VERSION 5.8 ;
BUSBITCHARS "[]" ;
DIVIDERCHAR "/" ;
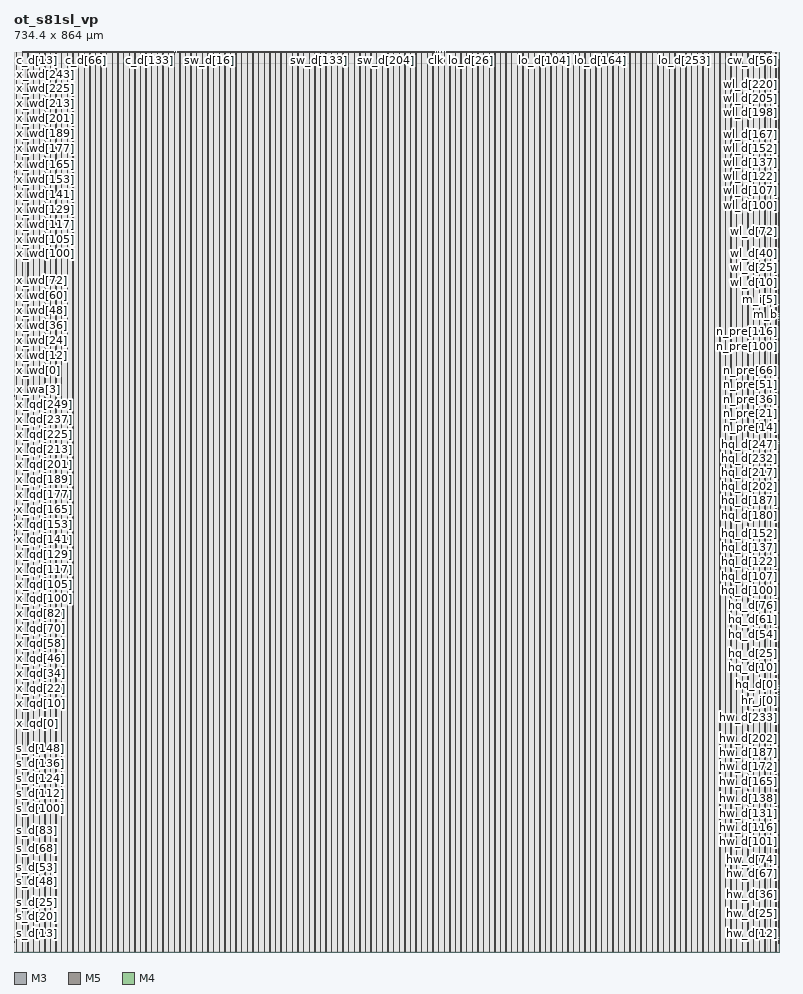
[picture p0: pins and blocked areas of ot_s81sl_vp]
MACRO ot_s81sl_vp
  CLASS BLOCK ;
  ORIGIN 0 0 ;
  FOREIGN ot_s81sl_vp 0 0 ;
  SIZE 734.4 BY 864.0 ;
  SYMMETRY X Y ;
  PIN c_v
    DIRECTION INPUT ;
    USE SIGNAL ;
    PORT
      LAYER M3 ;
        RECT 7.773 863.808 7.797 864.000 ;
    END
  END c_v
  PIN c_d[0]
    DIRECTION INPUT ;
    USE SIGNAL ;
    PORT
      LAYER M5 ;
        RECT 9.552 863.808 9.576 864.000 ;
    END
  END c_d[0]
  PIN c_d[1]
    DIRECTION INPUT ;
    USE SIGNAL ;
    PORT
      LAYER M3 ;
        RECT 10.473 863.808 10.497 864.000 ;
    END
  END c_d[1]
  PIN c_d[2]
    DIRECTION INPUT ;
    USE SIGNAL ;
    PORT
      LAYER M5 ;
        RECT 11.376 863.808 11.400 864.000 ;
    END
  END c_d[2]
  PIN c_d[3]
    DIRECTION INPUT ;
    USE SIGNAL ;
    PORT
      LAYER M3 ;
        RECT 12.273 863.808 12.297 864.000 ;
    END
  END c_d[3]
  PIN c_d[4]
    DIRECTION INPUT ;
    USE SIGNAL ;
    PORT
      LAYER M5 ;
        RECT 13.152 863.808 13.176 864.000 ;
    END
  END c_d[4]
  PIN c_d[5]
    DIRECTION INPUT ;
    USE SIGNAL ;
    PORT
      LAYER M3 ;
        RECT 14.073 863.808 14.097 864.000 ;
    END
  END c_d[5]
  PIN c_d[6]
    DIRECTION INPUT ;
    USE SIGNAL ;
    PORT
      LAYER M5 ;
        RECT 14.976 863.808 15.000 864.000 ;
    END
  END c_d[6]
  PIN c_d[7]
    DIRECTION INPUT ;
    USE SIGNAL ;
    PORT
      LAYER M3 ;
        RECT 15.873 863.808 15.897 864.000 ;
    END
  END c_d[7]
  PIN c_d[8]
    DIRECTION INPUT ;
    USE SIGNAL ;
    PORT
      LAYER M5 ;
        RECT 16.800 863.808 16.824 864.000 ;
    END
  END c_d[8]
  PIN c_d[9]
    DIRECTION INPUT ;
    USE SIGNAL ;
    PORT
      LAYER M3 ;
        RECT 17.673 863.808 17.697 864.000 ;
    END
  END c_d[9]
  PIN c_d[10]
    DIRECTION INPUT ;
    USE SIGNAL ;
    PORT
      LAYER M5 ;
        RECT 18.576 863.808 18.600 864.000 ;
    END
  END c_d[10]
  PIN c_d[11]
    DIRECTION INPUT ;
    USE SIGNAL ;
    PORT
      LAYER M3 ;
        RECT 19.509 863.808 19.533 864.000 ;
    END
  END c_d[11]
  PIN c_d[12]
    DIRECTION INPUT ;
    USE SIGNAL ;
    PORT
      LAYER M5 ;
        RECT 20.400 863.808 20.424 864.000 ;
    END
  END c_d[12]
  PIN c_d[13]
    DIRECTION INPUT ;
    USE SIGNAL ;
    PORT
      LAYER M3 ;
        RECT 21.309 863.808 21.333 864.000 ;
    END
  END c_d[13]
  PIN c_d[14]
    DIRECTION INPUT ;
    USE SIGNAL ;
    PORT
      LAYER M5 ;
        RECT 22.224 863.808 22.248 864.000 ;
    END
  END c_d[14]
  PIN c_d[15]
    DIRECTION INPUT ;
    USE SIGNAL ;
    PORT
      LAYER M3 ;
        RECT 23.109 863.808 23.133 864.000 ;
    END
  END c_d[15]
  PIN c_d[16]
    DIRECTION INPUT ;
    USE SIGNAL ;
    PORT
      LAYER M5 ;
        RECT 24.000 863.808 24.024 864.000 ;
    END
  END c_d[16]
  PIN c_d[17]
    DIRECTION INPUT ;
    USE SIGNAL ;
    PORT
      LAYER M3 ;
        RECT 24.909 863.808 24.933 864.000 ;
    END
  END c_d[17]
  PIN c_d[18]
    DIRECTION INPUT ;
    USE SIGNAL ;
    PORT
      LAYER M5 ;
        RECT 25.824 863.808 25.848 864.000 ;
    END
  END c_d[18]
  PIN c_d[19]
    DIRECTION INPUT ;
    USE SIGNAL ;
    PORT
      LAYER M3 ;
        RECT 26.709 863.808 26.733 864.000 ;
    END
  END c_d[19]
  PIN c_d[20]
    DIRECTION INPUT ;
    USE SIGNAL ;
    PORT
      LAYER M5 ;
        RECT 27.648 863.808 27.672 864.000 ;
    END
  END c_d[20]
  PIN c_d[21]
    DIRECTION INPUT ;
    USE SIGNAL ;
    PORT
      LAYER M3 ;
        RECT 28.545 863.808 28.569 864.000 ;
    END
  END c_d[21]
  PIN c_d[22]
    DIRECTION INPUT ;
    USE SIGNAL ;
    PORT
      LAYER M5 ;
        RECT 29.424 863.808 29.448 864.000 ;
    END
  END c_d[22]
  PIN c_d[23]
    DIRECTION INPUT ;
    USE SIGNAL ;
    PORT
      LAYER M3 ;
        RECT 30.345 863.808 30.369 864.000 ;
    END
  END c_d[23]
  PIN c_d[24]
    DIRECTION INPUT ;
    USE SIGNAL ;
    PORT
      LAYER M5 ;
        RECT 31.248 863.808 31.272 864.000 ;
    END
  END c_d[24]
  PIN c_d[25]
    DIRECTION INPUT ;
    USE SIGNAL ;
    PORT
      LAYER M3 ;
        RECT 32.145 863.808 32.169 864.000 ;
    END
  END c_d[25]
  PIN c_d[26]
    DIRECTION INPUT ;
    USE SIGNAL ;
    PORT
      LAYER M5 ;
        RECT 33.024 863.808 33.048 864.000 ;
    END
  END c_d[26]
  PIN c_d[27]
    DIRECTION INPUT ;
    USE SIGNAL ;
    PORT
      LAYER M3 ;
        RECT 33.945 863.808 33.969 864.000 ;
    END
  END c_d[27]
  PIN c_d[28]
    DIRECTION INPUT ;
    USE SIGNAL ;
    PORT
      LAYER M5 ;
        RECT 34.848 863.808 34.872 864.000 ;
    END
  END c_d[28]
  PIN c_d[29]
    DIRECTION INPUT ;
    USE SIGNAL ;
    PORT
      LAYER M3 ;
        RECT 35.745 863.808 35.769 864.000 ;
    END
  END c_d[29]
  PIN c_d[30]
    DIRECTION INPUT ;
    USE SIGNAL ;
    PORT
      LAYER M5 ;
        RECT 36.672 863.808 36.696 864.000 ;
    END
  END c_d[30]
  PIN c_d[31]
    DIRECTION INPUT ;
    USE SIGNAL ;
    PORT
      LAYER M3 ;
        RECT 37.581 863.808 37.605 864.000 ;
    END
  END c_d[31]
  PIN c_d[32]
    DIRECTION INPUT ;
    USE SIGNAL ;
    PORT
      LAYER M5 ;
        RECT 38.448 863.808 38.472 864.000 ;
    END
  END c_d[32]
  PIN c_d[33]
    DIRECTION INPUT ;
    USE SIGNAL ;
    PORT
      LAYER M3 ;
        RECT 39.381 863.808 39.405 864.000 ;
    END
  END c_d[33]
  PIN c_d[34]
    DIRECTION INPUT ;
    USE SIGNAL ;
    PORT
      LAYER M5 ;
        RECT 40.272 863.808 40.296 864.000 ;
    END
  END c_d[34]
  PIN c_d[35]
    DIRECTION INPUT ;
    USE SIGNAL ;
    PORT
      LAYER M3 ;
        RECT 41.181 863.808 41.205 864.000 ;
    END
  END c_d[35]
  PIN c_d[36]
    DIRECTION INPUT ;
    USE SIGNAL ;
    PORT
      LAYER M5 ;
        RECT 42.096 863.808 42.120 864.000 ;
    END
  END c_d[36]
  PIN c_d[37]
    DIRECTION INPUT ;
    USE SIGNAL ;
    PORT
      LAYER M3 ;
        RECT 42.981 863.808 43.005 864.000 ;
    END
  END c_d[37]
  PIN c_d[38]
    DIRECTION INPUT ;
    USE SIGNAL ;
    PORT
      LAYER M5 ;
        RECT 43.872 863.808 43.896 864.000 ;
    END
  END c_d[38]
  PIN c_d[39]
    DIRECTION INPUT ;
    USE SIGNAL ;
    PORT
      LAYER M3 ;
        RECT 44.781 863.808 44.805 864.000 ;
    END
  END c_d[39]
  PIN c_d[40]
    DIRECTION INPUT ;
    USE SIGNAL ;
    PORT
      LAYER M5 ;
        RECT 45.696 863.808 45.720 864.000 ;
    END
  END c_d[40]
  PIN c_d[41]
    DIRECTION INPUT ;
    USE SIGNAL ;
    PORT
      LAYER M3 ;
        RECT 46.617 863.808 46.641 864.000 ;
    END
  END c_d[41]
  PIN c_d[42]
    DIRECTION INPUT ;
    USE SIGNAL ;
    PORT
      LAYER M5 ;
        RECT 47.520 863.808 47.544 864.000 ;
    END
  END c_d[42]
  PIN c_d[43]
    DIRECTION INPUT ;
    USE SIGNAL ;
    PORT
      LAYER M3 ;
        RECT 48.417 863.808 48.441 864.000 ;
    END
  END c_d[43]
  PIN c_d[44]
    DIRECTION INPUT ;
    USE SIGNAL ;
    PORT
      LAYER M5 ;
        RECT 49.296 863.808 49.320 864.000 ;
    END
  END c_d[44]
  PIN c_d[45]
    DIRECTION INPUT ;
    USE SIGNAL ;
    PORT
      LAYER M3 ;
        RECT 50.217 863.808 50.241 864.000 ;
    END
  END c_d[45]
  PIN c_d[46]
    DIRECTION INPUT ;
    USE SIGNAL ;
    PORT
      LAYER M5 ;
        RECT 51.120 863.808 51.144 864.000 ;
    END
  END c_d[46]
  PIN c_d[47]
    DIRECTION INPUT ;
    USE SIGNAL ;
    PORT
      LAYER M3 ;
        RECT 52.017 863.808 52.041 864.000 ;
    END
  END c_d[47]
  PIN c_d[48]
    DIRECTION INPUT ;
    USE SIGNAL ;
    PORT
      LAYER M5 ;
        RECT 52.944 863.808 52.968 864.000 ;
    END
  END c_d[48]
  PIN c_d[49]
    DIRECTION INPUT ;
    USE SIGNAL ;
    PORT
      LAYER M3 ;
        RECT 53.817 863.808 53.841 864.000 ;
    END
  END c_d[49]
  PIN c_d[50]
    DIRECTION INPUT ;
    USE SIGNAL ;
    PORT
      LAYER M5 ;
        RECT 54.720 863.808 54.744 864.000 ;
    END
  END c_d[50]
  PIN c_d[51]
    DIRECTION INPUT ;
    USE SIGNAL ;
    PORT
      LAYER M3 ;
        RECT 55.653 863.808 55.677 864.000 ;
    END
  END c_d[51]
  PIN c_d[52]
    DIRECTION INPUT ;
    USE SIGNAL ;
    PORT
      LAYER M5 ;
        RECT 56.544 863.808 56.568 864.000 ;
    END
  END c_d[52]
  PIN c_d[53]
    DIRECTION INPUT ;
    USE SIGNAL ;
    PORT
      LAYER M3 ;
        RECT 57.453 863.808 57.477 864.000 ;
    END
  END c_d[53]
  PIN c_d[54]
    DIRECTION INPUT ;
    USE SIGNAL ;
    PORT
      LAYER M5 ;
        RECT 58.368 863.808 58.392 864.000 ;
    END
  END c_d[54]
  PIN c_d[55]
    DIRECTION INPUT ;
    USE SIGNAL ;
    PORT
      LAYER M3 ;
        RECT 59.253 863.808 59.277 864.000 ;
    END
  END c_d[55]
  PIN c_d[56]
    DIRECTION INPUT ;
    USE SIGNAL ;
    PORT
      LAYER M5 ;
        RECT 60.144 863.808 60.168 864.000 ;
    END
  END c_d[56]
  PIN c_d[57]
    DIRECTION INPUT ;
    USE SIGNAL ;
    PORT
      LAYER M3 ;
        RECT 61.053 863.808 61.077 864.000 ;
    END
  END c_d[57]
  PIN c_d[58]
    DIRECTION INPUT ;
    USE SIGNAL ;
    PORT
      LAYER M5 ;
        RECT 61.968 863.808 61.992 864.000 ;
    END
  END c_d[58]
  PIN c_d[59]
    DIRECTION INPUT ;
    USE SIGNAL ;
    PORT
      LAYER M3 ;
        RECT 62.853 863.808 62.877 864.000 ;
    END
  END c_d[59]
  PIN c_d[60]
    DIRECTION INPUT ;
    USE SIGNAL ;
    PORT
      LAYER M5 ;
        RECT 63.792 863.808 63.816 864.000 ;
    END
  END c_d[60]
  PIN c_d[61]
    DIRECTION INPUT ;
    USE SIGNAL ;
    PORT
      LAYER M3 ;
        RECT 64.689 863.808 64.713 864.000 ;
    END
  END c_d[61]
  PIN c_d[62]
    DIRECTION INPUT ;
    USE SIGNAL ;
    PORT
      LAYER M5 ;
        RECT 65.568 863.808 65.592 864.000 ;
    END
  END c_d[62]
  PIN c_d[63]
    DIRECTION INPUT ;
    USE SIGNAL ;
    PORT
      LAYER M3 ;
        RECT 66.489 863.808 66.513 864.000 ;
    END
  END c_d[63]
  PIN c_d[64]
    DIRECTION INPUT ;
    USE SIGNAL ;
    PORT
      LAYER M5 ;
        RECT 67.392 863.808 67.416 864.000 ;
    END
  END c_d[64]
  PIN c_d[65]
    DIRECTION INPUT ;
    USE SIGNAL ;
    PORT
      LAYER M3 ;
        RECT 68.289 863.808 68.313 864.000 ;
    END
  END c_d[65]
  PIN c_d[66]
    DIRECTION INPUT ;
    USE SIGNAL ;
    PORT
      LAYER M5 ;
        RECT 69.168 863.808 69.192 864.000 ;
    END
  END c_d[66]
  PIN c_d[67]
    DIRECTION INPUT ;
    USE SIGNAL ;
    PORT
      LAYER M3 ;
        RECT 70.089 863.808 70.113 864.000 ;
    END
  END c_d[67]
  PIN c_d[68]
    DIRECTION INPUT ;
    USE SIGNAL ;
    PORT
      LAYER M5 ;
        RECT 70.992 863.808 71.016 864.000 ;
    END
  END c_d[68]
  PIN c_d[69]
    DIRECTION INPUT ;
    USE SIGNAL ;
    PORT
      LAYER M3 ;
        RECT 71.889 863.808 71.913 864.000 ;
    END
  END c_d[69]
  PIN c_d[70]
    DIRECTION INPUT ;
    USE SIGNAL ;
    PORT
      LAYER M5 ;
        RECT 72.816 863.808 72.840 864.000 ;
    END
  END c_d[70]
  PIN c_d[71]
    DIRECTION INPUT ;
    USE SIGNAL ;
    PORT
      LAYER M3 ;
        RECT 73.725 863.808 73.749 864.000 ;
    END
  END c_d[71]
  PIN c_d[72]
    DIRECTION INPUT ;
    USE SIGNAL ;
    PORT
      LAYER M5 ;
        RECT 74.592 863.808 74.616 864.000 ;
    END
  END c_d[72]
  PIN c_d[73]
    DIRECTION INPUT ;
    USE SIGNAL ;
    PORT
      LAYER M3 ;
        RECT 75.525 863.808 75.549 864.000 ;
    END
  END c_d[73]
  PIN c_d[74]
    DIRECTION INPUT ;
    USE SIGNAL ;
    PORT
      LAYER M5 ;
        RECT 76.416 863.808 76.440 864.000 ;
    END
  END c_d[74]
  PIN c_d[75]
    DIRECTION INPUT ;
    USE SIGNAL ;
    PORT
      LAYER M3 ;
        RECT 77.325 863.808 77.349 864.000 ;
    END
  END c_d[75]
  PIN c_d[76]
    DIRECTION INPUT ;
    USE SIGNAL ;
    PORT
      LAYER M5 ;
        RECT 78.240 863.808 78.264 864.000 ;
    END
  END c_d[76]
  PIN c_d[77]
    DIRECTION INPUT ;
    USE SIGNAL ;
    PORT
      LAYER M3 ;
        RECT 79.125 863.808 79.149 864.000 ;
    END
  END c_d[77]
  PIN c_d[78]
    DIRECTION INPUT ;
    USE SIGNAL ;
    PORT
      LAYER M5 ;
        RECT 80.016 863.808 80.040 864.000 ;
    END
  END c_d[78]
  PIN c_d[79]
    DIRECTION INPUT ;
    USE SIGNAL ;
    PORT
      LAYER M3 ;
        RECT 80.925 863.808 80.949 864.000 ;
    END
  END c_d[79]
  PIN c_d[80]
    DIRECTION INPUT ;
    USE SIGNAL ;
    PORT
      LAYER M5 ;
        RECT 81.840 863.808 81.864 864.000 ;
    END
  END c_d[80]
  PIN c_d[81]
    DIRECTION INPUT ;
    USE SIGNAL ;
    PORT
      LAYER M3 ;
        RECT 82.761 863.808 82.785 864.000 ;
    END
  END c_d[81]
  PIN c_d[82]
    DIRECTION INPUT ;
    USE SIGNAL ;
    PORT
      LAYER M5 ;
        RECT 83.664 863.808 83.688 864.000 ;
    END
  END c_d[82]
  PIN c_d[83]
    DIRECTION INPUT ;
    USE SIGNAL ;
    PORT
      LAYER M3 ;
        RECT 84.561 863.808 84.585 864.000 ;
    END
  END c_d[83]
  PIN c_d[84]
    DIRECTION INPUT ;
    USE SIGNAL ;
    PORT
      LAYER M5 ;
        RECT 85.440 863.808 85.464 864.000 ;
    END
  END c_d[84]
  PIN c_d[85]
    DIRECTION INPUT ;
    USE SIGNAL ;
    PORT
      LAYER M3 ;
        RECT 86.361 863.808 86.385 864.000 ;
    END
  END c_d[85]
  PIN c_d[86]
    DIRECTION INPUT ;
    USE SIGNAL ;
    PORT
      LAYER M5 ;
        RECT 87.264 863.808 87.288 864.000 ;
    END
  END c_d[86]
  PIN c_d[87]
    DIRECTION INPUT ;
    USE SIGNAL ;
    PORT
      LAYER M3 ;
        RECT 88.161 863.808 88.185 864.000 ;
    END
  END c_d[87]
  PIN c_d[88]
    DIRECTION INPUT ;
    USE SIGNAL ;
    PORT
      LAYER M5 ;
        RECT 89.088 863.808 89.112 864.000 ;
    END
  END c_d[88]
  PIN c_d[89]
    DIRECTION INPUT ;
    USE SIGNAL ;
    PORT
      LAYER M3 ;
        RECT 89.961 863.808 89.985 864.000 ;
    END
  END c_d[89]
  PIN c_d[90]
    DIRECTION INPUT ;
    USE SIGNAL ;
    PORT
      LAYER M5 ;
        RECT 90.864 863.808 90.888 864.000 ;
    END
  END c_d[90]
  PIN c_d[91]
    DIRECTION INPUT ;
    USE SIGNAL ;
    PORT
      LAYER M3 ;
        RECT 91.797 863.808 91.821 864.000 ;
    END
  END c_d[91]
  PIN c_d[92]
    DIRECTION INPUT ;
    USE SIGNAL ;
    PORT
      LAYER M5 ;
        RECT 92.688 863.808 92.712 864.000 ;
    END
  END c_d[92]
  PIN c_d[93]
    DIRECTION INPUT ;
    USE SIGNAL ;
    PORT
      LAYER M3 ;
        RECT 93.597 863.808 93.621 864.000 ;
    END
  END c_d[93]
  PIN c_d[94]
    DIRECTION INPUT ;
    USE SIGNAL ;
    PORT
      LAYER M5 ;
        RECT 94.512 863.808 94.536 864.000 ;
    END
  END c_d[94]
  PIN c_d[95]
    DIRECTION INPUT ;
    USE SIGNAL ;
    PORT
      LAYER M3 ;
        RECT 95.397 863.808 95.421 864.000 ;
    END
  END c_d[95]
  PIN c_d[96]
    DIRECTION INPUT ;
    USE SIGNAL ;
    PORT
      LAYER M5 ;
        RECT 96.288 863.808 96.312 864.000 ;
    END
  END c_d[96]
  PIN c_d[97]
    DIRECTION INPUT ;
    USE SIGNAL ;
    PORT
      LAYER M3 ;
        RECT 97.197 863.808 97.221 864.000 ;
    END
  END c_d[97]
  PIN c_d[98]
    DIRECTION INPUT ;
    USE SIGNAL ;
    PORT
      LAYER M5 ;
        RECT 98.112 863.808 98.136 864.000 ;
    END
  END c_d[98]
  PIN c_d[99]
    DIRECTION INPUT ;
    USE SIGNAL ;
    PORT
      LAYER M3 ;
        RECT 98.997 863.808 99.021 864.000 ;
    END
  END c_d[99]
  PIN c_d[100]
    DIRECTION INPUT ;
    USE SIGNAL ;
    PORT
      LAYER M5 ;
        RECT 99.936 863.808 99.960 864.000 ;
    END
  END c_d[100]
  PIN c_d[101]
    DIRECTION INPUT ;
    USE SIGNAL ;
    PORT
      LAYER M3 ;
        RECT 100.833 863.808 100.857 864.000 ;
    END
  END c_d[101]
  PIN c_d[102]
    DIRECTION INPUT ;
    USE SIGNAL ;
    PORT
      LAYER M5 ;
        RECT 101.712 863.808 101.736 864.000 ;
    END
  END c_d[102]
  PIN c_d[103]
    DIRECTION INPUT ;
    USE SIGNAL ;
    PORT
      LAYER M3 ;
        RECT 102.633 863.808 102.657 864.000 ;
    END
  END c_d[103]
  PIN c_d[104]
    DIRECTION INPUT ;
    USE SIGNAL ;
    PORT
      LAYER M5 ;
        RECT 103.536 863.808 103.560 864.000 ;
    END
  END c_d[104]
  PIN c_d[105]
    DIRECTION INPUT ;
    USE SIGNAL ;
    PORT
      LAYER M3 ;
        RECT 104.433 863.808 104.457 864.000 ;
    END
  END c_d[105]
  PIN c_d[106]
    DIRECTION INPUT ;
    USE SIGNAL ;
    PORT
      LAYER M5 ;
        RECT 105.312 863.808 105.336 864.000 ;
    END
  END c_d[106]
  PIN c_d[107]
    DIRECTION INPUT ;
    USE SIGNAL ;
    PORT
      LAYER M3 ;
        RECT 106.233 863.808 106.257 864.000 ;
    END
  END c_d[107]
  PIN c_d[108]
    DIRECTION INPUT ;
    USE SIGNAL ;
    PORT
      LAYER M5 ;
        RECT 107.136 863.808 107.160 864.000 ;
    END
  END c_d[108]
  PIN c_d[109]
    DIRECTION INPUT ;
    USE SIGNAL ;
    PORT
      LAYER M3 ;
        RECT 108.033 863.808 108.057 864.000 ;
    END
  END c_d[109]
  PIN c_d[110]
    DIRECTION INPUT ;
    USE SIGNAL ;
    PORT
      LAYER M5 ;
        RECT 108.960 863.808 108.984 864.000 ;
    END
  END c_d[110]
  PIN c_d[111]
    DIRECTION INPUT ;
    USE SIGNAL ;
    PORT
      LAYER M3 ;
        RECT 109.869 863.808 109.893 864.000 ;
    END
  END c_d[111]
  PIN c_d[112]
    DIRECTION INPUT ;
    USE SIGNAL ;
    PORT
      LAYER M5 ;
        RECT 110.736 863.808 110.760 864.000 ;
    END
  END c_d[112]
  PIN c_d[113]
    DIRECTION INPUT ;
    USE SIGNAL ;
    PORT
      LAYER M3 ;
        RECT 111.669 863.808 111.693 864.000 ;
    END
  END c_d[113]
  PIN c_d[114]
    DIRECTION INPUT ;
    USE SIGNAL ;
    PORT
      LAYER M5 ;
        RECT 112.560 863.808 112.584 864.000 ;
    END
  END c_d[114]
  PIN c_d[115]
    DIRECTION INPUT ;
    USE SIGNAL ;
    PORT
      LAYER M3 ;
        RECT 113.469 863.808 113.493 864.000 ;
    END
  END c_d[115]
  PIN c_d[116]
    DIRECTION INPUT ;
    USE SIGNAL ;
    PORT
      LAYER M5 ;
        RECT 114.384 863.808 114.408 864.000 ;
    END
  END c_d[116]
  PIN c_d[117]
    DIRECTION INPUT ;
    USE SIGNAL ;
    PORT
      LAYER M3 ;
        RECT 115.269 863.808 115.293 864.000 ;
    END
  END c_d[117]
  PIN c_d[118]
    DIRECTION INPUT ;
    USE SIGNAL ;
    PORT
      LAYER M5 ;
        RECT 116.160 863.808 116.184 864.000 ;
    END
  END c_d[118]
  PIN c_d[119]
    DIRECTION INPUT ;
    USE SIGNAL ;
    PORT
      LAYER M3 ;
        RECT 117.069 863.808 117.093 864.000 ;
    END
  END c_d[119]
  PIN c_d[120]
    DIRECTION INPUT ;
    USE SIGNAL ;
    PORT
      LAYER M5 ;
        RECT 117.984 863.808 118.008 864.000 ;
    END
  END c_d[120]
  PIN c_d[121]
    DIRECTION INPUT ;
    USE SIGNAL ;
    PORT
      LAYER M3 ;
        RECT 118.905 863.808 118.929 864.000 ;
    END
  END c_d[121]
  PIN c_d[122]
    DIRECTION INPUT ;
    USE SIGNAL ;
    PORT
      LAYER M5 ;
        RECT 119.808 863.808 119.832 864.000 ;
    END
  END c_d[122]
  PIN c_d[123]
    DIRECTION INPUT ;
    USE SIGNAL ;
    PORT
      LAYER M3 ;
        RECT 120.705 863.808 120.729 864.000 ;
    END
  END c_d[123]
  PIN c_d[124]
    DIRECTION INPUT ;
    USE SIGNAL ;
    PORT
      LAYER M5 ;
        RECT 121.584 863.808 121.608 864.000 ;
    END
  END c_d[124]
  PIN c_d[125]
    DIRECTION INPUT ;
    USE SIGNAL ;
    PORT
      LAYER M3 ;
        RECT 122.505 863.808 122.529 864.000 ;
    END
  END c_d[125]
  PIN c_d[126]
    DIRECTION INPUT ;
    USE SIGNAL ;
    PORT
      LAYER M5 ;
        RECT 123.408 863.808 123.432 864.000 ;
    END
  END c_d[126]
  PIN c_d[127]
    DIRECTION INPUT ;
    USE SIGNAL ;
    PORT
      LAYER M3 ;
        RECT 124.305 863.808 124.329 864.000 ;
    END
  END c_d[127]
  PIN c_d[128]
    DIRECTION INPUT ;
    USE SIGNAL ;
    PORT
      LAYER M5 ;
        RECT 125.232 863.808 125.256 864.000 ;
    END
  END c_d[128]
  PIN c_d[129]
    DIRECTION INPUT ;
    USE SIGNAL ;
    PORT
      LAYER M3 ;
        RECT 126.105 863.808 126.129 864.000 ;
    END
  END c_d[129]
  PIN c_d[130]
    DIRECTION INPUT ;
    USE SIGNAL ;
    PORT
      LAYER M5 ;
        RECT 127.008 863.808 127.032 864.000 ;
    END
  END c_d[130]
  PIN c_d[131]
    DIRECTION INPUT ;
    USE SIGNAL ;
    PORT
      LAYER M3 ;
        RECT 127.941 863.808 127.965 864.000 ;
    END
  END c_d[131]
  PIN c_d[132]
    DIRECTION INPUT ;
    USE SIGNAL ;
    PORT
      LAYER M5 ;
        RECT 128.832 863.808 128.856 864.000 ;
    END
  END c_d[132]
  PIN c_d[133]
    DIRECTION INPUT ;
    USE SIGNAL ;
    PORT
      LAYER M3 ;
        RECT 129.741 863.808 129.765 864.000 ;
    END
  END c_d[133]
  PIN c_d[134]
    DIRECTION INPUT ;
    USE SIGNAL ;
    PORT
      LAYER M5 ;
        RECT 130.656 863.808 130.680 864.000 ;
    END
  END c_d[134]
  PIN c_d[135]
    DIRECTION INPUT ;
    USE SIGNAL ;
    PORT
      LAYER M3 ;
        RECT 131.541 863.808 131.565 864.000 ;
    END
  END c_d[135]
  PIN c_d[136]
    DIRECTION INPUT ;
    USE SIGNAL ;
    PORT
      LAYER M5 ;
        RECT 132.432 863.808 132.456 864.000 ;
    END
  END c_d[136]
  PIN c_d[137]
    DIRECTION INPUT ;
    USE SIGNAL ;
    PORT
      LAYER M3 ;
        RECT 133.341 863.808 133.365 864.000 ;
    END
  END c_d[137]
  PIN c_d[138]
    DIRECTION INPUT ;
    USE SIGNAL ;
    PORT
      LAYER M5 ;
        RECT 134.256 863.808 134.280 864.000 ;
    END
  END c_d[138]
  PIN c_d[139]
    DIRECTION INPUT ;
    USE SIGNAL ;
    PORT
      LAYER M3 ;
        RECT 135.141 863.808 135.165 864.000 ;
    END
  END c_d[139]
  PIN c_d[140]
    DIRECTION INPUT ;
    USE SIGNAL ;
    PORT
      LAYER M5 ;
        RECT 136.080 863.808 136.104 864.000 ;
    END
  END c_d[140]
  PIN c_d[141]
    DIRECTION INPUT ;
    USE SIGNAL ;
    PORT
      LAYER M3 ;
        RECT 136.977 863.808 137.001 864.000 ;
    END
  END c_d[141]
  PIN c_d[142]
    DIRECTION INPUT ;
    USE SIGNAL ;
    PORT
      LAYER M5 ;
        RECT 137.856 863.808 137.880 864.000 ;
    END
  END c_d[142]
  PIN c_d[143]
    DIRECTION INPUT ;
    USE SIGNAL ;
    PORT
      LAYER M3 ;
        RECT 138.777 863.808 138.801 864.000 ;
    END
  END c_d[143]
  PIN c_d[144]
    DIRECTION INPUT ;
    USE SIGNAL ;
    PORT
      LAYER M5 ;
        RECT 139.680 863.808 139.704 864.000 ;
    END
  END c_d[144]
  PIN c_d[145]
    DIRECTION INPUT ;
    USE SIGNAL ;
    PORT
      LAYER M3 ;
        RECT 140.577 863.808 140.601 864.000 ;
    END
  END c_d[145]
  PIN c_d[146]
    DIRECTION INPUT ;
    USE SIGNAL ;
    PORT
      LAYER M5 ;
        RECT 141.504 863.808 141.528 864.000 ;
    END
  END c_d[146]
  PIN c_d[147]
    DIRECTION INPUT ;
    USE SIGNAL ;
    PORT
      LAYER M3 ;
        RECT 142.377 863.808 142.401 864.000 ;
    END
  END c_d[147]
  PIN c_d[148]
    DIRECTION INPUT ;
    USE SIGNAL ;
    PORT
      LAYER M5 ;
        RECT 143.280 863.808 143.304 864.000 ;
    END
  END c_d[148]
  PIN c_d[149]
    DIRECTION INPUT ;
    USE SIGNAL ;
    PORT
      LAYER M3 ;
        RECT 144.177 863.808 144.201 864.000 ;
    END
  END c_d[149]
  PIN c_d[150]
    DIRECTION INPUT ;
    USE SIGNAL ;
    PORT
      LAYER M5 ;
        RECT 145.104 863.808 145.128 864.000 ;
    END
  END c_d[150]
  PIN c_d[151]
    DIRECTION INPUT ;
    USE SIGNAL ;
    PORT
      LAYER M3 ;
        RECT 146.013 863.808 146.037 864.000 ;
    END
  END c_d[151]
  PIN c_d[152]
    DIRECTION INPUT ;
    USE SIGNAL ;
    PORT
      LAYER M5 ;
        RECT 146.880 863.808 146.904 864.000 ;
    END
  END c_d[152]
  PIN c_d[153]
    DIRECTION INPUT ;
    USE SIGNAL ;
    PORT
      LAYER M3 ;
        RECT 147.813 863.808 147.837 864.000 ;
    END
  END c_d[153]
  PIN c_d[154]
    DIRECTION INPUT ;
    USE SIGNAL ;
    PORT
      LAYER M5 ;
        RECT 148.704 863.808 148.728 864.000 ;
    END
  END c_d[154]
  PIN c_d[155]
    DIRECTION INPUT ;
    USE SIGNAL ;
    PORT
      LAYER M3 ;
        RECT 149.613 863.808 149.637 864.000 ;
    END
  END c_d[155]
  PIN c_d[156]
    DIRECTION INPUT ;
    USE SIGNAL ;
    PORT
      LAYER M5 ;
        RECT 150.528 863.808 150.552 864.000 ;
    END
  END c_d[156]
  PIN c_d[157]
    DIRECTION INPUT ;
    USE SIGNAL ;
    PORT
      LAYER M3 ;
        RECT 151.413 863.808 151.437 864.000 ;
    END
  END c_d[157]
  PIN c_d[158]
    DIRECTION INPUT ;
    USE SIGNAL ;
    PORT
      LAYER M5 ;
        RECT 152.304 863.808 152.328 864.000 ;
    END
  END c_d[158]
  PIN c_d[159]
    DIRECTION INPUT ;
    USE SIGNAL ;
    PORT
      LAYER M3 ;
        RECT 153.213 863.808 153.237 864.000 ;
    END
  END c_d[159]
  PIN sw_v
    DIRECTION INPUT ;
    USE SIGNAL ;
    PORT
      LAYER M5 ;
        RECT 154.992 863.808 155.016 864.000 ;
    END
  END sw_v
  PIN sw_a[0]
    DIRECTION INPUT ;
    USE SIGNAL ;
    PORT
      LAYER M3 ;
        RECT 156.777 863.808 156.801 864.000 ;
    END
  END sw_a[0]
  PIN sw_a[1]
    DIRECTION INPUT ;
    USE SIGNAL ;
    PORT
      LAYER M5 ;
        RECT 157.680 863.808 157.704 864.000 ;
    END
  END sw_a[1]
  PIN sw_a[2]
    DIRECTION INPUT ;
    USE SIGNAL ;
    PORT
      LAYER M3 ;
        RECT 158.577 863.808 158.601 864.000 ;
    END
  END sw_a[2]
  PIN sw_a[3]
    DIRECTION INPUT ;
    USE SIGNAL ;
    PORT
      LAYER M5 ;
        RECT 159.456 863.808 159.480 864.000 ;
    END
  END sw_a[3]
  PIN sw_a[4]
    DIRECTION INPUT ;
    USE SIGNAL ;
    PORT
      LAYER M3 ;
        RECT 160.377 863.808 160.401 864.000 ;
    END
  END sw_a[4]
  PIN sw_a[5]
    DIRECTION INPUT ;
    USE SIGNAL ;
    PORT
      LAYER M5 ;
        RECT 161.280 863.808 161.304 864.000 ;
    END
  END sw_a[5]
  PIN sw_a[6]
    DIRECTION INPUT ;
    USE SIGNAL ;
    PORT
      LAYER M3 ;
        RECT 162.177 863.808 162.201 864.000 ;
    END
  END sw_a[6]
  PIN sw_a[7]
    DIRECTION INPUT ;
    USE SIGNAL ;
    PORT
      LAYER M5 ;
        RECT 163.104 863.808 163.128 864.000 ;
    END
  END sw_a[7]
  PIN sw_a[8]
    DIRECTION INPUT ;
    USE SIGNAL ;
    PORT
      LAYER M3 ;
        RECT 163.977 863.808 164.001 864.000 ;
    END
  END sw_a[8]
  PIN sw_a[9]
    DIRECTION INPUT ;
    USE SIGNAL ;
    PORT
      LAYER M5 ;
        RECT 164.880 863.808 164.904 864.000 ;
    END
  END sw_a[9]
  PIN sw_m[0]
    DIRECTION INPUT ;
    USE SIGNAL ;
    PORT
      LAYER M3 ;
        RECT 165.813 863.808 165.837 864.000 ;
    END
  END sw_m[0]
  PIN sw_m[1]
    DIRECTION INPUT ;
    USE SIGNAL ;
    PORT
      LAYER M5 ;
        RECT 166.704 863.808 166.728 864.000 ;
    END
  END sw_m[1]
  PIN sw_m[2]
    DIRECTION INPUT ;
    USE SIGNAL ;
    PORT
      LAYER M3 ;
        RECT 167.613 863.808 167.637 864.000 ;
    END
  END sw_m[2]
  PIN sw_m[3]
    DIRECTION INPUT ;
    USE SIGNAL ;
    PORT
      LAYER M5 ;
        RECT 168.528 863.808 168.552 864.000 ;
    END
  END sw_m[3]
  PIN sw_m[4]
    DIRECTION INPUT ;
    USE SIGNAL ;
    PORT
      LAYER M3 ;
        RECT 169.413 863.808 169.437 864.000 ;
    END
  END sw_m[4]
  PIN sw_m[5]
    DIRECTION INPUT ;
    USE SIGNAL ;
    PORT
      LAYER M5 ;
        RECT 170.304 863.808 170.328 864.000 ;
    END
  END sw_m[5]
  PIN sw_m[6]
    DIRECTION INPUT ;
    USE SIGNAL ;
    PORT
      LAYER M3 ;
        RECT 171.213 863.808 171.237 864.000 ;
    END
  END sw_m[6]
  PIN sw_m[7]
    DIRECTION INPUT ;
    USE SIGNAL ;
    PORT
      LAYER M5 ;
        RECT 172.128 863.808 172.152 864.000 ;
    END
  END sw_m[7]
  PIN sw_d[0]
    DIRECTION INPUT ;
    USE SIGNAL ;
    PORT
      LAYER M3 ;
        RECT 173.013 863.808 173.037 864.000 ;
    END
  END sw_d[0]
  PIN sw_d[1]
    DIRECTION INPUT ;
    USE SIGNAL ;
    PORT
      LAYER M5 ;
        RECT 173.952 863.808 173.976 864.000 ;
    END
  END sw_d[1]
  PIN sw_d[2]
    DIRECTION INPUT ;
    USE SIGNAL ;
    PORT
      LAYER M3 ;
        RECT 174.849 863.808 174.873 864.000 ;
    END
  END sw_d[2]
  PIN sw_d[3]
    DIRECTION INPUT ;
    USE SIGNAL ;
    PORT
      LAYER M5 ;
        RECT 175.728 863.808 175.752 864.000 ;
    END
  END sw_d[3]
  PIN sw_d[4]
    DIRECTION INPUT ;
    USE SIGNAL ;
    PORT
      LAYER M3 ;
        RECT 176.649 863.808 176.673 864.000 ;
    END
  END sw_d[4]
  PIN sw_d[5]
    DIRECTION INPUT ;
    USE SIGNAL ;
    PORT
      LAYER M5 ;
        RECT 177.552 863.808 177.576 864.000 ;
    END
  END sw_d[5]
  PIN sw_d[6]
    DIRECTION INPUT ;
    USE SIGNAL ;
    PORT
      LAYER M3 ;
        RECT 178.449 863.808 178.473 864.000 ;
    END
  END sw_d[6]
  PIN sw_d[7]
    DIRECTION INPUT ;
    USE SIGNAL ;
    PORT
      LAYER M5 ;
        RECT 179.376 863.808 179.400 864.000 ;
    END
  END sw_d[7]
  PIN sw_d[8]
    DIRECTION INPUT ;
    USE SIGNAL ;
    PORT
      LAYER M3 ;
        RECT 180.249 863.808 180.273 864.000 ;
    END
  END sw_d[8]
  PIN sw_d[9]
    DIRECTION INPUT ;
    USE SIGNAL ;
    PORT
      LAYER M5 ;
        RECT 181.152 863.808 181.176 864.000 ;
    END
  END sw_d[9]
  PIN sw_d[10]
    DIRECTION INPUT ;
    USE SIGNAL ;
    PORT
      LAYER M3 ;
        RECT 182.049 863.808 182.073 864.000 ;
    END
  END sw_d[10]
  PIN sw_d[11]
    DIRECTION INPUT ;
    USE SIGNAL ;
    PORT
      LAYER M5 ;
        RECT 182.976 863.808 183.000 864.000 ;
    END
  END sw_d[11]
  PIN sw_d[12]
    DIRECTION INPUT ;
    USE SIGNAL ;
    PORT
      LAYER M3 ;
        RECT 183.885 863.808 183.909 864.000 ;
    END
  END sw_d[12]
  PIN sw_d[13]
    DIRECTION INPUT ;
    USE SIGNAL ;
    PORT
      LAYER M5 ;
        RECT 184.752 863.808 184.776 864.000 ;
    END
  END sw_d[13]
  PIN sw_d[14]
    DIRECTION INPUT ;
    USE SIGNAL ;
    PORT
      LAYER M3 ;
        RECT 185.685 863.808 185.709 864.000 ;
    END
  END sw_d[14]
  PIN sw_d[15]
    DIRECTION INPUT ;
    USE SIGNAL ;
    PORT
      LAYER M5 ;
        RECT 186.576 863.808 186.600 864.000 ;
    END
  END sw_d[15]
  PIN sw_d[16]
    DIRECTION INPUT ;
    USE SIGNAL ;
    PORT
      LAYER M3 ;
        RECT 187.485 863.808 187.509 864.000 ;
    END
  END sw_d[16]
  PIN sw_d[17]
    DIRECTION INPUT ;
    USE SIGNAL ;
    PORT
      LAYER M5 ;
        RECT 188.400 863.808 188.424 864.000 ;
    END
  END sw_d[17]
  PIN sw_d[18]
    DIRECTION INPUT ;
    USE SIGNAL ;
    PORT
      LAYER M3 ;
        RECT 189.285 863.808 189.309 864.000 ;
    END
  END sw_d[18]
  PIN sw_d[19]
    DIRECTION INPUT ;
    USE SIGNAL ;
    PORT
      LAYER M5 ;
        RECT 190.176 863.808 190.200 864.000 ;
    END
  END sw_d[19]
  PIN sw_d[20]
    DIRECTION INPUT ;
    USE SIGNAL ;
    PORT
      LAYER M3 ;
        RECT 191.085 863.808 191.109 864.000 ;
    END
  END sw_d[20]
  PIN sw_d[21]
    DIRECTION INPUT ;
    USE SIGNAL ;
    PORT
      LAYER M5 ;
        RECT 192.000 863.808 192.024 864.000 ;
    END
  END sw_d[21]
  PIN sw_d[22]
    DIRECTION INPUT ;
    USE SIGNAL ;
    PORT
      LAYER M3 ;
        RECT 192.921 863.808 192.945 864.000 ;
    END
  END sw_d[22]
  PIN sw_d[23]
    DIRECTION INPUT ;
    USE SIGNAL ;
    PORT
      LAYER M5 ;
        RECT 193.824 863.808 193.848 864.000 ;
    END
  END sw_d[23]
  PIN sw_d[24]
    DIRECTION INPUT ;
    USE SIGNAL ;
    PORT
      LAYER M3 ;
        RECT 194.721 863.808 194.745 864.000 ;
    END
  END sw_d[24]
  PIN sw_d[25]
    DIRECTION INPUT ;
    USE SIGNAL ;
    PORT
      LAYER M5 ;
        RECT 195.600 863.808 195.624 864.000 ;
    END
  END sw_d[25]
  PIN sw_d[26]
    DIRECTION INPUT ;
    USE SIGNAL ;
    PORT
      LAYER M3 ;
        RECT 196.521 863.808 196.545 864.000 ;
    END
  END sw_d[26]
  PIN sw_d[27]
    DIRECTION INPUT ;
    USE SIGNAL ;
    PORT
      LAYER M5 ;
        RECT 197.424 863.808 197.448 864.000 ;
    END
  END sw_d[27]
  PIN sw_d[28]
    DIRECTION INPUT ;
    USE SIGNAL ;
    PORT
      LAYER M3 ;
        RECT 198.321 863.808 198.345 864.000 ;
    END
  END sw_d[28]
  PIN sw_d[29]
    DIRECTION INPUT ;
    USE SIGNAL ;
    PORT
      LAYER M5 ;
        RECT 199.248 863.808 199.272 864.000 ;
    END
  END sw_d[29]
  PIN sw_d[30]
    DIRECTION INPUT ;
    USE SIGNAL ;
    PORT
      LAYER M3 ;
        RECT 200.121 863.808 200.145 864.000 ;
    END
  END sw_d[30]
  PIN sw_d[31]
    DIRECTION INPUT ;
    USE SIGNAL ;
    PORT
      LAYER M5 ;
        RECT 201.024 863.808 201.048 864.000 ;
    END
  END sw_d[31]
  PIN sw_d[32]
    DIRECTION INPUT ;
    USE SIGNAL ;
    PORT
      LAYER M3 ;
        RECT 201.957 863.808 201.981 864.000 ;
    END
  END sw_d[32]
  PIN sw_d[33]
    DIRECTION INPUT ;
    USE SIGNAL ;
    PORT
      LAYER M5 ;
        RECT 202.848 863.808 202.872 864.000 ;
    END
  END sw_d[33]
  PIN sw_d[34]
    DIRECTION INPUT ;
    USE SIGNAL ;
    PORT
      LAYER M3 ;
        RECT 203.757 863.808 203.781 864.000 ;
    END
  END sw_d[34]
  PIN sw_d[35]
    DIRECTION INPUT ;
    USE SIGNAL ;
    PORT
      LAYER M5 ;
        RECT 204.672 863.808 204.696 864.000 ;
    END
  END sw_d[35]
  PIN sw_d[36]
    DIRECTION INPUT ;
    USE SIGNAL ;
    PORT
      LAYER M3 ;
        RECT 205.557 863.808 205.581 864.000 ;
    END
  END sw_d[36]
  PIN sw_d[37]
    DIRECTION INPUT ;
    USE SIGNAL ;
    PORT
      LAYER M5 ;
        RECT 206.448 863.808 206.472 864.000 ;
    END
  END sw_d[37]
  PIN sw_d[38]
    DIRECTION INPUT ;
    USE SIGNAL ;
    PORT
      LAYER M3 ;
        RECT 207.357 863.808 207.381 864.000 ;
    END
  END sw_d[38]
  PIN sw_d[39]
    DIRECTION INPUT ;
    USE SIGNAL ;
    PORT
      LAYER M5 ;
        RECT 208.272 863.808 208.296 864.000 ;
    END
  END sw_d[39]
  PIN sw_d[40]
    DIRECTION INPUT ;
    USE SIGNAL ;
    PORT
      LAYER M3 ;
        RECT 209.157 863.808 209.181 864.000 ;
    END
  END sw_d[40]
  PIN sw_d[41]
    DIRECTION INPUT ;
    USE SIGNAL ;
    PORT
      LAYER M5 ;
        RECT 210.096 863.808 210.120 864.000 ;
    END
  END sw_d[41]
  PIN sw_d[42]
    DIRECTION INPUT ;
    USE SIGNAL ;
    PORT
      LAYER M3 ;
        RECT 210.993 863.808 211.017 864.000 ;
    END
  END sw_d[42]
  PIN sw_d[43]
    DIRECTION INPUT ;
    USE SIGNAL ;
    PORT
      LAYER M5 ;
        RECT 211.872 863.808 211.896 864.000 ;
    END
  END sw_d[43]
  PIN sw_d[44]
    DIRECTION INPUT ;
    USE SIGNAL ;
    PORT
      LAYER M3 ;
        RECT 212.793 863.808 212.817 864.000 ;
    END
  END sw_d[44]
  PIN sw_d[45]
    DIRECTION INPUT ;
    USE SIGNAL ;
    PORT
      LAYER M5 ;
        RECT 213.696 863.808 213.720 864.000 ;
    END
  END sw_d[45]
  PIN sw_d[46]
    DIRECTION INPUT ;
    USE SIGNAL ;
    PORT
      LAYER M3 ;
        RECT 214.593 863.808 214.617 864.000 ;
    END
  END sw_d[46]
  PIN sw_d[47]
    DIRECTION INPUT ;
    USE SIGNAL ;
    PORT
      LAYER M5 ;
        RECT 215.520 863.808 215.544 864.000 ;
    END
  END sw_d[47]
  PIN sw_d[48]
    DIRECTION INPUT ;
    USE SIGNAL ;
    PORT
      LAYER M3 ;
        RECT 216.393 863.808 216.417 864.000 ;
    END
  END sw_d[48]
  PIN sw_d[49]
    DIRECTION INPUT ;
    USE SIGNAL ;
    PORT
      LAYER M5 ;
        RECT 217.296 863.808 217.320 864.000 ;
    END
  END sw_d[49]
  PIN sw_d[50]
    DIRECTION INPUT ;
    USE SIGNAL ;
    PORT
      LAYER M3 ;
        RECT 218.193 863.808 218.217 864.000 ;
    END
  END sw_d[50]
  PIN sw_d[51]
    DIRECTION INPUT ;
    USE SIGNAL ;
    PORT
      LAYER M5 ;
        RECT 219.120 863.808 219.144 864.000 ;
    END
  END sw_d[51]
  PIN sw_d[52]
    DIRECTION INPUT ;
    USE SIGNAL ;
    PORT
      LAYER M3 ;
        RECT 220.029 863.808 220.053 864.000 ;
    END
  END sw_d[52]
  PIN sw_d[53]
    DIRECTION INPUT ;
    USE SIGNAL ;
    PORT
      LAYER M5 ;
        RECT 220.944 863.808 220.968 864.000 ;
    END
  END sw_d[53]
  PIN sw_d[54]
    DIRECTION INPUT ;
    USE SIGNAL ;
    PORT
      LAYER M3 ;
        RECT 221.829 863.808 221.853 864.000 ;
    END
  END sw_d[54]
  PIN sw_d[55]
    DIRECTION INPUT ;
    USE SIGNAL ;
    PORT
      LAYER M5 ;
        RECT 222.720 863.808 222.744 864.000 ;
    END
  END sw_d[55]
  PIN sw_d[56]
    DIRECTION INPUT ;
    USE SIGNAL ;
    PORT
      LAYER M3 ;
        RECT 223.629 863.808 223.653 864.000 ;
    END
  END sw_d[56]
  PIN sw_d[57]
    DIRECTION INPUT ;
    USE SIGNAL ;
    PORT
      LAYER M5 ;
        RECT 224.544 863.808 224.568 864.000 ;
    END
  END sw_d[57]
  PIN sw_d[58]
    DIRECTION INPUT ;
    USE SIGNAL ;
    PORT
      LAYER M3 ;
        RECT 225.429 863.808 225.453 864.000 ;
    END
  END sw_d[58]
  PIN sw_d[59]
    DIRECTION INPUT ;
    USE SIGNAL ;
    PORT
      LAYER M5 ;
        RECT 226.320 863.808 226.344 864.000 ;
    END
  END sw_d[59]
  PIN sw_d[60]
    DIRECTION INPUT ;
    USE SIGNAL ;
    PORT
      LAYER M3 ;
        RECT 227.229 863.808 227.253 864.000 ;
    END
  END sw_d[60]
  PIN sw_d[61]
    DIRECTION INPUT ;
    USE SIGNAL ;
    PORT
      LAYER M5 ;
        RECT 228.144 863.808 228.168 864.000 ;
    END
  END sw_d[61]
  PIN sw_d[62]
    DIRECTION INPUT ;
    USE SIGNAL ;
    PORT
      LAYER M3 ;
        RECT 229.065 863.808 229.089 864.000 ;
    END
  END sw_d[62]
  PIN sw_d[63]
    DIRECTION INPUT ;
    USE SIGNAL ;
    PORT
      LAYER M5 ;
        RECT 229.968 863.808 229.992 864.000 ;
    END
  END sw_d[63]
  PIN sw_d[64]
    DIRECTION INPUT ;
    USE SIGNAL ;
    PORT
      LAYER M3 ;
        RECT 230.865 863.808 230.889 864.000 ;
    END
  END sw_d[64]
  PIN sw_d[65]
    DIRECTION INPUT ;
    USE SIGNAL ;
    PORT
      LAYER M5 ;
        RECT 231.744 863.808 231.768 864.000 ;
    END
  END sw_d[65]
  PIN sw_d[66]
    DIRECTION INPUT ;
    USE SIGNAL ;
    PORT
      LAYER M3 ;
        RECT 232.665 863.808 232.689 864.000 ;
    END
  END sw_d[66]
  PIN sw_d[67]
    DIRECTION INPUT ;
    USE SIGNAL ;
    PORT
      LAYER M5 ;
        RECT 233.568 863.808 233.592 864.000 ;
    END
  END sw_d[67]
  PIN sw_d[68]
    DIRECTION INPUT ;
    USE SIGNAL ;
    PORT
      LAYER M3 ;
        RECT 234.465 863.808 234.489 864.000 ;
    END
  END sw_d[68]
  PIN sw_d[69]
    DIRECTION INPUT ;
    USE SIGNAL ;
    PORT
      LAYER M5 ;
        RECT 235.392 863.808 235.416 864.000 ;
    END
  END sw_d[69]
  PIN sw_d[70]
    DIRECTION INPUT ;
    USE SIGNAL ;
    PORT
      LAYER M3 ;
        RECT 236.265 863.808 236.289 864.000 ;
    END
  END sw_d[70]
  PIN sw_d[71]
    DIRECTION INPUT ;
    USE SIGNAL ;
    PORT
      LAYER M5 ;
        RECT 237.168 863.808 237.192 864.000 ;
    END
  END sw_d[71]
  PIN sw_d[72]
    DIRECTION INPUT ;
    USE SIGNAL ;
    PORT
      LAYER M3 ;
        RECT 238.101 863.808 238.125 864.000 ;
    END
  END sw_d[72]
  PIN sw_d[73]
    DIRECTION INPUT ;
    USE SIGNAL ;
    PORT
      LAYER M5 ;
        RECT 238.992 863.808 239.016 864.000 ;
    END
  END sw_d[73]
  PIN sw_d[74]
    DIRECTION INPUT ;
    USE SIGNAL ;
    PORT
      LAYER M3 ;
        RECT 239.901 863.808 239.925 864.000 ;
    END
  END sw_d[74]
  PIN sw_d[75]
    DIRECTION INPUT ;
    USE SIGNAL ;
    PORT
      LAYER M5 ;
        RECT 240.816 863.808 240.840 864.000 ;
    END
  END sw_d[75]
  PIN sw_d[76]
    DIRECTION INPUT ;
    USE SIGNAL ;
    PORT
      LAYER M3 ;
        RECT 241.701 863.808 241.725 864.000 ;
    END
  END sw_d[76]
  PIN sw_d[77]
    DIRECTION INPUT ;
    USE SIGNAL ;
    PORT
      LAYER M5 ;
        RECT 242.592 863.808 242.616 864.000 ;
    END
  END sw_d[77]
  PIN sw_d[78]
    DIRECTION INPUT ;
    USE SIGNAL ;
    PORT
      LAYER M3 ;
        RECT 243.501 863.808 243.525 864.000 ;
    END
  END sw_d[78]
  PIN sw_d[79]
    DIRECTION INPUT ;
    USE SIGNAL ;
    PORT
      LAYER M5 ;
        RECT 244.416 863.808 244.440 864.000 ;
    END
  END sw_d[79]
  PIN sw_d[80]
    DIRECTION INPUT ;
    USE SIGNAL ;
    PORT
      LAYER M3 ;
        RECT 245.301 863.808 245.325 864.000 ;
    END
  END sw_d[80]
  PIN sw_d[81]
    DIRECTION INPUT ;
    USE SIGNAL ;
    PORT
      LAYER M5 ;
        RECT 246.240 863.808 246.264 864.000 ;
    END
  END sw_d[81]
  PIN sw_d[82]
    DIRECTION INPUT ;
    USE SIGNAL ;
    PORT
      LAYER M3 ;
        RECT 247.137 863.808 247.161 864.000 ;
    END
  END sw_d[82]
  PIN sw_d[83]
    DIRECTION INPUT ;
    USE SIGNAL ;
    PORT
      LAYER M5 ;
        RECT 248.016 863.808 248.040 864.000 ;
    END
  END sw_d[83]
  PIN sw_d[84]
    DIRECTION INPUT ;
    USE SIGNAL ;
    PORT
      LAYER M3 ;
        RECT 248.937 863.808 248.961 864.000 ;
    END
  END sw_d[84]
  PIN sw_d[85]
    DIRECTION INPUT ;
    USE SIGNAL ;
    PORT
      LAYER M5 ;
        RECT 249.840 863.808 249.864 864.000 ;
    END
  END sw_d[85]
  PIN sw_d[86]
    DIRECTION INPUT ;
    USE SIGNAL ;
    PORT
      LAYER M3 ;
        RECT 250.737 863.808 250.761 864.000 ;
    END
  END sw_d[86]
  PIN sw_d[87]
    DIRECTION INPUT ;
    USE SIGNAL ;
    PORT
      LAYER M5 ;
        RECT 251.664 863.808 251.688 864.000 ;
    END
  END sw_d[87]
  PIN sw_d[88]
    DIRECTION INPUT ;
    USE SIGNAL ;
    PORT
      LAYER M3 ;
        RECT 252.537 863.808 252.561 864.000 ;
    END
  END sw_d[88]
  PIN sw_d[89]
    DIRECTION INPUT ;
    USE SIGNAL ;
    PORT
      LAYER M5 ;
        RECT 253.440 863.808 253.464 864.000 ;
    END
  END sw_d[89]
  PIN sw_d[90]
    DIRECTION INPUT ;
    USE SIGNAL ;
    PORT
      LAYER M3 ;
        RECT 254.337 863.808 254.361 864.000 ;
    END
  END sw_d[90]
  PIN sw_d[91]
    DIRECTION INPUT ;
    USE SIGNAL ;
    PORT
      LAYER M5 ;
        RECT 255.264 863.808 255.288 864.000 ;
    END
  END sw_d[91]
  PIN sw_d[92]
    DIRECTION INPUT ;
    USE SIGNAL ;
    PORT
      LAYER M3 ;
        RECT 256.173 863.808 256.197 864.000 ;
    END
  END sw_d[92]
  PIN sw_d[93]
    DIRECTION INPUT ;
    USE SIGNAL ;
    PORT
      LAYER M5 ;
        RECT 257.088 863.808 257.112 864.000 ;
    END
  END sw_d[93]
  PIN sw_d[94]
    DIRECTION INPUT ;
    USE SIGNAL ;
    PORT
      LAYER M3 ;
        RECT 257.973 863.808 257.997 864.000 ;
    END
  END sw_d[94]
  PIN sw_d[95]
    DIRECTION INPUT ;
    USE SIGNAL ;
    PORT
      LAYER M5 ;
        RECT 258.864 863.808 258.888 864.000 ;
    END
  END sw_d[95]
  PIN sw_d[96]
    DIRECTION INPUT ;
    USE SIGNAL ;
    PORT
      LAYER M3 ;
        RECT 259.773 863.808 259.797 864.000 ;
    END
  END sw_d[96]
  PIN sw_d[97]
    DIRECTION INPUT ;
    USE SIGNAL ;
    PORT
      LAYER M5 ;
        RECT 260.688 863.808 260.712 864.000 ;
    END
  END sw_d[97]
  PIN sw_d[98]
    DIRECTION INPUT ;
    USE SIGNAL ;
    PORT
      LAYER M3 ;
        RECT 261.573 863.808 261.597 864.000 ;
    END
  END sw_d[98]
  PIN sw_d[99]
    DIRECTION INPUT ;
    USE SIGNAL ;
    PORT
      LAYER M5 ;
        RECT 262.464 863.808 262.488 864.000 ;
    END
  END sw_d[99]
  PIN sw_d[100]
    DIRECTION INPUT ;
    USE SIGNAL ;
    PORT
      LAYER M3 ;
        RECT 263.373 863.808 263.397 864.000 ;
    END
  END sw_d[100]
  PIN sw_d[101]
    DIRECTION INPUT ;
    USE SIGNAL ;
    PORT
      LAYER M5 ;
        RECT 264.288 863.808 264.312 864.000 ;
    END
  END sw_d[101]
  PIN sw_d[102]
    DIRECTION INPUT ;
    USE SIGNAL ;
    PORT
      LAYER M3 ;
        RECT 265.209 863.808 265.233 864.000 ;
    END
  END sw_d[102]
  PIN sw_d[103]
    DIRECTION INPUT ;
    USE SIGNAL ;
    PORT
      LAYER M5 ;
        RECT 266.112 863.808 266.136 864.000 ;
    END
  END sw_d[103]
  PIN sw_d[104]
    DIRECTION INPUT ;
    USE SIGNAL ;
    PORT
      LAYER M3 ;
        RECT 267.009 863.808 267.033 864.000 ;
    END
  END sw_d[104]
  PIN sw_d[105]
    DIRECTION INPUT ;
    USE SIGNAL ;
    PORT
      LAYER M5 ;
        RECT 267.888 863.808 267.912 864.000 ;
    END
  END sw_d[105]
  PIN sw_d[106]
    DIRECTION INPUT ;
    USE SIGNAL ;
    PORT
      LAYER M3 ;
        RECT 268.809 863.808 268.833 864.000 ;
    END
  END sw_d[106]
  PIN sw_d[107]
    DIRECTION INPUT ;
    USE SIGNAL ;
    PORT
      LAYER M5 ;
        RECT 269.712 863.808 269.736 864.000 ;
    END
  END sw_d[107]
  PIN sw_d[108]
    DIRECTION INPUT ;
    USE SIGNAL ;
    PORT
      LAYER M3 ;
        RECT 270.609 863.808 270.633 864.000 ;
    END
  END sw_d[108]
  PIN sw_d[109]
    DIRECTION INPUT ;
    USE SIGNAL ;
    PORT
      LAYER M5 ;
        RECT 271.536 863.808 271.560 864.000 ;
    END
  END sw_d[109]
  PIN sw_d[110]
    DIRECTION INPUT ;
    USE SIGNAL ;
    PORT
      LAYER M3 ;
        RECT 272.409 863.808 272.433 864.000 ;
    END
  END sw_d[110]
  PIN sw_d[111]
    DIRECTION INPUT ;
    USE SIGNAL ;
    PORT
      LAYER M5 ;
        RECT 273.312 863.808 273.336 864.000 ;
    END
  END sw_d[111]
  PIN sw_d[112]
    DIRECTION INPUT ;
    USE SIGNAL ;
    PORT
      LAYER M3 ;
        RECT 274.245 863.808 274.269 864.000 ;
    END
  END sw_d[112]
  PIN sw_d[113]
    DIRECTION INPUT ;
    USE SIGNAL ;
    PORT
      LAYER M5 ;
        RECT 275.136 863.808 275.160 864.000 ;
    END
  END sw_d[113]
  PIN sw_d[114]
    DIRECTION INPUT ;
    USE SIGNAL ;
    PORT
      LAYER M3 ;
        RECT 276.045 863.808 276.069 864.000 ;
    END
  END sw_d[114]
  PIN sw_d[115]
    DIRECTION INPUT ;
    USE SIGNAL ;
    PORT
      LAYER M5 ;
        RECT 276.960 863.808 276.984 864.000 ;
    END
  END sw_d[115]
  PIN sw_d[116]
    DIRECTION INPUT ;
    USE SIGNAL ;
    PORT
      LAYER M3 ;
        RECT 277.845 863.808 277.869 864.000 ;
    END
  END sw_d[116]
  PIN sw_d[117]
    DIRECTION INPUT ;
    USE SIGNAL ;
    PORT
      LAYER M5 ;
        RECT 278.736 863.808 278.760 864.000 ;
    END
  END sw_d[117]
  PIN sw_d[118]
    DIRECTION INPUT ;
    USE SIGNAL ;
    PORT
      LAYER M3 ;
        RECT 279.645 863.808 279.669 864.000 ;
    END
  END sw_d[118]
  PIN sw_d[119]
    DIRECTION INPUT ;
    USE SIGNAL ;
    PORT
      LAYER M5 ;
        RECT 280.560 863.808 280.584 864.000 ;
    END
  END sw_d[119]
  PIN sw_d[120]
    DIRECTION INPUT ;
    USE SIGNAL ;
    PORT
      LAYER M3 ;
        RECT 281.445 863.808 281.469 864.000 ;
    END
  END sw_d[120]
  PIN sw_d[121]
    DIRECTION INPUT ;
    USE SIGNAL ;
    PORT
      LAYER M5 ;
        RECT 282.384 863.808 282.408 864.000 ;
    END
  END sw_d[121]
  PIN sw_d[122]
    DIRECTION INPUT ;
    USE SIGNAL ;
    PORT
      LAYER M3 ;
        RECT 283.281 863.808 283.305 864.000 ;
    END
  END sw_d[122]
  PIN sw_d[123]
    DIRECTION INPUT ;
    USE SIGNAL ;
    PORT
      LAYER M5 ;
        RECT 284.160 863.808 284.184 864.000 ;
    END
  END sw_d[123]
  PIN sw_d[124]
    DIRECTION INPUT ;
    USE SIGNAL ;
    PORT
      LAYER M3 ;
        RECT 285.081 863.808 285.105 864.000 ;
    END
  END sw_d[124]
  PIN sw_d[125]
    DIRECTION INPUT ;
    USE SIGNAL ;
    PORT
      LAYER M5 ;
        RECT 285.984 863.808 286.008 864.000 ;
    END
  END sw_d[125]
  PIN sw_d[126]
    DIRECTION INPUT ;
    USE SIGNAL ;
    PORT
      LAYER M3 ;
        RECT 286.881 863.808 286.905 864.000 ;
    END
  END sw_d[126]
  PIN sw_d[127]
    DIRECTION INPUT ;
    USE SIGNAL ;
    PORT
      LAYER M5 ;
        RECT 287.808 863.808 287.832 864.000 ;
    END
  END sw_d[127]
  PIN sw_d[128]
    DIRECTION INPUT ;
    USE SIGNAL ;
    PORT
      LAYER M3 ;
        RECT 288.681 863.808 288.705 864.000 ;
    END
  END sw_d[128]
  PIN sw_d[129]
    DIRECTION INPUT ;
    USE SIGNAL ;
    PORT
      LAYER M5 ;
        RECT 289.584 863.808 289.608 864.000 ;
    END
  END sw_d[129]
  PIN sw_d[130]
    DIRECTION INPUT ;
    USE SIGNAL ;
    PORT
      LAYER M3 ;
        RECT 290.481 863.808 290.505 864.000 ;
    END
  END sw_d[130]
  PIN sw_d[131]
    DIRECTION INPUT ;
    USE SIGNAL ;
    PORT
      LAYER M5 ;
        RECT 291.408 863.808 291.432 864.000 ;
    END
  END sw_d[131]
  PIN sw_d[132]
    DIRECTION INPUT ;
    USE SIGNAL ;
    PORT
      LAYER M3 ;
        RECT 292.317 863.808 292.341 864.000 ;
    END
  END sw_d[132]
  PIN sw_d[133]
    DIRECTION INPUT ;
    USE SIGNAL ;
    PORT
      LAYER M5 ;
        RECT 293.232 863.808 293.256 864.000 ;
    END
  END sw_d[133]
  PIN sw_d[134]
    DIRECTION INPUT ;
    USE SIGNAL ;
    PORT
      LAYER M3 ;
        RECT 294.117 863.808 294.141 864.000 ;
    END
  END sw_d[134]
  PIN sw_d[135]
    DIRECTION INPUT ;
    USE SIGNAL ;
    PORT
      LAYER M5 ;
        RECT 295.008 863.808 295.032 864.000 ;
    END
  END sw_d[135]
  PIN sw_d[136]
    DIRECTION INPUT ;
    USE SIGNAL ;
    PORT
      LAYER M3 ;
        RECT 295.917 863.808 295.941 864.000 ;
    END
  END sw_d[136]
  PIN sw_d[137]
    DIRECTION INPUT ;
    USE SIGNAL ;
    PORT
      LAYER M5 ;
        RECT 296.832 863.808 296.856 864.000 ;
    END
  END sw_d[137]
  PIN sw_d[138]
    DIRECTION INPUT ;
    USE SIGNAL ;
    PORT
      LAYER M3 ;
        RECT 297.717 863.808 297.741 864.000 ;
    END
  END sw_d[138]
  PIN sw_d[139]
    DIRECTION INPUT ;
    USE SIGNAL ;
    PORT
      LAYER M5 ;
        RECT 298.608 863.808 298.632 864.000 ;
    END
  END sw_d[139]
  PIN sw_d[140]
    DIRECTION INPUT ;
    USE SIGNAL ;
    PORT
      LAYER M3 ;
        RECT 299.517 863.808 299.541 864.000 ;
    END
  END sw_d[140]
  PIN sw_d[141]
    DIRECTION INPUT ;
    USE SIGNAL ;
    PORT
      LAYER M5 ;
        RECT 300.432 863.808 300.456 864.000 ;
    END
  END sw_d[141]
  PIN sw_d[142]
    DIRECTION INPUT ;
    USE SIGNAL ;
    PORT
      LAYER M3 ;
        RECT 301.353 863.808 301.377 864.000 ;
    END
  END sw_d[142]
  PIN sw_d[143]
    DIRECTION INPUT ;
    USE SIGNAL ;
    PORT
      LAYER M5 ;
        RECT 302.256 863.808 302.280 864.000 ;
    END
  END sw_d[143]
  PIN sw_d[144]
    DIRECTION INPUT ;
    USE SIGNAL ;
    PORT
      LAYER M3 ;
        RECT 303.153 863.808 303.177 864.000 ;
    END
  END sw_d[144]
  PIN sw_d[145]
    DIRECTION INPUT ;
    USE SIGNAL ;
    PORT
      LAYER M5 ;
        RECT 304.032 863.808 304.056 864.000 ;
    END
  END sw_d[145]
  PIN sw_d[146]
    DIRECTION INPUT ;
    USE SIGNAL ;
    PORT
      LAYER M3 ;
        RECT 304.953 863.808 304.977 864.000 ;
    END
  END sw_d[146]
  PIN sw_d[147]
    DIRECTION INPUT ;
    USE SIGNAL ;
    PORT
      LAYER M5 ;
        RECT 305.856 863.808 305.880 864.000 ;
    END
  END sw_d[147]
  PIN sw_d[148]
    DIRECTION INPUT ;
    USE SIGNAL ;
    PORT
      LAYER M3 ;
        RECT 306.753 863.808 306.777 864.000 ;
    END
  END sw_d[148]
  PIN sw_d[149]
    DIRECTION INPUT ;
    USE SIGNAL ;
    PORT
      LAYER M5 ;
        RECT 307.680 863.808 307.704 864.000 ;
    END
  END sw_d[149]
  PIN sw_d[150]
    DIRECTION INPUT ;
    USE SIGNAL ;
    PORT
      LAYER M3 ;
        RECT 308.553 863.808 308.577 864.000 ;
    END
  END sw_d[150]
  PIN sw_d[151]
    DIRECTION INPUT ;
    USE SIGNAL ;
    PORT
      LAYER M5 ;
        RECT 309.456 863.808 309.480 864.000 ;
    END
  END sw_d[151]
  PIN sw_d[152]
    DIRECTION INPUT ;
    USE SIGNAL ;
    PORT
      LAYER M3 ;
        RECT 310.389 863.808 310.413 864.000 ;
    END
  END sw_d[152]
  PIN sw_d[153]
    DIRECTION INPUT ;
    USE SIGNAL ;
    PORT
      LAYER M5 ;
        RECT 311.280 863.808 311.304 864.000 ;
    END
  END sw_d[153]
  PIN sw_d[154]
    DIRECTION INPUT ;
    USE SIGNAL ;
    PORT
      LAYER M3 ;
        RECT 312.189 863.808 312.213 864.000 ;
    END
  END sw_d[154]
  PIN sw_d[155]
    DIRECTION INPUT ;
    USE SIGNAL ;
    PORT
      LAYER M5 ;
        RECT 313.104 863.808 313.128 864.000 ;
    END
  END sw_d[155]
  PIN sw_d[156]
    DIRECTION INPUT ;
    USE SIGNAL ;
    PORT
      LAYER M3 ;
        RECT 313.989 863.808 314.013 864.000 ;
    END
  END sw_d[156]
  PIN sw_d[157]
    DIRECTION INPUT ;
    USE SIGNAL ;
    PORT
      LAYER M5 ;
        RECT 314.880 863.808 314.904 864.000 ;
    END
  END sw_d[157]
  PIN sw_d[158]
    DIRECTION INPUT ;
    USE SIGNAL ;
    PORT
      LAYER M3 ;
        RECT 315.789 863.808 315.813 864.000 ;
    END
  END sw_d[158]
  PIN sw_d[159]
    DIRECTION INPUT ;
    USE SIGNAL ;
    PORT
      LAYER M5 ;
        RECT 316.704 863.808 316.728 864.000 ;
    END
  END sw_d[159]
  PIN sw_d[160]
    DIRECTION INPUT ;
    USE SIGNAL ;
    PORT
      LAYER M3 ;
        RECT 317.589 863.808 317.613 864.000 ;
    END
  END sw_d[160]
  PIN sw_d[161]
    DIRECTION INPUT ;
    USE SIGNAL ;
    PORT
      LAYER M5 ;
        RECT 318.528 863.808 318.552 864.000 ;
    END
  END sw_d[161]
  PIN sw_d[162]
    DIRECTION INPUT ;
    USE SIGNAL ;
    PORT
      LAYER M3 ;
        RECT 319.425 863.808 319.449 864.000 ;
    END
  END sw_d[162]
  PIN sw_d[163]
    DIRECTION INPUT ;
    USE SIGNAL ;
    PORT
      LAYER M5 ;
        RECT 320.304 863.808 320.328 864.000 ;
    END
  END sw_d[163]
  PIN sw_d[164]
    DIRECTION INPUT ;
    USE SIGNAL ;
    PORT
      LAYER M3 ;
        RECT 321.225 863.808 321.249 864.000 ;
    END
  END sw_d[164]
  PIN sw_d[165]
    DIRECTION INPUT ;
    USE SIGNAL ;
    PORT
      LAYER M5 ;
        RECT 322.128 863.808 322.152 864.000 ;
    END
  END sw_d[165]
  PIN sw_d[166]
    DIRECTION INPUT ;
    USE SIGNAL ;
    PORT
      LAYER M3 ;
        RECT 323.025 863.808 323.049 864.000 ;
    END
  END sw_d[166]
  PIN sw_d[167]
    DIRECTION INPUT ;
    USE SIGNAL ;
    PORT
      LAYER M5 ;
        RECT 323.952 863.808 323.976 864.000 ;
    END
  END sw_d[167]
  PIN sw_d[168]
    DIRECTION INPUT ;
    USE SIGNAL ;
    PORT
      LAYER M3 ;
        RECT 324.825 863.808 324.849 864.000 ;
    END
  END sw_d[168]
  PIN sw_d[169]
    DIRECTION INPUT ;
    USE SIGNAL ;
    PORT
      LAYER M5 ;
        RECT 325.728 863.808 325.752 864.000 ;
    END
  END sw_d[169]
  PIN sw_d[170]
    DIRECTION INPUT ;
    USE SIGNAL ;
    PORT
      LAYER M3 ;
        RECT 326.625 863.808 326.649 864.000 ;
    END
  END sw_d[170]
  PIN sw_d[171]
    DIRECTION INPUT ;
    USE SIGNAL ;
    PORT
      LAYER M5 ;
        RECT 327.552 863.808 327.576 864.000 ;
    END
  END sw_d[171]
  PIN sw_d[172]
    DIRECTION INPUT ;
    USE SIGNAL ;
    PORT
      LAYER M3 ;
        RECT 328.461 863.808 328.485 864.000 ;
    END
  END sw_d[172]
  PIN sw_d[173]
    DIRECTION INPUT ;
    USE SIGNAL ;
    PORT
      LAYER M5 ;
        RECT 329.376 863.808 329.400 864.000 ;
    END
  END sw_d[173]
  PIN sw_d[174]
    DIRECTION INPUT ;
    USE SIGNAL ;
    PORT
      LAYER M3 ;
        RECT 330.261 863.808 330.285 864.000 ;
    END
  END sw_d[174]
  PIN sw_d[175]
    DIRECTION INPUT ;
    USE SIGNAL ;
    PORT
      LAYER M5 ;
        RECT 331.152 863.808 331.176 864.000 ;
    END
  END sw_d[175]
  PIN sw_d[176]
    DIRECTION INPUT ;
    USE SIGNAL ;
    PORT
      LAYER M3 ;
        RECT 332.061 863.808 332.085 864.000 ;
    END
  END sw_d[176]
  PIN sw_d[177]
    DIRECTION INPUT ;
    USE SIGNAL ;
    PORT
      LAYER M5 ;
        RECT 332.976 863.808 333.000 864.000 ;
    END
  END sw_d[177]
  PIN sw_d[178]
    DIRECTION INPUT ;
    USE SIGNAL ;
    PORT
      LAYER M3 ;
        RECT 333.861 863.808 333.885 864.000 ;
    END
  END sw_d[178]
  PIN sw_d[179]
    DIRECTION INPUT ;
    USE SIGNAL ;
    PORT
      LAYER M5 ;
        RECT 334.752 863.808 334.776 864.000 ;
    END
  END sw_d[179]
  PIN sw_d[180]
    DIRECTION INPUT ;
    USE SIGNAL ;
    PORT
      LAYER M3 ;
        RECT 335.661 863.808 335.685 864.000 ;
    END
  END sw_d[180]
  PIN sw_d[181]
    DIRECTION INPUT ;
    USE SIGNAL ;
    PORT
      LAYER M5 ;
        RECT 336.576 863.808 336.600 864.000 ;
    END
  END sw_d[181]
  PIN sw_d[182]
    DIRECTION INPUT ;
    USE SIGNAL ;
    PORT
      LAYER M3 ;
        RECT 337.497 863.808 337.521 864.000 ;
    END
  END sw_d[182]
  PIN sw_d[183]
    DIRECTION INPUT ;
    USE SIGNAL ;
    PORT
      LAYER M5 ;
        RECT 338.400 863.808 338.424 864.000 ;
    END
  END sw_d[183]
  PIN sw_d[184]
    DIRECTION INPUT ;
    USE SIGNAL ;
    PORT
      LAYER M3 ;
        RECT 339.297 863.808 339.321 864.000 ;
    END
  END sw_d[184]
  PIN sw_d[185]
    DIRECTION INPUT ;
    USE SIGNAL ;
    PORT
      LAYER M5 ;
        RECT 340.176 863.808 340.200 864.000 ;
    END
  END sw_d[185]
  PIN sw_d[186]
    DIRECTION INPUT ;
    USE SIGNAL ;
    PORT
      LAYER M3 ;
        RECT 341.097 863.808 341.121 864.000 ;
    END
  END sw_d[186]
  PIN sw_d[187]
    DIRECTION INPUT ;
    USE SIGNAL ;
    PORT
      LAYER M5 ;
        RECT 342.000 863.808 342.024 864.000 ;
    END
  END sw_d[187]
  PIN sw_d[188]
    DIRECTION INPUT ;
    USE SIGNAL ;
    PORT
      LAYER M3 ;
        RECT 342.897 863.808 342.921 864.000 ;
    END
  END sw_d[188]
  PIN sw_d[189]
    DIRECTION INPUT ;
    USE SIGNAL ;
    PORT
      LAYER M5 ;
        RECT 343.824 863.808 343.848 864.000 ;
    END
  END sw_d[189]
  PIN sw_d[190]
    DIRECTION INPUT ;
    USE SIGNAL ;
    PORT
      LAYER M3 ;
        RECT 344.697 863.808 344.721 864.000 ;
    END
  END sw_d[190]
  PIN sw_d[191]
    DIRECTION INPUT ;
    USE SIGNAL ;
    PORT
      LAYER M5 ;
        RECT 345.600 863.808 345.624 864.000 ;
    END
  END sw_d[191]
  PIN sw_d[192]
    DIRECTION INPUT ;
    USE SIGNAL ;
    PORT
      LAYER M3 ;
        RECT 346.533 863.808 346.557 864.000 ;
    END
  END sw_d[192]
  PIN sw_d[193]
    DIRECTION INPUT ;
    USE SIGNAL ;
    PORT
      LAYER M5 ;
        RECT 347.424 863.808 347.448 864.000 ;
    END
  END sw_d[193]
  PIN sw_d[194]
    DIRECTION INPUT ;
    USE SIGNAL ;
    PORT
      LAYER M3 ;
        RECT 348.333 863.808 348.357 864.000 ;
    END
  END sw_d[194]
  PIN sw_d[195]
    DIRECTION INPUT ;
    USE SIGNAL ;
    PORT
      LAYER M5 ;
        RECT 349.248 863.808 349.272 864.000 ;
    END
  END sw_d[195]
  PIN sw_d[196]
    DIRECTION INPUT ;
    USE SIGNAL ;
    PORT
      LAYER M3 ;
        RECT 350.133 863.808 350.157 864.000 ;
    END
  END sw_d[196]
  PIN sw_d[197]
    DIRECTION INPUT ;
    USE SIGNAL ;
    PORT
      LAYER M5 ;
        RECT 351.024 863.808 351.048 864.000 ;
    END
  END sw_d[197]
  PIN sw_d[198]
    DIRECTION INPUT ;
    USE SIGNAL ;
    PORT
      LAYER M3 ;
        RECT 351.933 863.808 351.957 864.000 ;
    END
  END sw_d[198]
  PIN sw_d[199]
    DIRECTION INPUT ;
    USE SIGNAL ;
    PORT
      LAYER M5 ;
        RECT 352.848 863.808 352.872 864.000 ;
    END
  END sw_d[199]
  PIN sw_d[200]
    DIRECTION INPUT ;
    USE SIGNAL ;
    PORT
      LAYER M3 ;
        RECT 353.733 863.808 353.757 864.000 ;
    END
  END sw_d[200]
  PIN sw_d[201]
    DIRECTION INPUT ;
    USE SIGNAL ;
    PORT
      LAYER M5 ;
        RECT 354.672 863.808 354.696 864.000 ;
    END
  END sw_d[201]
  PIN sw_d[202]
    DIRECTION INPUT ;
    USE SIGNAL ;
    PORT
      LAYER M3 ;
        RECT 355.569 863.808 355.593 864.000 ;
    END
  END sw_d[202]
  PIN sw_d[203]
    DIRECTION INPUT ;
    USE SIGNAL ;
    PORT
      LAYER M5 ;
        RECT 356.448 863.808 356.472 864.000 ;
    END
  END sw_d[203]
  PIN sw_d[204]
    DIRECTION INPUT ;
    USE SIGNAL ;
    PORT
      LAYER M3 ;
        RECT 357.369 863.808 357.393 864.000 ;
    END
  END sw_d[204]
  PIN sw_d[205]
    DIRECTION INPUT ;
    USE SIGNAL ;
    PORT
      LAYER M5 ;
        RECT 358.272 863.808 358.296 864.000 ;
    END
  END sw_d[205]
  PIN sw_d[206]
    DIRECTION INPUT ;
    USE SIGNAL ;
    PORT
      LAYER M3 ;
        RECT 359.169 863.808 359.193 864.000 ;
    END
  END sw_d[206]
  PIN sw_d[207]
    DIRECTION INPUT ;
    USE SIGNAL ;
    PORT
      LAYER M5 ;
        RECT 360.096 863.808 360.120 864.000 ;
    END
  END sw_d[207]
  PIN sw_d[208]
    DIRECTION INPUT ;
    USE SIGNAL ;
    PORT
      LAYER M3 ;
        RECT 360.969 863.808 360.993 864.000 ;
    END
  END sw_d[208]
  PIN sw_d[209]
    DIRECTION INPUT ;
    USE SIGNAL ;
    PORT
      LAYER M5 ;
        RECT 361.872 863.808 361.896 864.000 ;
    END
  END sw_d[209]
  PIN sw_d[210]
    DIRECTION INPUT ;
    USE SIGNAL ;
    PORT
      LAYER M3 ;
        RECT 362.769 863.808 362.793 864.000 ;
    END
  END sw_d[210]
  PIN sw_d[211]
    DIRECTION INPUT ;
    USE SIGNAL ;
    PORT
      LAYER M5 ;
        RECT 363.696 863.808 363.720 864.000 ;
    END
  END sw_d[211]
  PIN sw_d[212]
    DIRECTION INPUT ;
    USE SIGNAL ;
    PORT
      LAYER M3 ;
        RECT 364.605 863.808 364.629 864.000 ;
    END
  END sw_d[212]
  PIN sw_d[213]
    DIRECTION INPUT ;
    USE SIGNAL ;
    PORT
      LAYER M5 ;
        RECT 365.520 863.808 365.544 864.000 ;
    END
  END sw_d[213]
  PIN sw_d[214]
    DIRECTION INPUT ;
    USE SIGNAL ;
    PORT
      LAYER M3 ;
        RECT 366.405 863.808 366.429 864.000 ;
    END
  END sw_d[214]
  PIN sw_d[215]
    DIRECTION INPUT ;
    USE SIGNAL ;
    PORT
      LAYER M5 ;
        RECT 367.296 863.808 367.320 864.000 ;
    END
  END sw_d[215]
  PIN sw_d[216]
    DIRECTION INPUT ;
    USE SIGNAL ;
    PORT
      LAYER M3 ;
        RECT 368.205 863.808 368.229 864.000 ;
    END
  END sw_d[216]
  PIN sw_d[217]
    DIRECTION INPUT ;
    USE SIGNAL ;
    PORT
      LAYER M5 ;
        RECT 369.120 863.808 369.144 864.000 ;
    END
  END sw_d[217]
  PIN sw_d[218]
    DIRECTION INPUT ;
    USE SIGNAL ;
    PORT
      LAYER M3 ;
        RECT 370.005 863.808 370.029 864.000 ;
    END
  END sw_d[218]
  PIN sw_d[219]
    DIRECTION INPUT ;
    USE SIGNAL ;
    PORT
      LAYER M5 ;
        RECT 370.896 863.808 370.920 864.000 ;
    END
  END sw_d[219]
  PIN sw_d[220]
    DIRECTION INPUT ;
    USE SIGNAL ;
    PORT
      LAYER M3 ;
        RECT 371.805 863.808 371.829 864.000 ;
    END
  END sw_d[220]
  PIN sw_d[221]
    DIRECTION INPUT ;
    USE SIGNAL ;
    PORT
      LAYER M5 ;
        RECT 372.720 863.808 372.744 864.000 ;
    END
  END sw_d[221]
  PIN sw_d[222]
    DIRECTION INPUT ;
    USE SIGNAL ;
    PORT
      LAYER M3 ;
        RECT 373.641 863.808 373.665 864.000 ;
    END
  END sw_d[222]
  PIN sw_d[223]
    DIRECTION INPUT ;
    USE SIGNAL ;
    PORT
      LAYER M5 ;
        RECT 374.544 863.808 374.568 864.000 ;
    END
  END sw_d[223]
  PIN sw_d[224]
    DIRECTION INPUT ;
    USE SIGNAL ;
    PORT
      LAYER M3 ;
        RECT 375.441 863.808 375.465 864.000 ;
    END
  END sw_d[224]
  PIN sw_d[225]
    DIRECTION INPUT ;
    USE SIGNAL ;
    PORT
      LAYER M5 ;
        RECT 376.320 863.808 376.344 864.000 ;
    END
  END sw_d[225]
  PIN sw_d[226]
    DIRECTION INPUT ;
    USE SIGNAL ;
    PORT
      LAYER M3 ;
        RECT 377.241 863.808 377.265 864.000 ;
    END
  END sw_d[226]
  PIN sw_d[227]
    DIRECTION INPUT ;
    USE SIGNAL ;
    PORT
      LAYER M5 ;
        RECT 378.144 863.808 378.168 864.000 ;
    END
  END sw_d[227]
  PIN sw_d[228]
    DIRECTION INPUT ;
    USE SIGNAL ;
    PORT
      LAYER M3 ;
        RECT 379.041 863.808 379.065 864.000 ;
    END
  END sw_d[228]
  PIN sw_d[229]
    DIRECTION INPUT ;
    USE SIGNAL ;
    PORT
      LAYER M5 ;
        RECT 379.968 863.808 379.992 864.000 ;
    END
  END sw_d[229]
  PIN sw_d[230]
    DIRECTION INPUT ;
    USE SIGNAL ;
    PORT
      LAYER M3 ;
        RECT 380.841 863.808 380.865 864.000 ;
    END
  END sw_d[230]
  PIN sw_d[231]
    DIRECTION INPUT ;
    USE SIGNAL ;
    PORT
      LAYER M5 ;
        RECT 381.744 863.808 381.768 864.000 ;
    END
  END sw_d[231]
  PIN sw_d[232]
    DIRECTION INPUT ;
    USE SIGNAL ;
    PORT
      LAYER M3 ;
        RECT 382.677 863.808 382.701 864.000 ;
    END
  END sw_d[232]
  PIN sw_d[233]
    DIRECTION INPUT ;
    USE SIGNAL ;
    PORT
      LAYER M5 ;
        RECT 383.568 863.808 383.592 864.000 ;
    END
  END sw_d[233]
  PIN sw_d[234]
    DIRECTION INPUT ;
    USE SIGNAL ;
    PORT
      LAYER M3 ;
        RECT 384.477 863.808 384.501 864.000 ;
    END
  END sw_d[234]
  PIN sw_d[235]
    DIRECTION INPUT ;
    USE SIGNAL ;
    PORT
      LAYER M5 ;
        RECT 385.392 863.808 385.416 864.000 ;
    END
  END sw_d[235]
  PIN sw_d[236]
    DIRECTION INPUT ;
    USE SIGNAL ;
    PORT
      LAYER M3 ;
        RECT 386.277 863.808 386.301 864.000 ;
    END
  END sw_d[236]
  PIN sw_d[237]
    DIRECTION INPUT ;
    USE SIGNAL ;
    PORT
      LAYER M5 ;
        RECT 387.168 863.808 387.192 864.000 ;
    END
  END sw_d[237]
  PIN sw_d[238]
    DIRECTION INPUT ;
    USE SIGNAL ;
    PORT
      LAYER M3 ;
        RECT 388.077 863.808 388.101 864.000 ;
    END
  END sw_d[238]
  PIN sw_d[239]
    DIRECTION INPUT ;
    USE SIGNAL ;
    PORT
      LAYER M5 ;
        RECT 388.992 863.808 389.016 864.000 ;
    END
  END sw_d[239]
  PIN sw_d[240]
    DIRECTION INPUT ;
    USE SIGNAL ;
    PORT
      LAYER M3 ;
        RECT 389.913 863.808 389.937 864.000 ;
    END
  END sw_d[240]
  PIN sw_d[241]
    DIRECTION INPUT ;
    USE SIGNAL ;
    PORT
      LAYER M5 ;
        RECT 390.816 863.808 390.840 864.000 ;
    END
  END sw_d[241]
  PIN sw_d[242]
    DIRECTION INPUT ;
    USE SIGNAL ;
    PORT
      LAYER M3 ;
        RECT 391.713 863.808 391.737 864.000 ;
    END
  END sw_d[242]
  PIN sw_d[243]
    DIRECTION INPUT ;
    USE SIGNAL ;
    PORT
      LAYER M5 ;
        RECT 392.592 863.808 392.616 864.000 ;
    END
  END sw_d[243]
  PIN sw_d[244]
    DIRECTION INPUT ;
    USE SIGNAL ;
    PORT
      LAYER M3 ;
        RECT 393.513 863.808 393.537 864.000 ;
    END
  END sw_d[244]
  PIN sw_d[245]
    DIRECTION INPUT ;
    USE SIGNAL ;
    PORT
      LAYER M5 ;
        RECT 394.416 863.808 394.440 864.000 ;
    END
  END sw_d[245]
  PIN sw_d[246]
    DIRECTION INPUT ;
    USE SIGNAL ;
    PORT
      LAYER M3 ;
        RECT 395.313 863.808 395.337 864.000 ;
    END
  END sw_d[246]
  PIN sw_d[247]
    DIRECTION INPUT ;
    USE SIGNAL ;
    PORT
      LAYER M5 ;
        RECT 396.240 863.808 396.264 864.000 ;
    END
  END sw_d[247]
  PIN sw_d[248]
    DIRECTION INPUT ;
    USE SIGNAL ;
    PORT
      LAYER M3 ;
        RECT 397.113 863.808 397.137 864.000 ;
    END
  END sw_d[248]
  PIN sw_d[249]
    DIRECTION INPUT ;
    USE SIGNAL ;
    PORT
      LAYER M5 ;
        RECT 398.016 863.808 398.040 864.000 ;
    END
  END sw_d[249]
  PIN sw_d[250]
    DIRECTION INPUT ;
    USE SIGNAL ;
    PORT
      LAYER M3 ;
        RECT 398.949 863.808 398.973 864.000 ;
    END
  END sw_d[250]
  PIN sw_d[251]
    DIRECTION INPUT ;
    USE SIGNAL ;
    PORT
      LAYER M5 ;
        RECT 399.840 863.808 399.864 864.000 ;
    END
  END sw_d[251]
  PIN sw_d[252]
    DIRECTION INPUT ;
    USE SIGNAL ;
    PORT
      LAYER M3 ;
        RECT 400.749 863.808 400.773 864.000 ;
    END
  END sw_d[252]
  PIN sw_d[253]
    DIRECTION INPUT ;
    USE SIGNAL ;
    PORT
      LAYER M5 ;
        RECT 401.664 863.808 401.688 864.000 ;
    END
  END sw_d[253]
  PIN sw_d[254]
    DIRECTION INPUT ;
    USE SIGNAL ;
    PORT
      LAYER M3 ;
        RECT 402.549 863.808 402.573 864.000 ;
    END
  END sw_d[254]
  PIN sw_d[255]
    DIRECTION INPUT ;
    USE SIGNAL ;
    PORT
      LAYER M5 ;
        RECT 403.440 863.808 403.464 864.000 ;
    END
  END sw_d[255]
  PIN clk
    DIRECTION INPUT ;
    USE CLOCK ;
    PORT
      LAYER M5 ;
        RECT 405.216 863.808 405.240 864.000 ;
    END
  END clk
  PIN rst_n
    DIRECTION INPUT ;
    USE SIGNAL ;
    PORT
      LAYER M5 ;
        RECT 407.856 863.808 407.880 864.000 ;
    END
  END rst_n
  PIN fault
    DIRECTION OUTPUT ;
    USE SIGNAL ;
    PORT
      LAYER M3 ;
        RECT 410.469 863.808 410.493 864.000 ;
    END
  END fault
  PIN lo_v
    DIRECTION OUTPUT ;
    USE SIGNAL ;
    PORT
      LAYER M5 ;
        RECT 413.136 863.808 413.160 864.000 ;
    END
  END lo_v
  PIN lo_d[0]
    DIRECTION OUTPUT ;
    USE SIGNAL ;
    PORT
      LAYER M3 ;
        RECT 414.897 863.808 414.921 864.000 ;
    END
  END lo_d[0]
  PIN lo_d[1]
    DIRECTION OUTPUT ;
    USE SIGNAL ;
    PORT
      LAYER M5 ;
        RECT 415.776 863.808 415.800 864.000 ;
    END
  END lo_d[1]
  PIN lo_d[2]
    DIRECTION OUTPUT ;
    USE SIGNAL ;
    PORT
      LAYER M3 ;
        RECT 416.697 863.808 416.721 864.000 ;
    END
  END lo_d[2]
  PIN lo_d[3]
    DIRECTION OUTPUT ;
    USE SIGNAL ;
    PORT
      LAYER M5 ;
        RECT 417.600 863.808 417.624 864.000 ;
    END
  END lo_d[3]
  PIN lo_d[4]
    DIRECTION OUTPUT ;
    USE SIGNAL ;
    PORT
      LAYER M3 ;
        RECT 418.497 863.808 418.521 864.000 ;
    END
  END lo_d[4]
  PIN lo_d[5]
    DIRECTION OUTPUT ;
    USE SIGNAL ;
    PORT
      LAYER M5 ;
        RECT 419.424 863.808 419.448 864.000 ;
    END
  END lo_d[5]
  PIN lo_d[6]
    DIRECTION OUTPUT ;
    USE SIGNAL ;
    PORT
      LAYER M3 ;
        RECT 420.297 863.808 420.321 864.000 ;
    END
  END lo_d[6]
  PIN lo_d[7]
    DIRECTION OUTPUT ;
    USE SIGNAL ;
    PORT
      LAYER M5 ;
        RECT 421.200 863.808 421.224 864.000 ;
    END
  END lo_d[7]
  PIN lo_d[8]
    DIRECTION OUTPUT ;
    USE SIGNAL ;
    PORT
      LAYER M3 ;
        RECT 422.097 863.808 422.121 864.000 ;
    END
  END lo_d[8]
  PIN lo_d[9]
    DIRECTION OUTPUT ;
    USE SIGNAL ;
    PORT
      LAYER M5 ;
        RECT 423.024 863.808 423.048 864.000 ;
    END
  END lo_d[9]
  PIN lo_d[10]
    DIRECTION OUTPUT ;
    USE SIGNAL ;
    PORT
      LAYER M3 ;
        RECT 423.933 863.808 423.957 864.000 ;
    END
  END lo_d[10]
  PIN lo_d[11]
    DIRECTION OUTPUT ;
    USE SIGNAL ;
    PORT
      LAYER M5 ;
        RECT 424.848 863.808 424.872 864.000 ;
    END
  END lo_d[11]
  PIN lo_d[12]
    DIRECTION OUTPUT ;
    USE SIGNAL ;
    PORT
      LAYER M3 ;
        RECT 425.733 863.808 425.757 864.000 ;
    END
  END lo_d[12]
  PIN lo_d[13]
    DIRECTION OUTPUT ;
    USE SIGNAL ;
    PORT
      LAYER M5 ;
        RECT 426.624 863.808 426.648 864.000 ;
    END
  END lo_d[13]
  PIN lo_d[14]
    DIRECTION OUTPUT ;
    USE SIGNAL ;
    PORT
      LAYER M3 ;
        RECT 427.533 863.808 427.557 864.000 ;
    END
  END lo_d[14]
  PIN lo_d[15]
    DIRECTION OUTPUT ;
    USE SIGNAL ;
    PORT
      LAYER M5 ;
        RECT 428.448 863.808 428.472 864.000 ;
    END
  END lo_d[15]
  PIN lo_d[16]
    DIRECTION OUTPUT ;
    USE SIGNAL ;
    PORT
      LAYER M3 ;
        RECT 429.333 863.808 429.357 864.000 ;
    END
  END lo_d[16]
  PIN lo_d[17]
    DIRECTION OUTPUT ;
    USE SIGNAL ;
    PORT
      LAYER M5 ;
        RECT 430.224 863.808 430.248 864.000 ;
    END
  END lo_d[17]
  PIN lo_d[18]
    DIRECTION OUTPUT ;
    USE SIGNAL ;
    PORT
      LAYER M3 ;
        RECT 431.133 863.808 431.157 864.000 ;
    END
  END lo_d[18]
  PIN lo_d[19]
    DIRECTION OUTPUT ;
    USE SIGNAL ;
    PORT
      LAYER M5 ;
        RECT 432.048 863.808 432.072 864.000 ;
    END
  END lo_d[19]
  PIN lo_d[20]
    DIRECTION OUTPUT ;
    USE SIGNAL ;
    PORT
      LAYER M3 ;
        RECT 432.969 863.808 432.993 864.000 ;
    END
  END lo_d[20]
  PIN lo_d[21]
    DIRECTION OUTPUT ;
    USE SIGNAL ;
    PORT
      LAYER M5 ;
        RECT 433.872 863.808 433.896 864.000 ;
    END
  END lo_d[21]
  PIN lo_d[22]
    DIRECTION OUTPUT ;
    USE SIGNAL ;
    PORT
      LAYER M3 ;
        RECT 434.769 863.808 434.793 864.000 ;
    END
  END lo_d[22]
  PIN lo_d[23]
    DIRECTION OUTPUT ;
    USE SIGNAL ;
    PORT
      LAYER M5 ;
        RECT 435.648 863.808 435.672 864.000 ;
    END
  END lo_d[23]
  PIN lo_d[24]
    DIRECTION OUTPUT ;
    USE SIGNAL ;
    PORT
      LAYER M3 ;
        RECT 436.569 863.808 436.593 864.000 ;
    END
  END lo_d[24]
  PIN lo_d[25]
    DIRECTION OUTPUT ;
    USE SIGNAL ;
    PORT
      LAYER M5 ;
        RECT 437.472 863.808 437.496 864.000 ;
    END
  END lo_d[25]
  PIN lo_d[26]
    DIRECTION OUTPUT ;
    USE SIGNAL ;
    PORT
      LAYER M3 ;
        RECT 438.369 863.808 438.393 864.000 ;
    END
  END lo_d[26]
  PIN lo_d[27]
    DIRECTION OUTPUT ;
    USE SIGNAL ;
    PORT
      LAYER M5 ;
        RECT 439.296 863.808 439.320 864.000 ;
    END
  END lo_d[27]
  PIN lo_d[28]
    DIRECTION OUTPUT ;
    USE SIGNAL ;
    PORT
      LAYER M3 ;
        RECT 440.169 863.808 440.193 864.000 ;
    END
  END lo_d[28]
  PIN lo_d[29]
    DIRECTION OUTPUT ;
    USE SIGNAL ;
    PORT
      LAYER M5 ;
        RECT 441.072 863.808 441.096 864.000 ;
    END
  END lo_d[29]
  PIN lo_d[30]
    DIRECTION OUTPUT ;
    USE SIGNAL ;
    PORT
      LAYER M3 ;
        RECT 442.005 863.808 442.029 864.000 ;
    END
  END lo_d[30]
  PIN lo_d[31]
    DIRECTION OUTPUT ;
    USE SIGNAL ;
    PORT
      LAYER M5 ;
        RECT 442.896 863.808 442.920 864.000 ;
    END
  END lo_d[31]
  PIN lo_d[32]
    DIRECTION OUTPUT ;
    USE SIGNAL ;
    PORT
      LAYER M3 ;
        RECT 443.805 863.808 443.829 864.000 ;
    END
  END lo_d[32]
  PIN lo_d[33]
    DIRECTION OUTPUT ;
    USE SIGNAL ;
    PORT
      LAYER M5 ;
        RECT 444.720 863.808 444.744 864.000 ;
    END
  END lo_d[33]
  PIN lo_d[34]
    DIRECTION OUTPUT ;
    USE SIGNAL ;
    PORT
      LAYER M3 ;
        RECT 445.605 863.808 445.629 864.000 ;
    END
  END lo_d[34]
  PIN lo_d[35]
    DIRECTION OUTPUT ;
    USE SIGNAL ;
    PORT
      LAYER M5 ;
        RECT 446.496 863.808 446.520 864.000 ;
    END
  END lo_d[35]
  PIN lo_d[36]
    DIRECTION OUTPUT ;
    USE SIGNAL ;
    PORT
      LAYER M3 ;
        RECT 447.405 863.808 447.429 864.000 ;
    END
  END lo_d[36]
  PIN lo_d[37]
    DIRECTION OUTPUT ;
    USE SIGNAL ;
    PORT
      LAYER M5 ;
        RECT 448.320 863.808 448.344 864.000 ;
    END
  END lo_d[37]
  PIN lo_d[38]
    DIRECTION OUTPUT ;
    USE SIGNAL ;
    PORT
      LAYER M3 ;
        RECT 449.205 863.808 449.229 864.000 ;
    END
  END lo_d[38]
  PIN lo_d[39]
    DIRECTION OUTPUT ;
    USE SIGNAL ;
    PORT
      LAYER M5 ;
        RECT 450.144 863.808 450.168 864.000 ;
    END
  END lo_d[39]
  PIN lo_d[40]
    DIRECTION OUTPUT ;
    USE SIGNAL ;
    PORT
      LAYER M3 ;
        RECT 451.041 863.808 451.065 864.000 ;
    END
  END lo_d[40]
  PIN lo_d[41]
    DIRECTION OUTPUT ;
    USE SIGNAL ;
    PORT
      LAYER M5 ;
        RECT 451.920 863.808 451.944 864.000 ;
    END
  END lo_d[41]
  PIN lo_d[42]
    DIRECTION OUTPUT ;
    USE SIGNAL ;
    PORT
      LAYER M3 ;
        RECT 452.841 863.808 452.865 864.000 ;
    END
  END lo_d[42]
  PIN lo_d[43]
    DIRECTION OUTPUT ;
    USE SIGNAL ;
    PORT
      LAYER M5 ;
        RECT 453.744 863.808 453.768 864.000 ;
    END
  END lo_d[43]
  PIN lo_d[44]
    DIRECTION OUTPUT ;
    USE SIGNAL ;
    PORT
      LAYER M3 ;
        RECT 454.641 863.808 454.665 864.000 ;
    END
  END lo_d[44]
  PIN lo_d[45]
    DIRECTION OUTPUT ;
    USE SIGNAL ;
    PORT
      LAYER M5 ;
        RECT 455.568 863.808 455.592 864.000 ;
    END
  END lo_d[45]
  PIN lo_d[46]
    DIRECTION OUTPUT ;
    USE SIGNAL ;
    PORT
      LAYER M3 ;
        RECT 456.441 863.808 456.465 864.000 ;
    END
  END lo_d[46]
  PIN lo_d[47]
    DIRECTION OUTPUT ;
    USE SIGNAL ;
    PORT
      LAYER M5 ;
        RECT 457.344 863.808 457.368 864.000 ;
    END
  END lo_d[47]
  PIN lo_d[48]
    DIRECTION OUTPUT ;
    USE SIGNAL ;
    PORT
      LAYER M3 ;
        RECT 458.241 863.808 458.265 864.000 ;
    END
  END lo_d[48]
  PIN lo_d[49]
    DIRECTION OUTPUT ;
    USE SIGNAL ;
    PORT
      LAYER M5 ;
        RECT 459.168 863.808 459.192 864.000 ;
    END
  END lo_d[49]
  PIN lo_d[50]
    DIRECTION OUTPUT ;
    USE SIGNAL ;
    PORT
      LAYER M3 ;
        RECT 460.077 863.808 460.101 864.000 ;
    END
  END lo_d[50]
  PIN lo_d[51]
    DIRECTION OUTPUT ;
    USE SIGNAL ;
    PORT
      LAYER M5 ;
        RECT 460.992 863.808 461.016 864.000 ;
    END
  END lo_d[51]
  PIN lo_d[52]
    DIRECTION OUTPUT ;
    USE SIGNAL ;
    PORT
      LAYER M3 ;
        RECT 461.877 863.808 461.901 864.000 ;
    END
  END lo_d[52]
  PIN lo_d[53]
    DIRECTION OUTPUT ;
    USE SIGNAL ;
    PORT
      LAYER M5 ;
        RECT 462.768 863.808 462.792 864.000 ;
    END
  END lo_d[53]
  PIN lo_d[54]
    DIRECTION OUTPUT ;
    USE SIGNAL ;
    PORT
      LAYER M3 ;
        RECT 463.677 863.808 463.701 864.000 ;
    END
  END lo_d[54]
  PIN lo_d[55]
    DIRECTION OUTPUT ;
    USE SIGNAL ;
    PORT
      LAYER M5 ;
        RECT 464.592 863.808 464.616 864.000 ;
    END
  END lo_d[55]
  PIN lo_d[56]
    DIRECTION OUTPUT ;
    USE SIGNAL ;
    PORT
      LAYER M3 ;
        RECT 465.477 863.808 465.501 864.000 ;
    END
  END lo_d[56]
  PIN lo_d[57]
    DIRECTION OUTPUT ;
    USE SIGNAL ;
    PORT
      LAYER M5 ;
        RECT 466.368 863.808 466.392 864.000 ;
    END
  END lo_d[57]
  PIN lo_d[58]
    DIRECTION OUTPUT ;
    USE SIGNAL ;
    PORT
      LAYER M3 ;
        RECT 467.277 863.808 467.301 864.000 ;
    END
  END lo_d[58]
  PIN lo_d[59]
    DIRECTION OUTPUT ;
    USE SIGNAL ;
    PORT
      LAYER M5 ;
        RECT 468.192 863.808 468.216 864.000 ;
    END
  END lo_d[59]
  PIN lo_d[60]
    DIRECTION OUTPUT ;
    USE SIGNAL ;
    PORT
      LAYER M3 ;
        RECT 469.113 863.808 469.137 864.000 ;
    END
  END lo_d[60]
  PIN lo_d[61]
    DIRECTION OUTPUT ;
    USE SIGNAL ;
    PORT
      LAYER M5 ;
        RECT 470.016 863.808 470.040 864.000 ;
    END
  END lo_d[61]
  PIN lo_d[62]
    DIRECTION OUTPUT ;
    USE SIGNAL ;
    PORT
      LAYER M3 ;
        RECT 470.913 863.808 470.937 864.000 ;
    END
  END lo_d[62]
  PIN lo_d[63]
    DIRECTION OUTPUT ;
    USE SIGNAL ;
    PORT
      LAYER M5 ;
        RECT 471.792 863.808 471.816 864.000 ;
    END
  END lo_d[63]
  PIN lo_d[64]
    DIRECTION OUTPUT ;
    USE SIGNAL ;
    PORT
      LAYER M3 ;
        RECT 472.713 863.808 472.737 864.000 ;
    END
  END lo_d[64]
  PIN lo_d[65]
    DIRECTION OUTPUT ;
    USE SIGNAL ;
    PORT
      LAYER M5 ;
        RECT 473.616 863.808 473.640 864.000 ;
    END
  END lo_d[65]
  PIN lo_d[66]
    DIRECTION OUTPUT ;
    USE SIGNAL ;
    PORT
      LAYER M3 ;
        RECT 474.513 863.808 474.537 864.000 ;
    END
  END lo_d[66]
  PIN lo_d[67]
    DIRECTION OUTPUT ;
    USE SIGNAL ;
    PORT
      LAYER M5 ;
        RECT 475.440 863.808 475.464 864.000 ;
    END
  END lo_d[67]
  PIN lo_d[68]
    DIRECTION OUTPUT ;
    USE SIGNAL ;
    PORT
      LAYER M3 ;
        RECT 476.313 863.808 476.337 864.000 ;
    END
  END lo_d[68]
  PIN lo_d[69]
    DIRECTION OUTPUT ;
    USE SIGNAL ;
    PORT
      LAYER M5 ;
        RECT 477.216 863.808 477.240 864.000 ;
    END
  END lo_d[69]
  PIN lo_d[70]
    DIRECTION OUTPUT ;
    USE SIGNAL ;
    PORT
      LAYER M3 ;
        RECT 478.149 863.808 478.173 864.000 ;
    END
  END lo_d[70]
  PIN lo_d[71]
    DIRECTION OUTPUT ;
    USE SIGNAL ;
    PORT
      LAYER M5 ;
        RECT 479.040 863.808 479.064 864.000 ;
    END
  END lo_d[71]
  PIN lo_d[72]
    DIRECTION OUTPUT ;
    USE SIGNAL ;
    PORT
      LAYER M3 ;
        RECT 479.949 863.808 479.973 864.000 ;
    END
  END lo_d[72]
  PIN lo_d[73]
    DIRECTION OUTPUT ;
    USE SIGNAL ;
    PORT
      LAYER M5 ;
        RECT 480.864 863.808 480.888 864.000 ;
    END
  END lo_d[73]
  PIN lo_d[74]
    DIRECTION OUTPUT ;
    USE SIGNAL ;
    PORT
      LAYER M3 ;
        RECT 481.749 863.808 481.773 864.000 ;
    END
  END lo_d[74]
  PIN lo_d[75]
    DIRECTION OUTPUT ;
    USE SIGNAL ;
    PORT
      LAYER M5 ;
        RECT 482.640 863.808 482.664 864.000 ;
    END
  END lo_d[75]
  PIN lo_d[76]
    DIRECTION OUTPUT ;
    USE SIGNAL ;
    PORT
      LAYER M3 ;
        RECT 483.549 863.808 483.573 864.000 ;
    END
  END lo_d[76]
  PIN lo_d[77]
    DIRECTION OUTPUT ;
    USE SIGNAL ;
    PORT
      LAYER M5 ;
        RECT 484.464 863.808 484.488 864.000 ;
    END
  END lo_d[77]
  PIN lo_d[78]
    DIRECTION OUTPUT ;
    USE SIGNAL ;
    PORT
      LAYER M3 ;
        RECT 485.349 863.808 485.373 864.000 ;
    END
  END lo_d[78]
  PIN lo_d[79]
    DIRECTION OUTPUT ;
    USE SIGNAL ;
    PORT
      LAYER M5 ;
        RECT 486.288 863.808 486.312 864.000 ;
    END
  END lo_d[79]
  PIN lo_d[80]
    DIRECTION OUTPUT ;
    USE SIGNAL ;
    PORT
      LAYER M3 ;
        RECT 487.185 863.808 487.209 864.000 ;
    END
  END lo_d[80]
  PIN lo_d[81]
    DIRECTION OUTPUT ;
    USE SIGNAL ;
    PORT
      LAYER M5 ;
        RECT 488.064 863.808 488.088 864.000 ;
    END
  END lo_d[81]
  PIN lo_d[82]
    DIRECTION OUTPUT ;
    USE SIGNAL ;
    PORT
      LAYER M3 ;
        RECT 488.985 863.808 489.009 864.000 ;
    END
  END lo_d[82]
  PIN lo_d[83]
    DIRECTION OUTPUT ;
    USE SIGNAL ;
    PORT
      LAYER M5 ;
        RECT 489.888 863.808 489.912 864.000 ;
    END
  END lo_d[83]
  PIN lo_d[84]
    DIRECTION OUTPUT ;
    USE SIGNAL ;
    PORT
      LAYER M3 ;
        RECT 490.785 863.808 490.809 864.000 ;
    END
  END lo_d[84]
  PIN lo_d[85]
    DIRECTION OUTPUT ;
    USE SIGNAL ;
    PORT
      LAYER M5 ;
        RECT 491.712 863.808 491.736 864.000 ;
    END
  END lo_d[85]
  PIN lo_d[86]
    DIRECTION OUTPUT ;
    USE SIGNAL ;
    PORT
      LAYER M3 ;
        RECT 492.585 863.808 492.609 864.000 ;
    END
  END lo_d[86]
  PIN lo_d[87]
    DIRECTION OUTPUT ;
    USE SIGNAL ;
    PORT
      LAYER M5 ;
        RECT 493.488 863.808 493.512 864.000 ;
    END
  END lo_d[87]
  PIN lo_d[88]
    DIRECTION OUTPUT ;
    USE SIGNAL ;
    PORT
      LAYER M3 ;
        RECT 494.385 863.808 494.409 864.000 ;
    END
  END lo_d[88]
  PIN lo_d[89]
    DIRECTION OUTPUT ;
    USE SIGNAL ;
    PORT
      LAYER M5 ;
        RECT 495.312 863.808 495.336 864.000 ;
    END
  END lo_d[89]
  PIN lo_d[90]
    DIRECTION OUTPUT ;
    USE SIGNAL ;
    PORT
      LAYER M3 ;
        RECT 496.221 863.808 496.245 864.000 ;
    END
  END lo_d[90]
  PIN lo_d[91]
    DIRECTION OUTPUT ;
    USE SIGNAL ;
    PORT
      LAYER M5 ;
        RECT 497.136 863.808 497.160 864.000 ;
    END
  END lo_d[91]
  PIN lo_d[92]
    DIRECTION OUTPUT ;
    USE SIGNAL ;
    PORT
      LAYER M3 ;
        RECT 498.021 863.808 498.045 864.000 ;
    END
  END lo_d[92]
  PIN lo_d[93]
    DIRECTION OUTPUT ;
    USE SIGNAL ;
    PORT
      LAYER M5 ;
        RECT 498.912 863.808 498.936 864.000 ;
    END
  END lo_d[93]
  PIN lo_d[94]
    DIRECTION OUTPUT ;
    USE SIGNAL ;
    PORT
      LAYER M3 ;
        RECT 499.821 863.808 499.845 864.000 ;
    END
  END lo_d[94]
  PIN lo_d[95]
    DIRECTION OUTPUT ;
    USE SIGNAL ;
    PORT
      LAYER M5 ;
        RECT 500.736 863.808 500.760 864.000 ;
    END
  END lo_d[95]
  PIN lo_d[96]
    DIRECTION OUTPUT ;
    USE SIGNAL ;
    PORT
      LAYER M3 ;
        RECT 501.621 863.808 501.645 864.000 ;
    END
  END lo_d[96]
  PIN lo_d[97]
    DIRECTION OUTPUT ;
    USE SIGNAL ;
    PORT
      LAYER M5 ;
        RECT 502.512 863.808 502.536 864.000 ;
    END
  END lo_d[97]
  PIN lo_d[98]
    DIRECTION OUTPUT ;
    USE SIGNAL ;
    PORT
      LAYER M3 ;
        RECT 503.421 863.808 503.445 864.000 ;
    END
  END lo_d[98]
  PIN lo_d[99]
    DIRECTION OUTPUT ;
    USE SIGNAL ;
    PORT
      LAYER M5 ;
        RECT 504.336 863.808 504.360 864.000 ;
    END
  END lo_d[99]
  PIN lo_d[100]
    DIRECTION OUTPUT ;
    USE SIGNAL ;
    PORT
      LAYER M3 ;
        RECT 505.257 863.808 505.281 864.000 ;
    END
  END lo_d[100]
  PIN lo_d[101]
    DIRECTION OUTPUT ;
    USE SIGNAL ;
    PORT
      LAYER M5 ;
        RECT 506.160 863.808 506.184 864.000 ;
    END
  END lo_d[101]
  PIN lo_d[102]
    DIRECTION OUTPUT ;
    USE SIGNAL ;
    PORT
      LAYER M3 ;
        RECT 507.057 863.808 507.081 864.000 ;
    END
  END lo_d[102]
  PIN lo_d[103]
    DIRECTION OUTPUT ;
    USE SIGNAL ;
    PORT
      LAYER M5 ;
        RECT 507.936 863.808 507.960 864.000 ;
    END
  END lo_d[103]
  PIN lo_d[104]
    DIRECTION OUTPUT ;
    USE SIGNAL ;
    PORT
      LAYER M3 ;
        RECT 508.857 863.808 508.881 864.000 ;
    END
  END lo_d[104]
  PIN lo_d[105]
    DIRECTION OUTPUT ;
    USE SIGNAL ;
    PORT
      LAYER M5 ;
        RECT 509.760 863.808 509.784 864.000 ;
    END
  END lo_d[105]
  PIN lo_d[106]
    DIRECTION OUTPUT ;
    USE SIGNAL ;
    PORT
      LAYER M3 ;
        RECT 510.657 863.808 510.681 864.000 ;
    END
  END lo_d[106]
  PIN lo_d[107]
    DIRECTION OUTPUT ;
    USE SIGNAL ;
    PORT
      LAYER M5 ;
        RECT 511.584 863.808 511.608 864.000 ;
    END
  END lo_d[107]
  PIN lo_d[108]
    DIRECTION OUTPUT ;
    USE SIGNAL ;
    PORT
      LAYER M3 ;
        RECT 512.457 863.808 512.481 864.000 ;
    END
  END lo_d[108]
  PIN lo_d[109]
    DIRECTION OUTPUT ;
    USE SIGNAL ;
    PORT
      LAYER M5 ;
        RECT 513.360 863.808 513.384 864.000 ;
    END
  END lo_d[109]
  PIN lo_d[110]
    DIRECTION OUTPUT ;
    USE SIGNAL ;
    PORT
      LAYER M3 ;
        RECT 514.293 863.808 514.317 864.000 ;
    END
  END lo_d[110]
  PIN lo_d[111]
    DIRECTION OUTPUT ;
    USE SIGNAL ;
    PORT
      LAYER M5 ;
        RECT 515.184 863.808 515.208 864.000 ;
    END
  END lo_d[111]
  PIN lo_d[112]
    DIRECTION OUTPUT ;
    USE SIGNAL ;
    PORT
      LAYER M3 ;
        RECT 516.093 863.808 516.117 864.000 ;
    END
  END lo_d[112]
  PIN lo_d[113]
    DIRECTION OUTPUT ;
    USE SIGNAL ;
    PORT
      LAYER M5 ;
        RECT 517.008 863.808 517.032 864.000 ;
    END
  END lo_d[113]
  PIN lo_d[114]
    DIRECTION OUTPUT ;
    USE SIGNAL ;
    PORT
      LAYER M3 ;
        RECT 517.893 863.808 517.917 864.000 ;
    END
  END lo_d[114]
  PIN lo_d[115]
    DIRECTION OUTPUT ;
    USE SIGNAL ;
    PORT
      LAYER M5 ;
        RECT 518.784 863.808 518.808 864.000 ;
    END
  END lo_d[115]
  PIN lo_d[116]
    DIRECTION OUTPUT ;
    USE SIGNAL ;
    PORT
      LAYER M3 ;
        RECT 519.693 863.808 519.717 864.000 ;
    END
  END lo_d[116]
  PIN lo_d[117]
    DIRECTION OUTPUT ;
    USE SIGNAL ;
    PORT
      LAYER M5 ;
        RECT 520.608 863.808 520.632 864.000 ;
    END
  END lo_d[117]
  PIN lo_d[118]
    DIRECTION OUTPUT ;
    USE SIGNAL ;
    PORT
      LAYER M3 ;
        RECT 521.493 863.808 521.517 864.000 ;
    END
  END lo_d[118]
  PIN lo_d[119]
    DIRECTION OUTPUT ;
    USE SIGNAL ;
    PORT
      LAYER M5 ;
        RECT 522.432 863.808 522.456 864.000 ;
    END
  END lo_d[119]
  PIN lo_d[120]
    DIRECTION OUTPUT ;
    USE SIGNAL ;
    PORT
      LAYER M3 ;
        RECT 523.329 863.808 523.353 864.000 ;
    END
  END lo_d[120]
  PIN lo_d[121]
    DIRECTION OUTPUT ;
    USE SIGNAL ;
    PORT
      LAYER M5 ;
        RECT 524.208 863.808 524.232 864.000 ;
    END
  END lo_d[121]
  PIN lo_d[122]
    DIRECTION OUTPUT ;
    USE SIGNAL ;
    PORT
      LAYER M3 ;
        RECT 525.129 863.808 525.153 864.000 ;
    END
  END lo_d[122]
  PIN lo_d[123]
    DIRECTION OUTPUT ;
    USE SIGNAL ;
    PORT
      LAYER M5 ;
        RECT 526.032 863.808 526.056 864.000 ;
    END
  END lo_d[123]
  PIN lo_d[124]
    DIRECTION OUTPUT ;
    USE SIGNAL ;
    PORT
      LAYER M3 ;
        RECT 526.929 863.808 526.953 864.000 ;
    END
  END lo_d[124]
  PIN lo_d[125]
    DIRECTION OUTPUT ;
    USE SIGNAL ;
    PORT
      LAYER M5 ;
        RECT 527.856 863.808 527.880 864.000 ;
    END
  END lo_d[125]
  PIN lo_d[126]
    DIRECTION OUTPUT ;
    USE SIGNAL ;
    PORT
      LAYER M3 ;
        RECT 528.729 863.808 528.753 864.000 ;
    END
  END lo_d[126]
  PIN lo_d[127]
    DIRECTION OUTPUT ;
    USE SIGNAL ;
    PORT
      LAYER M5 ;
        RECT 529.632 863.808 529.656 864.000 ;
    END
  END lo_d[127]
  PIN lo_d[128]
    DIRECTION OUTPUT ;
    USE SIGNAL ;
    PORT
      LAYER M3 ;
        RECT 530.529 863.808 530.553 864.000 ;
    END
  END lo_d[128]
  PIN lo_d[129]
    DIRECTION OUTPUT ;
    USE SIGNAL ;
    PORT
      LAYER M5 ;
        RECT 531.456 863.808 531.480 864.000 ;
    END
  END lo_d[129]
  PIN lo_d[130]
    DIRECTION OUTPUT ;
    USE SIGNAL ;
    PORT
      LAYER M3 ;
        RECT 532.365 863.808 532.389 864.000 ;
    END
  END lo_d[130]
  PIN lo_d[131]
    DIRECTION OUTPUT ;
    USE SIGNAL ;
    PORT
      LAYER M5 ;
        RECT 533.280 863.808 533.304 864.000 ;
    END
  END lo_d[131]
  PIN lo_d[132]
    DIRECTION OUTPUT ;
    USE SIGNAL ;
    PORT
      LAYER M3 ;
        RECT 534.165 863.808 534.189 864.000 ;
    END
  END lo_d[132]
  PIN lo_d[133]
    DIRECTION OUTPUT ;
    USE SIGNAL ;
    PORT
      LAYER M5 ;
        RECT 535.056 863.808 535.080 864.000 ;
    END
  END lo_d[133]
  PIN lo_d[134]
    DIRECTION OUTPUT ;
    USE SIGNAL ;
    PORT
      LAYER M3 ;
        RECT 535.965 863.808 535.989 864.000 ;
    END
  END lo_d[134]
  PIN lo_d[135]
    DIRECTION OUTPUT ;
    USE SIGNAL ;
    PORT
      LAYER M5 ;
        RECT 536.880 863.808 536.904 864.000 ;
    END
  END lo_d[135]
  PIN lo_d[136]
    DIRECTION OUTPUT ;
    USE SIGNAL ;
    PORT
      LAYER M3 ;
        RECT 537.765 863.808 537.789 864.000 ;
    END
  END lo_d[136]
  PIN lo_d[137]
    DIRECTION OUTPUT ;
    USE SIGNAL ;
    PORT
      LAYER M5 ;
        RECT 538.656 863.808 538.680 864.000 ;
    END
  END lo_d[137]
  PIN lo_d[138]
    DIRECTION OUTPUT ;
    USE SIGNAL ;
    PORT
      LAYER M3 ;
        RECT 539.565 863.808 539.589 864.000 ;
    END
  END lo_d[138]
  PIN lo_d[139]
    DIRECTION OUTPUT ;
    USE SIGNAL ;
    PORT
      LAYER M5 ;
        RECT 540.480 863.808 540.504 864.000 ;
    END
  END lo_d[139]
  PIN lo_d[140]
    DIRECTION OUTPUT ;
    USE SIGNAL ;
    PORT
      LAYER M3 ;
        RECT 541.401 863.808 541.425 864.000 ;
    END
  END lo_d[140]
  PIN lo_d[141]
    DIRECTION OUTPUT ;
    USE SIGNAL ;
    PORT
      LAYER M5 ;
        RECT 542.304 863.808 542.328 864.000 ;
    END
  END lo_d[141]
  PIN lo_d[142]
    DIRECTION OUTPUT ;
    USE SIGNAL ;
    PORT
      LAYER M3 ;
        RECT 543.201 863.808 543.225 864.000 ;
    END
  END lo_d[142]
  PIN lo_d[143]
    DIRECTION OUTPUT ;
    USE SIGNAL ;
    PORT
      LAYER M5 ;
        RECT 544.080 863.808 544.104 864.000 ;
    END
  END lo_d[143]
  PIN lo_d[144]
    DIRECTION OUTPUT ;
    USE SIGNAL ;
    PORT
      LAYER M3 ;
        RECT 545.001 863.808 545.025 864.000 ;
    END
  END lo_d[144]
  PIN lo_d[145]
    DIRECTION OUTPUT ;
    USE SIGNAL ;
    PORT
      LAYER M5 ;
        RECT 545.904 863.808 545.928 864.000 ;
    END
  END lo_d[145]
  PIN lo_d[146]
    DIRECTION OUTPUT ;
    USE SIGNAL ;
    PORT
      LAYER M3 ;
        RECT 546.801 863.808 546.825 864.000 ;
    END
  END lo_d[146]
  PIN lo_d[147]
    DIRECTION OUTPUT ;
    USE SIGNAL ;
    PORT
      LAYER M5 ;
        RECT 547.728 863.808 547.752 864.000 ;
    END
  END lo_d[147]
  PIN lo_d[148]
    DIRECTION OUTPUT ;
    USE SIGNAL ;
    PORT
      LAYER M3 ;
        RECT 548.601 863.808 548.625 864.000 ;
    END
  END lo_d[148]
  PIN lo_d[149]
    DIRECTION OUTPUT ;
    USE SIGNAL ;
    PORT
      LAYER M5 ;
        RECT 549.504 863.808 549.528 864.000 ;
    END
  END lo_d[149]
  PIN lo_d[150]
    DIRECTION OUTPUT ;
    USE SIGNAL ;
    PORT
      LAYER M3 ;
        RECT 550.437 863.808 550.461 864.000 ;
    END
  END lo_d[150]
  PIN lo_d[151]
    DIRECTION OUTPUT ;
    USE SIGNAL ;
    PORT
      LAYER M5 ;
        RECT 551.328 863.808 551.352 864.000 ;
    END
  END lo_d[151]
  PIN lo_d[152]
    DIRECTION OUTPUT ;
    USE SIGNAL ;
    PORT
      LAYER M3 ;
        RECT 552.237 863.808 552.261 864.000 ;
    END
  END lo_d[152]
  PIN lo_d[153]
    DIRECTION OUTPUT ;
    USE SIGNAL ;
    PORT
      LAYER M5 ;
        RECT 553.152 863.808 553.176 864.000 ;
    END
  END lo_d[153]
  PIN lo_d[154]
    DIRECTION OUTPUT ;
    USE SIGNAL ;
    PORT
      LAYER M3 ;
        RECT 554.037 863.808 554.061 864.000 ;
    END
  END lo_d[154]
  PIN lo_d[155]
    DIRECTION OUTPUT ;
    USE SIGNAL ;
    PORT
      LAYER M5 ;
        RECT 554.928 863.808 554.952 864.000 ;
    END
  END lo_d[155]
  PIN lo_d[156]
    DIRECTION OUTPUT ;
    USE SIGNAL ;
    PORT
      LAYER M3 ;
        RECT 555.837 863.808 555.861 864.000 ;
    END
  END lo_d[156]
  PIN lo_d[157]
    DIRECTION OUTPUT ;
    USE SIGNAL ;
    PORT
      LAYER M5 ;
        RECT 556.752 863.808 556.776 864.000 ;
    END
  END lo_d[157]
  PIN lo_d[158]
    DIRECTION OUTPUT ;
    USE SIGNAL ;
    PORT
      LAYER M3 ;
        RECT 557.673 863.808 557.697 864.000 ;
    END
  END lo_d[158]
  PIN lo_d[159]
    DIRECTION OUTPUT ;
    USE SIGNAL ;
    PORT
      LAYER M5 ;
        RECT 558.576 863.808 558.600 864.000 ;
    END
  END lo_d[159]
  PIN lo_d[160]
    DIRECTION OUTPUT ;
    USE SIGNAL ;
    PORT
      LAYER M3 ;
        RECT 559.473 863.808 559.497 864.000 ;
    END
  END lo_d[160]
  PIN lo_d[161]
    DIRECTION OUTPUT ;
    USE SIGNAL ;
    PORT
      LAYER M5 ;
        RECT 560.352 863.808 560.376 864.000 ;
    END
  END lo_d[161]
  PIN lo_d[162]
    DIRECTION OUTPUT ;
    USE SIGNAL ;
    PORT
      LAYER M3 ;
        RECT 561.273 863.808 561.297 864.000 ;
    END
  END lo_d[162]
  PIN lo_d[163]
    DIRECTION OUTPUT ;
    USE SIGNAL ;
    PORT
      LAYER M5 ;
        RECT 562.176 863.808 562.200 864.000 ;
    END
  END lo_d[163]
  PIN lo_d[164]
    DIRECTION OUTPUT ;
    USE SIGNAL ;
    PORT
      LAYER M3 ;
        RECT 563.073 863.808 563.097 864.000 ;
    END
  END lo_d[164]
  PIN lo_d[165]
    DIRECTION OUTPUT ;
    USE SIGNAL ;
    PORT
      LAYER M5 ;
        RECT 564.000 863.808 564.024 864.000 ;
    END
  END lo_d[165]
  PIN lo_d[166]
    DIRECTION OUTPUT ;
    USE SIGNAL ;
    PORT
      LAYER M3 ;
        RECT 564.873 863.808 564.897 864.000 ;
    END
  END lo_d[166]
  PIN lo_d[167]
    DIRECTION OUTPUT ;
    USE SIGNAL ;
    PORT
      LAYER M5 ;
        RECT 565.776 863.808 565.800 864.000 ;
    END
  END lo_d[167]
  PIN lo_d[168]
    DIRECTION OUTPUT ;
    USE SIGNAL ;
    PORT
      LAYER M3 ;
        RECT 566.709 863.808 566.733 864.000 ;
    END
  END lo_d[168]
  PIN lo_d[169]
    DIRECTION OUTPUT ;
    USE SIGNAL ;
    PORT
      LAYER M5 ;
        RECT 567.600 863.808 567.624 864.000 ;
    END
  END lo_d[169]
  PIN lo_d[170]
    DIRECTION OUTPUT ;
    USE SIGNAL ;
    PORT
      LAYER M3 ;
        RECT 568.509 863.808 568.533 864.000 ;
    END
  END lo_d[170]
  PIN lo_d[171]
    DIRECTION OUTPUT ;
    USE SIGNAL ;
    PORT
      LAYER M5 ;
        RECT 569.424 863.808 569.448 864.000 ;
    END
  END lo_d[171]
  PIN lo_d[172]
    DIRECTION OUTPUT ;
    USE SIGNAL ;
    PORT
      LAYER M3 ;
        RECT 570.309 863.808 570.333 864.000 ;
    END
  END lo_d[172]
  PIN lo_d[173]
    DIRECTION OUTPUT ;
    USE SIGNAL ;
    PORT
      LAYER M5 ;
        RECT 571.200 863.808 571.224 864.000 ;
    END
  END lo_d[173]
  PIN lo_d[174]
    DIRECTION OUTPUT ;
    USE SIGNAL ;
    PORT
      LAYER M3 ;
        RECT 572.109 863.808 572.133 864.000 ;
    END
  END lo_d[174]
  PIN lo_d[175]
    DIRECTION OUTPUT ;
    USE SIGNAL ;
    PORT
      LAYER M5 ;
        RECT 573.024 863.808 573.048 864.000 ;
    END
  END lo_d[175]
  PIN lo_d[176]
    DIRECTION OUTPUT ;
    USE SIGNAL ;
    PORT
      LAYER M3 ;
        RECT 573.909 863.808 573.933 864.000 ;
    END
  END lo_d[176]
  PIN lo_d[177]
    DIRECTION OUTPUT ;
    USE SIGNAL ;
    PORT
      LAYER M5 ;
        RECT 574.800 863.808 574.824 864.000 ;
    END
  END lo_d[177]
  PIN lo_d[178]
    DIRECTION OUTPUT ;
    USE SIGNAL ;
    PORT
      LAYER M3 ;
        RECT 575.745 863.808 575.769 864.000 ;
    END
  END lo_d[178]
  PIN lo_d[179]
    DIRECTION OUTPUT ;
    USE SIGNAL ;
    PORT
      LAYER M5 ;
        RECT 576.624 863.808 576.648 864.000 ;
    END
  END lo_d[179]
  PIN lo_d[180]
    DIRECTION OUTPUT ;
    USE SIGNAL ;
    PORT
      LAYER M3 ;
        RECT 577.545 863.808 577.569 864.000 ;
    END
  END lo_d[180]
  PIN lo_d[181]
    DIRECTION OUTPUT ;
    USE SIGNAL ;
    PORT
      LAYER M5 ;
        RECT 578.448 863.808 578.472 864.000 ;
    END
  END lo_d[181]
  PIN lo_d[182]
    DIRECTION OUTPUT ;
    USE SIGNAL ;
    PORT
      LAYER M3 ;
        RECT 579.345 863.808 579.369 864.000 ;
    END
  END lo_d[182]
  PIN lo_d[183]
    DIRECTION OUTPUT ;
    USE SIGNAL ;
    PORT
      LAYER M5 ;
        RECT 580.224 863.808 580.248 864.000 ;
    END
  END lo_d[183]
  PIN lo_d[184]
    DIRECTION OUTPUT ;
    USE SIGNAL ;
    PORT
      LAYER M3 ;
        RECT 581.145 863.808 581.169 864.000 ;
    END
  END lo_d[184]
  PIN lo_d[185]
    DIRECTION OUTPUT ;
    USE SIGNAL ;
    PORT
      LAYER M5 ;
        RECT 582.048 863.808 582.072 864.000 ;
    END
  END lo_d[185]
  PIN lo_d[186]
    DIRECTION OUTPUT ;
    USE SIGNAL ;
    PORT
      LAYER M3 ;
        RECT 582.945 863.808 582.969 864.000 ;
    END
  END lo_d[186]
  PIN lo_d[187]
    DIRECTION OUTPUT ;
    USE SIGNAL ;
    PORT
      LAYER M5 ;
        RECT 583.872 863.808 583.896 864.000 ;
    END
  END lo_d[187]
  PIN lo_d[188]
    DIRECTION OUTPUT ;
    USE SIGNAL ;
    PORT
      LAYER M3 ;
        RECT 584.781 863.808 584.805 864.000 ;
    END
  END lo_d[188]
  PIN lo_d[189]
    DIRECTION OUTPUT ;
    USE SIGNAL ;
    PORT
      LAYER M5 ;
        RECT 585.648 863.808 585.672 864.000 ;
    END
  END lo_d[189]
  PIN lo_d[190]
    DIRECTION OUTPUT ;
    USE SIGNAL ;
    PORT
      LAYER M3 ;
        RECT 586.581 863.808 586.605 864.000 ;
    END
  END lo_d[190]
  PIN lo_d[191]
    DIRECTION OUTPUT ;
    USE SIGNAL ;
    PORT
      LAYER M5 ;
        RECT 587.472 863.808 587.496 864.000 ;
    END
  END lo_d[191]
  PIN lo_d[192]
    DIRECTION OUTPUT ;
    USE SIGNAL ;
    PORT
      LAYER M3 ;
        RECT 588.381 863.808 588.405 864.000 ;
    END
  END lo_d[192]
  PIN lo_d[193]
    DIRECTION OUTPUT ;
    USE SIGNAL ;
    PORT
      LAYER M5 ;
        RECT 589.296 863.808 589.320 864.000 ;
    END
  END lo_d[193]
  PIN lo_d[194]
    DIRECTION OUTPUT ;
    USE SIGNAL ;
    PORT
      LAYER M3 ;
        RECT 590.181 863.808 590.205 864.000 ;
    END
  END lo_d[194]
  PIN lo_d[195]
    DIRECTION OUTPUT ;
    USE SIGNAL ;
    PORT
      LAYER M5 ;
        RECT 591.072 863.808 591.096 864.000 ;
    END
  END lo_d[195]
  PIN lo_d[196]
    DIRECTION OUTPUT ;
    USE SIGNAL ;
    PORT
      LAYER M3 ;
        RECT 591.981 863.808 592.005 864.000 ;
    END
  END lo_d[196]
  PIN lo_d[197]
    DIRECTION OUTPUT ;
    USE SIGNAL ;
    PORT
      LAYER M5 ;
        RECT 592.896 863.808 592.920 864.000 ;
    END
  END lo_d[197]
  PIN lo_d[198]
    DIRECTION OUTPUT ;
    USE SIGNAL ;
    PORT
      LAYER M3 ;
        RECT 593.817 863.808 593.841 864.000 ;
    END
  END lo_d[198]
  PIN lo_d[199]
    DIRECTION OUTPUT ;
    USE SIGNAL ;
    PORT
      LAYER M5 ;
        RECT 594.720 863.808 594.744 864.000 ;
    END
  END lo_d[199]
  PIN lo_d[200]
    DIRECTION OUTPUT ;
    USE SIGNAL ;
    PORT
      LAYER M3 ;
        RECT 595.617 863.808 595.641 864.000 ;
    END
  END lo_d[200]
  PIN lo_d[201]
    DIRECTION OUTPUT ;
    USE SIGNAL ;
    PORT
      LAYER M5 ;
        RECT 596.496 863.808 596.520 864.000 ;
    END
  END lo_d[201]
  PIN lo_d[202]
    DIRECTION OUTPUT ;
    USE SIGNAL ;
    PORT
      LAYER M3 ;
        RECT 597.417 863.808 597.441 864.000 ;
    END
  END lo_d[202]
  PIN lo_d[203]
    DIRECTION OUTPUT ;
    USE SIGNAL ;
    PORT
      LAYER M5 ;
        RECT 598.320 863.808 598.344 864.000 ;
    END
  END lo_d[203]
  PIN lo_d[204]
    DIRECTION OUTPUT ;
    USE SIGNAL ;
    PORT
      LAYER M3 ;
        RECT 599.217 863.808 599.241 864.000 ;
    END
  END lo_d[204]
  PIN lo_d[205]
    DIRECTION OUTPUT ;
    USE SIGNAL ;
    PORT
      LAYER M5 ;
        RECT 600.144 863.808 600.168 864.000 ;
    END
  END lo_d[205]
  PIN lo_d[206]
    DIRECTION OUTPUT ;
    USE SIGNAL ;
    PORT
      LAYER M3 ;
        RECT 601.017 863.808 601.041 864.000 ;
    END
  END lo_d[206]
  PIN lo_d[207]
    DIRECTION OUTPUT ;
    USE SIGNAL ;
    PORT
      LAYER M5 ;
        RECT 601.920 863.808 601.944 864.000 ;
    END
  END lo_d[207]
  PIN lo_d[208]
    DIRECTION OUTPUT ;
    USE SIGNAL ;
    PORT
      LAYER M3 ;
        RECT 602.853 863.808 602.877 864.000 ;
    END
  END lo_d[208]
  PIN lo_d[209]
    DIRECTION OUTPUT ;
    USE SIGNAL ;
    PORT
      LAYER M5 ;
        RECT 603.744 863.808 603.768 864.000 ;
    END
  END lo_d[209]
  PIN lo_d[210]
    DIRECTION OUTPUT ;
    USE SIGNAL ;
    PORT
      LAYER M3 ;
        RECT 604.653 863.808 604.677 864.000 ;
    END
  END lo_d[210]
  PIN lo_d[211]
    DIRECTION OUTPUT ;
    USE SIGNAL ;
    PORT
      LAYER M5 ;
        RECT 605.568 863.808 605.592 864.000 ;
    END
  END lo_d[211]
  PIN lo_d[212]
    DIRECTION OUTPUT ;
    USE SIGNAL ;
    PORT
      LAYER M3 ;
        RECT 606.453 863.808 606.477 864.000 ;
    END
  END lo_d[212]
  PIN lo_d[213]
    DIRECTION OUTPUT ;
    USE SIGNAL ;
    PORT
      LAYER M5 ;
        RECT 607.344 863.808 607.368 864.000 ;
    END
  END lo_d[213]
  PIN lo_d[214]
    DIRECTION OUTPUT ;
    USE SIGNAL ;
    PORT
      LAYER M3 ;
        RECT 608.253 863.808 608.277 864.000 ;
    END
  END lo_d[214]
  PIN lo_d[215]
    DIRECTION OUTPUT ;
    USE SIGNAL ;
    PORT
      LAYER M5 ;
        RECT 609.168 863.808 609.192 864.000 ;
    END
  END lo_d[215]
  PIN lo_d[216]
    DIRECTION OUTPUT ;
    USE SIGNAL ;
    PORT
      LAYER M3 ;
        RECT 610.053 863.808 610.077 864.000 ;
    END
  END lo_d[216]
  PIN lo_d[217]
    DIRECTION OUTPUT ;
    USE SIGNAL ;
    PORT
      LAYER M5 ;
        RECT 610.992 863.808 611.016 864.000 ;
    END
  END lo_d[217]
  PIN lo_d[218]
    DIRECTION OUTPUT ;
    USE SIGNAL ;
    PORT
      LAYER M3 ;
        RECT 611.889 863.808 611.913 864.000 ;
    END
  END lo_d[218]
  PIN lo_d[219]
    DIRECTION OUTPUT ;
    USE SIGNAL ;
    PORT
      LAYER M5 ;
        RECT 612.768 863.808 612.792 864.000 ;
    END
  END lo_d[219]
  PIN lo_d[220]
    DIRECTION OUTPUT ;
    USE SIGNAL ;
    PORT
      LAYER M3 ;
        RECT 613.689 863.808 613.713 864.000 ;
    END
  END lo_d[220]
  PIN lo_d[221]
    DIRECTION OUTPUT ;
    USE SIGNAL ;
    PORT
      LAYER M5 ;
        RECT 614.592 863.808 614.616 864.000 ;
    END
  END lo_d[221]
  PIN lo_d[222]
    DIRECTION OUTPUT ;
    USE SIGNAL ;
    PORT
      LAYER M3 ;
        RECT 615.489 863.808 615.513 864.000 ;
    END
  END lo_d[222]
  PIN lo_d[223]
    DIRECTION OUTPUT ;
    USE SIGNAL ;
    PORT
      LAYER M5 ;
        RECT 616.368 863.808 616.392 864.000 ;
    END
  END lo_d[223]
  PIN lo_d[224]
    DIRECTION OUTPUT ;
    USE SIGNAL ;
    PORT
      LAYER M3 ;
        RECT 617.289 863.808 617.313 864.000 ;
    END
  END lo_d[224]
  PIN lo_d[225]
    DIRECTION OUTPUT ;
    USE SIGNAL ;
    PORT
      LAYER M5 ;
        RECT 618.192 863.808 618.216 864.000 ;
    END
  END lo_d[225]
  PIN lo_d[226]
    DIRECTION OUTPUT ;
    USE SIGNAL ;
    PORT
      LAYER M3 ;
        RECT 619.089 863.808 619.113 864.000 ;
    END
  END lo_d[226]
  PIN lo_d[227]
    DIRECTION OUTPUT ;
    USE SIGNAL ;
    PORT
      LAYER M5 ;
        RECT 620.016 863.808 620.040 864.000 ;
    END
  END lo_d[227]
  PIN lo_d[228]
    DIRECTION OUTPUT ;
    USE SIGNAL ;
    PORT
      LAYER M3 ;
        RECT 620.925 863.808 620.949 864.000 ;
    END
  END lo_d[228]
  PIN lo_d[229]
    DIRECTION OUTPUT ;
    USE SIGNAL ;
    PORT
      LAYER M5 ;
        RECT 621.792 863.808 621.816 864.000 ;
    END
  END lo_d[229]
  PIN lo_d[230]
    DIRECTION OUTPUT ;
    USE SIGNAL ;
    PORT
      LAYER M3 ;
        RECT 622.725 863.808 622.749 864.000 ;
    END
  END lo_d[230]
  PIN lo_d[231]
    DIRECTION OUTPUT ;
    USE SIGNAL ;
    PORT
      LAYER M5 ;
        RECT 623.616 863.808 623.640 864.000 ;
    END
  END lo_d[231]
  PIN lo_d[232]
    DIRECTION OUTPUT ;
    USE SIGNAL ;
    PORT
      LAYER M3 ;
        RECT 624.525 863.808 624.549 864.000 ;
    END
  END lo_d[232]
  PIN lo_d[233]
    DIRECTION OUTPUT ;
    USE SIGNAL ;
    PORT
      LAYER M5 ;
        RECT 625.440 863.808 625.464 864.000 ;
    END
  END lo_d[233]
  PIN lo_d[234]
    DIRECTION OUTPUT ;
    USE SIGNAL ;
    PORT
      LAYER M3 ;
        RECT 626.325 863.808 626.349 864.000 ;
    END
  END lo_d[234]
  PIN lo_d[235]
    DIRECTION OUTPUT ;
    USE SIGNAL ;
    PORT
      LAYER M5 ;
        RECT 627.216 863.808 627.240 864.000 ;
    END
  END lo_d[235]
  PIN lo_d[236]
    DIRECTION OUTPUT ;
    USE SIGNAL ;
    PORT
      LAYER M3 ;
        RECT 628.125 863.808 628.149 864.000 ;
    END
  END lo_d[236]
  PIN lo_d[237]
    DIRECTION OUTPUT ;
    USE SIGNAL ;
    PORT
      LAYER M5 ;
        RECT 629.040 863.808 629.064 864.000 ;
    END
  END lo_d[237]
  PIN lo_d[238]
    DIRECTION OUTPUT ;
    USE SIGNAL ;
    PORT
      LAYER M3 ;
        RECT 629.961 863.808 629.985 864.000 ;
    END
  END lo_d[238]
  PIN lo_d[239]
    DIRECTION OUTPUT ;
    USE SIGNAL ;
    PORT
      LAYER M5 ;
        RECT 630.864 863.808 630.888 864.000 ;
    END
  END lo_d[239]
  PIN lo_d[240]
    DIRECTION OUTPUT ;
    USE SIGNAL ;
    PORT
      LAYER M3 ;
        RECT 631.761 863.808 631.785 864.000 ;
    END
  END lo_d[240]
  PIN lo_d[241]
    DIRECTION OUTPUT ;
    USE SIGNAL ;
    PORT
      LAYER M5 ;
        RECT 632.640 863.808 632.664 864.000 ;
    END
  END lo_d[241]
  PIN lo_d[242]
    DIRECTION OUTPUT ;
    USE SIGNAL ;
    PORT
      LAYER M3 ;
        RECT 633.561 863.808 633.585 864.000 ;
    END
  END lo_d[242]
  PIN lo_d[243]
    DIRECTION OUTPUT ;
    USE SIGNAL ;
    PORT
      LAYER M5 ;
        RECT 634.464 863.808 634.488 864.000 ;
    END
  END lo_d[243]
  PIN lo_d[244]
    DIRECTION OUTPUT ;
    USE SIGNAL ;
    PORT
      LAYER M3 ;
        RECT 635.361 863.808 635.385 864.000 ;
    END
  END lo_d[244]
  PIN lo_d[245]
    DIRECTION OUTPUT ;
    USE SIGNAL ;
    PORT
      LAYER M5 ;
        RECT 636.288 863.808 636.312 864.000 ;
    END
  END lo_d[245]
  PIN lo_d[246]
    DIRECTION OUTPUT ;
    USE SIGNAL ;
    PORT
      LAYER M3 ;
        RECT 637.161 863.808 637.185 864.000 ;
    END
  END lo_d[246]
  PIN lo_d[247]
    DIRECTION OUTPUT ;
    USE SIGNAL ;
    PORT
      LAYER M5 ;
        RECT 638.064 863.808 638.088 864.000 ;
    END
  END lo_d[247]
  PIN lo_d[248]
    DIRECTION OUTPUT ;
    USE SIGNAL ;
    PORT
      LAYER M3 ;
        RECT 638.997 863.808 639.021 864.000 ;
    END
  END lo_d[248]
  PIN lo_d[249]
    DIRECTION OUTPUT ;
    USE SIGNAL ;
    PORT
      LAYER M5 ;
        RECT 639.888 863.808 639.912 864.000 ;
    END
  END lo_d[249]
  PIN lo_d[250]
    DIRECTION OUTPUT ;
    USE SIGNAL ;
    PORT
      LAYER M3 ;
        RECT 640.797 863.808 640.821 864.000 ;
    END
  END lo_d[250]
  PIN lo_d[251]
    DIRECTION OUTPUT ;
    USE SIGNAL ;
    PORT
      LAYER M5 ;
        RECT 641.712 863.808 641.736 864.000 ;
    END
  END lo_d[251]
  PIN lo_d[252]
    DIRECTION OUTPUT ;
    USE SIGNAL ;
    PORT
      LAYER M3 ;
        RECT 642.597 863.808 642.621 864.000 ;
    END
  END lo_d[252]
  PIN lo_d[253]
    DIRECTION OUTPUT ;
    USE SIGNAL ;
    PORT
      LAYER M5 ;
        RECT 643.488 863.808 643.512 864.000 ;
    END
  END lo_d[253]
  PIN lo_d[254]
    DIRECTION OUTPUT ;
    USE SIGNAL ;
    PORT
      LAYER M3 ;
        RECT 644.397 863.808 644.421 864.000 ;
    END
  END lo_d[254]
  PIN lo_d[255]
    DIRECTION OUTPUT ;
    USE SIGNAL ;
    PORT
      LAYER M5 ;
        RECT 645.312 863.808 645.336 864.000 ;
    END
  END lo_d[255]
  PIN cw_v[0]
    DIRECTION INPUT ;
    USE SIGNAL ;
    PORT
      LAYER M3 ;
        RECT 646.413 863.808 646.437 864.000 ;
    END
  END cw_v[0]
  PIN cw_v[1]
    DIRECTION INPUT ;
    USE SIGNAL ;
    PORT
      LAYER M5 ;
        RECT 647.712 863.808 647.736 864.000 ;
    END
  END cw_v[1]
  PIN cw_a[0]
    DIRECTION INPUT ;
    USE SIGNAL ;
    PORT
      LAYER M3 ;
        RECT 648.825 863.808 648.849 864.000 ;
    END
  END cw_a[0]
  PIN cw_a[1]
    DIRECTION INPUT ;
    USE SIGNAL ;
    PORT
      LAYER M5 ;
        RECT 649.728 863.808 649.752 864.000 ;
    END
  END cw_a[1]
  PIN cw_a[2]
    DIRECTION INPUT ;
    USE SIGNAL ;
    PORT
      LAYER M3 ;
        RECT 650.661 863.808 650.685 864.000 ;
    END
  END cw_a[2]
  PIN cw_a[3]
    DIRECTION INPUT ;
    USE SIGNAL ;
    PORT
      LAYER M5 ;
        RECT 651.552 863.808 651.576 864.000 ;
    END
  END cw_a[3]
  PIN cw_a[4]
    DIRECTION INPUT ;
    USE SIGNAL ;
    PORT
      LAYER M3 ;
        RECT 652.461 863.808 652.485 864.000 ;
    END
  END cw_a[4]
  PIN cw_a[5]
    DIRECTION INPUT ;
    USE SIGNAL ;
    PORT
      LAYER M5 ;
        RECT 653.376 863.808 653.400 864.000 ;
    END
  END cw_a[5]
  PIN cw_a[6]
    DIRECTION INPUT ;
    USE SIGNAL ;
    PORT
      LAYER M3 ;
        RECT 654.261 863.808 654.285 864.000 ;
    END
  END cw_a[6]
  PIN cw_a[7]
    DIRECTION INPUT ;
    USE SIGNAL ;
    PORT
      LAYER M5 ;
        RECT 655.152 863.808 655.176 864.000 ;
    END
  END cw_a[7]
  PIN cw_a[8]
    DIRECTION INPUT ;
    USE SIGNAL ;
    PORT
      LAYER M3 ;
        RECT 656.061 863.808 656.085 864.000 ;
    END
  END cw_a[8]
  PIN cw_a[9]
    DIRECTION INPUT ;
    USE SIGNAL ;
    PORT
      LAYER M5 ;
        RECT 656.976 863.808 657.000 864.000 ;
    END
  END cw_a[9]
  PIN cw_a[10]
    DIRECTION INPUT ;
    USE SIGNAL ;
    PORT
      LAYER M3 ;
        RECT 657.861 863.808 657.885 864.000 ;
    END
  END cw_a[10]
  PIN cw_a[11]
    DIRECTION INPUT ;
    USE SIGNAL ;
    PORT
      LAYER M5 ;
        RECT 658.800 863.808 658.824 864.000 ;
    END
  END cw_a[11]
  PIN cw_a[12]
    DIRECTION INPUT ;
    USE SIGNAL ;
    PORT
      LAYER M3 ;
        RECT 659.697 863.808 659.721 864.000 ;
    END
  END cw_a[12]
  PIN cw_a[13]
    DIRECTION INPUT ;
    USE SIGNAL ;
    PORT
      LAYER M5 ;
        RECT 660.576 863.808 660.600 864.000 ;
    END
  END cw_a[13]
  PIN cw_a[14]
    DIRECTION INPUT ;
    USE SIGNAL ;
    PORT
      LAYER M3 ;
        RECT 661.497 863.808 661.521 864.000 ;
    END
  END cw_a[14]
  PIN cw_a[15]
    DIRECTION INPUT ;
    USE SIGNAL ;
    PORT
      LAYER M5 ;
        RECT 662.400 863.808 662.424 864.000 ;
    END
  END cw_a[15]
  PIN cw_a[16]
    DIRECTION INPUT ;
    USE SIGNAL ;
    PORT
      LAYER M3 ;
        RECT 663.297 863.808 663.321 864.000 ;
    END
  END cw_a[16]
  PIN cw_a[17]
    DIRECTION INPUT ;
    USE SIGNAL ;
    PORT
      LAYER M5 ;
        RECT 664.224 863.808 664.248 864.000 ;
    END
  END cw_a[17]
  PIN cw_a[18]
    DIRECTION INPUT ;
    USE SIGNAL ;
    PORT
      LAYER M3 ;
        RECT 665.097 863.808 665.121 864.000 ;
    END
  END cw_a[18]
  PIN cw_a[19]
    DIRECTION INPUT ;
    USE SIGNAL ;
    PORT
      LAYER M5 ;
        RECT 666.000 863.808 666.024 864.000 ;
    END
  END cw_a[19]
  PIN cw_a[20]
    DIRECTION INPUT ;
    USE SIGNAL ;
    PORT
      LAYER M3 ;
        RECT 666.897 863.808 666.921 864.000 ;
    END
  END cw_a[20]
  PIN cw_a[21]
    DIRECTION INPUT ;
    USE SIGNAL ;
    PORT
      LAYER M5 ;
        RECT 667.824 863.808 667.848 864.000 ;
    END
  END cw_a[21]
  PIN cw_a[22]
    DIRECTION INPUT ;
    USE SIGNAL ;
    PORT
      LAYER M3 ;
        RECT 668.733 863.808 668.757 864.000 ;
    END
  END cw_a[22]
  PIN cw_a[23]
    DIRECTION INPUT ;
    USE SIGNAL ;
    PORT
      LAYER M5 ;
        RECT 669.648 863.808 669.672 864.000 ;
    END
  END cw_a[23]
  PIN cw_d[0]
    DIRECTION INPUT ;
    USE SIGNAL ;
    PORT
      LAYER M3 ;
        RECT 670.533 863.808 670.557 864.000 ;
    END
  END cw_d[0]
  PIN cw_d[1]
    DIRECTION INPUT ;
    USE SIGNAL ;
    PORT
      LAYER M5 ;
        RECT 671.424 863.808 671.448 864.000 ;
    END
  END cw_d[1]
  PIN cw_d[2]
    DIRECTION INPUT ;
    USE SIGNAL ;
    PORT
      LAYER M3 ;
        RECT 672.333 863.808 672.357 864.000 ;
    END
  END cw_d[2]
  PIN cw_d[3]
    DIRECTION INPUT ;
    USE SIGNAL ;
    PORT
      LAYER M5 ;
        RECT 673.248 863.808 673.272 864.000 ;
    END
  END cw_d[3]
  PIN cw_d[4]
    DIRECTION INPUT ;
    USE SIGNAL ;
    PORT
      LAYER M3 ;
        RECT 674.133 863.808 674.157 864.000 ;
    END
  END cw_d[4]
  PIN cw_d[5]
    DIRECTION INPUT ;
    USE SIGNAL ;
    PORT
      LAYER M5 ;
        RECT 675.024 863.808 675.048 864.000 ;
    END
  END cw_d[5]
  PIN cw_d[6]
    DIRECTION INPUT ;
    USE SIGNAL ;
    PORT
      LAYER M3 ;
        RECT 675.933 863.808 675.957 864.000 ;
    END
  END cw_d[6]
  PIN cw_d[7]
    DIRECTION INPUT ;
    USE SIGNAL ;
    PORT
      LAYER M5 ;
        RECT 676.848 863.808 676.872 864.000 ;
    END
  END cw_d[7]
  PIN cw_d[8]
    DIRECTION INPUT ;
    USE SIGNAL ;
    PORT
      LAYER M3 ;
        RECT 677.769 863.808 677.793 864.000 ;
    END
  END cw_d[8]
  PIN cw_d[9]
    DIRECTION INPUT ;
    USE SIGNAL ;
    PORT
      LAYER M5 ;
        RECT 678.672 863.808 678.696 864.000 ;
    END
  END cw_d[9]
  PIN cw_d[10]
    DIRECTION INPUT ;
    USE SIGNAL ;
    PORT
      LAYER M3 ;
        RECT 679.569 863.808 679.593 864.000 ;
    END
  END cw_d[10]
  PIN cw_d[11]
    DIRECTION INPUT ;
    USE SIGNAL ;
    PORT
      LAYER M5 ;
        RECT 680.448 863.808 680.472 864.000 ;
    END
  END cw_d[11]
  PIN cw_d[12]
    DIRECTION INPUT ;
    USE SIGNAL ;
    PORT
      LAYER M3 ;
        RECT 681.369 863.808 681.393 864.000 ;
    END
  END cw_d[12]
  PIN cw_d[13]
    DIRECTION INPUT ;
    USE SIGNAL ;
    PORT
      LAYER M5 ;
        RECT 682.272 863.808 682.296 864.000 ;
    END
  END cw_d[13]
  PIN cw_d[14]
    DIRECTION INPUT ;
    USE SIGNAL ;
    PORT
      LAYER M3 ;
        RECT 683.169 863.808 683.193 864.000 ;
    END
  END cw_d[14]
  PIN cw_d[15]
    DIRECTION INPUT ;
    USE SIGNAL ;
    PORT
      LAYER M5 ;
        RECT 684.096 863.808 684.120 864.000 ;
    END
  END cw_d[15]
  PIN cw_d[16]
    DIRECTION INPUT ;
    USE SIGNAL ;
    PORT
      LAYER M3 ;
        RECT 684.969 863.808 684.993 864.000 ;
    END
  END cw_d[16]
  PIN cw_d[17]
    DIRECTION INPUT ;
    USE SIGNAL ;
    PORT
      LAYER M5 ;
        RECT 685.872 863.808 685.896 864.000 ;
    END
  END cw_d[17]
  PIN cw_d[18]
    DIRECTION INPUT ;
    USE SIGNAL ;
    PORT
      LAYER M3 ;
        RECT 686.805 863.808 686.829 864.000 ;
    END
  END cw_d[18]
  PIN cw_d[19]
    DIRECTION INPUT ;
    USE SIGNAL ;
    PORT
      LAYER M5 ;
        RECT 687.696 863.808 687.720 864.000 ;
    END
  END cw_d[19]
  PIN cw_d[20]
    DIRECTION INPUT ;
    USE SIGNAL ;
    PORT
      LAYER M3 ;
        RECT 688.605 863.808 688.629 864.000 ;
    END
  END cw_d[20]
  PIN cw_d[21]
    DIRECTION INPUT ;
    USE SIGNAL ;
    PORT
      LAYER M5 ;
        RECT 689.520 863.808 689.544 864.000 ;
    END
  END cw_d[21]
  PIN cw_d[22]
    DIRECTION INPUT ;
    USE SIGNAL ;
    PORT
      LAYER M3 ;
        RECT 690.405 863.808 690.429 864.000 ;
    END
  END cw_d[22]
  PIN cw_d[23]
    DIRECTION INPUT ;
    USE SIGNAL ;
    PORT
      LAYER M5 ;
        RECT 691.296 863.808 691.320 864.000 ;
    END
  END cw_d[23]
  PIN cw_d[24]
    DIRECTION INPUT ;
    USE SIGNAL ;
    PORT
      LAYER M3 ;
        RECT 692.205 863.808 692.229 864.000 ;
    END
  END cw_d[24]
  PIN cw_d[25]
    DIRECTION INPUT ;
    USE SIGNAL ;
    PORT
      LAYER M5 ;
        RECT 693.120 863.808 693.144 864.000 ;
    END
  END cw_d[25]
  PIN cw_d[26]
    DIRECTION INPUT ;
    USE SIGNAL ;
    PORT
      LAYER M3 ;
        RECT 694.005 863.808 694.029 864.000 ;
    END
  END cw_d[26]
  PIN cw_d[27]
    DIRECTION INPUT ;
    USE SIGNAL ;
    PORT
      LAYER M5 ;
        RECT 694.944 863.808 694.968 864.000 ;
    END
  END cw_d[27]
  PIN cw_d[28]
    DIRECTION INPUT ;
    USE SIGNAL ;
    PORT
      LAYER M3 ;
        RECT 695.841 863.808 695.865 864.000 ;
    END
  END cw_d[28]
  PIN cw_d[29]
    DIRECTION INPUT ;
    USE SIGNAL ;
    PORT
      LAYER M5 ;
        RECT 696.720 863.808 696.744 864.000 ;
    END
  END cw_d[29]
  PIN cw_d[30]
    DIRECTION INPUT ;
    USE SIGNAL ;
    PORT
      LAYER M3 ;
        RECT 697.641 863.808 697.665 864.000 ;
    END
  END cw_d[30]
  PIN cw_d[31]
    DIRECTION INPUT ;
    USE SIGNAL ;
    PORT
      LAYER M5 ;
        RECT 698.544 863.808 698.568 864.000 ;
    END
  END cw_d[31]
  PIN cw_d[32]
    DIRECTION INPUT ;
    USE SIGNAL ;
    PORT
      LAYER M3 ;
        RECT 699.441 863.808 699.465 864.000 ;
    END
  END cw_d[32]
  PIN cw_d[33]
    DIRECTION INPUT ;
    USE SIGNAL ;
    PORT
      LAYER M5 ;
        RECT 700.368 863.808 700.392 864.000 ;
    END
  END cw_d[33]
  PIN cw_d[34]
    DIRECTION INPUT ;
    USE SIGNAL ;
    PORT
      LAYER M3 ;
        RECT 701.241 863.808 701.265 864.000 ;
    END
  END cw_d[34]
  PIN cw_d[35]
    DIRECTION INPUT ;
    USE SIGNAL ;
    PORT
      LAYER M5 ;
        RECT 702.144 863.808 702.168 864.000 ;
    END
  END cw_d[35]
  PIN cw_d[36]
    DIRECTION INPUT ;
    USE SIGNAL ;
    PORT
      LAYER M3 ;
        RECT 703.041 863.808 703.065 864.000 ;
    END
  END cw_d[36]
  PIN cw_d[37]
    DIRECTION INPUT ;
    USE SIGNAL ;
    PORT
      LAYER M5 ;
        RECT 703.968 863.808 703.992 864.000 ;
    END
  END cw_d[37]
  PIN cw_d[38]
    DIRECTION INPUT ;
    USE SIGNAL ;
    PORT
      LAYER M3 ;
        RECT 704.877 863.808 704.901 864.000 ;
    END
  END cw_d[38]
  PIN cw_d[39]
    DIRECTION INPUT ;
    USE SIGNAL ;
    PORT
      LAYER M5 ;
        RECT 705.792 863.808 705.816 864.000 ;
    END
  END cw_d[39]
  PIN cw_d[40]
    DIRECTION INPUT ;
    USE SIGNAL ;
    PORT
      LAYER M3 ;
        RECT 706.677 863.808 706.701 864.000 ;
    END
  END cw_d[40]
  PIN cw_d[41]
    DIRECTION INPUT ;
    USE SIGNAL ;
    PORT
      LAYER M5 ;
        RECT 707.568 863.808 707.592 864.000 ;
    END
  END cw_d[41]
  PIN cw_d[42]
    DIRECTION INPUT ;
    USE SIGNAL ;
    PORT
      LAYER M3 ;
        RECT 708.477 863.808 708.501 864.000 ;
    END
  END cw_d[42]
  PIN cw_d[43]
    DIRECTION INPUT ;
    USE SIGNAL ;
    PORT
      LAYER M5 ;
        RECT 709.392 863.808 709.416 864.000 ;
    END
  END cw_d[43]
  PIN cw_d[44]
    DIRECTION INPUT ;
    USE SIGNAL ;
    PORT
      LAYER M3 ;
        RECT 710.277 863.808 710.301 864.000 ;
    END
  END cw_d[44]
  PIN cw_d[45]
    DIRECTION INPUT ;
    USE SIGNAL ;
    PORT
      LAYER M5 ;
        RECT 711.168 863.808 711.192 864.000 ;
    END
  END cw_d[45]
  PIN cw_d[46]
    DIRECTION INPUT ;
    USE SIGNAL ;
    PORT
      LAYER M3 ;
        RECT 712.077 863.808 712.101 864.000 ;
    END
  END cw_d[46]
  PIN cw_d[47]
    DIRECTION INPUT ;
    USE SIGNAL ;
    PORT
      LAYER M5 ;
        RECT 712.992 863.808 713.016 864.000 ;
    END
  END cw_d[47]
  PIN cw_d[48]
    DIRECTION INPUT ;
    USE SIGNAL ;
    PORT
      LAYER M3 ;
        RECT 713.913 863.808 713.937 864.000 ;
    END
  END cw_d[48]
  PIN cw_d[49]
    DIRECTION INPUT ;
    USE SIGNAL ;
    PORT
      LAYER M5 ;
        RECT 714.816 863.808 714.840 864.000 ;
    END
  END cw_d[49]
  PIN cw_d[50]
    DIRECTION INPUT ;
    USE SIGNAL ;
    PORT
      LAYER M3 ;
        RECT 715.713 863.808 715.737 864.000 ;
    END
  END cw_d[50]
  PIN cw_d[51]
    DIRECTION INPUT ;
    USE SIGNAL ;
    PORT
      LAYER M5 ;
        RECT 716.592 863.808 716.616 864.000 ;
    END
  END cw_d[51]
  PIN cw_d[52]
    DIRECTION INPUT ;
    USE SIGNAL ;
    PORT
      LAYER M3 ;
        RECT 717.513 863.808 717.537 864.000 ;
    END
  END cw_d[52]
  PIN cw_d[53]
    DIRECTION INPUT ;
    USE SIGNAL ;
    PORT
      LAYER M5 ;
        RECT 718.416 863.808 718.440 864.000 ;
    END
  END cw_d[53]
  PIN cw_d[54]
    DIRECTION INPUT ;
    USE SIGNAL ;
    PORT
      LAYER M3 ;
        RECT 719.313 863.808 719.337 864.000 ;
    END
  END cw_d[54]
  PIN cw_d[55]
    DIRECTION INPUT ;
    USE SIGNAL ;
    PORT
      LAYER M5 ;
        RECT 720.240 863.808 720.264 864.000 ;
    END
  END cw_d[55]
  PIN cw_d[56]
    DIRECTION INPUT ;
    USE SIGNAL ;
    PORT
      LAYER M3 ;
        RECT 721.113 863.808 721.137 864.000 ;
    END
  END cw_d[56]
  PIN cw_d[57]
    DIRECTION INPUT ;
    USE SIGNAL ;
    PORT
      LAYER M5 ;
        RECT 722.016 863.808 722.040 864.000 ;
    END
  END cw_d[57]
  PIN cw_d[58]
    DIRECTION INPUT ;
    USE SIGNAL ;
    PORT
      LAYER M3 ;
        RECT 722.949 863.808 722.973 864.000 ;
    END
  END cw_d[58]
  PIN cw_d[59]
    DIRECTION INPUT ;
    USE SIGNAL ;
    PORT
      LAYER M5 ;
        RECT 723.840 863.808 723.864 864.000 ;
    END
  END cw_d[59]
  PIN cw_d[60]
    DIRECTION INPUT ;
    USE SIGNAL ;
    PORT
      LAYER M3 ;
        RECT 724.749 863.808 724.773 864.000 ;
    END
  END cw_d[60]
  PIN cw_d[61]
    DIRECTION INPUT ;
    USE SIGNAL ;
    PORT
      LAYER M5 ;
        RECT 725.664 863.808 725.688 864.000 ;
    END
  END cw_d[61]
  PIN cw_d[62]
    DIRECTION INPUT ;
    USE SIGNAL ;
    PORT
      LAYER M3 ;
        RECT 726.549 863.808 726.573 864.000 ;
    END
  END cw_d[62]
  PIN cw_d[63]
    DIRECTION INPUT ;
    USE SIGNAL ;
    PORT
      LAYER M5 ;
        RECT 727.440 863.808 727.464 864.000 ;
    END
  END cw_d[63]
  PIN hw_v
    DIRECTION OUTPUT ;
    USE SIGNAL ;
    PORT
      LAYER M4 ;
        RECT 734.208 7.728 734.400 7.752 ;
    END
  END hw_v
  PIN hw_j[0]
    DIRECTION OUTPUT ;
    USE SIGNAL ;
    PORT
      LAYER M4 ;
        RECT 734.208 9.456 734.400 9.480 ;
    END
  END hw_j[0]
  PIN hw_j[1]
    DIRECTION OUTPUT ;
    USE SIGNAL ;
    PORT
      LAYER M4 ;
        RECT 734.208 10.272 734.400 10.296 ;
    END
  END hw_j[1]
  PIN hw_j[2]
    DIRECTION OUTPUT ;
    USE SIGNAL ;
    PORT
      LAYER M4 ;
        RECT 734.208 11.136 734.400 11.160 ;
    END
  END hw_j[2]
  PIN hw_hf
    DIRECTION OUTPUT ;
    USE SIGNAL ;
    PORT
      LAYER M4 ;
        RECT 734.208 12.816 734.400 12.840 ;
    END
  END hw_hf
  PIN hw_d[0]
    DIRECTION OUTPUT ;
    USE SIGNAL ;
    PORT
      LAYER M4 ;
        RECT 734.208 14.544 734.400 14.568 ;
    END
  END hw_d[0]
  PIN hw_d[1]
    DIRECTION OUTPUT ;
    USE SIGNAL ;
    PORT
      LAYER M4 ;
        RECT 734.208 15.456 734.400 15.480 ;
    END
  END hw_d[1]
  PIN hw_d[2]
    DIRECTION OUTPUT ;
    USE SIGNAL ;
    PORT
      LAYER M4 ;
        RECT 734.208 16.368 734.400 16.392 ;
    END
  END hw_d[2]
  PIN hw_d[3]
    DIRECTION OUTPUT ;
    USE SIGNAL ;
    PORT
      LAYER M4 ;
        RECT 734.208 17.280 734.400 17.304 ;
    END
  END hw_d[3]
  PIN hw_d[4]
    DIRECTION OUTPUT ;
    USE SIGNAL ;
    PORT
      LAYER M4 ;
        RECT 734.208 18.192 734.400 18.216 ;
    END
  END hw_d[4]
  PIN hw_d[5]
    DIRECTION OUTPUT ;
    USE SIGNAL ;
    PORT
      LAYER M4 ;
        RECT 734.208 19.104 734.400 19.128 ;
    END
  END hw_d[5]
  PIN hw_d[6]
    DIRECTION OUTPUT ;
    USE SIGNAL ;
    PORT
      LAYER M4 ;
        RECT 734.208 20.016 734.400 20.040 ;
    END
  END hw_d[6]
  PIN hw_d[7]
    DIRECTION OUTPUT ;
    USE SIGNAL ;
    PORT
      LAYER M4 ;
        RECT 734.208 20.880 734.400 20.904 ;
    END
  END hw_d[7]
  PIN hw_d[8]
    DIRECTION OUTPUT ;
    USE SIGNAL ;
    PORT
      LAYER M4 ;
        RECT 734.208 21.792 734.400 21.816 ;
    END
  END hw_d[8]
  PIN hw_d[9]
    DIRECTION OUTPUT ;
    USE SIGNAL ;
    PORT
      LAYER M4 ;
        RECT 734.208 22.704 734.400 22.728 ;
    END
  END hw_d[9]
  PIN hw_d[10]
    DIRECTION OUTPUT ;
    USE SIGNAL ;
    PORT
      LAYER M4 ;
        RECT 734.208 23.616 734.400 23.640 ;
    END
  END hw_d[10]
  PIN hw_d[11]
    DIRECTION OUTPUT ;
    USE SIGNAL ;
    PORT
      LAYER M4 ;
        RECT 734.208 24.528 734.400 24.552 ;
    END
  END hw_d[11]
  PIN hw_d[12]
    DIRECTION OUTPUT ;
    USE SIGNAL ;
    PORT
      LAYER M4 ;
        RECT 734.208 25.440 734.400 25.464 ;
    END
  END hw_d[12]
  PIN hw_d[13]
    DIRECTION OUTPUT ;
    USE SIGNAL ;
    PORT
      LAYER M4 ;
        RECT 734.208 26.304 734.400 26.328 ;
    END
  END hw_d[13]
  PIN hw_d[14]
    DIRECTION OUTPUT ;
    USE SIGNAL ;
    PORT
      LAYER M4 ;
        RECT 734.208 27.216 734.400 27.240 ;
    END
  END hw_d[14]
  PIN hw_d[15]
    DIRECTION OUTPUT ;
    USE SIGNAL ;
    PORT
      LAYER M4 ;
        RECT 734.208 28.128 734.400 28.152 ;
    END
  END hw_d[15]
  PIN hw_d[16]
    DIRECTION OUTPUT ;
    USE SIGNAL ;
    PORT
      LAYER M4 ;
        RECT 734.208 29.040 734.400 29.064 ;
    END
  END hw_d[16]
  PIN hw_d[17]
    DIRECTION OUTPUT ;
    USE SIGNAL ;
    PORT
      LAYER M4 ;
        RECT 734.208 29.952 734.400 29.976 ;
    END
  END hw_d[17]
  PIN hw_d[18]
    DIRECTION OUTPUT ;
    USE SIGNAL ;
    PORT
      LAYER M4 ;
        RECT 734.208 30.864 734.400 30.888 ;
    END
  END hw_d[18]
  PIN hw_d[19]
    DIRECTION OUTPUT ;
    USE SIGNAL ;
    PORT
      LAYER M4 ;
        RECT 734.208 31.776 734.400 31.800 ;
    END
  END hw_d[19]
  PIN hw_d[20]
    DIRECTION OUTPUT ;
    USE SIGNAL ;
    PORT
      LAYER M4 ;
        RECT 734.208 32.640 734.400 32.664 ;
    END
  END hw_d[20]
  PIN hw_d[21]
    DIRECTION OUTPUT ;
    USE SIGNAL ;
    PORT
      LAYER M4 ;
        RECT 734.208 33.552 734.400 33.576 ;
    END
  END hw_d[21]
  PIN hw_d[22]
    DIRECTION OUTPUT ;
    USE SIGNAL ;
    PORT
      LAYER M4 ;
        RECT 734.208 34.464 734.400 34.488 ;
    END
  END hw_d[22]
  PIN hw_d[23]
    DIRECTION OUTPUT ;
    USE SIGNAL ;
    PORT
      LAYER M4 ;
        RECT 734.208 35.376 734.400 35.400 ;
    END
  END hw_d[23]
  PIN hw_d[24]
    DIRECTION OUTPUT ;
    USE SIGNAL ;
    PORT
      LAYER M4 ;
        RECT 734.208 36.288 734.400 36.312 ;
    END
  END hw_d[24]
  PIN hw_d[25]
    DIRECTION OUTPUT ;
    USE SIGNAL ;
    PORT
      LAYER M4 ;
        RECT 734.208 37.200 734.400 37.224 ;
    END
  END hw_d[25]
  PIN hw_d[26]
    DIRECTION OUTPUT ;
    USE SIGNAL ;
    PORT
      LAYER M4 ;
        RECT 734.208 38.112 734.400 38.136 ;
    END
  END hw_d[26]
  PIN hw_d[27]
    DIRECTION OUTPUT ;
    USE SIGNAL ;
    PORT
      LAYER M4 ;
        RECT 734.208 38.976 734.400 39.000 ;
    END
  END hw_d[27]
  PIN hw_d[28]
    DIRECTION OUTPUT ;
    USE SIGNAL ;
    PORT
      LAYER M4 ;
        RECT 734.208 39.888 734.400 39.912 ;
    END
  END hw_d[28]
  PIN hw_d[29]
    DIRECTION OUTPUT ;
    USE SIGNAL ;
    PORT
      LAYER M4 ;
        RECT 734.208 40.800 734.400 40.824 ;
    END
  END hw_d[29]
  PIN hw_d[30]
    DIRECTION OUTPUT ;
    USE SIGNAL ;
    PORT
      LAYER M4 ;
        RECT 734.208 41.712 734.400 41.736 ;
    END
  END hw_d[30]
  PIN hw_d[31]
    DIRECTION OUTPUT ;
    USE SIGNAL ;
    PORT
      LAYER M4 ;
        RECT 734.208 42.624 734.400 42.648 ;
    END
  END hw_d[31]
  PIN hw_d[32]
    DIRECTION OUTPUT ;
    USE SIGNAL ;
    PORT
      LAYER M4 ;
        RECT 734.208 43.536 734.400 43.560 ;
    END
  END hw_d[32]
  PIN hw_d[33]
    DIRECTION OUTPUT ;
    USE SIGNAL ;
    PORT
      LAYER M4 ;
        RECT 734.208 44.400 734.400 44.424 ;
    END
  END hw_d[33]
  PIN hw_d[34]
    DIRECTION OUTPUT ;
    USE SIGNAL ;
    PORT
      LAYER M4 ;
        RECT 734.208 45.312 734.400 45.336 ;
    END
  END hw_d[34]
  PIN hw_d[35]
    DIRECTION OUTPUT ;
    USE SIGNAL ;
    PORT
      LAYER M4 ;
        RECT 734.208 46.224 734.400 46.248 ;
    END
  END hw_d[35]
  PIN hw_d[36]
    DIRECTION OUTPUT ;
    USE SIGNAL ;
    PORT
      LAYER M4 ;
        RECT 734.208 47.136 734.400 47.160 ;
    END
  END hw_d[36]
  PIN hw_d[37]
    DIRECTION OUTPUT ;
    USE SIGNAL ;
    PORT
      LAYER M4 ;
        RECT 734.208 48.048 734.400 48.072 ;
    END
  END hw_d[37]
  PIN hw_d[38]
    DIRECTION OUTPUT ;
    USE SIGNAL ;
    PORT
      LAYER M4 ;
        RECT 734.208 48.960 734.400 48.984 ;
    END
  END hw_d[38]
  PIN hw_d[39]
    DIRECTION OUTPUT ;
    USE SIGNAL ;
    PORT
      LAYER M4 ;
        RECT 734.208 49.872 734.400 49.896 ;
    END
  END hw_d[39]
  PIN hw_d[40]
    DIRECTION OUTPUT ;
    USE SIGNAL ;
    PORT
      LAYER M4 ;
        RECT 734.208 50.736 734.400 50.760 ;
    END
  END hw_d[40]
  PIN hw_d[41]
    DIRECTION OUTPUT ;
    USE SIGNAL ;
    PORT
      LAYER M4 ;
        RECT 734.208 51.648 734.400 51.672 ;
    END
  END hw_d[41]
  PIN hw_d[42]
    DIRECTION OUTPUT ;
    USE SIGNAL ;
    PORT
      LAYER M4 ;
        RECT 734.208 52.560 734.400 52.584 ;
    END
  END hw_d[42]
  PIN hw_d[43]
    DIRECTION OUTPUT ;
    USE SIGNAL ;
    PORT
      LAYER M4 ;
        RECT 734.208 53.472 734.400 53.496 ;
    END
  END hw_d[43]
  PIN hw_d[44]
    DIRECTION OUTPUT ;
    USE SIGNAL ;
    PORT
      LAYER M4 ;
        RECT 734.208 54.384 734.400 54.408 ;
    END
  END hw_d[44]
  PIN hw_d[45]
    DIRECTION OUTPUT ;
    USE SIGNAL ;
    PORT
      LAYER M4 ;
        RECT 734.208 55.296 734.400 55.320 ;
    END
  END hw_d[45]
  PIN hw_d[46]
    DIRECTION OUTPUT ;
    USE SIGNAL ;
    PORT
      LAYER M4 ;
        RECT 734.208 56.208 734.400 56.232 ;
    END
  END hw_d[46]
  PIN hw_d[47]
    DIRECTION OUTPUT ;
    USE SIGNAL ;
    PORT
      LAYER M4 ;
        RECT 734.208 57.072 734.400 57.096 ;
    END
  END hw_d[47]
  PIN hw_d[48]
    DIRECTION OUTPUT ;
    USE SIGNAL ;
    PORT
      LAYER M4 ;
        RECT 734.208 57.984 734.400 58.008 ;
    END
  END hw_d[48]
  PIN hw_d[49]
    DIRECTION OUTPUT ;
    USE SIGNAL ;
    PORT
      LAYER M4 ;
        RECT 734.208 58.896 734.400 58.920 ;
    END
  END hw_d[49]
  PIN hw_d[50]
    DIRECTION OUTPUT ;
    USE SIGNAL ;
    PORT
      LAYER M4 ;
        RECT 734.208 59.808 734.400 59.832 ;
    END
  END hw_d[50]
  PIN hw_d[51]
    DIRECTION OUTPUT ;
    USE SIGNAL ;
    PORT
      LAYER M4 ;
        RECT 734.208 60.720 734.400 60.744 ;
    END
  END hw_d[51]
  PIN hw_d[52]
    DIRECTION OUTPUT ;
    USE SIGNAL ;
    PORT
      LAYER M4 ;
        RECT 734.208 61.632 734.400 61.656 ;
    END
  END hw_d[52]
  PIN hw_d[53]
    DIRECTION OUTPUT ;
    USE SIGNAL ;
    PORT
      LAYER M4 ;
        RECT 734.208 62.496 734.400 62.520 ;
    END
  END hw_d[53]
  PIN hw_d[54]
    DIRECTION OUTPUT ;
    USE SIGNAL ;
    PORT
      LAYER M4 ;
        RECT 734.208 63.408 734.400 63.432 ;
    END
  END hw_d[54]
  PIN hw_d[55]
    DIRECTION OUTPUT ;
    USE SIGNAL ;
    PORT
      LAYER M4 ;
        RECT 734.208 64.320 734.400 64.344 ;
    END
  END hw_d[55]
  PIN hw_d[56]
    DIRECTION OUTPUT ;
    USE SIGNAL ;
    PORT
      LAYER M4 ;
        RECT 734.208 65.232 734.400 65.256 ;
    END
  END hw_d[56]
  PIN hw_d[57]
    DIRECTION OUTPUT ;
    USE SIGNAL ;
    PORT
      LAYER M4 ;
        RECT 734.208 66.144 734.400 66.168 ;
    END
  END hw_d[57]
  PIN hw_d[58]
    DIRECTION OUTPUT ;
    USE SIGNAL ;
    PORT
      LAYER M4 ;
        RECT 734.208 67.056 734.400 67.080 ;
    END
  END hw_d[58]
  PIN hw_d[59]
    DIRECTION OUTPUT ;
    USE SIGNAL ;
    PORT
      LAYER M4 ;
        RECT 734.208 67.968 734.400 67.992 ;
    END
  END hw_d[59]
  PIN hw_d[60]
    DIRECTION OUTPUT ;
    USE SIGNAL ;
    PORT
      LAYER M4 ;
        RECT 734.208 68.832 734.400 68.856 ;
    END
  END hw_d[60]
  PIN hw_d[61]
    DIRECTION OUTPUT ;
    USE SIGNAL ;
    PORT
      LAYER M4 ;
        RECT 734.208 69.744 734.400 69.768 ;
    END
  END hw_d[61]
  PIN hw_d[62]
    DIRECTION OUTPUT ;
    USE SIGNAL ;
    PORT
      LAYER M4 ;
        RECT 734.208 70.656 734.400 70.680 ;
    END
  END hw_d[62]
  PIN hw_d[63]
    DIRECTION OUTPUT ;
    USE SIGNAL ;
    PORT
      LAYER M4 ;
        RECT 734.208 71.568 734.400 71.592 ;
    END
  END hw_d[63]
  PIN hw_d[64]
    DIRECTION OUTPUT ;
    USE SIGNAL ;
    PORT
      LAYER M4 ;
        RECT 734.208 72.480 734.400 72.504 ;
    END
  END hw_d[64]
  PIN hw_d[65]
    DIRECTION OUTPUT ;
    USE SIGNAL ;
    PORT
      LAYER M4 ;
        RECT 734.208 73.392 734.400 73.416 ;
    END
  END hw_d[65]
  PIN hw_d[66]
    DIRECTION OUTPUT ;
    USE SIGNAL ;
    PORT
      LAYER M4 ;
        RECT 734.208 74.256 734.400 74.280 ;
    END
  END hw_d[66]
  PIN hw_d[67]
    DIRECTION OUTPUT ;
    USE SIGNAL ;
    PORT
      LAYER M4 ;
        RECT 734.208 75.168 734.400 75.192 ;
    END
  END hw_d[67]
  PIN hw_d[68]
    DIRECTION OUTPUT ;
    USE SIGNAL ;
    PORT
      LAYER M4 ;
        RECT 734.208 76.080 734.400 76.104 ;
    END
  END hw_d[68]
  PIN hw_d[69]
    DIRECTION OUTPUT ;
    USE SIGNAL ;
    PORT
      LAYER M4 ;
        RECT 734.208 76.992 734.400 77.016 ;
    END
  END hw_d[69]
  PIN hw_d[70]
    DIRECTION OUTPUT ;
    USE SIGNAL ;
    PORT
      LAYER M4 ;
        RECT 734.208 77.904 734.400 77.928 ;
    END
  END hw_d[70]
  PIN hw_d[71]
    DIRECTION OUTPUT ;
    USE SIGNAL ;
    PORT
      LAYER M4 ;
        RECT 734.208 78.816 734.400 78.840 ;
    END
  END hw_d[71]
  PIN hw_d[72]
    DIRECTION OUTPUT ;
    USE SIGNAL ;
    PORT
      LAYER M4 ;
        RECT 734.208 79.728 734.400 79.752 ;
    END
  END hw_d[72]
  PIN hw_d[73]
    DIRECTION OUTPUT ;
    USE SIGNAL ;
    PORT
      LAYER M4 ;
        RECT 734.208 80.592 734.400 80.616 ;
    END
  END hw_d[73]
  PIN hw_d[74]
    DIRECTION OUTPUT ;
    USE SIGNAL ;
    PORT
      LAYER M4 ;
        RECT 734.208 81.504 734.400 81.528 ;
    END
  END hw_d[74]
  PIN hw_d[75]
    DIRECTION OUTPUT ;
    USE SIGNAL ;
    PORT
      LAYER M4 ;
        RECT 734.208 82.416 734.400 82.440 ;
    END
  END hw_d[75]
  PIN hw_d[76]
    DIRECTION OUTPUT ;
    USE SIGNAL ;
    PORT
      LAYER M4 ;
        RECT 734.208 83.328 734.400 83.352 ;
    END
  END hw_d[76]
  PIN hw_d[77]
    DIRECTION OUTPUT ;
    USE SIGNAL ;
    PORT
      LAYER M4 ;
        RECT 734.208 84.240 734.400 84.264 ;
    END
  END hw_d[77]
  PIN hw_d[78]
    DIRECTION OUTPUT ;
    USE SIGNAL ;
    PORT
      LAYER M4 ;
        RECT 734.208 85.152 734.400 85.176 ;
    END
  END hw_d[78]
  PIN hw_d[79]
    DIRECTION OUTPUT ;
    USE SIGNAL ;
    PORT
      LAYER M4 ;
        RECT 734.208 86.064 734.400 86.088 ;
    END
  END hw_d[79]
  PIN hw_d[80]
    DIRECTION OUTPUT ;
    USE SIGNAL ;
    PORT
      LAYER M4 ;
        RECT 734.208 86.928 734.400 86.952 ;
    END
  END hw_d[80]
  PIN hw_d[81]
    DIRECTION OUTPUT ;
    USE SIGNAL ;
    PORT
      LAYER M4 ;
        RECT 734.208 87.840 734.400 87.864 ;
    END
  END hw_d[81]
  PIN hw_d[82]
    DIRECTION OUTPUT ;
    USE SIGNAL ;
    PORT
      LAYER M4 ;
        RECT 734.208 88.752 734.400 88.776 ;
    END
  END hw_d[82]
  PIN hw_d[83]
    DIRECTION OUTPUT ;
    USE SIGNAL ;
    PORT
      LAYER M4 ;
        RECT 734.208 89.664 734.400 89.688 ;
    END
  END hw_d[83]
  PIN hw_d[84]
    DIRECTION OUTPUT ;
    USE SIGNAL ;
    PORT
      LAYER M4 ;
        RECT 734.208 90.576 734.400 90.600 ;
    END
  END hw_d[84]
  PIN hw_d[85]
    DIRECTION OUTPUT ;
    USE SIGNAL ;
    PORT
      LAYER M4 ;
        RECT 734.208 91.488 734.400 91.512 ;
    END
  END hw_d[85]
  PIN hw_d[86]
    DIRECTION OUTPUT ;
    USE SIGNAL ;
    PORT
      LAYER M4 ;
        RECT 734.208 92.352 734.400 92.376 ;
    END
  END hw_d[86]
  PIN hw_d[87]
    DIRECTION OUTPUT ;
    USE SIGNAL ;
    PORT
      LAYER M4 ;
        RECT 734.208 93.264 734.400 93.288 ;
    END
  END hw_d[87]
  PIN hw_d[88]
    DIRECTION OUTPUT ;
    USE SIGNAL ;
    PORT
      LAYER M4 ;
        RECT 734.208 94.176 734.400 94.200 ;
    END
  END hw_d[88]
  PIN hw_d[89]
    DIRECTION OUTPUT ;
    USE SIGNAL ;
    PORT
      LAYER M4 ;
        RECT 734.208 95.088 734.400 95.112 ;
    END
  END hw_d[89]
  PIN hw_d[90]
    DIRECTION OUTPUT ;
    USE SIGNAL ;
    PORT
      LAYER M4 ;
        RECT 734.208 96.000 734.400 96.024 ;
    END
  END hw_d[90]
  PIN hw_d[91]
    DIRECTION OUTPUT ;
    USE SIGNAL ;
    PORT
      LAYER M4 ;
        RECT 734.208 96.912 734.400 96.936 ;
    END
  END hw_d[91]
  PIN hw_d[92]
    DIRECTION OUTPUT ;
    USE SIGNAL ;
    PORT
      LAYER M4 ;
        RECT 734.208 97.824 734.400 97.848 ;
    END
  END hw_d[92]
  PIN hw_d[93]
    DIRECTION OUTPUT ;
    USE SIGNAL ;
    PORT
      LAYER M4 ;
        RECT 734.208 98.688 734.400 98.712 ;
    END
  END hw_d[93]
  PIN hw_d[94]
    DIRECTION OUTPUT ;
    USE SIGNAL ;
    PORT
      LAYER M4 ;
        RECT 734.208 99.600 734.400 99.624 ;
    END
  END hw_d[94]
  PIN hw_d[95]
    DIRECTION OUTPUT ;
    USE SIGNAL ;
    PORT
      LAYER M4 ;
        RECT 734.208 100.512 734.400 100.536 ;
    END
  END hw_d[95]
  PIN hw_d[96]
    DIRECTION OUTPUT ;
    USE SIGNAL ;
    PORT
      LAYER M4 ;
        RECT 734.208 101.424 734.400 101.448 ;
    END
  END hw_d[96]
  PIN hw_d[97]
    DIRECTION OUTPUT ;
    USE SIGNAL ;
    PORT
      LAYER M4 ;
        RECT 734.208 102.336 734.400 102.360 ;
    END
  END hw_d[97]
  PIN hw_d[98]
    DIRECTION OUTPUT ;
    USE SIGNAL ;
    PORT
      LAYER M4 ;
        RECT 734.208 103.248 734.400 103.272 ;
    END
  END hw_d[98]
  PIN hw_d[99]
    DIRECTION OUTPUT ;
    USE SIGNAL ;
    PORT
      LAYER M4 ;
        RECT 734.208 104.160 734.400 104.184 ;
    END
  END hw_d[99]
  PIN hw_d[100]
    DIRECTION OUTPUT ;
    USE SIGNAL ;
    PORT
      LAYER M4 ;
        RECT 734.208 105.024 734.400 105.048 ;
    END
  END hw_d[100]
  PIN hw_d[101]
    DIRECTION OUTPUT ;
    USE SIGNAL ;
    PORT
      LAYER M4 ;
        RECT 734.208 105.936 734.400 105.960 ;
    END
  END hw_d[101]
  PIN hw_d[102]
    DIRECTION OUTPUT ;
    USE SIGNAL ;
    PORT
      LAYER M4 ;
        RECT 734.208 106.848 734.400 106.872 ;
    END
  END hw_d[102]
  PIN hw_d[103]
    DIRECTION OUTPUT ;
    USE SIGNAL ;
    PORT
      LAYER M4 ;
        RECT 734.208 107.760 734.400 107.784 ;
    END
  END hw_d[103]
  PIN hw_d[104]
    DIRECTION OUTPUT ;
    USE SIGNAL ;
    PORT
      LAYER M4 ;
        RECT 734.208 108.672 734.400 108.696 ;
    END
  END hw_d[104]
  PIN hw_d[105]
    DIRECTION OUTPUT ;
    USE SIGNAL ;
    PORT
      LAYER M4 ;
        RECT 734.208 109.584 734.400 109.608 ;
    END
  END hw_d[105]
  PIN hw_d[106]
    DIRECTION OUTPUT ;
    USE SIGNAL ;
    PORT
      LAYER M4 ;
        RECT 734.208 110.448 734.400 110.472 ;
    END
  END hw_d[106]
  PIN hw_d[107]
    DIRECTION OUTPUT ;
    USE SIGNAL ;
    PORT
      LAYER M4 ;
        RECT 734.208 111.360 734.400 111.384 ;
    END
  END hw_d[107]
  PIN hw_d[108]
    DIRECTION OUTPUT ;
    USE SIGNAL ;
    PORT
      LAYER M4 ;
        RECT 734.208 112.272 734.400 112.296 ;
    END
  END hw_d[108]
  PIN hw_d[109]
    DIRECTION OUTPUT ;
    USE SIGNAL ;
    PORT
      LAYER M4 ;
        RECT 734.208 113.184 734.400 113.208 ;
    END
  END hw_d[109]
  PIN hw_d[110]
    DIRECTION OUTPUT ;
    USE SIGNAL ;
    PORT
      LAYER M4 ;
        RECT 734.208 114.096 734.400 114.120 ;
    END
  END hw_d[110]
  PIN hw_d[111]
    DIRECTION OUTPUT ;
    USE SIGNAL ;
    PORT
      LAYER M4 ;
        RECT 734.208 115.008 734.400 115.032 ;
    END
  END hw_d[111]
  PIN hw_d[112]
    DIRECTION OUTPUT ;
    USE SIGNAL ;
    PORT
      LAYER M4 ;
        RECT 734.208 115.920 734.400 115.944 ;
    END
  END hw_d[112]
  PIN hw_d[113]
    DIRECTION OUTPUT ;
    USE SIGNAL ;
    PORT
      LAYER M4 ;
        RECT 734.208 116.784 734.400 116.808 ;
    END
  END hw_d[113]
  PIN hw_d[114]
    DIRECTION OUTPUT ;
    USE SIGNAL ;
    PORT
      LAYER M4 ;
        RECT 734.208 117.696 734.400 117.720 ;
    END
  END hw_d[114]
  PIN hw_d[115]
    DIRECTION OUTPUT ;
    USE SIGNAL ;
    PORT
      LAYER M4 ;
        RECT 734.208 118.608 734.400 118.632 ;
    END
  END hw_d[115]
  PIN hw_d[116]
    DIRECTION OUTPUT ;
    USE SIGNAL ;
    PORT
      LAYER M4 ;
        RECT 734.208 119.520 734.400 119.544 ;
    END
  END hw_d[116]
  PIN hw_d[117]
    DIRECTION OUTPUT ;
    USE SIGNAL ;
    PORT
      LAYER M4 ;
        RECT 734.208 120.432 734.400 120.456 ;
    END
  END hw_d[117]
  PIN hw_d[118]
    DIRECTION OUTPUT ;
    USE SIGNAL ;
    PORT
      LAYER M4 ;
        RECT 734.208 121.344 734.400 121.368 ;
    END
  END hw_d[118]
  PIN hw_d[119]
    DIRECTION OUTPUT ;
    USE SIGNAL ;
    PORT
      LAYER M4 ;
        RECT 734.208 122.256 734.400 122.280 ;
    END
  END hw_d[119]
  PIN hw_d[120]
    DIRECTION OUTPUT ;
    USE SIGNAL ;
    PORT
      LAYER M4 ;
        RECT 734.208 123.120 734.400 123.144 ;
    END
  END hw_d[120]
  PIN hw_d[121]
    DIRECTION OUTPUT ;
    USE SIGNAL ;
    PORT
      LAYER M4 ;
        RECT 734.208 124.032 734.400 124.056 ;
    END
  END hw_d[121]
  PIN hw_d[122]
    DIRECTION OUTPUT ;
    USE SIGNAL ;
    PORT
      LAYER M4 ;
        RECT 734.208 124.944 734.400 124.968 ;
    END
  END hw_d[122]
  PIN hw_d[123]
    DIRECTION OUTPUT ;
    USE SIGNAL ;
    PORT
      LAYER M4 ;
        RECT 734.208 125.856 734.400 125.880 ;
    END
  END hw_d[123]
  PIN hw_d[124]
    DIRECTION OUTPUT ;
    USE SIGNAL ;
    PORT
      LAYER M4 ;
        RECT 734.208 126.768 734.400 126.792 ;
    END
  END hw_d[124]
  PIN hw_d[125]
    DIRECTION OUTPUT ;
    USE SIGNAL ;
    PORT
      LAYER M4 ;
        RECT 734.208 127.680 734.400 127.704 ;
    END
  END hw_d[125]
  PIN hw_d[126]
    DIRECTION OUTPUT ;
    USE SIGNAL ;
    PORT
      LAYER M4 ;
        RECT 734.208 128.544 734.400 128.568 ;
    END
  END hw_d[126]
  PIN hw_d[127]
    DIRECTION OUTPUT ;
    USE SIGNAL ;
    PORT
      LAYER M4 ;
        RECT 734.208 129.456 734.400 129.480 ;
    END
  END hw_d[127]
  PIN hw_d[128]
    DIRECTION OUTPUT ;
    USE SIGNAL ;
    PORT
      LAYER M4 ;
        RECT 734.208 130.368 734.400 130.392 ;
    END
  END hw_d[128]
  PIN hw_d[129]
    DIRECTION OUTPUT ;
    USE SIGNAL ;
    PORT
      LAYER M4 ;
        RECT 734.208 131.280 734.400 131.304 ;
    END
  END hw_d[129]
  PIN hw_d[130]
    DIRECTION OUTPUT ;
    USE SIGNAL ;
    PORT
      LAYER M4 ;
        RECT 734.208 132.192 734.400 132.216 ;
    END
  END hw_d[130]
  PIN hw_d[131]
    DIRECTION OUTPUT ;
    USE SIGNAL ;
    PORT
      LAYER M4 ;
        RECT 734.208 133.104 734.400 133.128 ;
    END
  END hw_d[131]
  PIN hw_d[132]
    DIRECTION OUTPUT ;
    USE SIGNAL ;
    PORT
      LAYER M4 ;
        RECT 734.208 134.016 734.400 134.040 ;
    END
  END hw_d[132]
  PIN hw_d[133]
    DIRECTION OUTPUT ;
    USE SIGNAL ;
    PORT
      LAYER M4 ;
        RECT 734.208 134.880 734.400 134.904 ;
    END
  END hw_d[133]
  PIN hw_d[134]
    DIRECTION OUTPUT ;
    USE SIGNAL ;
    PORT
      LAYER M4 ;
        RECT 734.208 135.792 734.400 135.816 ;
    END
  END hw_d[134]
  PIN hw_d[135]
    DIRECTION OUTPUT ;
    USE SIGNAL ;
    PORT
      LAYER M4 ;
        RECT 734.208 136.704 734.400 136.728 ;
    END
  END hw_d[135]
  PIN hw_d[136]
    DIRECTION OUTPUT ;
    USE SIGNAL ;
    PORT
      LAYER M4 ;
        RECT 734.208 137.616 734.400 137.640 ;
    END
  END hw_d[136]
  PIN hw_d[137]
    DIRECTION OUTPUT ;
    USE SIGNAL ;
    PORT
      LAYER M4 ;
        RECT 734.208 138.528 734.400 138.552 ;
    END
  END hw_d[137]
  PIN hw_d[138]
    DIRECTION OUTPUT ;
    USE SIGNAL ;
    PORT
      LAYER M4 ;
        RECT 734.208 139.440 734.400 139.464 ;
    END
  END hw_d[138]
  PIN hw_d[139]
    DIRECTION OUTPUT ;
    USE SIGNAL ;
    PORT
      LAYER M4 ;
        RECT 734.208 140.352 734.400 140.376 ;
    END
  END hw_d[139]
  PIN hw_d[140]
    DIRECTION OUTPUT ;
    USE SIGNAL ;
    PORT
      LAYER M4 ;
        RECT 734.208 141.216 734.400 141.240 ;
    END
  END hw_d[140]
  PIN hw_d[141]
    DIRECTION OUTPUT ;
    USE SIGNAL ;
    PORT
      LAYER M4 ;
        RECT 734.208 142.128 734.400 142.152 ;
    END
  END hw_d[141]
  PIN hw_d[142]
    DIRECTION OUTPUT ;
    USE SIGNAL ;
    PORT
      LAYER M4 ;
        RECT 734.208 143.040 734.400 143.064 ;
    END
  END hw_d[142]
  PIN hw_d[143]
    DIRECTION OUTPUT ;
    USE SIGNAL ;
    PORT
      LAYER M4 ;
        RECT 734.208 143.952 734.400 143.976 ;
    END
  END hw_d[143]
  PIN hw_d[144]
    DIRECTION OUTPUT ;
    USE SIGNAL ;
    PORT
      LAYER M4 ;
        RECT 734.208 144.864 734.400 144.888 ;
    END
  END hw_d[144]
  PIN hw_d[145]
    DIRECTION OUTPUT ;
    USE SIGNAL ;
    PORT
      LAYER M4 ;
        RECT 734.208 145.776 734.400 145.800 ;
    END
  END hw_d[145]
  PIN hw_d[146]
    DIRECTION OUTPUT ;
    USE SIGNAL ;
    PORT
      LAYER M4 ;
        RECT 734.208 146.640 734.400 146.664 ;
    END
  END hw_d[146]
  PIN hw_d[147]
    DIRECTION OUTPUT ;
    USE SIGNAL ;
    PORT
      LAYER M4 ;
        RECT 734.208 147.552 734.400 147.576 ;
    END
  END hw_d[147]
  PIN hw_d[148]
    DIRECTION OUTPUT ;
    USE SIGNAL ;
    PORT
      LAYER M4 ;
        RECT 734.208 148.464 734.400 148.488 ;
    END
  END hw_d[148]
  PIN hw_d[149]
    DIRECTION OUTPUT ;
    USE SIGNAL ;
    PORT
      LAYER M4 ;
        RECT 734.208 149.376 734.400 149.400 ;
    END
  END hw_d[149]
  PIN hw_d[150]
    DIRECTION OUTPUT ;
    USE SIGNAL ;
    PORT
      LAYER M4 ;
        RECT 734.208 150.288 734.400 150.312 ;
    END
  END hw_d[150]
  PIN hw_d[151]
    DIRECTION OUTPUT ;
    USE SIGNAL ;
    PORT
      LAYER M4 ;
        RECT 734.208 151.200 734.400 151.224 ;
    END
  END hw_d[151]
  PIN hw_d[152]
    DIRECTION OUTPUT ;
    USE SIGNAL ;
    PORT
      LAYER M4 ;
        RECT 734.208 152.112 734.400 152.136 ;
    END
  END hw_d[152]
  PIN hw_d[153]
    DIRECTION OUTPUT ;
    USE SIGNAL ;
    PORT
      LAYER M4 ;
        RECT 734.208 152.976 734.400 153.000 ;
    END
  END hw_d[153]
  PIN hw_d[154]
    DIRECTION OUTPUT ;
    USE SIGNAL ;
    PORT
      LAYER M4 ;
        RECT 734.208 153.888 734.400 153.912 ;
    END
  END hw_d[154]
  PIN hw_d[155]
    DIRECTION OUTPUT ;
    USE SIGNAL ;
    PORT
      LAYER M4 ;
        RECT 734.208 154.800 734.400 154.824 ;
    END
  END hw_d[155]
  PIN hw_d[156]
    DIRECTION OUTPUT ;
    USE SIGNAL ;
    PORT
      LAYER M4 ;
        RECT 734.208 155.712 734.400 155.736 ;
    END
  END hw_d[156]
  PIN hw_d[157]
    DIRECTION OUTPUT ;
    USE SIGNAL ;
    PORT
      LAYER M4 ;
        RECT 734.208 156.624 734.400 156.648 ;
    END
  END hw_d[157]
  PIN hw_d[158]
    DIRECTION OUTPUT ;
    USE SIGNAL ;
    PORT
      LAYER M4 ;
        RECT 734.208 157.536 734.400 157.560 ;
    END
  END hw_d[158]
  PIN hw_d[159]
    DIRECTION OUTPUT ;
    USE SIGNAL ;
    PORT
      LAYER M4 ;
        RECT 734.208 158.400 734.400 158.424 ;
    END
  END hw_d[159]
  PIN hw_d[160]
    DIRECTION OUTPUT ;
    USE SIGNAL ;
    PORT
      LAYER M4 ;
        RECT 734.208 159.312 734.400 159.336 ;
    END
  END hw_d[160]
  PIN hw_d[161]
    DIRECTION OUTPUT ;
    USE SIGNAL ;
    PORT
      LAYER M4 ;
        RECT 734.208 160.224 734.400 160.248 ;
    END
  END hw_d[161]
  PIN hw_d[162]
    DIRECTION OUTPUT ;
    USE SIGNAL ;
    PORT
      LAYER M4 ;
        RECT 734.208 161.136 734.400 161.160 ;
    END
  END hw_d[162]
  PIN hw_d[163]
    DIRECTION OUTPUT ;
    USE SIGNAL ;
    PORT
      LAYER M4 ;
        RECT 734.208 162.048 734.400 162.072 ;
    END
  END hw_d[163]
  PIN hw_d[164]
    DIRECTION OUTPUT ;
    USE SIGNAL ;
    PORT
      LAYER M4 ;
        RECT 734.208 162.960 734.400 162.984 ;
    END
  END hw_d[164]
  PIN hw_d[165]
    DIRECTION OUTPUT ;
    USE SIGNAL ;
    PORT
      LAYER M4 ;
        RECT 734.208 163.872 734.400 163.896 ;
    END
  END hw_d[165]
  PIN hw_d[166]
    DIRECTION OUTPUT ;
    USE SIGNAL ;
    PORT
      LAYER M4 ;
        RECT 734.208 164.736 734.400 164.760 ;
    END
  END hw_d[166]
  PIN hw_d[167]
    DIRECTION OUTPUT ;
    USE SIGNAL ;
    PORT
      LAYER M4 ;
        RECT 734.208 165.648 734.400 165.672 ;
    END
  END hw_d[167]
  PIN hw_d[168]
    DIRECTION OUTPUT ;
    USE SIGNAL ;
    PORT
      LAYER M4 ;
        RECT 734.208 166.560 734.400 166.584 ;
    END
  END hw_d[168]
  PIN hw_d[169]
    DIRECTION OUTPUT ;
    USE SIGNAL ;
    PORT
      LAYER M4 ;
        RECT 734.208 167.472 734.400 167.496 ;
    END
  END hw_d[169]
  PIN hw_d[170]
    DIRECTION OUTPUT ;
    USE SIGNAL ;
    PORT
      LAYER M4 ;
        RECT 734.208 168.384 734.400 168.408 ;
    END
  END hw_d[170]
  PIN hw_d[171]
    DIRECTION OUTPUT ;
    USE SIGNAL ;
    PORT
      LAYER M4 ;
        RECT 734.208 169.296 734.400 169.320 ;
    END
  END hw_d[171]
  PIN hw_d[172]
    DIRECTION OUTPUT ;
    USE SIGNAL ;
    PORT
      LAYER M4 ;
        RECT 734.208 170.208 734.400 170.232 ;
    END
  END hw_d[172]
  PIN hw_d[173]
    DIRECTION OUTPUT ;
    USE SIGNAL ;
    PORT
      LAYER M4 ;
        RECT 734.208 171.072 734.400 171.096 ;
    END
  END hw_d[173]
  PIN hw_d[174]
    DIRECTION OUTPUT ;
    USE SIGNAL ;
    PORT
      LAYER M4 ;
        RECT 734.208 171.984 734.400 172.008 ;
    END
  END hw_d[174]
  PIN hw_d[175]
    DIRECTION OUTPUT ;
    USE SIGNAL ;
    PORT
      LAYER M4 ;
        RECT 734.208 172.896 734.400 172.920 ;
    END
  END hw_d[175]
  PIN hw_d[176]
    DIRECTION OUTPUT ;
    USE SIGNAL ;
    PORT
      LAYER M4 ;
        RECT 734.208 173.808 734.400 173.832 ;
    END
  END hw_d[176]
  PIN hw_d[177]
    DIRECTION OUTPUT ;
    USE SIGNAL ;
    PORT
      LAYER M4 ;
        RECT 734.208 174.720 734.400 174.744 ;
    END
  END hw_d[177]
  PIN hw_d[178]
    DIRECTION OUTPUT ;
    USE SIGNAL ;
    PORT
      LAYER M4 ;
        RECT 734.208 175.632 734.400 175.656 ;
    END
  END hw_d[178]
  PIN hw_d[179]
    DIRECTION OUTPUT ;
    USE SIGNAL ;
    PORT
      LAYER M4 ;
        RECT 734.208 176.496 734.400 176.520 ;
    END
  END hw_d[179]
  PIN hw_d[180]
    DIRECTION OUTPUT ;
    USE SIGNAL ;
    PORT
      LAYER M4 ;
        RECT 734.208 177.408 734.400 177.432 ;
    END
  END hw_d[180]
  PIN hw_d[181]
    DIRECTION OUTPUT ;
    USE SIGNAL ;
    PORT
      LAYER M4 ;
        RECT 734.208 178.320 734.400 178.344 ;
    END
  END hw_d[181]
  PIN hw_d[182]
    DIRECTION OUTPUT ;
    USE SIGNAL ;
    PORT
      LAYER M4 ;
        RECT 734.208 179.232 734.400 179.256 ;
    END
  END hw_d[182]
  PIN hw_d[183]
    DIRECTION OUTPUT ;
    USE SIGNAL ;
    PORT
      LAYER M4 ;
        RECT 734.208 180.144 734.400 180.168 ;
    END
  END hw_d[183]
  PIN hw_d[184]
    DIRECTION OUTPUT ;
    USE SIGNAL ;
    PORT
      LAYER M4 ;
        RECT 734.208 181.056 734.400 181.080 ;
    END
  END hw_d[184]
  PIN hw_d[185]
    DIRECTION OUTPUT ;
    USE SIGNAL ;
    PORT
      LAYER M4 ;
        RECT 734.208 181.968 734.400 181.992 ;
    END
  END hw_d[185]
  PIN hw_d[186]
    DIRECTION OUTPUT ;
    USE SIGNAL ;
    PORT
      LAYER M4 ;
        RECT 734.208 182.832 734.400 182.856 ;
    END
  END hw_d[186]
  PIN hw_d[187]
    DIRECTION OUTPUT ;
    USE SIGNAL ;
    PORT
      LAYER M4 ;
        RECT 734.208 183.744 734.400 183.768 ;
    END
  END hw_d[187]
  PIN hw_d[188]
    DIRECTION OUTPUT ;
    USE SIGNAL ;
    PORT
      LAYER M4 ;
        RECT 734.208 184.656 734.400 184.680 ;
    END
  END hw_d[188]
  PIN hw_d[189]
    DIRECTION OUTPUT ;
    USE SIGNAL ;
    PORT
      LAYER M4 ;
        RECT 734.208 185.568 734.400 185.592 ;
    END
  END hw_d[189]
  PIN hw_d[190]
    DIRECTION OUTPUT ;
    USE SIGNAL ;
    PORT
      LAYER M4 ;
        RECT 734.208 186.480 734.400 186.504 ;
    END
  END hw_d[190]
  PIN hw_d[191]
    DIRECTION OUTPUT ;
    USE SIGNAL ;
    PORT
      LAYER M4 ;
        RECT 734.208 187.392 734.400 187.416 ;
    END
  END hw_d[191]
  PIN hw_d[192]
    DIRECTION OUTPUT ;
    USE SIGNAL ;
    PORT
      LAYER M4 ;
        RECT 734.208 188.304 734.400 188.328 ;
    END
  END hw_d[192]
  PIN hw_d[193]
    DIRECTION OUTPUT ;
    USE SIGNAL ;
    PORT
      LAYER M4 ;
        RECT 734.208 189.168 734.400 189.192 ;
    END
  END hw_d[193]
  PIN hw_d[194]
    DIRECTION OUTPUT ;
    USE SIGNAL ;
    PORT
      LAYER M4 ;
        RECT 734.208 190.080 734.400 190.104 ;
    END
  END hw_d[194]
  PIN hw_d[195]
    DIRECTION OUTPUT ;
    USE SIGNAL ;
    PORT
      LAYER M4 ;
        RECT 734.208 190.992 734.400 191.016 ;
    END
  END hw_d[195]
  PIN hw_d[196]
    DIRECTION OUTPUT ;
    USE SIGNAL ;
    PORT
      LAYER M4 ;
        RECT 734.208 191.904 734.400 191.928 ;
    END
  END hw_d[196]
  PIN hw_d[197]
    DIRECTION OUTPUT ;
    USE SIGNAL ;
    PORT
      LAYER M4 ;
        RECT 734.208 192.816 734.400 192.840 ;
    END
  END hw_d[197]
  PIN hw_d[198]
    DIRECTION OUTPUT ;
    USE SIGNAL ;
    PORT
      LAYER M4 ;
        RECT 734.208 193.728 734.400 193.752 ;
    END
  END hw_d[198]
  PIN hw_d[199]
    DIRECTION OUTPUT ;
    USE SIGNAL ;
    PORT
      LAYER M4 ;
        RECT 734.208 194.592 734.400 194.616 ;
    END
  END hw_d[199]
  PIN hw_d[200]
    DIRECTION OUTPUT ;
    USE SIGNAL ;
    PORT
      LAYER M4 ;
        RECT 734.208 195.504 734.400 195.528 ;
    END
  END hw_d[200]
  PIN hw_d[201]
    DIRECTION OUTPUT ;
    USE SIGNAL ;
    PORT
      LAYER M4 ;
        RECT 734.208 196.416 734.400 196.440 ;
    END
  END hw_d[201]
  PIN hw_d[202]
    DIRECTION OUTPUT ;
    USE SIGNAL ;
    PORT
      LAYER M4 ;
        RECT 734.208 197.328 734.400 197.352 ;
    END
  END hw_d[202]
  PIN hw_d[203]
    DIRECTION OUTPUT ;
    USE SIGNAL ;
    PORT
      LAYER M4 ;
        RECT 734.208 198.240 734.400 198.264 ;
    END
  END hw_d[203]
  PIN hw_d[204]
    DIRECTION OUTPUT ;
    USE SIGNAL ;
    PORT
      LAYER M4 ;
        RECT 734.208 199.152 734.400 199.176 ;
    END
  END hw_d[204]
  PIN hw_d[205]
    DIRECTION OUTPUT ;
    USE SIGNAL ;
    PORT
      LAYER M4 ;
        RECT 734.208 200.064 734.400 200.088 ;
    END
  END hw_d[205]
  PIN hw_d[206]
    DIRECTION OUTPUT ;
    USE SIGNAL ;
    PORT
      LAYER M4 ;
        RECT 734.208 200.928 734.400 200.952 ;
    END
  END hw_d[206]
  PIN hw_d[207]
    DIRECTION OUTPUT ;
    USE SIGNAL ;
    PORT
      LAYER M4 ;
        RECT 734.208 201.840 734.400 201.864 ;
    END
  END hw_d[207]
  PIN hw_d[208]
    DIRECTION OUTPUT ;
    USE SIGNAL ;
    PORT
      LAYER M4 ;
        RECT 734.208 202.752 734.400 202.776 ;
    END
  END hw_d[208]
  PIN hw_d[209]
    DIRECTION OUTPUT ;
    USE SIGNAL ;
    PORT
      LAYER M4 ;
        RECT 734.208 203.664 734.400 203.688 ;
    END
  END hw_d[209]
  PIN hw_d[210]
    DIRECTION OUTPUT ;
    USE SIGNAL ;
    PORT
      LAYER M4 ;
        RECT 734.208 204.576 734.400 204.600 ;
    END
  END hw_d[210]
  PIN hw_d[211]
    DIRECTION OUTPUT ;
    USE SIGNAL ;
    PORT
      LAYER M4 ;
        RECT 734.208 205.488 734.400 205.512 ;
    END
  END hw_d[211]
  PIN hw_d[212]
    DIRECTION OUTPUT ;
    USE SIGNAL ;
    PORT
      LAYER M4 ;
        RECT 734.208 206.400 734.400 206.424 ;
    END
  END hw_d[212]
  PIN hw_d[213]
    DIRECTION OUTPUT ;
    USE SIGNAL ;
    PORT
      LAYER M4 ;
        RECT 734.208 207.264 734.400 207.288 ;
    END
  END hw_d[213]
  PIN hw_d[214]
    DIRECTION OUTPUT ;
    USE SIGNAL ;
    PORT
      LAYER M4 ;
        RECT 734.208 208.176 734.400 208.200 ;
    END
  END hw_d[214]
  PIN hw_d[215]
    DIRECTION OUTPUT ;
    USE SIGNAL ;
    PORT
      LAYER M4 ;
        RECT 734.208 209.088 734.400 209.112 ;
    END
  END hw_d[215]
  PIN hw_d[216]
    DIRECTION OUTPUT ;
    USE SIGNAL ;
    PORT
      LAYER M4 ;
        RECT 734.208 210.000 734.400 210.024 ;
    END
  END hw_d[216]
  PIN hw_d[217]
    DIRECTION OUTPUT ;
    USE SIGNAL ;
    PORT
      LAYER M4 ;
        RECT 734.208 210.912 734.400 210.936 ;
    END
  END hw_d[217]
  PIN hw_d[218]
    DIRECTION OUTPUT ;
    USE SIGNAL ;
    PORT
      LAYER M4 ;
        RECT 734.208 211.824 734.400 211.848 ;
    END
  END hw_d[218]
  PIN hw_d[219]
    DIRECTION OUTPUT ;
    USE SIGNAL ;
    PORT
      LAYER M4 ;
        RECT 734.208 212.688 734.400 212.712 ;
    END
  END hw_d[219]
  PIN hw_d[220]
    DIRECTION OUTPUT ;
    USE SIGNAL ;
    PORT
      LAYER M4 ;
        RECT 734.208 213.600 734.400 213.624 ;
    END
  END hw_d[220]
  PIN hw_d[221]
    DIRECTION OUTPUT ;
    USE SIGNAL ;
    PORT
      LAYER M4 ;
        RECT 734.208 214.512 734.400 214.536 ;
    END
  END hw_d[221]
  PIN hw_d[222]
    DIRECTION OUTPUT ;
    USE SIGNAL ;
    PORT
      LAYER M4 ;
        RECT 734.208 215.424 734.400 215.448 ;
    END
  END hw_d[222]
  PIN hw_d[223]
    DIRECTION OUTPUT ;
    USE SIGNAL ;
    PORT
      LAYER M4 ;
        RECT 734.208 216.336 734.400 216.360 ;
    END
  END hw_d[223]
  PIN hw_d[224]
    DIRECTION OUTPUT ;
    USE SIGNAL ;
    PORT
      LAYER M4 ;
        RECT 734.208 217.248 734.400 217.272 ;
    END
  END hw_d[224]
  PIN hw_d[225]
    DIRECTION OUTPUT ;
    USE SIGNAL ;
    PORT
      LAYER M4 ;
        RECT 734.208 218.160 734.400 218.184 ;
    END
  END hw_d[225]
  PIN hw_d[226]
    DIRECTION OUTPUT ;
    USE SIGNAL ;
    PORT
      LAYER M4 ;
        RECT 734.208 219.024 734.400 219.048 ;
    END
  END hw_d[226]
  PIN hw_d[227]
    DIRECTION OUTPUT ;
    USE SIGNAL ;
    PORT
      LAYER M4 ;
        RECT 734.208 219.936 734.400 219.960 ;
    END
  END hw_d[227]
  PIN hw_d[228]
    DIRECTION OUTPUT ;
    USE SIGNAL ;
    PORT
      LAYER M4 ;
        RECT 734.208 220.848 734.400 220.872 ;
    END
  END hw_d[228]
  PIN hw_d[229]
    DIRECTION OUTPUT ;
    USE SIGNAL ;
    PORT
      LAYER M4 ;
        RECT 734.208 221.760 734.400 221.784 ;
    END
  END hw_d[229]
  PIN hw_d[230]
    DIRECTION OUTPUT ;
    USE SIGNAL ;
    PORT
      LAYER M4 ;
        RECT 734.208 222.672 734.400 222.696 ;
    END
  END hw_d[230]
  PIN hw_d[231]
    DIRECTION OUTPUT ;
    USE SIGNAL ;
    PORT
      LAYER M4 ;
        RECT 734.208 223.584 734.400 223.608 ;
    END
  END hw_d[231]
  PIN hw_d[232]
    DIRECTION OUTPUT ;
    USE SIGNAL ;
    PORT
      LAYER M4 ;
        RECT 734.208 224.496 734.400 224.520 ;
    END
  END hw_d[232]
  PIN hw_d[233]
    DIRECTION OUTPUT ;
    USE SIGNAL ;
    PORT
      LAYER M4 ;
        RECT 734.208 225.360 734.400 225.384 ;
    END
  END hw_d[233]
  PIN hw_d[234]
    DIRECTION OUTPUT ;
    USE SIGNAL ;
    PORT
      LAYER M4 ;
        RECT 734.208 226.272 734.400 226.296 ;
    END
  END hw_d[234]
  PIN hw_d[235]
    DIRECTION OUTPUT ;
    USE SIGNAL ;
    PORT
      LAYER M4 ;
        RECT 734.208 227.184 734.400 227.208 ;
    END
  END hw_d[235]
  PIN hw_d[236]
    DIRECTION OUTPUT ;
    USE SIGNAL ;
    PORT
      LAYER M4 ;
        RECT 734.208 228.096 734.400 228.120 ;
    END
  END hw_d[236]
  PIN hw_d[237]
    DIRECTION OUTPUT ;
    USE SIGNAL ;
    PORT
      LAYER M4 ;
        RECT 734.208 229.008 734.400 229.032 ;
    END
  END hw_d[237]
  PIN hw_d[238]
    DIRECTION OUTPUT ;
    USE SIGNAL ;
    PORT
      LAYER M4 ;
        RECT 734.208 229.920 734.400 229.944 ;
    END
  END hw_d[238]
  PIN hw_d[239]
    DIRECTION OUTPUT ;
    USE SIGNAL ;
    PORT
      LAYER M4 ;
        RECT 734.208 230.784 734.400 230.808 ;
    END
  END hw_d[239]
  PIN hw_d[240]
    DIRECTION OUTPUT ;
    USE SIGNAL ;
    PORT
      LAYER M4 ;
        RECT 734.208 231.696 734.400 231.720 ;
    END
  END hw_d[240]
  PIN hw_d[241]
    DIRECTION OUTPUT ;
    USE SIGNAL ;
    PORT
      LAYER M4 ;
        RECT 734.208 232.608 734.400 232.632 ;
    END
  END hw_d[241]
  PIN hw_d[242]
    DIRECTION OUTPUT ;
    USE SIGNAL ;
    PORT
      LAYER M4 ;
        RECT 734.208 233.520 734.400 233.544 ;
    END
  END hw_d[242]
  PIN hw_d[243]
    DIRECTION OUTPUT ;
    USE SIGNAL ;
    PORT
      LAYER M4 ;
        RECT 734.208 234.432 734.400 234.456 ;
    END
  END hw_d[243]
  PIN hw_d[244]
    DIRECTION OUTPUT ;
    USE SIGNAL ;
    PORT
      LAYER M4 ;
        RECT 734.208 235.344 734.400 235.368 ;
    END
  END hw_d[244]
  PIN hw_d[245]
    DIRECTION OUTPUT ;
    USE SIGNAL ;
    PORT
      LAYER M4 ;
        RECT 734.208 236.256 734.400 236.280 ;
    END
  END hw_d[245]
  PIN hw_d[246]
    DIRECTION OUTPUT ;
    USE SIGNAL ;
    PORT
      LAYER M4 ;
        RECT 734.208 237.120 734.400 237.144 ;
    END
  END hw_d[246]
  PIN hw_d[247]
    DIRECTION OUTPUT ;
    USE SIGNAL ;
    PORT
      LAYER M4 ;
        RECT 734.208 238.032 734.400 238.056 ;
    END
  END hw_d[247]
  PIN hw_d[248]
    DIRECTION OUTPUT ;
    USE SIGNAL ;
    PORT
      LAYER M4 ;
        RECT 734.208 238.944 734.400 238.968 ;
    END
  END hw_d[248]
  PIN hw_d[249]
    DIRECTION OUTPUT ;
    USE SIGNAL ;
    PORT
      LAYER M4 ;
        RECT 734.208 239.856 734.400 239.880 ;
    END
  END hw_d[249]
  PIN hw_d[250]
    DIRECTION OUTPUT ;
    USE SIGNAL ;
    PORT
      LAYER M4 ;
        RECT 734.208 240.768 734.400 240.792 ;
    END
  END hw_d[250]
  PIN hw_d[251]
    DIRECTION OUTPUT ;
    USE SIGNAL ;
    PORT
      LAYER M4 ;
        RECT 734.208 241.680 734.400 241.704 ;
    END
  END hw_d[251]
  PIN hw_d[252]
    DIRECTION OUTPUT ;
    USE SIGNAL ;
    PORT
      LAYER M4 ;
        RECT 734.208 242.592 734.400 242.616 ;
    END
  END hw_d[252]
  PIN hw_d[253]
    DIRECTION OUTPUT ;
    USE SIGNAL ;
    PORT
      LAYER M4 ;
        RECT 734.208 243.456 734.400 243.480 ;
    END
  END hw_d[253]
  PIN hw_d[254]
    DIRECTION OUTPUT ;
    USE SIGNAL ;
    PORT
      LAYER M4 ;
        RECT 734.208 244.368 734.400 244.392 ;
    END
  END hw_d[254]
  PIN hw_d[255]
    DIRECTION OUTPUT ;
    USE SIGNAL ;
    PORT
      LAYER M4 ;
        RECT 734.208 245.280 734.400 245.304 ;
    END
  END hw_d[255]
  PIN hr_v
    DIRECTION OUTPUT ;
    USE SIGNAL ;
    PORT
      LAYER M4 ;
        RECT 734.208 247.008 734.400 247.032 ;
    END
  END hr_v
  PIN hr_j[0]
    DIRECTION OUTPUT ;
    USE SIGNAL ;
    PORT
      LAYER M4 ;
        RECT 734.208 248.688 734.400 248.712 ;
    END
  END hr_j[0]
  PIN hr_j[1]
    DIRECTION OUTPUT ;
    USE SIGNAL ;
    PORT
      LAYER M4 ;
        RECT 734.208 249.552 734.400 249.576 ;
    END
  END hr_j[1]
  PIN hr_j[2]
    DIRECTION OUTPUT ;
    USE SIGNAL ;
    PORT
      LAYER M4 ;
        RECT 734.208 250.416 734.400 250.440 ;
    END
  END hr_j[2]
  PIN hr_hf
    DIRECTION OUTPUT ;
    USE SIGNAL ;
    PORT
      LAYER M4 ;
        RECT 734.208 252.096 734.400 252.120 ;
    END
  END hr_hf
  PIN hq_v
    DIRECTION INPUT ;
    USE SIGNAL ;
    PORT
      LAYER M4 ;
        RECT 734.208 254.640 734.400 254.664 ;
    END
  END hq_v
  PIN hq_d[0]
    DIRECTION INPUT ;
    USE SIGNAL ;
    PORT
      LAYER M4 ;
        RECT 734.208 256.368 734.400 256.392 ;
    END
  END hq_d[0]
  PIN hq_d[1]
    DIRECTION INPUT ;
    USE SIGNAL ;
    PORT
      LAYER M4 ;
        RECT 734.208 257.280 734.400 257.304 ;
    END
  END hq_d[1]
  PIN hq_d[2]
    DIRECTION INPUT ;
    USE SIGNAL ;
    PORT
      LAYER M4 ;
        RECT 734.208 258.192 734.400 258.216 ;
    END
  END hq_d[2]
  PIN hq_d[3]
    DIRECTION INPUT ;
    USE SIGNAL ;
    PORT
      LAYER M4 ;
        RECT 734.208 259.104 734.400 259.128 ;
    END
  END hq_d[3]
  PIN hq_d[4]
    DIRECTION INPUT ;
    USE SIGNAL ;
    PORT
      LAYER M4 ;
        RECT 734.208 260.016 734.400 260.040 ;
    END
  END hq_d[4]
  PIN hq_d[5]
    DIRECTION INPUT ;
    USE SIGNAL ;
    PORT
      LAYER M4 ;
        RECT 734.208 260.880 734.400 260.904 ;
    END
  END hq_d[5]
  PIN hq_d[6]
    DIRECTION INPUT ;
    USE SIGNAL ;
    PORT
      LAYER M4 ;
        RECT 734.208 261.792 734.400 261.816 ;
    END
  END hq_d[6]
  PIN hq_d[7]
    DIRECTION INPUT ;
    USE SIGNAL ;
    PORT
      LAYER M4 ;
        RECT 734.208 262.704 734.400 262.728 ;
    END
  END hq_d[7]
  PIN hq_d[8]
    DIRECTION INPUT ;
    USE SIGNAL ;
    PORT
      LAYER M4 ;
        RECT 734.208 263.616 734.400 263.640 ;
    END
  END hq_d[8]
  PIN hq_d[9]
    DIRECTION INPUT ;
    USE SIGNAL ;
    PORT
      LAYER M4 ;
        RECT 734.208 264.528 734.400 264.552 ;
    END
  END hq_d[9]
  PIN hq_d[10]
    DIRECTION INPUT ;
    USE SIGNAL ;
    PORT
      LAYER M4 ;
        RECT 734.208 265.440 734.400 265.464 ;
    END
  END hq_d[10]
  PIN hq_d[11]
    DIRECTION INPUT ;
    USE SIGNAL ;
    PORT
      LAYER M4 ;
        RECT 734.208 266.352 734.400 266.376 ;
    END
  END hq_d[11]
  PIN hq_d[12]
    DIRECTION INPUT ;
    USE SIGNAL ;
    PORT
      LAYER M4 ;
        RECT 734.208 267.216 734.400 267.240 ;
    END
  END hq_d[12]
  PIN hq_d[13]
    DIRECTION INPUT ;
    USE SIGNAL ;
    PORT
      LAYER M4 ;
        RECT 734.208 268.128 734.400 268.152 ;
    END
  END hq_d[13]
  PIN hq_d[14]
    DIRECTION INPUT ;
    USE SIGNAL ;
    PORT
      LAYER M4 ;
        RECT 734.208 269.040 734.400 269.064 ;
    END
  END hq_d[14]
  PIN hq_d[15]
    DIRECTION INPUT ;
    USE SIGNAL ;
    PORT
      LAYER M4 ;
        RECT 734.208 269.952 734.400 269.976 ;
    END
  END hq_d[15]
  PIN hq_d[16]
    DIRECTION INPUT ;
    USE SIGNAL ;
    PORT
      LAYER M4 ;
        RECT 734.208 270.864 734.400 270.888 ;
    END
  END hq_d[16]
  PIN hq_d[17]
    DIRECTION INPUT ;
    USE SIGNAL ;
    PORT
      LAYER M4 ;
        RECT 734.208 271.776 734.400 271.800 ;
    END
  END hq_d[17]
  PIN hq_d[18]
    DIRECTION INPUT ;
    USE SIGNAL ;
    PORT
      LAYER M4 ;
        RECT 734.208 272.688 734.400 272.712 ;
    END
  END hq_d[18]
  PIN hq_d[19]
    DIRECTION INPUT ;
    USE SIGNAL ;
    PORT
      LAYER M4 ;
        RECT 734.208 273.552 734.400 273.576 ;
    END
  END hq_d[19]
  PIN hq_d[20]
    DIRECTION INPUT ;
    USE SIGNAL ;
    PORT
      LAYER M4 ;
        RECT 734.208 274.464 734.400 274.488 ;
    END
  END hq_d[20]
  PIN hq_d[21]
    DIRECTION INPUT ;
    USE SIGNAL ;
    PORT
      LAYER M4 ;
        RECT 734.208 275.376 734.400 275.400 ;
    END
  END hq_d[21]
  PIN hq_d[22]
    DIRECTION INPUT ;
    USE SIGNAL ;
    PORT
      LAYER M4 ;
        RECT 734.208 276.288 734.400 276.312 ;
    END
  END hq_d[22]
  PIN hq_d[23]
    DIRECTION INPUT ;
    USE SIGNAL ;
    PORT
      LAYER M4 ;
        RECT 734.208 277.200 734.400 277.224 ;
    END
  END hq_d[23]
  PIN hq_d[24]
    DIRECTION INPUT ;
    USE SIGNAL ;
    PORT
      LAYER M4 ;
        RECT 734.208 278.112 734.400 278.136 ;
    END
  END hq_d[24]
  PIN hq_d[25]
    DIRECTION INPUT ;
    USE SIGNAL ;
    PORT
      LAYER M4 ;
        RECT 734.208 278.976 734.400 279.000 ;
    END
  END hq_d[25]
  PIN hq_d[26]
    DIRECTION INPUT ;
    USE SIGNAL ;
    PORT
      LAYER M4 ;
        RECT 734.208 279.888 734.400 279.912 ;
    END
  END hq_d[26]
  PIN hq_d[27]
    DIRECTION INPUT ;
    USE SIGNAL ;
    PORT
      LAYER M4 ;
        RECT 734.208 280.800 734.400 280.824 ;
    END
  END hq_d[27]
  PIN hq_d[28]
    DIRECTION INPUT ;
    USE SIGNAL ;
    PORT
      LAYER M4 ;
        RECT 734.208 281.712 734.400 281.736 ;
    END
  END hq_d[28]
  PIN hq_d[29]
    DIRECTION INPUT ;
    USE SIGNAL ;
    PORT
      LAYER M4 ;
        RECT 734.208 282.624 734.400 282.648 ;
    END
  END hq_d[29]
  PIN hq_d[30]
    DIRECTION INPUT ;
    USE SIGNAL ;
    PORT
      LAYER M4 ;
        RECT 734.208 283.536 734.400 283.560 ;
    END
  END hq_d[30]
  PIN hq_d[31]
    DIRECTION INPUT ;
    USE SIGNAL ;
    PORT
      LAYER M4 ;
        RECT 734.208 284.448 734.400 284.472 ;
    END
  END hq_d[31]
  PIN hq_d[32]
    DIRECTION INPUT ;
    USE SIGNAL ;
    PORT
      LAYER M4 ;
        RECT 734.208 285.312 734.400 285.336 ;
    END
  END hq_d[32]
  PIN hq_d[33]
    DIRECTION INPUT ;
    USE SIGNAL ;
    PORT
      LAYER M4 ;
        RECT 734.208 286.224 734.400 286.248 ;
    END
  END hq_d[33]
  PIN hq_d[34]
    DIRECTION INPUT ;
    USE SIGNAL ;
    PORT
      LAYER M4 ;
        RECT 734.208 287.136 734.400 287.160 ;
    END
  END hq_d[34]
  PIN hq_d[35]
    DIRECTION INPUT ;
    USE SIGNAL ;
    PORT
      LAYER M4 ;
        RECT 734.208 288.048 734.400 288.072 ;
    END
  END hq_d[35]
  PIN hq_d[36]
    DIRECTION INPUT ;
    USE SIGNAL ;
    PORT
      LAYER M4 ;
        RECT 734.208 288.960 734.400 288.984 ;
    END
  END hq_d[36]
  PIN hq_d[37]
    DIRECTION INPUT ;
    USE SIGNAL ;
    PORT
      LAYER M4 ;
        RECT 734.208 289.872 734.400 289.896 ;
    END
  END hq_d[37]
  PIN hq_d[38]
    DIRECTION INPUT ;
    USE SIGNAL ;
    PORT
      LAYER M4 ;
        RECT 734.208 290.784 734.400 290.808 ;
    END
  END hq_d[38]
  PIN hq_d[39]
    DIRECTION INPUT ;
    USE SIGNAL ;
    PORT
      LAYER M4 ;
        RECT 734.208 291.648 734.400 291.672 ;
    END
  END hq_d[39]
  PIN hq_d[40]
    DIRECTION INPUT ;
    USE SIGNAL ;
    PORT
      LAYER M4 ;
        RECT 734.208 292.560 734.400 292.584 ;
    END
  END hq_d[40]
  PIN hq_d[41]
    DIRECTION INPUT ;
    USE SIGNAL ;
    PORT
      LAYER M4 ;
        RECT 734.208 293.472 734.400 293.496 ;
    END
  END hq_d[41]
  PIN hq_d[42]
    DIRECTION INPUT ;
    USE SIGNAL ;
    PORT
      LAYER M4 ;
        RECT 734.208 294.384 734.400 294.408 ;
    END
  END hq_d[42]
  PIN hq_d[43]
    DIRECTION INPUT ;
    USE SIGNAL ;
    PORT
      LAYER M4 ;
        RECT 734.208 295.296 734.400 295.320 ;
    END
  END hq_d[43]
  PIN hq_d[44]
    DIRECTION INPUT ;
    USE SIGNAL ;
    PORT
      LAYER M4 ;
        RECT 734.208 296.208 734.400 296.232 ;
    END
  END hq_d[44]
  PIN hq_d[45]
    DIRECTION INPUT ;
    USE SIGNAL ;
    PORT
      LAYER M4 ;
        RECT 734.208 297.072 734.400 297.096 ;
    END
  END hq_d[45]
  PIN hq_d[46]
    DIRECTION INPUT ;
    USE SIGNAL ;
    PORT
      LAYER M4 ;
        RECT 734.208 297.984 734.400 298.008 ;
    END
  END hq_d[46]
  PIN hq_d[47]
    DIRECTION INPUT ;
    USE SIGNAL ;
    PORT
      LAYER M4 ;
        RECT 734.208 298.896 734.400 298.920 ;
    END
  END hq_d[47]
  PIN hq_d[48]
    DIRECTION INPUT ;
    USE SIGNAL ;
    PORT
      LAYER M4 ;
        RECT 734.208 299.808 734.400 299.832 ;
    END
  END hq_d[48]
  PIN hq_d[49]
    DIRECTION INPUT ;
    USE SIGNAL ;
    PORT
      LAYER M4 ;
        RECT 734.208 300.720 734.400 300.744 ;
    END
  END hq_d[49]
  PIN hq_d[50]
    DIRECTION INPUT ;
    USE SIGNAL ;
    PORT
      LAYER M4 ;
        RECT 734.208 301.632 734.400 301.656 ;
    END
  END hq_d[50]
  PIN hq_d[51]
    DIRECTION INPUT ;
    USE SIGNAL ;
    PORT
      LAYER M4 ;
        RECT 734.208 302.544 734.400 302.568 ;
    END
  END hq_d[51]
  PIN hq_d[52]
    DIRECTION INPUT ;
    USE SIGNAL ;
    PORT
      LAYER M4 ;
        RECT 734.208 303.408 734.400 303.432 ;
    END
  END hq_d[52]
  PIN hq_d[53]
    DIRECTION INPUT ;
    USE SIGNAL ;
    PORT
      LAYER M4 ;
        RECT 734.208 304.320 734.400 304.344 ;
    END
  END hq_d[53]
  PIN hq_d[54]
    DIRECTION INPUT ;
    USE SIGNAL ;
    PORT
      LAYER M4 ;
        RECT 734.208 305.232 734.400 305.256 ;
    END
  END hq_d[54]
  PIN hq_d[55]
    DIRECTION INPUT ;
    USE SIGNAL ;
    PORT
      LAYER M4 ;
        RECT 734.208 306.144 734.400 306.168 ;
    END
  END hq_d[55]
  PIN hq_d[56]
    DIRECTION INPUT ;
    USE SIGNAL ;
    PORT
      LAYER M4 ;
        RECT 734.208 307.056 734.400 307.080 ;
    END
  END hq_d[56]
  PIN hq_d[57]
    DIRECTION INPUT ;
    USE SIGNAL ;
    PORT
      LAYER M4 ;
        RECT 734.208 307.968 734.400 307.992 ;
    END
  END hq_d[57]
  PIN hq_d[58]
    DIRECTION INPUT ;
    USE SIGNAL ;
    PORT
      LAYER M4 ;
        RECT 734.208 308.880 734.400 308.904 ;
    END
  END hq_d[58]
  PIN hq_d[59]
    DIRECTION INPUT ;
    USE SIGNAL ;
    PORT
      LAYER M4 ;
        RECT 734.208 309.744 734.400 309.768 ;
    END
  END hq_d[59]
  PIN hq_d[60]
    DIRECTION INPUT ;
    USE SIGNAL ;
    PORT
      LAYER M4 ;
        RECT 734.208 310.656 734.400 310.680 ;
    END
  END hq_d[60]
  PIN hq_d[61]
    DIRECTION INPUT ;
    USE SIGNAL ;
    PORT
      LAYER M4 ;
        RECT 734.208 311.568 734.400 311.592 ;
    END
  END hq_d[61]
  PIN hq_d[62]
    DIRECTION INPUT ;
    USE SIGNAL ;
    PORT
      LAYER M4 ;
        RECT 734.208 312.480 734.400 312.504 ;
    END
  END hq_d[62]
  PIN hq_d[63]
    DIRECTION INPUT ;
    USE SIGNAL ;
    PORT
      LAYER M4 ;
        RECT 734.208 313.392 734.400 313.416 ;
    END
  END hq_d[63]
  PIN hq_d[64]
    DIRECTION INPUT ;
    USE SIGNAL ;
    PORT
      LAYER M4 ;
        RECT 734.208 314.304 734.400 314.328 ;
    END
  END hq_d[64]
  PIN hq_d[65]
    DIRECTION INPUT ;
    USE SIGNAL ;
    PORT
      LAYER M4 ;
        RECT 734.208 315.168 734.400 315.192 ;
    END
  END hq_d[65]
  PIN hq_d[66]
    DIRECTION INPUT ;
    USE SIGNAL ;
    PORT
      LAYER M4 ;
        RECT 734.208 316.080 734.400 316.104 ;
    END
  END hq_d[66]
  PIN hq_d[67]
    DIRECTION INPUT ;
    USE SIGNAL ;
    PORT
      LAYER M4 ;
        RECT 734.208 316.992 734.400 317.016 ;
    END
  END hq_d[67]
  PIN hq_d[68]
    DIRECTION INPUT ;
    USE SIGNAL ;
    PORT
      LAYER M4 ;
        RECT 734.208 317.904 734.400 317.928 ;
    END
  END hq_d[68]
  PIN hq_d[69]
    DIRECTION INPUT ;
    USE SIGNAL ;
    PORT
      LAYER M4 ;
        RECT 734.208 318.816 734.400 318.840 ;
    END
  END hq_d[69]
  PIN hq_d[70]
    DIRECTION INPUT ;
    USE SIGNAL ;
    PORT
      LAYER M4 ;
        RECT 734.208 319.728 734.400 319.752 ;
    END
  END hq_d[70]
  PIN hq_d[71]
    DIRECTION INPUT ;
    USE SIGNAL ;
    PORT
      LAYER M4 ;
        RECT 734.208 320.640 734.400 320.664 ;
    END
  END hq_d[71]
  PIN hq_d[72]
    DIRECTION INPUT ;
    USE SIGNAL ;
    PORT
      LAYER M4 ;
        RECT 734.208 321.504 734.400 321.528 ;
    END
  END hq_d[72]
  PIN hq_d[73]
    DIRECTION INPUT ;
    USE SIGNAL ;
    PORT
      LAYER M4 ;
        RECT 734.208 322.416 734.400 322.440 ;
    END
  END hq_d[73]
  PIN hq_d[74]
    DIRECTION INPUT ;
    USE SIGNAL ;
    PORT
      LAYER M4 ;
        RECT 734.208 323.328 734.400 323.352 ;
    END
  END hq_d[74]
  PIN hq_d[75]
    DIRECTION INPUT ;
    USE SIGNAL ;
    PORT
      LAYER M4 ;
        RECT 734.208 324.240 734.400 324.264 ;
    END
  END hq_d[75]
  PIN hq_d[76]
    DIRECTION INPUT ;
    USE SIGNAL ;
    PORT
      LAYER M4 ;
        RECT 734.208 325.152 734.400 325.176 ;
    END
  END hq_d[76]
  PIN hq_d[77]
    DIRECTION INPUT ;
    USE SIGNAL ;
    PORT
      LAYER M4 ;
        RECT 734.208 326.064 734.400 326.088 ;
    END
  END hq_d[77]
  PIN hq_d[78]
    DIRECTION INPUT ;
    USE SIGNAL ;
    PORT
      LAYER M4 ;
        RECT 734.208 326.928 734.400 326.952 ;
    END
  END hq_d[78]
  PIN hq_d[79]
    DIRECTION INPUT ;
    USE SIGNAL ;
    PORT
      LAYER M4 ;
        RECT 734.208 327.840 734.400 327.864 ;
    END
  END hq_d[79]
  PIN hq_d[80]
    DIRECTION INPUT ;
    USE SIGNAL ;
    PORT
      LAYER M4 ;
        RECT 734.208 328.752 734.400 328.776 ;
    END
  END hq_d[80]
  PIN hq_d[81]
    DIRECTION INPUT ;
    USE SIGNAL ;
    PORT
      LAYER M4 ;
        RECT 734.208 329.664 734.400 329.688 ;
    END
  END hq_d[81]
  PIN hq_d[82]
    DIRECTION INPUT ;
    USE SIGNAL ;
    PORT
      LAYER M4 ;
        RECT 734.208 330.576 734.400 330.600 ;
    END
  END hq_d[82]
  PIN hq_d[83]
    DIRECTION INPUT ;
    USE SIGNAL ;
    PORT
      LAYER M4 ;
        RECT 734.208 331.488 734.400 331.512 ;
    END
  END hq_d[83]
  PIN hq_d[84]
    DIRECTION INPUT ;
    USE SIGNAL ;
    PORT
      LAYER M4 ;
        RECT 734.208 332.400 734.400 332.424 ;
    END
  END hq_d[84]
  PIN hq_d[85]
    DIRECTION INPUT ;
    USE SIGNAL ;
    PORT
      LAYER M4 ;
        RECT 734.208 333.264 734.400 333.288 ;
    END
  END hq_d[85]
  PIN hq_d[86]
    DIRECTION INPUT ;
    USE SIGNAL ;
    PORT
      LAYER M4 ;
        RECT 734.208 334.176 734.400 334.200 ;
    END
  END hq_d[86]
  PIN hq_d[87]
    DIRECTION INPUT ;
    USE SIGNAL ;
    PORT
      LAYER M4 ;
        RECT 734.208 335.088 734.400 335.112 ;
    END
  END hq_d[87]
  PIN hq_d[88]
    DIRECTION INPUT ;
    USE SIGNAL ;
    PORT
      LAYER M4 ;
        RECT 734.208 336.000 734.400 336.024 ;
    END
  END hq_d[88]
  PIN hq_d[89]
    DIRECTION INPUT ;
    USE SIGNAL ;
    PORT
      LAYER M4 ;
        RECT 734.208 336.912 734.400 336.936 ;
    END
  END hq_d[89]
  PIN hq_d[90]
    DIRECTION INPUT ;
    USE SIGNAL ;
    PORT
      LAYER M4 ;
        RECT 734.208 337.824 734.400 337.848 ;
    END
  END hq_d[90]
  PIN hq_d[91]
    DIRECTION INPUT ;
    USE SIGNAL ;
    PORT
      LAYER M4 ;
        RECT 734.208 338.736 734.400 338.760 ;
    END
  END hq_d[91]
  PIN hq_d[92]
    DIRECTION INPUT ;
    USE SIGNAL ;
    PORT
      LAYER M4 ;
        RECT 734.208 339.600 734.400 339.624 ;
    END
  END hq_d[92]
  PIN hq_d[93]
    DIRECTION INPUT ;
    USE SIGNAL ;
    PORT
      LAYER M4 ;
        RECT 734.208 340.512 734.400 340.536 ;
    END
  END hq_d[93]
  PIN hq_d[94]
    DIRECTION INPUT ;
    USE SIGNAL ;
    PORT
      LAYER M4 ;
        RECT 734.208 341.424 734.400 341.448 ;
    END
  END hq_d[94]
  PIN hq_d[95]
    DIRECTION INPUT ;
    USE SIGNAL ;
    PORT
      LAYER M4 ;
        RECT 734.208 342.336 734.400 342.360 ;
    END
  END hq_d[95]
  PIN hq_d[96]
    DIRECTION INPUT ;
    USE SIGNAL ;
    PORT
      LAYER M4 ;
        RECT 734.208 343.248 734.400 343.272 ;
    END
  END hq_d[96]
  PIN hq_d[97]
    DIRECTION INPUT ;
    USE SIGNAL ;
    PORT
      LAYER M4 ;
        RECT 734.208 344.160 734.400 344.184 ;
    END
  END hq_d[97]
  PIN hq_d[98]
    DIRECTION INPUT ;
    USE SIGNAL ;
    PORT
      LAYER M4 ;
        RECT 734.208 345.024 734.400 345.048 ;
    END
  END hq_d[98]
  PIN hq_d[99]
    DIRECTION INPUT ;
    USE SIGNAL ;
    PORT
      LAYER M4 ;
        RECT 734.208 345.936 734.400 345.960 ;
    END
  END hq_d[99]
  PIN hq_d[100]
    DIRECTION INPUT ;
    USE SIGNAL ;
    PORT
      LAYER M4 ;
        RECT 734.208 346.848 734.400 346.872 ;
    END
  END hq_d[100]
  PIN hq_d[101]
    DIRECTION INPUT ;
    USE SIGNAL ;
    PORT
      LAYER M4 ;
        RECT 734.208 347.760 734.400 347.784 ;
    END
  END hq_d[101]
  PIN hq_d[102]
    DIRECTION INPUT ;
    USE SIGNAL ;
    PORT
      LAYER M4 ;
        RECT 734.208 348.672 734.400 348.696 ;
    END
  END hq_d[102]
  PIN hq_d[103]
    DIRECTION INPUT ;
    USE SIGNAL ;
    PORT
      LAYER M4 ;
        RECT 734.208 349.584 734.400 349.608 ;
    END
  END hq_d[103]
  PIN hq_d[104]
    DIRECTION INPUT ;
    USE SIGNAL ;
    PORT
      LAYER M4 ;
        RECT 734.208 350.496 734.400 350.520 ;
    END
  END hq_d[104]
  PIN hq_d[105]
    DIRECTION INPUT ;
    USE SIGNAL ;
    PORT
      LAYER M4 ;
        RECT 734.208 351.360 734.400 351.384 ;
    END
  END hq_d[105]
  PIN hq_d[106]
    DIRECTION INPUT ;
    USE SIGNAL ;
    PORT
      LAYER M4 ;
        RECT 734.208 352.272 734.400 352.296 ;
    END
  END hq_d[106]
  PIN hq_d[107]
    DIRECTION INPUT ;
    USE SIGNAL ;
    PORT
      LAYER M4 ;
        RECT 734.208 353.184 734.400 353.208 ;
    END
  END hq_d[107]
  PIN hq_d[108]
    DIRECTION INPUT ;
    USE SIGNAL ;
    PORT
      LAYER M4 ;
        RECT 734.208 354.096 734.400 354.120 ;
    END
  END hq_d[108]
  PIN hq_d[109]
    DIRECTION INPUT ;
    USE SIGNAL ;
    PORT
      LAYER M4 ;
        RECT 734.208 355.008 734.400 355.032 ;
    END
  END hq_d[109]
  PIN hq_d[110]
    DIRECTION INPUT ;
    USE SIGNAL ;
    PORT
      LAYER M4 ;
        RECT 734.208 355.920 734.400 355.944 ;
    END
  END hq_d[110]
  PIN hq_d[111]
    DIRECTION INPUT ;
    USE SIGNAL ;
    PORT
      LAYER M4 ;
        RECT 734.208 356.832 734.400 356.856 ;
    END
  END hq_d[111]
  PIN hq_d[112]
    DIRECTION INPUT ;
    USE SIGNAL ;
    PORT
      LAYER M4 ;
        RECT 734.208 357.696 734.400 357.720 ;
    END
  END hq_d[112]
  PIN hq_d[113]
    DIRECTION INPUT ;
    USE SIGNAL ;
    PORT
      LAYER M4 ;
        RECT 734.208 358.608 734.400 358.632 ;
    END
  END hq_d[113]
  PIN hq_d[114]
    DIRECTION INPUT ;
    USE SIGNAL ;
    PORT
      LAYER M4 ;
        RECT 734.208 359.520 734.400 359.544 ;
    END
  END hq_d[114]
  PIN hq_d[115]
    DIRECTION INPUT ;
    USE SIGNAL ;
    PORT
      LAYER M4 ;
        RECT 734.208 360.432 734.400 360.456 ;
    END
  END hq_d[115]
  PIN hq_d[116]
    DIRECTION INPUT ;
    USE SIGNAL ;
    PORT
      LAYER M4 ;
        RECT 734.208 361.344 734.400 361.368 ;
    END
  END hq_d[116]
  PIN hq_d[117]
    DIRECTION INPUT ;
    USE SIGNAL ;
    PORT
      LAYER M4 ;
        RECT 734.208 362.256 734.400 362.280 ;
    END
  END hq_d[117]
  PIN hq_d[118]
    DIRECTION INPUT ;
    USE SIGNAL ;
    PORT
      LAYER M4 ;
        RECT 734.208 363.120 734.400 363.144 ;
    END
  END hq_d[118]
  PIN hq_d[119]
    DIRECTION INPUT ;
    USE SIGNAL ;
    PORT
      LAYER M4 ;
        RECT 734.208 364.032 734.400 364.056 ;
    END
  END hq_d[119]
  PIN hq_d[120]
    DIRECTION INPUT ;
    USE SIGNAL ;
    PORT
      LAYER M4 ;
        RECT 734.208 364.944 734.400 364.968 ;
    END
  END hq_d[120]
  PIN hq_d[121]
    DIRECTION INPUT ;
    USE SIGNAL ;
    PORT
      LAYER M4 ;
        RECT 734.208 365.856 734.400 365.880 ;
    END
  END hq_d[121]
  PIN hq_d[122]
    DIRECTION INPUT ;
    USE SIGNAL ;
    PORT
      LAYER M4 ;
        RECT 734.208 366.768 734.400 366.792 ;
    END
  END hq_d[122]
  PIN hq_d[123]
    DIRECTION INPUT ;
    USE SIGNAL ;
    PORT
      LAYER M4 ;
        RECT 734.208 367.680 734.400 367.704 ;
    END
  END hq_d[123]
  PIN hq_d[124]
    DIRECTION INPUT ;
    USE SIGNAL ;
    PORT
      LAYER M4 ;
        RECT 734.208 368.592 734.400 368.616 ;
    END
  END hq_d[124]
  PIN hq_d[125]
    DIRECTION INPUT ;
    USE SIGNAL ;
    PORT
      LAYER M4 ;
        RECT 734.208 369.456 734.400 369.480 ;
    END
  END hq_d[125]
  PIN hq_d[126]
    DIRECTION INPUT ;
    USE SIGNAL ;
    PORT
      LAYER M4 ;
        RECT 734.208 370.368 734.400 370.392 ;
    END
  END hq_d[126]
  PIN hq_d[127]
    DIRECTION INPUT ;
    USE SIGNAL ;
    PORT
      LAYER M4 ;
        RECT 734.208 371.280 734.400 371.304 ;
    END
  END hq_d[127]
  PIN hq_d[128]
    DIRECTION INPUT ;
    USE SIGNAL ;
    PORT
      LAYER M4 ;
        RECT 734.208 372.192 734.400 372.216 ;
    END
  END hq_d[128]
  PIN hq_d[129]
    DIRECTION INPUT ;
    USE SIGNAL ;
    PORT
      LAYER M4 ;
        RECT 734.208 373.104 734.400 373.128 ;
    END
  END hq_d[129]
  PIN hq_d[130]
    DIRECTION INPUT ;
    USE SIGNAL ;
    PORT
      LAYER M4 ;
        RECT 734.208 374.016 734.400 374.040 ;
    END
  END hq_d[130]
  PIN hq_d[131]
    DIRECTION INPUT ;
    USE SIGNAL ;
    PORT
      LAYER M4 ;
        RECT 734.208 374.928 734.400 374.952 ;
    END
  END hq_d[131]
  PIN hq_d[132]
    DIRECTION INPUT ;
    USE SIGNAL ;
    PORT
      LAYER M4 ;
        RECT 734.208 375.792 734.400 375.816 ;
    END
  END hq_d[132]
  PIN hq_d[133]
    DIRECTION INPUT ;
    USE SIGNAL ;
    PORT
      LAYER M4 ;
        RECT 734.208 376.704 734.400 376.728 ;
    END
  END hq_d[133]
  PIN hq_d[134]
    DIRECTION INPUT ;
    USE SIGNAL ;
    PORT
      LAYER M4 ;
        RECT 734.208 377.616 734.400 377.640 ;
    END
  END hq_d[134]
  PIN hq_d[135]
    DIRECTION INPUT ;
    USE SIGNAL ;
    PORT
      LAYER M4 ;
        RECT 734.208 378.528 734.400 378.552 ;
    END
  END hq_d[135]
  PIN hq_d[136]
    DIRECTION INPUT ;
    USE SIGNAL ;
    PORT
      LAYER M4 ;
        RECT 734.208 379.440 734.400 379.464 ;
    END
  END hq_d[136]
  PIN hq_d[137]
    DIRECTION INPUT ;
    USE SIGNAL ;
    PORT
      LAYER M4 ;
        RECT 734.208 380.352 734.400 380.376 ;
    END
  END hq_d[137]
  PIN hq_d[138]
    DIRECTION INPUT ;
    USE SIGNAL ;
    PORT
      LAYER M4 ;
        RECT 734.208 381.216 734.400 381.240 ;
    END
  END hq_d[138]
  PIN hq_d[139]
    DIRECTION INPUT ;
    USE SIGNAL ;
    PORT
      LAYER M4 ;
        RECT 734.208 382.128 734.400 382.152 ;
    END
  END hq_d[139]
  PIN hq_d[140]
    DIRECTION INPUT ;
    USE SIGNAL ;
    PORT
      LAYER M4 ;
        RECT 734.208 383.040 734.400 383.064 ;
    END
  END hq_d[140]
  PIN hq_d[141]
    DIRECTION INPUT ;
    USE SIGNAL ;
    PORT
      LAYER M4 ;
        RECT 734.208 383.952 734.400 383.976 ;
    END
  END hq_d[141]
  PIN hq_d[142]
    DIRECTION INPUT ;
    USE SIGNAL ;
    PORT
      LAYER M4 ;
        RECT 734.208 384.864 734.400 384.888 ;
    END
  END hq_d[142]
  PIN hq_d[143]
    DIRECTION INPUT ;
    USE SIGNAL ;
    PORT
      LAYER M4 ;
        RECT 734.208 385.776 734.400 385.800 ;
    END
  END hq_d[143]
  PIN hq_d[144]
    DIRECTION INPUT ;
    USE SIGNAL ;
    PORT
      LAYER M4 ;
        RECT 734.208 386.688 734.400 386.712 ;
    END
  END hq_d[144]
  PIN hq_d[145]
    DIRECTION INPUT ;
    USE SIGNAL ;
    PORT
      LAYER M4 ;
        RECT 734.208 387.552 734.400 387.576 ;
    END
  END hq_d[145]
  PIN hq_d[146]
    DIRECTION INPUT ;
    USE SIGNAL ;
    PORT
      LAYER M4 ;
        RECT 734.208 388.464 734.400 388.488 ;
    END
  END hq_d[146]
  PIN hq_d[147]
    DIRECTION INPUT ;
    USE SIGNAL ;
    PORT
      LAYER M4 ;
        RECT 734.208 389.376 734.400 389.400 ;
    END
  END hq_d[147]
  PIN hq_d[148]
    DIRECTION INPUT ;
    USE SIGNAL ;
    PORT
      LAYER M4 ;
        RECT 734.208 390.288 734.400 390.312 ;
    END
  END hq_d[148]
  PIN hq_d[149]
    DIRECTION INPUT ;
    USE SIGNAL ;
    PORT
      LAYER M4 ;
        RECT 734.208 391.200 734.400 391.224 ;
    END
  END hq_d[149]
  PIN hq_d[150]
    DIRECTION INPUT ;
    USE SIGNAL ;
    PORT
      LAYER M4 ;
        RECT 734.208 392.112 734.400 392.136 ;
    END
  END hq_d[150]
  PIN hq_d[151]
    DIRECTION INPUT ;
    USE SIGNAL ;
    PORT
      LAYER M4 ;
        RECT 734.208 392.976 734.400 393.000 ;
    END
  END hq_d[151]
  PIN hq_d[152]
    DIRECTION INPUT ;
    USE SIGNAL ;
    PORT
      LAYER M4 ;
        RECT 734.208 393.888 734.400 393.912 ;
    END
  END hq_d[152]
  PIN hq_d[153]
    DIRECTION INPUT ;
    USE SIGNAL ;
    PORT
      LAYER M4 ;
        RECT 734.208 394.800 734.400 394.824 ;
    END
  END hq_d[153]
  PIN hq_d[154]
    DIRECTION INPUT ;
    USE SIGNAL ;
    PORT
      LAYER M4 ;
        RECT 734.208 395.712 734.400 395.736 ;
    END
  END hq_d[154]
  PIN hq_d[155]
    DIRECTION INPUT ;
    USE SIGNAL ;
    PORT
      LAYER M4 ;
        RECT 734.208 396.624 734.400 396.648 ;
    END
  END hq_d[155]
  PIN hq_d[156]
    DIRECTION INPUT ;
    USE SIGNAL ;
    PORT
      LAYER M4 ;
        RECT 734.208 397.536 734.400 397.560 ;
    END
  END hq_d[156]
  PIN hq_d[157]
    DIRECTION INPUT ;
    USE SIGNAL ;
    PORT
      LAYER M4 ;
        RECT 734.208 398.448 734.400 398.472 ;
    END
  END hq_d[157]
  PIN hq_d[158]
    DIRECTION INPUT ;
    USE SIGNAL ;
    PORT
      LAYER M4 ;
        RECT 734.208 399.312 734.400 399.336 ;
    END
  END hq_d[158]
  PIN hq_d[159]
    DIRECTION INPUT ;
    USE SIGNAL ;
    PORT
      LAYER M4 ;
        RECT 734.208 400.224 734.400 400.248 ;
    END
  END hq_d[159]
  PIN hq_d[160]
    DIRECTION INPUT ;
    USE SIGNAL ;
    PORT
      LAYER M4 ;
        RECT 734.208 401.136 734.400 401.160 ;
    END
  END hq_d[160]
  PIN hq_d[161]
    DIRECTION INPUT ;
    USE SIGNAL ;
    PORT
      LAYER M4 ;
        RECT 734.208 402.048 734.400 402.072 ;
    END
  END hq_d[161]
  PIN hq_d[162]
    DIRECTION INPUT ;
    USE SIGNAL ;
    PORT
      LAYER M4 ;
        RECT 734.208 402.960 734.400 402.984 ;
    END
  END hq_d[162]
  PIN hq_d[163]
    DIRECTION INPUT ;
    USE SIGNAL ;
    PORT
      LAYER M4 ;
        RECT 734.208 403.872 734.400 403.896 ;
    END
  END hq_d[163]
  PIN hq_d[164]
    DIRECTION INPUT ;
    USE SIGNAL ;
    PORT
      LAYER M4 ;
        RECT 734.208 404.784 734.400 404.808 ;
    END
  END hq_d[164]
  PIN hq_d[165]
    DIRECTION INPUT ;
    USE SIGNAL ;
    PORT
      LAYER M4 ;
        RECT 734.208 405.648 734.400 405.672 ;
    END
  END hq_d[165]
  PIN hq_d[166]
    DIRECTION INPUT ;
    USE SIGNAL ;
    PORT
      LAYER M4 ;
        RECT 734.208 406.560 734.400 406.584 ;
    END
  END hq_d[166]
  PIN hq_d[167]
    DIRECTION INPUT ;
    USE SIGNAL ;
    PORT
      LAYER M4 ;
        RECT 734.208 407.472 734.400 407.496 ;
    END
  END hq_d[167]
  PIN hq_d[168]
    DIRECTION INPUT ;
    USE SIGNAL ;
    PORT
      LAYER M4 ;
        RECT 734.208 408.384 734.400 408.408 ;
    END
  END hq_d[168]
  PIN hq_d[169]
    DIRECTION INPUT ;
    USE SIGNAL ;
    PORT
      LAYER M4 ;
        RECT 734.208 409.296 734.400 409.320 ;
    END
  END hq_d[169]
  PIN hq_d[170]
    DIRECTION INPUT ;
    USE SIGNAL ;
    PORT
      LAYER M4 ;
        RECT 734.208 410.208 734.400 410.232 ;
    END
  END hq_d[170]
  PIN hq_d[171]
    DIRECTION INPUT ;
    USE SIGNAL ;
    PORT
      LAYER M4 ;
        RECT 734.208 411.072 734.400 411.096 ;
    END
  END hq_d[171]
  PIN hq_d[172]
    DIRECTION INPUT ;
    USE SIGNAL ;
    PORT
      LAYER M4 ;
        RECT 734.208 411.984 734.400 412.008 ;
    END
  END hq_d[172]
  PIN hq_d[173]
    DIRECTION INPUT ;
    USE SIGNAL ;
    PORT
      LAYER M4 ;
        RECT 734.208 412.896 734.400 412.920 ;
    END
  END hq_d[173]
  PIN hq_d[174]
    DIRECTION INPUT ;
    USE SIGNAL ;
    PORT
      LAYER M4 ;
        RECT 734.208 413.808 734.400 413.832 ;
    END
  END hq_d[174]
  PIN hq_d[175]
    DIRECTION INPUT ;
    USE SIGNAL ;
    PORT
      LAYER M4 ;
        RECT 734.208 414.720 734.400 414.744 ;
    END
  END hq_d[175]
  PIN hq_d[176]
    DIRECTION INPUT ;
    USE SIGNAL ;
    PORT
      LAYER M4 ;
        RECT 734.208 415.632 734.400 415.656 ;
    END
  END hq_d[176]
  PIN hq_d[177]
    DIRECTION INPUT ;
    USE SIGNAL ;
    PORT
      LAYER M4 ;
        RECT 734.208 416.544 734.400 416.568 ;
    END
  END hq_d[177]
  PIN hq_d[178]
    DIRECTION INPUT ;
    USE SIGNAL ;
    PORT
      LAYER M4 ;
        RECT 734.208 417.408 734.400 417.432 ;
    END
  END hq_d[178]
  PIN hq_d[179]
    DIRECTION INPUT ;
    USE SIGNAL ;
    PORT
      LAYER M4 ;
        RECT 734.208 418.320 734.400 418.344 ;
    END
  END hq_d[179]
  PIN hq_d[180]
    DIRECTION INPUT ;
    USE SIGNAL ;
    PORT
      LAYER M4 ;
        RECT 734.208 419.232 734.400 419.256 ;
    END
  END hq_d[180]
  PIN hq_d[181]
    DIRECTION INPUT ;
    USE SIGNAL ;
    PORT
      LAYER M4 ;
        RECT 734.208 420.144 734.400 420.168 ;
    END
  END hq_d[181]
  PIN hq_d[182]
    DIRECTION INPUT ;
    USE SIGNAL ;
    PORT
      LAYER M4 ;
        RECT 734.208 421.056 734.400 421.080 ;
    END
  END hq_d[182]
  PIN hq_d[183]
    DIRECTION INPUT ;
    USE SIGNAL ;
    PORT
      LAYER M4 ;
        RECT 734.208 421.968 734.400 421.992 ;
    END
  END hq_d[183]
  PIN hq_d[184]
    DIRECTION INPUT ;
    USE SIGNAL ;
    PORT
      LAYER M4 ;
        RECT 734.208 422.880 734.400 422.904 ;
    END
  END hq_d[184]
  PIN hq_d[185]
    DIRECTION INPUT ;
    USE SIGNAL ;
    PORT
      LAYER M4 ;
        RECT 734.208 423.744 734.400 423.768 ;
    END
  END hq_d[185]
  PIN hq_d[186]
    DIRECTION INPUT ;
    USE SIGNAL ;
    PORT
      LAYER M4 ;
        RECT 734.208 424.656 734.400 424.680 ;
    END
  END hq_d[186]
  PIN hq_d[187]
    DIRECTION INPUT ;
    USE SIGNAL ;
    PORT
      LAYER M4 ;
        RECT 734.208 425.568 734.400 425.592 ;
    END
  END hq_d[187]
  PIN hq_d[188]
    DIRECTION INPUT ;
    USE SIGNAL ;
    PORT
      LAYER M4 ;
        RECT 734.208 426.480 734.400 426.504 ;
    END
  END hq_d[188]
  PIN hq_d[189]
    DIRECTION INPUT ;
    USE SIGNAL ;
    PORT
      LAYER M4 ;
        RECT 734.208 427.392 734.400 427.416 ;
    END
  END hq_d[189]
  PIN hq_d[190]
    DIRECTION INPUT ;
    USE SIGNAL ;
    PORT
      LAYER M4 ;
        RECT 734.208 428.304 734.400 428.328 ;
    END
  END hq_d[190]
  PIN hq_d[191]
    DIRECTION INPUT ;
    USE SIGNAL ;
    PORT
      LAYER M4 ;
        RECT 734.208 429.168 734.400 429.192 ;
    END
  END hq_d[191]
  PIN hq_d[192]
    DIRECTION INPUT ;
    USE SIGNAL ;
    PORT
      LAYER M4 ;
        RECT 734.208 430.080 734.400 430.104 ;
    END
  END hq_d[192]
  PIN hq_d[193]
    DIRECTION INPUT ;
    USE SIGNAL ;
    PORT
      LAYER M4 ;
        RECT 734.208 430.992 734.400 431.016 ;
    END
  END hq_d[193]
  PIN hq_d[194]
    DIRECTION INPUT ;
    USE SIGNAL ;
    PORT
      LAYER M4 ;
        RECT 734.208 431.904 734.400 431.928 ;
    END
  END hq_d[194]
  PIN hq_d[195]
    DIRECTION INPUT ;
    USE SIGNAL ;
    PORT
      LAYER M4 ;
        RECT 734.208 432.816 734.400 432.840 ;
    END
  END hq_d[195]
  PIN hq_d[196]
    DIRECTION INPUT ;
    USE SIGNAL ;
    PORT
      LAYER M4 ;
        RECT 734.208 433.728 734.400 433.752 ;
    END
  END hq_d[196]
  PIN hq_d[197]
    DIRECTION INPUT ;
    USE SIGNAL ;
    PORT
      LAYER M4 ;
        RECT 734.208 434.640 734.400 434.664 ;
    END
  END hq_d[197]
  PIN hq_d[198]
    DIRECTION INPUT ;
    USE SIGNAL ;
    PORT
      LAYER M4 ;
        RECT 734.208 435.504 734.400 435.528 ;
    END
  END hq_d[198]
  PIN hq_d[199]
    DIRECTION INPUT ;
    USE SIGNAL ;
    PORT
      LAYER M4 ;
        RECT 734.208 436.416 734.400 436.440 ;
    END
  END hq_d[199]
  PIN hq_d[200]
    DIRECTION INPUT ;
    USE SIGNAL ;
    PORT
      LAYER M4 ;
        RECT 734.208 437.328 734.400 437.352 ;
    END
  END hq_d[200]
  PIN hq_d[201]
    DIRECTION INPUT ;
    USE SIGNAL ;
    PORT
      LAYER M4 ;
        RECT 734.208 438.240 734.400 438.264 ;
    END
  END hq_d[201]
  PIN hq_d[202]
    DIRECTION INPUT ;
    USE SIGNAL ;
    PORT
      LAYER M4 ;
        RECT 734.208 439.152 734.400 439.176 ;
    END
  END hq_d[202]
  PIN hq_d[203]
    DIRECTION INPUT ;
    USE SIGNAL ;
    PORT
      LAYER M4 ;
        RECT 734.208 440.064 734.400 440.088 ;
    END
  END hq_d[203]
  PIN hq_d[204]
    DIRECTION INPUT ;
    USE SIGNAL ;
    PORT
      LAYER M4 ;
        RECT 734.208 440.976 734.400 441.000 ;
    END
  END hq_d[204]
  PIN hq_d[205]
    DIRECTION INPUT ;
    USE SIGNAL ;
    PORT
      LAYER M4 ;
        RECT 734.208 441.840 734.400 441.864 ;
    END
  END hq_d[205]
  PIN hq_d[206]
    DIRECTION INPUT ;
    USE SIGNAL ;
    PORT
      LAYER M4 ;
        RECT 734.208 442.752 734.400 442.776 ;
    END
  END hq_d[206]
  PIN hq_d[207]
    DIRECTION INPUT ;
    USE SIGNAL ;
    PORT
      LAYER M4 ;
        RECT 734.208 443.664 734.400 443.688 ;
    END
  END hq_d[207]
  PIN hq_d[208]
    DIRECTION INPUT ;
    USE SIGNAL ;
    PORT
      LAYER M4 ;
        RECT 734.208 444.576 734.400 444.600 ;
    END
  END hq_d[208]
  PIN hq_d[209]
    DIRECTION INPUT ;
    USE SIGNAL ;
    PORT
      LAYER M4 ;
        RECT 734.208 445.488 734.400 445.512 ;
    END
  END hq_d[209]
  PIN hq_d[210]
    DIRECTION INPUT ;
    USE SIGNAL ;
    PORT
      LAYER M4 ;
        RECT 734.208 446.400 734.400 446.424 ;
    END
  END hq_d[210]
  PIN hq_d[211]
    DIRECTION INPUT ;
    USE SIGNAL ;
    PORT
      LAYER M4 ;
        RECT 734.208 447.264 734.400 447.288 ;
    END
  END hq_d[211]
  PIN hq_d[212]
    DIRECTION INPUT ;
    USE SIGNAL ;
    PORT
      LAYER M4 ;
        RECT 734.208 448.176 734.400 448.200 ;
    END
  END hq_d[212]
  PIN hq_d[213]
    DIRECTION INPUT ;
    USE SIGNAL ;
    PORT
      LAYER M4 ;
        RECT 734.208 449.088 734.400 449.112 ;
    END
  END hq_d[213]
  PIN hq_d[214]
    DIRECTION INPUT ;
    USE SIGNAL ;
    PORT
      LAYER M4 ;
        RECT 734.208 450.000 734.400 450.024 ;
    END
  END hq_d[214]
  PIN hq_d[215]
    DIRECTION INPUT ;
    USE SIGNAL ;
    PORT
      LAYER M4 ;
        RECT 734.208 450.912 734.400 450.936 ;
    END
  END hq_d[215]
  PIN hq_d[216]
    DIRECTION INPUT ;
    USE SIGNAL ;
    PORT
      LAYER M4 ;
        RECT 734.208 451.824 734.400 451.848 ;
    END
  END hq_d[216]
  PIN hq_d[217]
    DIRECTION INPUT ;
    USE SIGNAL ;
    PORT
      LAYER M4 ;
        RECT 734.208 452.736 734.400 452.760 ;
    END
  END hq_d[217]
  PIN hq_d[218]
    DIRECTION INPUT ;
    USE SIGNAL ;
    PORT
      LAYER M4 ;
        RECT 734.208 453.600 734.400 453.624 ;
    END
  END hq_d[218]
  PIN hq_d[219]
    DIRECTION INPUT ;
    USE SIGNAL ;
    PORT
      LAYER M4 ;
        RECT 734.208 454.512 734.400 454.536 ;
    END
  END hq_d[219]
  PIN hq_d[220]
    DIRECTION INPUT ;
    USE SIGNAL ;
    PORT
      LAYER M4 ;
        RECT 734.208 455.424 734.400 455.448 ;
    END
  END hq_d[220]
  PIN hq_d[221]
    DIRECTION INPUT ;
    USE SIGNAL ;
    PORT
      LAYER M4 ;
        RECT 734.208 456.336 734.400 456.360 ;
    END
  END hq_d[221]
  PIN hq_d[222]
    DIRECTION INPUT ;
    USE SIGNAL ;
    PORT
      LAYER M4 ;
        RECT 734.208 457.248 734.400 457.272 ;
    END
  END hq_d[222]
  PIN hq_d[223]
    DIRECTION INPUT ;
    USE SIGNAL ;
    PORT
      LAYER M4 ;
        RECT 734.208 458.160 734.400 458.184 ;
    END
  END hq_d[223]
  PIN hq_d[224]
    DIRECTION INPUT ;
    USE SIGNAL ;
    PORT
      LAYER M4 ;
        RECT 734.208 459.024 734.400 459.048 ;
    END
  END hq_d[224]
  PIN hq_d[225]
    DIRECTION INPUT ;
    USE SIGNAL ;
    PORT
      LAYER M4 ;
        RECT 734.208 459.936 734.400 459.960 ;
    END
  END hq_d[225]
  PIN hq_d[226]
    DIRECTION INPUT ;
    USE SIGNAL ;
    PORT
      LAYER M4 ;
        RECT 734.208 460.848 734.400 460.872 ;
    END
  END hq_d[226]
  PIN hq_d[227]
    DIRECTION INPUT ;
    USE SIGNAL ;
    PORT
      LAYER M4 ;
        RECT 734.208 461.760 734.400 461.784 ;
    END
  END hq_d[227]
  PIN hq_d[228]
    DIRECTION INPUT ;
    USE SIGNAL ;
    PORT
      LAYER M4 ;
        RECT 734.208 462.672 734.400 462.696 ;
    END
  END hq_d[228]
  PIN hq_d[229]
    DIRECTION INPUT ;
    USE SIGNAL ;
    PORT
      LAYER M4 ;
        RECT 734.208 463.584 734.400 463.608 ;
    END
  END hq_d[229]
  PIN hq_d[230]
    DIRECTION INPUT ;
    USE SIGNAL ;
    PORT
      LAYER M4 ;
        RECT 734.208 464.496 734.400 464.520 ;
    END
  END hq_d[230]
  PIN hq_d[231]
    DIRECTION INPUT ;
    USE SIGNAL ;
    PORT
      LAYER M4 ;
        RECT 734.208 465.360 734.400 465.384 ;
    END
  END hq_d[231]
  PIN hq_d[232]
    DIRECTION INPUT ;
    USE SIGNAL ;
    PORT
      LAYER M4 ;
        RECT 734.208 466.272 734.400 466.296 ;
    END
  END hq_d[232]
  PIN hq_d[233]
    DIRECTION INPUT ;
    USE SIGNAL ;
    PORT
      LAYER M4 ;
        RECT 734.208 467.184 734.400 467.208 ;
    END
  END hq_d[233]
  PIN hq_d[234]
    DIRECTION INPUT ;
    USE SIGNAL ;
    PORT
      LAYER M4 ;
        RECT 734.208 468.096 734.400 468.120 ;
    END
  END hq_d[234]
  PIN hq_d[235]
    DIRECTION INPUT ;
    USE SIGNAL ;
    PORT
      LAYER M4 ;
        RECT 734.208 469.008 734.400 469.032 ;
    END
  END hq_d[235]
  PIN hq_d[236]
    DIRECTION INPUT ;
    USE SIGNAL ;
    PORT
      LAYER M4 ;
        RECT 734.208 469.920 734.400 469.944 ;
    END
  END hq_d[236]
  PIN hq_d[237]
    DIRECTION INPUT ;
    USE SIGNAL ;
    PORT
      LAYER M4 ;
        RECT 734.208 470.832 734.400 470.856 ;
    END
  END hq_d[237]
  PIN hq_d[238]
    DIRECTION INPUT ;
    USE SIGNAL ;
    PORT
      LAYER M4 ;
        RECT 734.208 471.696 734.400 471.720 ;
    END
  END hq_d[238]
  PIN hq_d[239]
    DIRECTION INPUT ;
    USE SIGNAL ;
    PORT
      LAYER M4 ;
        RECT 734.208 472.608 734.400 472.632 ;
    END
  END hq_d[239]
  PIN hq_d[240]
    DIRECTION INPUT ;
    USE SIGNAL ;
    PORT
      LAYER M4 ;
        RECT 734.208 473.520 734.400 473.544 ;
    END
  END hq_d[240]
  PIN hq_d[241]
    DIRECTION INPUT ;
    USE SIGNAL ;
    PORT
      LAYER M4 ;
        RECT 734.208 474.432 734.400 474.456 ;
    END
  END hq_d[241]
  PIN hq_d[242]
    DIRECTION INPUT ;
    USE SIGNAL ;
    PORT
      LAYER M4 ;
        RECT 734.208 475.344 734.400 475.368 ;
    END
  END hq_d[242]
  PIN hq_d[243]
    DIRECTION INPUT ;
    USE SIGNAL ;
    PORT
      LAYER M4 ;
        RECT 734.208 476.256 734.400 476.280 ;
    END
  END hq_d[243]
  PIN hq_d[244]
    DIRECTION INPUT ;
    USE SIGNAL ;
    PORT
      LAYER M4 ;
        RECT 734.208 477.120 734.400 477.144 ;
    END
  END hq_d[244]
  PIN hq_d[245]
    DIRECTION INPUT ;
    USE SIGNAL ;
    PORT
      LAYER M4 ;
        RECT 734.208 478.032 734.400 478.056 ;
    END
  END hq_d[245]
  PIN hq_d[246]
    DIRECTION INPUT ;
    USE SIGNAL ;
    PORT
      LAYER M4 ;
        RECT 734.208 478.944 734.400 478.968 ;
    END
  END hq_d[246]
  PIN hq_d[247]
    DIRECTION INPUT ;
    USE SIGNAL ;
    PORT
      LAYER M4 ;
        RECT 734.208 479.856 734.400 479.880 ;
    END
  END hq_d[247]
  PIN hq_d[248]
    DIRECTION INPUT ;
    USE SIGNAL ;
    PORT
      LAYER M4 ;
        RECT 734.208 480.768 734.400 480.792 ;
    END
  END hq_d[248]
  PIN hq_d[249]
    DIRECTION INPUT ;
    USE SIGNAL ;
    PORT
      LAYER M4 ;
        RECT 734.208 481.680 734.400 481.704 ;
    END
  END hq_d[249]
  PIN hq_d[250]
    DIRECTION INPUT ;
    USE SIGNAL ;
    PORT
      LAYER M4 ;
        RECT 734.208 482.592 734.400 482.616 ;
    END
  END hq_d[250]
  PIN hq_d[251]
    DIRECTION INPUT ;
    USE SIGNAL ;
    PORT
      LAYER M4 ;
        RECT 734.208 483.456 734.400 483.480 ;
    END
  END hq_d[251]
  PIN hq_d[252]
    DIRECTION INPUT ;
    USE SIGNAL ;
    PORT
      LAYER M4 ;
        RECT 734.208 484.368 734.400 484.392 ;
    END
  END hq_d[252]
  PIN hq_d[253]
    DIRECTION INPUT ;
    USE SIGNAL ;
    PORT
      LAYER M4 ;
        RECT 734.208 485.280 734.400 485.304 ;
    END
  END hq_d[253]
  PIN hq_d[254]
    DIRECTION INPUT ;
    USE SIGNAL ;
    PORT
      LAYER M4 ;
        RECT 734.208 486.192 734.400 486.216 ;
    END
  END hq_d[254]
  PIN hq_d[255]
    DIRECTION INPUT ;
    USE SIGNAL ;
    PORT
      LAYER M4 ;
        RECT 734.208 487.104 734.400 487.128 ;
    END
  END hq_d[255]
  PIN n_go
    DIRECTION OUTPUT ;
    USE SIGNAL ;
    PORT
      LAYER M4 ;
        RECT 734.208 488.832 734.400 488.856 ;
    END
  END n_go
  PIN n_pre[0]
    DIRECTION OUTPUT ;
    USE SIGNAL ;
    PORT
      LAYER M4 ;
        RECT 734.208 490.560 734.400 490.584 ;
    END
  END n_pre[0]
  PIN n_pre[1]
    DIRECTION OUTPUT ;
    USE SIGNAL ;
    PORT
      LAYER M4 ;
        RECT 734.208 491.472 734.400 491.496 ;
    END
  END n_pre[1]
  PIN n_pre[2]
    DIRECTION OUTPUT ;
    USE SIGNAL ;
    PORT
      LAYER M4 ;
        RECT 734.208 492.336 734.400 492.360 ;
    END
  END n_pre[2]
  PIN n_pre[3]
    DIRECTION OUTPUT ;
    USE SIGNAL ;
    PORT
      LAYER M4 ;
        RECT 734.208 493.248 734.400 493.272 ;
    END
  END n_pre[3]
  PIN n_pre[4]
    DIRECTION OUTPUT ;
    USE SIGNAL ;
    PORT
      LAYER M4 ;
        RECT 734.208 494.160 734.400 494.184 ;
    END
  END n_pre[4]
  PIN n_pre[5]
    DIRECTION OUTPUT ;
    USE SIGNAL ;
    PORT
      LAYER M4 ;
        RECT 734.208 495.072 734.400 495.096 ;
    END
  END n_pre[5]
  PIN n_pre[6]
    DIRECTION OUTPUT ;
    USE SIGNAL ;
    PORT
      LAYER M4 ;
        RECT 734.208 495.984 734.400 496.008 ;
    END
  END n_pre[6]
  PIN n_pre[7]
    DIRECTION OUTPUT ;
    USE SIGNAL ;
    PORT
      LAYER M4 ;
        RECT 734.208 496.896 734.400 496.920 ;
    END
  END n_pre[7]
  PIN n_pre[8]
    DIRECTION OUTPUT ;
    USE SIGNAL ;
    PORT
      LAYER M4 ;
        RECT 734.208 497.808 734.400 497.832 ;
    END
  END n_pre[8]
  PIN n_pre[9]
    DIRECTION OUTPUT ;
    USE SIGNAL ;
    PORT
      LAYER M4 ;
        RECT 734.208 498.672 734.400 498.696 ;
    END
  END n_pre[9]
  PIN n_pre[10]
    DIRECTION OUTPUT ;
    USE SIGNAL ;
    PORT
      LAYER M4 ;
        RECT 734.208 499.584 734.400 499.608 ;
    END
  END n_pre[10]
  PIN n_pre[11]
    DIRECTION OUTPUT ;
    USE SIGNAL ;
    PORT
      LAYER M4 ;
        RECT 734.208 500.496 734.400 500.520 ;
    END
  END n_pre[11]
  PIN n_pre[12]
    DIRECTION OUTPUT ;
    USE SIGNAL ;
    PORT
      LAYER M4 ;
        RECT 734.208 501.408 734.400 501.432 ;
    END
  END n_pre[12]
  PIN n_pre[13]
    DIRECTION OUTPUT ;
    USE SIGNAL ;
    PORT
      LAYER M4 ;
        RECT 734.208 502.320 734.400 502.344 ;
    END
  END n_pre[13]
  PIN n_pre[14]
    DIRECTION OUTPUT ;
    USE SIGNAL ;
    PORT
      LAYER M4 ;
        RECT 734.208 503.232 734.400 503.256 ;
    END
  END n_pre[14]
  PIN n_pre[15]
    DIRECTION OUTPUT ;
    USE SIGNAL ;
    PORT
      LAYER M4 ;
        RECT 734.208 504.096 734.400 504.120 ;
    END
  END n_pre[15]
  PIN n_pre[16]
    DIRECTION OUTPUT ;
    USE SIGNAL ;
    PORT
      LAYER M4 ;
        RECT 734.208 505.008 734.400 505.032 ;
    END
  END n_pre[16]
  PIN n_pre[17]
    DIRECTION OUTPUT ;
    USE SIGNAL ;
    PORT
      LAYER M4 ;
        RECT 734.208 505.920 734.400 505.944 ;
    END
  END n_pre[17]
  PIN n_pre[18]
    DIRECTION OUTPUT ;
    USE SIGNAL ;
    PORT
      LAYER M4 ;
        RECT 734.208 506.832 734.400 506.856 ;
    END
  END n_pre[18]
  PIN n_pre[19]
    DIRECTION OUTPUT ;
    USE SIGNAL ;
    PORT
      LAYER M4 ;
        RECT 734.208 507.744 734.400 507.768 ;
    END
  END n_pre[19]
  PIN n_pre[20]
    DIRECTION OUTPUT ;
    USE SIGNAL ;
    PORT
      LAYER M4 ;
        RECT 734.208 508.656 734.400 508.680 ;
    END
  END n_pre[20]
  PIN n_pre[21]
    DIRECTION OUTPUT ;
    USE SIGNAL ;
    PORT
      LAYER M4 ;
        RECT 734.208 509.568 734.400 509.592 ;
    END
  END n_pre[21]
  PIN n_pre[22]
    DIRECTION OUTPUT ;
    USE SIGNAL ;
    PORT
      LAYER M4 ;
        RECT 734.208 510.432 734.400 510.456 ;
    END
  END n_pre[22]
  PIN n_pre[23]
    DIRECTION OUTPUT ;
    USE SIGNAL ;
    PORT
      LAYER M4 ;
        RECT 734.208 511.344 734.400 511.368 ;
    END
  END n_pre[23]
  PIN n_pre[24]
    DIRECTION OUTPUT ;
    USE SIGNAL ;
    PORT
      LAYER M4 ;
        RECT 734.208 512.256 734.400 512.280 ;
    END
  END n_pre[24]
  PIN n_pre[25]
    DIRECTION OUTPUT ;
    USE SIGNAL ;
    PORT
      LAYER M4 ;
        RECT 734.208 513.168 734.400 513.192 ;
    END
  END n_pre[25]
  PIN n_pre[26]
    DIRECTION OUTPUT ;
    USE SIGNAL ;
    PORT
      LAYER M4 ;
        RECT 734.208 514.080 734.400 514.104 ;
    END
  END n_pre[26]
  PIN n_pre[27]
    DIRECTION OUTPUT ;
    USE SIGNAL ;
    PORT
      LAYER M4 ;
        RECT 734.208 514.992 734.400 515.016 ;
    END
  END n_pre[27]
  PIN n_pre[28]
    DIRECTION OUTPUT ;
    USE SIGNAL ;
    PORT
      LAYER M4 ;
        RECT 734.208 515.904 734.400 515.928 ;
    END
  END n_pre[28]
  PIN n_pre[29]
    DIRECTION OUTPUT ;
    USE SIGNAL ;
    PORT
      LAYER M4 ;
        RECT 734.208 516.768 734.400 516.792 ;
    END
  END n_pre[29]
  PIN n_pre[30]
    DIRECTION OUTPUT ;
    USE SIGNAL ;
    PORT
      LAYER M4 ;
        RECT 734.208 517.680 734.400 517.704 ;
    END
  END n_pre[30]
  PIN n_pre[31]
    DIRECTION OUTPUT ;
    USE SIGNAL ;
    PORT
      LAYER M4 ;
        RECT 734.208 518.592 734.400 518.616 ;
    END
  END n_pre[31]
  PIN n_pre[32]
    DIRECTION OUTPUT ;
    USE SIGNAL ;
    PORT
      LAYER M4 ;
        RECT 734.208 519.504 734.400 519.528 ;
    END
  END n_pre[32]
  PIN n_pre[33]
    DIRECTION OUTPUT ;
    USE SIGNAL ;
    PORT
      LAYER M4 ;
        RECT 734.208 520.416 734.400 520.440 ;
    END
  END n_pre[33]
  PIN n_pre[34]
    DIRECTION OUTPUT ;
    USE SIGNAL ;
    PORT
      LAYER M4 ;
        RECT 734.208 521.328 734.400 521.352 ;
    END
  END n_pre[34]
  PIN n_pre[35]
    DIRECTION OUTPUT ;
    USE SIGNAL ;
    PORT
      LAYER M4 ;
        RECT 734.208 522.192 734.400 522.216 ;
    END
  END n_pre[35]
  PIN n_pre[36]
    DIRECTION OUTPUT ;
    USE SIGNAL ;
    PORT
      LAYER M4 ;
        RECT 734.208 523.104 734.400 523.128 ;
    END
  END n_pre[36]
  PIN n_pre[37]
    DIRECTION OUTPUT ;
    USE SIGNAL ;
    PORT
      LAYER M4 ;
        RECT 734.208 524.016 734.400 524.040 ;
    END
  END n_pre[37]
  PIN n_pre[38]
    DIRECTION OUTPUT ;
    USE SIGNAL ;
    PORT
      LAYER M4 ;
        RECT 734.208 524.928 734.400 524.952 ;
    END
  END n_pre[38]
  PIN n_pre[39]
    DIRECTION OUTPUT ;
    USE SIGNAL ;
    PORT
      LAYER M4 ;
        RECT 734.208 525.840 734.400 525.864 ;
    END
  END n_pre[39]
  PIN n_pre[40]
    DIRECTION OUTPUT ;
    USE SIGNAL ;
    PORT
      LAYER M4 ;
        RECT 734.208 526.752 734.400 526.776 ;
    END
  END n_pre[40]
  PIN n_pre[41]
    DIRECTION OUTPUT ;
    USE SIGNAL ;
    PORT
      LAYER M4 ;
        RECT 734.208 527.664 734.400 527.688 ;
    END
  END n_pre[41]
  PIN n_pre[42]
    DIRECTION OUTPUT ;
    USE SIGNAL ;
    PORT
      LAYER M4 ;
        RECT 734.208 528.528 734.400 528.552 ;
    END
  END n_pre[42]
  PIN n_pre[43]
    DIRECTION OUTPUT ;
    USE SIGNAL ;
    PORT
      LAYER M4 ;
        RECT 734.208 529.440 734.400 529.464 ;
    END
  END n_pre[43]
  PIN n_pre[44]
    DIRECTION OUTPUT ;
    USE SIGNAL ;
    PORT
      LAYER M4 ;
        RECT 734.208 530.352 734.400 530.376 ;
    END
  END n_pre[44]
  PIN n_pre[45]
    DIRECTION OUTPUT ;
    USE SIGNAL ;
    PORT
      LAYER M4 ;
        RECT 734.208 531.264 734.400 531.288 ;
    END
  END n_pre[45]
  PIN n_pre[46]
    DIRECTION OUTPUT ;
    USE SIGNAL ;
    PORT
      LAYER M4 ;
        RECT 734.208 532.176 734.400 532.200 ;
    END
  END n_pre[46]
  PIN n_pre[47]
    DIRECTION OUTPUT ;
    USE SIGNAL ;
    PORT
      LAYER M4 ;
        RECT 734.208 533.088 734.400 533.112 ;
    END
  END n_pre[47]
  PIN n_pre[48]
    DIRECTION OUTPUT ;
    USE SIGNAL ;
    PORT
      LAYER M4 ;
        RECT 734.208 534.000 734.400 534.024 ;
    END
  END n_pre[48]
  PIN n_pre[49]
    DIRECTION OUTPUT ;
    USE SIGNAL ;
    PORT
      LAYER M4 ;
        RECT 734.208 534.864 734.400 534.888 ;
    END
  END n_pre[49]
  PIN n_pre[50]
    DIRECTION OUTPUT ;
    USE SIGNAL ;
    PORT
      LAYER M4 ;
        RECT 734.208 535.776 734.400 535.800 ;
    END
  END n_pre[50]
  PIN n_pre[51]
    DIRECTION OUTPUT ;
    USE SIGNAL ;
    PORT
      LAYER M4 ;
        RECT 734.208 536.688 734.400 536.712 ;
    END
  END n_pre[51]
  PIN n_pre[52]
    DIRECTION OUTPUT ;
    USE SIGNAL ;
    PORT
      LAYER M4 ;
        RECT 734.208 537.600 734.400 537.624 ;
    END
  END n_pre[52]
  PIN n_pre[53]
    DIRECTION OUTPUT ;
    USE SIGNAL ;
    PORT
      LAYER M4 ;
        RECT 734.208 538.512 734.400 538.536 ;
    END
  END n_pre[53]
  PIN n_pre[54]
    DIRECTION OUTPUT ;
    USE SIGNAL ;
    PORT
      LAYER M4 ;
        RECT 734.208 539.424 734.400 539.448 ;
    END
  END n_pre[54]
  PIN n_pre[55]
    DIRECTION OUTPUT ;
    USE SIGNAL ;
    PORT
      LAYER M4 ;
        RECT 734.208 540.288 734.400 540.312 ;
    END
  END n_pre[55]
  PIN n_pre[56]
    DIRECTION OUTPUT ;
    USE SIGNAL ;
    PORT
      LAYER M4 ;
        RECT 734.208 541.200 734.400 541.224 ;
    END
  END n_pre[56]
  PIN n_pre[57]
    DIRECTION OUTPUT ;
    USE SIGNAL ;
    PORT
      LAYER M4 ;
        RECT 734.208 542.112 734.400 542.136 ;
    END
  END n_pre[57]
  PIN n_pre[58]
    DIRECTION OUTPUT ;
    USE SIGNAL ;
    PORT
      LAYER M4 ;
        RECT 734.208 543.024 734.400 543.048 ;
    END
  END n_pre[58]
  PIN n_pre[59]
    DIRECTION OUTPUT ;
    USE SIGNAL ;
    PORT
      LAYER M4 ;
        RECT 734.208 543.936 734.400 543.960 ;
    END
  END n_pre[59]
  PIN n_pre[60]
    DIRECTION OUTPUT ;
    USE SIGNAL ;
    PORT
      LAYER M4 ;
        RECT 734.208 544.848 734.400 544.872 ;
    END
  END n_pre[60]
  PIN n_pre[61]
    DIRECTION OUTPUT ;
    USE SIGNAL ;
    PORT
      LAYER M4 ;
        RECT 734.208 545.760 734.400 545.784 ;
    END
  END n_pre[61]
  PIN n_pre[62]
    DIRECTION OUTPUT ;
    USE SIGNAL ;
    PORT
      LAYER M4 ;
        RECT 734.208 546.624 734.400 546.648 ;
    END
  END n_pre[62]
  PIN n_pre[63]
    DIRECTION OUTPUT ;
    USE SIGNAL ;
    PORT
      LAYER M4 ;
        RECT 734.208 547.536 734.400 547.560 ;
    END
  END n_pre[63]
  PIN n_pre[64]
    DIRECTION OUTPUT ;
    USE SIGNAL ;
    PORT
      LAYER M4 ;
        RECT 734.208 548.448 734.400 548.472 ;
    END
  END n_pre[64]
  PIN n_pre[65]
    DIRECTION OUTPUT ;
    USE SIGNAL ;
    PORT
      LAYER M4 ;
        RECT 734.208 549.360 734.400 549.384 ;
    END
  END n_pre[65]
  PIN n_pre[66]
    DIRECTION OUTPUT ;
    USE SIGNAL ;
    PORT
      LAYER M4 ;
        RECT 734.208 550.272 734.400 550.296 ;
    END
  END n_pre[66]
  PIN n_pre[67]
    DIRECTION OUTPUT ;
    USE SIGNAL ;
    PORT
      LAYER M4 ;
        RECT 734.208 551.184 734.400 551.208 ;
    END
  END n_pre[67]
  PIN n_pre[68]
    DIRECTION OUTPUT ;
    USE SIGNAL ;
    PORT
      LAYER M4 ;
        RECT 734.208 552.096 734.400 552.120 ;
    END
  END n_pre[68]
  PIN n_pre[69]
    DIRECTION OUTPUT ;
    USE SIGNAL ;
    PORT
      LAYER M4 ;
        RECT 734.208 552.960 734.400 552.984 ;
    END
  END n_pre[69]
  PIN n_pre[70]
    DIRECTION OUTPUT ;
    USE SIGNAL ;
    PORT
      LAYER M4 ;
        RECT 734.208 553.872 734.400 553.896 ;
    END
  END n_pre[70]
  PIN n_pre[71]
    DIRECTION OUTPUT ;
    USE SIGNAL ;
    PORT
      LAYER M4 ;
        RECT 734.208 554.784 734.400 554.808 ;
    END
  END n_pre[71]
  PIN n_pre[72]
    DIRECTION OUTPUT ;
    USE SIGNAL ;
    PORT
      LAYER M4 ;
        RECT 734.208 555.696 734.400 555.720 ;
    END
  END n_pre[72]
  PIN n_pre[73]
    DIRECTION OUTPUT ;
    USE SIGNAL ;
    PORT
      LAYER M4 ;
        RECT 734.208 556.608 734.400 556.632 ;
    END
  END n_pre[73]
  PIN n_pre[74]
    DIRECTION OUTPUT ;
    USE SIGNAL ;
    PORT
      LAYER M4 ;
        RECT 734.208 557.520 734.400 557.544 ;
    END
  END n_pre[74]
  PIN n_pre[75]
    DIRECTION OUTPUT ;
    USE SIGNAL ;
    PORT
      LAYER M4 ;
        RECT 734.208 558.384 734.400 558.408 ;
    END
  END n_pre[75]
  PIN n_pre[76]
    DIRECTION OUTPUT ;
    USE SIGNAL ;
    PORT
      LAYER M4 ;
        RECT 734.208 559.296 734.400 559.320 ;
    END
  END n_pre[76]
  PIN n_pre[77]
    DIRECTION OUTPUT ;
    USE SIGNAL ;
    PORT
      LAYER M4 ;
        RECT 734.208 560.208 734.400 560.232 ;
    END
  END n_pre[77]
  PIN n_pre[78]
    DIRECTION OUTPUT ;
    USE SIGNAL ;
    PORT
      LAYER M4 ;
        RECT 734.208 561.120 734.400 561.144 ;
    END
  END n_pre[78]
  PIN n_pre[79]
    DIRECTION OUTPUT ;
    USE SIGNAL ;
    PORT
      LAYER M4 ;
        RECT 734.208 562.032 734.400 562.056 ;
    END
  END n_pre[79]
  PIN n_pre[80]
    DIRECTION OUTPUT ;
    USE SIGNAL ;
    PORT
      LAYER M4 ;
        RECT 734.208 562.944 734.400 562.968 ;
    END
  END n_pre[80]
  PIN n_pre[81]
    DIRECTION OUTPUT ;
    USE SIGNAL ;
    PORT
      LAYER M4 ;
        RECT 734.208 563.856 734.400 563.880 ;
    END
  END n_pre[81]
  PIN n_pre[82]
    DIRECTION OUTPUT ;
    USE SIGNAL ;
    PORT
      LAYER M4 ;
        RECT 734.208 564.720 734.400 564.744 ;
    END
  END n_pre[82]
  PIN n_pre[83]
    DIRECTION OUTPUT ;
    USE SIGNAL ;
    PORT
      LAYER M4 ;
        RECT 734.208 565.632 734.400 565.656 ;
    END
  END n_pre[83]
  PIN n_pre[84]
    DIRECTION OUTPUT ;
    USE SIGNAL ;
    PORT
      LAYER M4 ;
        RECT 734.208 566.544 734.400 566.568 ;
    END
  END n_pre[84]
  PIN n_pre[85]
    DIRECTION OUTPUT ;
    USE SIGNAL ;
    PORT
      LAYER M4 ;
        RECT 734.208 567.456 734.400 567.480 ;
    END
  END n_pre[85]
  PIN n_pre[86]
    DIRECTION OUTPUT ;
    USE SIGNAL ;
    PORT
      LAYER M4 ;
        RECT 734.208 568.368 734.400 568.392 ;
    END
  END n_pre[86]
  PIN n_pre[87]
    DIRECTION OUTPUT ;
    USE SIGNAL ;
    PORT
      LAYER M4 ;
        RECT 734.208 569.280 734.400 569.304 ;
    END
  END n_pre[87]
  PIN n_pre[88]
    DIRECTION OUTPUT ;
    USE SIGNAL ;
    PORT
      LAYER M4 ;
        RECT 734.208 570.192 734.400 570.216 ;
    END
  END n_pre[88]
  PIN n_pre[89]
    DIRECTION OUTPUT ;
    USE SIGNAL ;
    PORT
      LAYER M4 ;
        RECT 734.208 571.056 734.400 571.080 ;
    END
  END n_pre[89]
  PIN n_pre[90]
    DIRECTION OUTPUT ;
    USE SIGNAL ;
    PORT
      LAYER M4 ;
        RECT 734.208 571.968 734.400 571.992 ;
    END
  END n_pre[90]
  PIN n_pre[91]
    DIRECTION OUTPUT ;
    USE SIGNAL ;
    PORT
      LAYER M4 ;
        RECT 734.208 572.880 734.400 572.904 ;
    END
  END n_pre[91]
  PIN n_pre[92]
    DIRECTION OUTPUT ;
    USE SIGNAL ;
    PORT
      LAYER M4 ;
        RECT 734.208 573.792 734.400 573.816 ;
    END
  END n_pre[92]
  PIN n_pre[93]
    DIRECTION OUTPUT ;
    USE SIGNAL ;
    PORT
      LAYER M4 ;
        RECT 734.208 574.704 734.400 574.728 ;
    END
  END n_pre[93]
  PIN n_pre[94]
    DIRECTION OUTPUT ;
    USE SIGNAL ;
    PORT
      LAYER M4 ;
        RECT 734.208 575.616 734.400 575.640 ;
    END
  END n_pre[94]
  PIN n_pre[95]
    DIRECTION OUTPUT ;
    USE SIGNAL ;
    PORT
      LAYER M4 ;
        RECT 734.208 576.480 734.400 576.504 ;
    END
  END n_pre[95]
  PIN n_pre[96]
    DIRECTION OUTPUT ;
    USE SIGNAL ;
    PORT
      LAYER M4 ;
        RECT 734.208 577.392 734.400 577.416 ;
    END
  END n_pre[96]
  PIN n_pre[97]
    DIRECTION OUTPUT ;
    USE SIGNAL ;
    PORT
      LAYER M4 ;
        RECT 734.208 578.304 734.400 578.328 ;
    END
  END n_pre[97]
  PIN n_pre[98]
    DIRECTION OUTPUT ;
    USE SIGNAL ;
    PORT
      LAYER M4 ;
        RECT 734.208 579.216 734.400 579.240 ;
    END
  END n_pre[98]
  PIN n_pre[99]
    DIRECTION OUTPUT ;
    USE SIGNAL ;
    PORT
      LAYER M4 ;
        RECT 734.208 580.128 734.400 580.152 ;
    END
  END n_pre[99]
  PIN n_pre[100]
    DIRECTION OUTPUT ;
    USE SIGNAL ;
    PORT
      LAYER M4 ;
        RECT 734.208 581.040 734.400 581.064 ;
    END
  END n_pre[100]
  PIN n_pre[101]
    DIRECTION OUTPUT ;
    USE SIGNAL ;
    PORT
      LAYER M4 ;
        RECT 734.208 581.952 734.400 581.976 ;
    END
  END n_pre[101]
  PIN n_pre[102]
    DIRECTION OUTPUT ;
    USE SIGNAL ;
    PORT
      LAYER M4 ;
        RECT 734.208 582.816 734.400 582.840 ;
    END
  END n_pre[102]
  PIN n_pre[103]
    DIRECTION OUTPUT ;
    USE SIGNAL ;
    PORT
      LAYER M4 ;
        RECT 734.208 583.728 734.400 583.752 ;
    END
  END n_pre[103]
  PIN n_pre[104]
    DIRECTION OUTPUT ;
    USE SIGNAL ;
    PORT
      LAYER M4 ;
        RECT 734.208 584.640 734.400 584.664 ;
    END
  END n_pre[104]
  PIN n_pre[105]
    DIRECTION OUTPUT ;
    USE SIGNAL ;
    PORT
      LAYER M4 ;
        RECT 734.208 585.552 734.400 585.576 ;
    END
  END n_pre[105]
  PIN n_pre[106]
    DIRECTION OUTPUT ;
    USE SIGNAL ;
    PORT
      LAYER M4 ;
        RECT 734.208 586.464 734.400 586.488 ;
    END
  END n_pre[106]
  PIN n_pre[107]
    DIRECTION OUTPUT ;
    USE SIGNAL ;
    PORT
      LAYER M4 ;
        RECT 734.208 587.376 734.400 587.400 ;
    END
  END n_pre[107]
  PIN n_pre[108]
    DIRECTION OUTPUT ;
    USE SIGNAL ;
    PORT
      LAYER M4 ;
        RECT 734.208 588.240 734.400 588.264 ;
    END
  END n_pre[108]
  PIN n_pre[109]
    DIRECTION OUTPUT ;
    USE SIGNAL ;
    PORT
      LAYER M4 ;
        RECT 734.208 589.152 734.400 589.176 ;
    END
  END n_pre[109]
  PIN n_pre[110]
    DIRECTION OUTPUT ;
    USE SIGNAL ;
    PORT
      LAYER M4 ;
        RECT 734.208 590.064 734.400 590.088 ;
    END
  END n_pre[110]
  PIN n_pre[111]
    DIRECTION OUTPUT ;
    USE SIGNAL ;
    PORT
      LAYER M4 ;
        RECT 734.208 590.976 734.400 591.000 ;
    END
  END n_pre[111]
  PIN n_pre[112]
    DIRECTION OUTPUT ;
    USE SIGNAL ;
    PORT
      LAYER M4 ;
        RECT 734.208 591.888 734.400 591.912 ;
    END
  END n_pre[112]
  PIN n_pre[113]
    DIRECTION OUTPUT ;
    USE SIGNAL ;
    PORT
      LAYER M4 ;
        RECT 734.208 592.800 734.400 592.824 ;
    END
  END n_pre[113]
  PIN n_pre[114]
    DIRECTION OUTPUT ;
    USE SIGNAL ;
    PORT
      LAYER M4 ;
        RECT 734.208 593.712 734.400 593.736 ;
    END
  END n_pre[114]
  PIN n_pre[115]
    DIRECTION OUTPUT ;
    USE SIGNAL ;
    PORT
      LAYER M4 ;
        RECT 734.208 594.576 734.400 594.600 ;
    END
  END n_pre[115]
  PIN n_pre[116]
    DIRECTION OUTPUT ;
    USE SIGNAL ;
    PORT
      LAYER M4 ;
        RECT 734.208 595.488 734.400 595.512 ;
    END
  END n_pre[116]
  PIN n_pre[117]
    DIRECTION OUTPUT ;
    USE SIGNAL ;
    PORT
      LAYER M4 ;
        RECT 734.208 596.400 734.400 596.424 ;
    END
  END n_pre[117]
  PIN n_pre[118]
    DIRECTION OUTPUT ;
    USE SIGNAL ;
    PORT
      LAYER M4 ;
        RECT 734.208 597.312 734.400 597.336 ;
    END
  END n_pre[118]
  PIN n_pre[119]
    DIRECTION OUTPUT ;
    USE SIGNAL ;
    PORT
      LAYER M4 ;
        RECT 734.208 598.224 734.400 598.248 ;
    END
  END n_pre[119]
  PIN n_pre[120]
    DIRECTION OUTPUT ;
    USE SIGNAL ;
    PORT
      LAYER M4 ;
        RECT 734.208 599.136 734.400 599.160 ;
    END
  END n_pre[120]
  PIN n_pre[121]
    DIRECTION OUTPUT ;
    USE SIGNAL ;
    PORT
      LAYER M4 ;
        RECT 734.208 600.048 734.400 600.072 ;
    END
  END n_pre[121]
  PIN n_pre[122]
    DIRECTION OUTPUT ;
    USE SIGNAL ;
    PORT
      LAYER M4 ;
        RECT 734.208 600.912 734.400 600.936 ;
    END
  END n_pre[122]
  PIN n_pre[123]
    DIRECTION OUTPUT ;
    USE SIGNAL ;
    PORT
      LAYER M4 ;
        RECT 734.208 601.824 734.400 601.848 ;
    END
  END n_pre[123]
  PIN n_pre[124]
    DIRECTION OUTPUT ;
    USE SIGNAL ;
    PORT
      LAYER M4 ;
        RECT 734.208 602.736 734.400 602.760 ;
    END
  END n_pre[124]
  PIN n_pre[125]
    DIRECTION OUTPUT ;
    USE SIGNAL ;
    PORT
      LAYER M4 ;
        RECT 734.208 603.648 734.400 603.672 ;
    END
  END n_pre[125]
  PIN n_pre[126]
    DIRECTION OUTPUT ;
    USE SIGNAL ;
    PORT
      LAYER M4 ;
        RECT 734.208 604.560 734.400 604.584 ;
    END
  END n_pre[126]
  PIN n_pre[127]
    DIRECTION OUTPUT ;
    USE SIGNAL ;
    PORT
      LAYER M4 ;
        RECT 734.208 605.472 734.400 605.496 ;
    END
  END n_pre[127]
  PIN m_v
    DIRECTION OUTPUT ;
    USE SIGNAL ;
    PORT
      LAYER M4 ;
        RECT 734.208 607.200 734.400 607.224 ;
    END
  END m_v
  PIN m_q
    DIRECTION OUTPUT ;
    USE SIGNAL ;
    PORT
      LAYER M4 ;
        RECT 734.208 609.744 734.400 609.768 ;
    END
  END m_q
  PIN m_b
    DIRECTION OUTPUT ;
    USE SIGNAL ;
    PORT
      LAYER M4 ;
        RECT 734.208 612.288 734.400 612.312 ;
    END
  END m_b
  PIN m_i[0]
    DIRECTION OUTPUT ;
    USE SIGNAL ;
    PORT
      LAYER M4 ;
        RECT 734.208 614.016 734.400 614.040 ;
    END
  END m_i[0]
  PIN m_i[1]
    DIRECTION OUTPUT ;
    USE SIGNAL ;
    PORT
      LAYER M4 ;
        RECT 734.208 614.928 734.400 614.952 ;
    END
  END m_i[1]
  PIN m_i[2]
    DIRECTION OUTPUT ;
    USE SIGNAL ;
    PORT
      LAYER M4 ;
        RECT 734.208 615.792 734.400 615.816 ;
    END
  END m_i[2]
  PIN m_i[3]
    DIRECTION OUTPUT ;
    USE SIGNAL ;
    PORT
      LAYER M4 ;
        RECT 734.208 616.704 734.400 616.728 ;
    END
  END m_i[3]
  PIN m_i[4]
    DIRECTION OUTPUT ;
    USE SIGNAL ;
    PORT
      LAYER M4 ;
        RECT 734.208 617.616 734.400 617.640 ;
    END
  END m_i[4]
  PIN m_i[5]
    DIRECTION OUTPUT ;
    USE SIGNAL ;
    PORT
      LAYER M4 ;
        RECT 734.208 618.528 734.400 618.552 ;
    END
  END m_i[5]
  PIN m_i[6]
    DIRECTION OUTPUT ;
    USE SIGNAL ;
    PORT
      LAYER M4 ;
        RECT 734.208 619.440 734.400 619.464 ;
    END
  END m_i[6]
  PIN m_i[7]
    DIRECTION OUTPUT ;
    USE SIGNAL ;
    PORT
      LAYER M4 ;
        RECT 734.208 620.352 734.400 620.376 ;
    END
  END m_i[7]
  PIN wl_v
    DIRECTION OUTPUT ;
    USE SIGNAL ;
    PORT
      LAYER M4 ;
        RECT 734.208 622.080 734.400 622.104 ;
    END
  END wl_v
  PIN wl_i[0]
    DIRECTION OUTPUT ;
    USE SIGNAL ;
    PORT
      LAYER M4 ;
        RECT 734.208 623.760 734.400 623.784 ;
    END
  END wl_i[0]
  PIN wl_i[1]
    DIRECTION OUTPUT ;
    USE SIGNAL ;
    PORT
      LAYER M4 ;
        RECT 734.208 624.624 734.400 624.648 ;
    END
  END wl_i[1]
  PIN wl_i[2]
    DIRECTION OUTPUT ;
    USE SIGNAL ;
    PORT
      LAYER M4 ;
        RECT 734.208 625.440 734.400 625.464 ;
    END
  END wl_i[2]
  PIN wl_d[0]
    DIRECTION OUTPUT ;
    USE SIGNAL ;
    PORT
      LAYER M4 ;
        RECT 734.208 626.352 734.400 626.376 ;
    END
  END wl_d[0]
  PIN wl_d[1]
    DIRECTION OUTPUT ;
    USE SIGNAL ;
    PORT
      LAYER M4 ;
        RECT 734.208 627.264 734.400 627.288 ;
    END
  END wl_d[1]
  PIN wl_d[2]
    DIRECTION OUTPUT ;
    USE SIGNAL ;
    PORT
      LAYER M4 ;
        RECT 734.208 628.128 734.400 628.152 ;
    END
  END wl_d[2]
  PIN wl_d[3]
    DIRECTION OUTPUT ;
    USE SIGNAL ;
    PORT
      LAYER M4 ;
        RECT 734.208 629.040 734.400 629.064 ;
    END
  END wl_d[3]
  PIN wl_d[4]
    DIRECTION OUTPUT ;
    USE SIGNAL ;
    PORT
      LAYER M4 ;
        RECT 734.208 629.952 734.400 629.976 ;
    END
  END wl_d[4]
  PIN wl_d[5]
    DIRECTION OUTPUT ;
    USE SIGNAL ;
    PORT
      LAYER M4 ;
        RECT 734.208 630.864 734.400 630.888 ;
    END
  END wl_d[5]
  PIN wl_d[6]
    DIRECTION OUTPUT ;
    USE SIGNAL ;
    PORT
      LAYER M4 ;
        RECT 734.208 631.776 734.400 631.800 ;
    END
  END wl_d[6]
  PIN wl_d[7]
    DIRECTION OUTPUT ;
    USE SIGNAL ;
    PORT
      LAYER M4 ;
        RECT 734.208 632.688 734.400 632.712 ;
    END
  END wl_d[7]
  PIN wl_d[8]
    DIRECTION OUTPUT ;
    USE SIGNAL ;
    PORT
      LAYER M4 ;
        RECT 734.208 633.600 734.400 633.624 ;
    END
  END wl_d[8]
  PIN wl_d[9]
    DIRECTION OUTPUT ;
    USE SIGNAL ;
    PORT
      LAYER M4 ;
        RECT 734.208 634.464 734.400 634.488 ;
    END
  END wl_d[9]
  PIN wl_d[10]
    DIRECTION OUTPUT ;
    USE SIGNAL ;
    PORT
      LAYER M4 ;
        RECT 734.208 635.376 734.400 635.400 ;
    END
  END wl_d[10]
  PIN wl_d[11]
    DIRECTION OUTPUT ;
    USE SIGNAL ;
    PORT
      LAYER M4 ;
        RECT 734.208 636.288 734.400 636.312 ;
    END
  END wl_d[11]
  PIN wl_d[12]
    DIRECTION OUTPUT ;
    USE SIGNAL ;
    PORT
      LAYER M4 ;
        RECT 734.208 637.200 734.400 637.224 ;
    END
  END wl_d[12]
  PIN wl_d[13]
    DIRECTION OUTPUT ;
    USE SIGNAL ;
    PORT
      LAYER M4 ;
        RECT 734.208 638.112 734.400 638.136 ;
    END
  END wl_d[13]
  PIN wl_d[14]
    DIRECTION OUTPUT ;
    USE SIGNAL ;
    PORT
      LAYER M4 ;
        RECT 734.208 639.024 734.400 639.048 ;
    END
  END wl_d[14]
  PIN wl_d[15]
    DIRECTION OUTPUT ;
    USE SIGNAL ;
    PORT
      LAYER M4 ;
        RECT 734.208 639.888 734.400 639.912 ;
    END
  END wl_d[15]
  PIN wl_d[16]
    DIRECTION OUTPUT ;
    USE SIGNAL ;
    PORT
      LAYER M4 ;
        RECT 734.208 640.800 734.400 640.824 ;
    END
  END wl_d[16]
  PIN wl_d[17]
    DIRECTION OUTPUT ;
    USE SIGNAL ;
    PORT
      LAYER M4 ;
        RECT 734.208 641.712 734.400 641.736 ;
    END
  END wl_d[17]
  PIN wl_d[18]
    DIRECTION OUTPUT ;
    USE SIGNAL ;
    PORT
      LAYER M4 ;
        RECT 734.208 642.624 734.400 642.648 ;
    END
  END wl_d[18]
  PIN wl_d[19]
    DIRECTION OUTPUT ;
    USE SIGNAL ;
    PORT
      LAYER M4 ;
        RECT 734.208 643.536 734.400 643.560 ;
    END
  END wl_d[19]
  PIN wl_d[20]
    DIRECTION OUTPUT ;
    USE SIGNAL ;
    PORT
      LAYER M4 ;
        RECT 734.208 644.448 734.400 644.472 ;
    END
  END wl_d[20]
  PIN wl_d[21]
    DIRECTION OUTPUT ;
    USE SIGNAL ;
    PORT
      LAYER M4 ;
        RECT 734.208 645.360 734.400 645.384 ;
    END
  END wl_d[21]
  PIN wl_d[22]
    DIRECTION OUTPUT ;
    USE SIGNAL ;
    PORT
      LAYER M4 ;
        RECT 734.208 646.224 734.400 646.248 ;
    END
  END wl_d[22]
  PIN wl_d[23]
    DIRECTION OUTPUT ;
    USE SIGNAL ;
    PORT
      LAYER M4 ;
        RECT 734.208 647.136 734.400 647.160 ;
    END
  END wl_d[23]
  PIN wl_d[24]
    DIRECTION OUTPUT ;
    USE SIGNAL ;
    PORT
      LAYER M4 ;
        RECT 734.208 648.048 734.400 648.072 ;
    END
  END wl_d[24]
  PIN wl_d[25]
    DIRECTION OUTPUT ;
    USE SIGNAL ;
    PORT
      LAYER M4 ;
        RECT 734.208 648.960 734.400 648.984 ;
    END
  END wl_d[25]
  PIN wl_d[26]
    DIRECTION OUTPUT ;
    USE SIGNAL ;
    PORT
      LAYER M4 ;
        RECT 734.208 649.872 734.400 649.896 ;
    END
  END wl_d[26]
  PIN wl_d[27]
    DIRECTION OUTPUT ;
    USE SIGNAL ;
    PORT
      LAYER M4 ;
        RECT 734.208 650.784 734.400 650.808 ;
    END
  END wl_d[27]
  PIN wl_d[28]
    DIRECTION OUTPUT ;
    USE SIGNAL ;
    PORT
      LAYER M4 ;
        RECT 734.208 651.696 734.400 651.720 ;
    END
  END wl_d[28]
  PIN wl_d[29]
    DIRECTION OUTPUT ;
    USE SIGNAL ;
    PORT
      LAYER M4 ;
        RECT 734.208 652.560 734.400 652.584 ;
    END
  END wl_d[29]
  PIN wl_d[30]
    DIRECTION OUTPUT ;
    USE SIGNAL ;
    PORT
      LAYER M4 ;
        RECT 734.208 653.472 734.400 653.496 ;
    END
  END wl_d[30]
  PIN wl_d[31]
    DIRECTION OUTPUT ;
    USE SIGNAL ;
    PORT
      LAYER M4 ;
        RECT 734.208 654.384 734.400 654.408 ;
    END
  END wl_d[31]
  PIN wl_d[32]
    DIRECTION OUTPUT ;
    USE SIGNAL ;
    PORT
      LAYER M4 ;
        RECT 734.208 655.296 734.400 655.320 ;
    END
  END wl_d[32]
  PIN wl_d[33]
    DIRECTION OUTPUT ;
    USE SIGNAL ;
    PORT
      LAYER M4 ;
        RECT 734.208 656.208 734.400 656.232 ;
    END
  END wl_d[33]
  PIN wl_d[34]
    DIRECTION OUTPUT ;
    USE SIGNAL ;
    PORT
      LAYER M4 ;
        RECT 734.208 657.120 734.400 657.144 ;
    END
  END wl_d[34]
  PIN wl_d[35]
    DIRECTION OUTPUT ;
    USE SIGNAL ;
    PORT
      LAYER M4 ;
        RECT 734.208 657.984 734.400 658.008 ;
    END
  END wl_d[35]
  PIN wl_d[36]
    DIRECTION OUTPUT ;
    USE SIGNAL ;
    PORT
      LAYER M4 ;
        RECT 734.208 658.896 734.400 658.920 ;
    END
  END wl_d[36]
  PIN wl_d[37]
    DIRECTION OUTPUT ;
    USE SIGNAL ;
    PORT
      LAYER M4 ;
        RECT 734.208 659.808 734.400 659.832 ;
    END
  END wl_d[37]
  PIN wl_d[38]
    DIRECTION OUTPUT ;
    USE SIGNAL ;
    PORT
      LAYER M4 ;
        RECT 734.208 660.720 734.400 660.744 ;
    END
  END wl_d[38]
  PIN wl_d[39]
    DIRECTION OUTPUT ;
    USE SIGNAL ;
    PORT
      LAYER M4 ;
        RECT 734.208 661.632 734.400 661.656 ;
    END
  END wl_d[39]
  PIN wl_d[40]
    DIRECTION OUTPUT ;
    USE SIGNAL ;
    PORT
      LAYER M4 ;
        RECT 734.208 662.544 734.400 662.568 ;
    END
  END wl_d[40]
  PIN wl_d[41]
    DIRECTION OUTPUT ;
    USE SIGNAL ;
    PORT
      LAYER M4 ;
        RECT 734.208 663.456 734.400 663.480 ;
    END
  END wl_d[41]
  PIN wl_d[42]
    DIRECTION OUTPUT ;
    USE SIGNAL ;
    PORT
      LAYER M4 ;
        RECT 734.208 664.320 734.400 664.344 ;
    END
  END wl_d[42]
  PIN wl_d[43]
    DIRECTION OUTPUT ;
    USE SIGNAL ;
    PORT
      LAYER M4 ;
        RECT 734.208 665.232 734.400 665.256 ;
    END
  END wl_d[43]
  PIN wl_d[44]
    DIRECTION OUTPUT ;
    USE SIGNAL ;
    PORT
      LAYER M4 ;
        RECT 734.208 666.144 734.400 666.168 ;
    END
  END wl_d[44]
  PIN wl_d[45]
    DIRECTION OUTPUT ;
    USE SIGNAL ;
    PORT
      LAYER M4 ;
        RECT 734.208 667.056 734.400 667.080 ;
    END
  END wl_d[45]
  PIN wl_d[46]
    DIRECTION OUTPUT ;
    USE SIGNAL ;
    PORT
      LAYER M4 ;
        RECT 734.208 667.968 734.400 667.992 ;
    END
  END wl_d[46]
  PIN wl_d[47]
    DIRECTION OUTPUT ;
    USE SIGNAL ;
    PORT
      LAYER M4 ;
        RECT 734.208 668.880 734.400 668.904 ;
    END
  END wl_d[47]
  PIN wl_d[48]
    DIRECTION OUTPUT ;
    USE SIGNAL ;
    PORT
      LAYER M4 ;
        RECT 734.208 669.744 734.400 669.768 ;
    END
  END wl_d[48]
  PIN wl_d[49]
    DIRECTION OUTPUT ;
    USE SIGNAL ;
    PORT
      LAYER M4 ;
        RECT 734.208 670.656 734.400 670.680 ;
    END
  END wl_d[49]
  PIN wl_d[50]
    DIRECTION OUTPUT ;
    USE SIGNAL ;
    PORT
      LAYER M4 ;
        RECT 734.208 671.568 734.400 671.592 ;
    END
  END wl_d[50]
  PIN wl_d[51]
    DIRECTION OUTPUT ;
    USE SIGNAL ;
    PORT
      LAYER M4 ;
        RECT 734.208 672.480 734.400 672.504 ;
    END
  END wl_d[51]
  PIN wl_d[52]
    DIRECTION OUTPUT ;
    USE SIGNAL ;
    PORT
      LAYER M4 ;
        RECT 734.208 673.392 734.400 673.416 ;
    END
  END wl_d[52]
  PIN wl_d[53]
    DIRECTION OUTPUT ;
    USE SIGNAL ;
    PORT
      LAYER M4 ;
        RECT 734.208 674.304 734.400 674.328 ;
    END
  END wl_d[53]
  PIN wl_d[54]
    DIRECTION OUTPUT ;
    USE SIGNAL ;
    PORT
      LAYER M4 ;
        RECT 734.208 675.216 734.400 675.240 ;
    END
  END wl_d[54]
  PIN wl_d[55]
    DIRECTION OUTPUT ;
    USE SIGNAL ;
    PORT
      LAYER M4 ;
        RECT 734.208 676.080 734.400 676.104 ;
    END
  END wl_d[55]
  PIN wl_d[56]
    DIRECTION OUTPUT ;
    USE SIGNAL ;
    PORT
      LAYER M4 ;
        RECT 734.208 676.992 734.400 677.016 ;
    END
  END wl_d[56]
  PIN wl_d[57]
    DIRECTION OUTPUT ;
    USE SIGNAL ;
    PORT
      LAYER M4 ;
        RECT 734.208 677.904 734.400 677.928 ;
    END
  END wl_d[57]
  PIN wl_d[58]
    DIRECTION OUTPUT ;
    USE SIGNAL ;
    PORT
      LAYER M4 ;
        RECT 734.208 678.816 734.400 678.840 ;
    END
  END wl_d[58]
  PIN wl_d[59]
    DIRECTION OUTPUT ;
    USE SIGNAL ;
    PORT
      LAYER M4 ;
        RECT 734.208 679.728 734.400 679.752 ;
    END
  END wl_d[59]
  PIN wl_d[60]
    DIRECTION OUTPUT ;
    USE SIGNAL ;
    PORT
      LAYER M4 ;
        RECT 734.208 680.640 734.400 680.664 ;
    END
  END wl_d[60]
  PIN wl_d[61]
    DIRECTION OUTPUT ;
    USE SIGNAL ;
    PORT
      LAYER M4 ;
        RECT 734.208 681.552 734.400 681.576 ;
    END
  END wl_d[61]
  PIN wl_d[62]
    DIRECTION OUTPUT ;
    USE SIGNAL ;
    PORT
      LAYER M4 ;
        RECT 734.208 682.416 734.400 682.440 ;
    END
  END wl_d[62]
  PIN wl_d[63]
    DIRECTION OUTPUT ;
    USE SIGNAL ;
    PORT
      LAYER M4 ;
        RECT 734.208 683.328 734.400 683.352 ;
    END
  END wl_d[63]
  PIN wl_d[64]
    DIRECTION OUTPUT ;
    USE SIGNAL ;
    PORT
      LAYER M4 ;
        RECT 734.208 684.240 734.400 684.264 ;
    END
  END wl_d[64]
  PIN wl_d[65]
    DIRECTION OUTPUT ;
    USE SIGNAL ;
    PORT
      LAYER M4 ;
        RECT 734.208 685.152 734.400 685.176 ;
    END
  END wl_d[65]
  PIN wl_d[66]
    DIRECTION OUTPUT ;
    USE SIGNAL ;
    PORT
      LAYER M4 ;
        RECT 734.208 686.064 734.400 686.088 ;
    END
  END wl_d[66]
  PIN wl_d[67]
    DIRECTION OUTPUT ;
    USE SIGNAL ;
    PORT
      LAYER M4 ;
        RECT 734.208 686.976 734.400 687.000 ;
    END
  END wl_d[67]
  PIN wl_d[68]
    DIRECTION OUTPUT ;
    USE SIGNAL ;
    PORT
      LAYER M4 ;
        RECT 734.208 687.840 734.400 687.864 ;
    END
  END wl_d[68]
  PIN wl_d[69]
    DIRECTION OUTPUT ;
    USE SIGNAL ;
    PORT
      LAYER M4 ;
        RECT 734.208 688.752 734.400 688.776 ;
    END
  END wl_d[69]
  PIN wl_d[70]
    DIRECTION OUTPUT ;
    USE SIGNAL ;
    PORT
      LAYER M4 ;
        RECT 734.208 689.664 734.400 689.688 ;
    END
  END wl_d[70]
  PIN wl_d[71]
    DIRECTION OUTPUT ;
    USE SIGNAL ;
    PORT
      LAYER M4 ;
        RECT 734.208 690.576 734.400 690.600 ;
    END
  END wl_d[71]
  PIN wl_d[72]
    DIRECTION OUTPUT ;
    USE SIGNAL ;
    PORT
      LAYER M4 ;
        RECT 734.208 691.488 734.400 691.512 ;
    END
  END wl_d[72]
  PIN wl_d[73]
    DIRECTION OUTPUT ;
    USE SIGNAL ;
    PORT
      LAYER M4 ;
        RECT 734.208 692.400 734.400 692.424 ;
    END
  END wl_d[73]
  PIN wl_d[74]
    DIRECTION OUTPUT ;
    USE SIGNAL ;
    PORT
      LAYER M4 ;
        RECT 734.208 693.312 734.400 693.336 ;
    END
  END wl_d[74]
  PIN wl_d[75]
    DIRECTION OUTPUT ;
    USE SIGNAL ;
    PORT
      LAYER M4 ;
        RECT 734.208 694.176 734.400 694.200 ;
    END
  END wl_d[75]
  PIN wl_d[76]
    DIRECTION OUTPUT ;
    USE SIGNAL ;
    PORT
      LAYER M4 ;
        RECT 734.208 695.088 734.400 695.112 ;
    END
  END wl_d[76]
  PIN wl_d[77]
    DIRECTION OUTPUT ;
    USE SIGNAL ;
    PORT
      LAYER M4 ;
        RECT 734.208 696.000 734.400 696.024 ;
    END
  END wl_d[77]
  PIN wl_d[78]
    DIRECTION OUTPUT ;
    USE SIGNAL ;
    PORT
      LAYER M4 ;
        RECT 734.208 696.912 734.400 696.936 ;
    END
  END wl_d[78]
  PIN wl_d[79]
    DIRECTION OUTPUT ;
    USE SIGNAL ;
    PORT
      LAYER M4 ;
        RECT 734.208 697.824 734.400 697.848 ;
    END
  END wl_d[79]
  PIN wl_d[80]
    DIRECTION OUTPUT ;
    USE SIGNAL ;
    PORT
      LAYER M4 ;
        RECT 734.208 698.736 734.400 698.760 ;
    END
  END wl_d[80]
  PIN wl_d[81]
    DIRECTION OUTPUT ;
    USE SIGNAL ;
    PORT
      LAYER M4 ;
        RECT 734.208 699.648 734.400 699.672 ;
    END
  END wl_d[81]
  PIN wl_d[82]
    DIRECTION OUTPUT ;
    USE SIGNAL ;
    PORT
      LAYER M4 ;
        RECT 734.208 700.512 734.400 700.536 ;
    END
  END wl_d[82]
  PIN wl_d[83]
    DIRECTION OUTPUT ;
    USE SIGNAL ;
    PORT
      LAYER M4 ;
        RECT 734.208 701.424 734.400 701.448 ;
    END
  END wl_d[83]
  PIN wl_d[84]
    DIRECTION OUTPUT ;
    USE SIGNAL ;
    PORT
      LAYER M4 ;
        RECT 734.208 702.336 734.400 702.360 ;
    END
  END wl_d[84]
  PIN wl_d[85]
    DIRECTION OUTPUT ;
    USE SIGNAL ;
    PORT
      LAYER M4 ;
        RECT 734.208 703.248 734.400 703.272 ;
    END
  END wl_d[85]
  PIN wl_d[86]
    DIRECTION OUTPUT ;
    USE SIGNAL ;
    PORT
      LAYER M4 ;
        RECT 734.208 704.160 734.400 704.184 ;
    END
  END wl_d[86]
  PIN wl_d[87]
    DIRECTION OUTPUT ;
    USE SIGNAL ;
    PORT
      LAYER M4 ;
        RECT 734.208 705.072 734.400 705.096 ;
    END
  END wl_d[87]
  PIN wl_d[88]
    DIRECTION OUTPUT ;
    USE SIGNAL ;
    PORT
      LAYER M4 ;
        RECT 734.208 705.936 734.400 705.960 ;
    END
  END wl_d[88]
  PIN wl_d[89]
    DIRECTION OUTPUT ;
    USE SIGNAL ;
    PORT
      LAYER M4 ;
        RECT 734.208 706.848 734.400 706.872 ;
    END
  END wl_d[89]
  PIN wl_d[90]
    DIRECTION OUTPUT ;
    USE SIGNAL ;
    PORT
      LAYER M4 ;
        RECT 734.208 707.760 734.400 707.784 ;
    END
  END wl_d[90]
  PIN wl_d[91]
    DIRECTION OUTPUT ;
    USE SIGNAL ;
    PORT
      LAYER M4 ;
        RECT 734.208 708.672 734.400 708.696 ;
    END
  END wl_d[91]
  PIN wl_d[92]
    DIRECTION OUTPUT ;
    USE SIGNAL ;
    PORT
      LAYER M4 ;
        RECT 734.208 709.584 734.400 709.608 ;
    END
  END wl_d[92]
  PIN wl_d[93]
    DIRECTION OUTPUT ;
    USE SIGNAL ;
    PORT
      LAYER M4 ;
        RECT 734.208 710.496 734.400 710.520 ;
    END
  END wl_d[93]
  PIN wl_d[94]
    DIRECTION OUTPUT ;
    USE SIGNAL ;
    PORT
      LAYER M4 ;
        RECT 734.208 711.408 734.400 711.432 ;
    END
  END wl_d[94]
  PIN wl_d[95]
    DIRECTION OUTPUT ;
    USE SIGNAL ;
    PORT
      LAYER M4 ;
        RECT 734.208 712.272 734.400 712.296 ;
    END
  END wl_d[95]
  PIN wl_d[96]
    DIRECTION OUTPUT ;
    USE SIGNAL ;
    PORT
      LAYER M4 ;
        RECT 734.208 713.184 734.400 713.208 ;
    END
  END wl_d[96]
  PIN wl_d[97]
    DIRECTION OUTPUT ;
    USE SIGNAL ;
    PORT
      LAYER M4 ;
        RECT 734.208 714.096 734.400 714.120 ;
    END
  END wl_d[97]
  PIN wl_d[98]
    DIRECTION OUTPUT ;
    USE SIGNAL ;
    PORT
      LAYER M4 ;
        RECT 734.208 715.008 734.400 715.032 ;
    END
  END wl_d[98]
  PIN wl_d[99]
    DIRECTION OUTPUT ;
    USE SIGNAL ;
    PORT
      LAYER M4 ;
        RECT 734.208 715.920 734.400 715.944 ;
    END
  END wl_d[99]
  PIN wl_d[100]
    DIRECTION OUTPUT ;
    USE SIGNAL ;
    PORT
      LAYER M4 ;
        RECT 734.208 716.832 734.400 716.856 ;
    END
  END wl_d[100]
  PIN wl_d[101]
    DIRECTION OUTPUT ;
    USE SIGNAL ;
    PORT
      LAYER M4 ;
        RECT 734.208 717.744 734.400 717.768 ;
    END
  END wl_d[101]
  PIN wl_d[102]
    DIRECTION OUTPUT ;
    USE SIGNAL ;
    PORT
      LAYER M4 ;
        RECT 734.208 718.608 734.400 718.632 ;
    END
  END wl_d[102]
  PIN wl_d[103]
    DIRECTION OUTPUT ;
    USE SIGNAL ;
    PORT
      LAYER M4 ;
        RECT 734.208 719.520 734.400 719.544 ;
    END
  END wl_d[103]
  PIN wl_d[104]
    DIRECTION OUTPUT ;
    USE SIGNAL ;
    PORT
      LAYER M4 ;
        RECT 734.208 720.432 734.400 720.456 ;
    END
  END wl_d[104]
  PIN wl_d[105]
    DIRECTION OUTPUT ;
    USE SIGNAL ;
    PORT
      LAYER M4 ;
        RECT 734.208 721.344 734.400 721.368 ;
    END
  END wl_d[105]
  PIN wl_d[106]
    DIRECTION OUTPUT ;
    USE SIGNAL ;
    PORT
      LAYER M4 ;
        RECT 734.208 722.256 734.400 722.280 ;
    END
  END wl_d[106]
  PIN wl_d[107]
    DIRECTION OUTPUT ;
    USE SIGNAL ;
    PORT
      LAYER M4 ;
        RECT 734.208 723.168 734.400 723.192 ;
    END
  END wl_d[107]
  PIN wl_d[108]
    DIRECTION OUTPUT ;
    USE SIGNAL ;
    PORT
      LAYER M4 ;
        RECT 734.208 724.032 734.400 724.056 ;
    END
  END wl_d[108]
  PIN wl_d[109]
    DIRECTION OUTPUT ;
    USE SIGNAL ;
    PORT
      LAYER M4 ;
        RECT 734.208 724.944 734.400 724.968 ;
    END
  END wl_d[109]
  PIN wl_d[110]
    DIRECTION OUTPUT ;
    USE SIGNAL ;
    PORT
      LAYER M4 ;
        RECT 734.208 725.856 734.400 725.880 ;
    END
  END wl_d[110]
  PIN wl_d[111]
    DIRECTION OUTPUT ;
    USE SIGNAL ;
    PORT
      LAYER M4 ;
        RECT 734.208 726.768 734.400 726.792 ;
    END
  END wl_d[111]
  PIN wl_d[112]
    DIRECTION OUTPUT ;
    USE SIGNAL ;
    PORT
      LAYER M4 ;
        RECT 734.208 727.680 734.400 727.704 ;
    END
  END wl_d[112]
  PIN wl_d[113]
    DIRECTION OUTPUT ;
    USE SIGNAL ;
    PORT
      LAYER M4 ;
        RECT 734.208 728.592 734.400 728.616 ;
    END
  END wl_d[113]
  PIN wl_d[114]
    DIRECTION OUTPUT ;
    USE SIGNAL ;
    PORT
      LAYER M4 ;
        RECT 734.208 729.504 734.400 729.528 ;
    END
  END wl_d[114]
  PIN wl_d[115]
    DIRECTION OUTPUT ;
    USE SIGNAL ;
    PORT
      LAYER M4 ;
        RECT 734.208 730.368 734.400 730.392 ;
    END
  END wl_d[115]
  PIN wl_d[116]
    DIRECTION OUTPUT ;
    USE SIGNAL ;
    PORT
      LAYER M4 ;
        RECT 734.208 731.280 734.400 731.304 ;
    END
  END wl_d[116]
  PIN wl_d[117]
    DIRECTION OUTPUT ;
    USE SIGNAL ;
    PORT
      LAYER M4 ;
        RECT 734.208 732.192 734.400 732.216 ;
    END
  END wl_d[117]
  PIN wl_d[118]
    DIRECTION OUTPUT ;
    USE SIGNAL ;
    PORT
      LAYER M4 ;
        RECT 734.208 733.104 734.400 733.128 ;
    END
  END wl_d[118]
  PIN wl_d[119]
    DIRECTION OUTPUT ;
    USE SIGNAL ;
    PORT
      LAYER M4 ;
        RECT 734.208 734.016 734.400 734.040 ;
    END
  END wl_d[119]
  PIN wl_d[120]
    DIRECTION OUTPUT ;
    USE SIGNAL ;
    PORT
      LAYER M4 ;
        RECT 734.208 734.928 734.400 734.952 ;
    END
  END wl_d[120]
  PIN wl_d[121]
    DIRECTION OUTPUT ;
    USE SIGNAL ;
    PORT
      LAYER M4 ;
        RECT 734.208 735.792 734.400 735.816 ;
    END
  END wl_d[121]
  PIN wl_d[122]
    DIRECTION OUTPUT ;
    USE SIGNAL ;
    PORT
      LAYER M4 ;
        RECT 734.208 736.704 734.400 736.728 ;
    END
  END wl_d[122]
  PIN wl_d[123]
    DIRECTION OUTPUT ;
    USE SIGNAL ;
    PORT
      LAYER M4 ;
        RECT 734.208 737.616 734.400 737.640 ;
    END
  END wl_d[123]
  PIN wl_d[124]
    DIRECTION OUTPUT ;
    USE SIGNAL ;
    PORT
      LAYER M4 ;
        RECT 734.208 738.528 734.400 738.552 ;
    END
  END wl_d[124]
  PIN wl_d[125]
    DIRECTION OUTPUT ;
    USE SIGNAL ;
    PORT
      LAYER M4 ;
        RECT 734.208 739.440 734.400 739.464 ;
    END
  END wl_d[125]
  PIN wl_d[126]
    DIRECTION OUTPUT ;
    USE SIGNAL ;
    PORT
      LAYER M4 ;
        RECT 734.208 740.352 734.400 740.376 ;
    END
  END wl_d[126]
  PIN wl_d[127]
    DIRECTION OUTPUT ;
    USE SIGNAL ;
    PORT
      LAYER M4 ;
        RECT 734.208 741.264 734.400 741.288 ;
    END
  END wl_d[127]
  PIN wl_d[128]
    DIRECTION OUTPUT ;
    USE SIGNAL ;
    PORT
      LAYER M4 ;
        RECT 734.208 742.128 734.400 742.152 ;
    END
  END wl_d[128]
  PIN wl_d[129]
    DIRECTION OUTPUT ;
    USE SIGNAL ;
    PORT
      LAYER M4 ;
        RECT 734.208 743.040 734.400 743.064 ;
    END
  END wl_d[129]
  PIN wl_d[130]
    DIRECTION OUTPUT ;
    USE SIGNAL ;
    PORT
      LAYER M4 ;
        RECT 734.208 743.952 734.400 743.976 ;
    END
  END wl_d[130]
  PIN wl_d[131]
    DIRECTION OUTPUT ;
    USE SIGNAL ;
    PORT
      LAYER M4 ;
        RECT 734.208 744.864 734.400 744.888 ;
    END
  END wl_d[131]
  PIN wl_d[132]
    DIRECTION OUTPUT ;
    USE SIGNAL ;
    PORT
      LAYER M4 ;
        RECT 734.208 745.776 734.400 745.800 ;
    END
  END wl_d[132]
  PIN wl_d[133]
    DIRECTION OUTPUT ;
    USE SIGNAL ;
    PORT
      LAYER M4 ;
        RECT 734.208 746.688 734.400 746.712 ;
    END
  END wl_d[133]
  PIN wl_d[134]
    DIRECTION OUTPUT ;
    USE SIGNAL ;
    PORT
      LAYER M4 ;
        RECT 734.208 747.600 734.400 747.624 ;
    END
  END wl_d[134]
  PIN wl_d[135]
    DIRECTION OUTPUT ;
    USE SIGNAL ;
    PORT
      LAYER M4 ;
        RECT 734.208 748.464 734.400 748.488 ;
    END
  END wl_d[135]
  PIN wl_d[136]
    DIRECTION OUTPUT ;
    USE SIGNAL ;
    PORT
      LAYER M4 ;
        RECT 734.208 749.376 734.400 749.400 ;
    END
  END wl_d[136]
  PIN wl_d[137]
    DIRECTION OUTPUT ;
    USE SIGNAL ;
    PORT
      LAYER M4 ;
        RECT 734.208 750.288 734.400 750.312 ;
    END
  END wl_d[137]
  PIN wl_d[138]
    DIRECTION OUTPUT ;
    USE SIGNAL ;
    PORT
      LAYER M4 ;
        RECT 734.208 751.200 734.400 751.224 ;
    END
  END wl_d[138]
  PIN wl_d[139]
    DIRECTION OUTPUT ;
    USE SIGNAL ;
    PORT
      LAYER M4 ;
        RECT 734.208 752.112 734.400 752.136 ;
    END
  END wl_d[139]
  PIN wl_d[140]
    DIRECTION OUTPUT ;
    USE SIGNAL ;
    PORT
      LAYER M4 ;
        RECT 734.208 753.024 734.400 753.048 ;
    END
  END wl_d[140]
  PIN wl_d[141]
    DIRECTION OUTPUT ;
    USE SIGNAL ;
    PORT
      LAYER M4 ;
        RECT 734.208 753.888 734.400 753.912 ;
    END
  END wl_d[141]
  PIN wl_d[142]
    DIRECTION OUTPUT ;
    USE SIGNAL ;
    PORT
      LAYER M4 ;
        RECT 734.208 754.800 734.400 754.824 ;
    END
  END wl_d[142]
  PIN wl_d[143]
    DIRECTION OUTPUT ;
    USE SIGNAL ;
    PORT
      LAYER M4 ;
        RECT 734.208 755.712 734.400 755.736 ;
    END
  END wl_d[143]
  PIN wl_d[144]
    DIRECTION OUTPUT ;
    USE SIGNAL ;
    PORT
      LAYER M4 ;
        RECT 734.208 756.624 734.400 756.648 ;
    END
  END wl_d[144]
  PIN wl_d[145]
    DIRECTION OUTPUT ;
    USE SIGNAL ;
    PORT
      LAYER M4 ;
        RECT 734.208 757.536 734.400 757.560 ;
    END
  END wl_d[145]
  PIN wl_d[146]
    DIRECTION OUTPUT ;
    USE SIGNAL ;
    PORT
      LAYER M4 ;
        RECT 734.208 758.448 734.400 758.472 ;
    END
  END wl_d[146]
  PIN wl_d[147]
    DIRECTION OUTPUT ;
    USE SIGNAL ;
    PORT
      LAYER M4 ;
        RECT 734.208 759.360 734.400 759.384 ;
    END
  END wl_d[147]
  PIN wl_d[148]
    DIRECTION OUTPUT ;
    USE SIGNAL ;
    PORT
      LAYER M4 ;
        RECT 734.208 760.224 734.400 760.248 ;
    END
  END wl_d[148]
  PIN wl_d[149]
    DIRECTION OUTPUT ;
    USE SIGNAL ;
    PORT
      LAYER M4 ;
        RECT 734.208 761.136 734.400 761.160 ;
    END
  END wl_d[149]
  PIN wl_d[150]
    DIRECTION OUTPUT ;
    USE SIGNAL ;
    PORT
      LAYER M4 ;
        RECT 734.208 762.048 734.400 762.072 ;
    END
  END wl_d[150]
  PIN wl_d[151]
    DIRECTION OUTPUT ;
    USE SIGNAL ;
    PORT
      LAYER M4 ;
        RECT 734.208 762.960 734.400 762.984 ;
    END
  END wl_d[151]
  PIN wl_d[152]
    DIRECTION OUTPUT ;
    USE SIGNAL ;
    PORT
      LAYER M4 ;
        RECT 734.208 763.872 734.400 763.896 ;
    END
  END wl_d[152]
  PIN wl_d[153]
    DIRECTION OUTPUT ;
    USE SIGNAL ;
    PORT
      LAYER M4 ;
        RECT 734.208 764.784 734.400 764.808 ;
    END
  END wl_d[153]
  PIN wl_d[154]
    DIRECTION OUTPUT ;
    USE SIGNAL ;
    PORT
      LAYER M4 ;
        RECT 734.208 765.696 734.400 765.720 ;
    END
  END wl_d[154]
  PIN wl_d[155]
    DIRECTION OUTPUT ;
    USE SIGNAL ;
    PORT
      LAYER M4 ;
        RECT 734.208 766.560 734.400 766.584 ;
    END
  END wl_d[155]
  PIN wl_d[156]
    DIRECTION OUTPUT ;
    USE SIGNAL ;
    PORT
      LAYER M4 ;
        RECT 734.208 767.472 734.400 767.496 ;
    END
  END wl_d[156]
  PIN wl_d[157]
    DIRECTION OUTPUT ;
    USE SIGNAL ;
    PORT
      LAYER M4 ;
        RECT 734.208 768.384 734.400 768.408 ;
    END
  END wl_d[157]
  PIN wl_d[158]
    DIRECTION OUTPUT ;
    USE SIGNAL ;
    PORT
      LAYER M4 ;
        RECT 734.208 769.296 734.400 769.320 ;
    END
  END wl_d[158]
  PIN wl_d[159]
    DIRECTION OUTPUT ;
    USE SIGNAL ;
    PORT
      LAYER M4 ;
        RECT 734.208 770.208 734.400 770.232 ;
    END
  END wl_d[159]
  PIN wl_d[160]
    DIRECTION OUTPUT ;
    USE SIGNAL ;
    PORT
      LAYER M4 ;
        RECT 734.208 771.120 734.400 771.144 ;
    END
  END wl_d[160]
  PIN wl_d[161]
    DIRECTION OUTPUT ;
    USE SIGNAL ;
    PORT
      LAYER M4 ;
        RECT 734.208 771.984 734.400 772.008 ;
    END
  END wl_d[161]
  PIN wl_d[162]
    DIRECTION OUTPUT ;
    USE SIGNAL ;
    PORT
      LAYER M4 ;
        RECT 734.208 772.896 734.400 772.920 ;
    END
  END wl_d[162]
  PIN wl_d[163]
    DIRECTION OUTPUT ;
    USE SIGNAL ;
    PORT
      LAYER M4 ;
        RECT 734.208 773.808 734.400 773.832 ;
    END
  END wl_d[163]
  PIN wl_d[164]
    DIRECTION OUTPUT ;
    USE SIGNAL ;
    PORT
      LAYER M4 ;
        RECT 734.208 774.720 734.400 774.744 ;
    END
  END wl_d[164]
  PIN wl_d[165]
    DIRECTION OUTPUT ;
    USE SIGNAL ;
    PORT
      LAYER M4 ;
        RECT 734.208 775.632 734.400 775.656 ;
    END
  END wl_d[165]
  PIN wl_d[166]
    DIRECTION OUTPUT ;
    USE SIGNAL ;
    PORT
      LAYER M4 ;
        RECT 734.208 776.544 734.400 776.568 ;
    END
  END wl_d[166]
  PIN wl_d[167]
    DIRECTION OUTPUT ;
    USE SIGNAL ;
    PORT
      LAYER M4 ;
        RECT 734.208 777.456 734.400 777.480 ;
    END
  END wl_d[167]
  PIN wl_d[168]
    DIRECTION OUTPUT ;
    USE SIGNAL ;
    PORT
      LAYER M4 ;
        RECT 734.208 778.320 734.400 778.344 ;
    END
  END wl_d[168]
  PIN wl_d[169]
    DIRECTION OUTPUT ;
    USE SIGNAL ;
    PORT
      LAYER M4 ;
        RECT 734.208 779.232 734.400 779.256 ;
    END
  END wl_d[169]
  PIN wl_d[170]
    DIRECTION OUTPUT ;
    USE SIGNAL ;
    PORT
      LAYER M4 ;
        RECT 734.208 780.144 734.400 780.168 ;
    END
  END wl_d[170]
  PIN wl_d[171]
    DIRECTION OUTPUT ;
    USE SIGNAL ;
    PORT
      LAYER M4 ;
        RECT 734.208 781.056 734.400 781.080 ;
    END
  END wl_d[171]
  PIN wl_d[172]
    DIRECTION OUTPUT ;
    USE SIGNAL ;
    PORT
      LAYER M4 ;
        RECT 734.208 781.968 734.400 781.992 ;
    END
  END wl_d[172]
  PIN wl_d[173]
    DIRECTION OUTPUT ;
    USE SIGNAL ;
    PORT
      LAYER M4 ;
        RECT 734.208 782.880 734.400 782.904 ;
    END
  END wl_d[173]
  PIN wl_d[174]
    DIRECTION OUTPUT ;
    USE SIGNAL ;
    PORT
      LAYER M4 ;
        RECT 734.208 783.792 734.400 783.816 ;
    END
  END wl_d[174]
  PIN wl_d[175]
    DIRECTION OUTPUT ;
    USE SIGNAL ;
    PORT
      LAYER M4 ;
        RECT 734.208 784.656 734.400 784.680 ;
    END
  END wl_d[175]
  PIN wl_d[176]
    DIRECTION OUTPUT ;
    USE SIGNAL ;
    PORT
      LAYER M4 ;
        RECT 734.208 785.568 734.400 785.592 ;
    END
  END wl_d[176]
  PIN wl_d[177]
    DIRECTION OUTPUT ;
    USE SIGNAL ;
    PORT
      LAYER M4 ;
        RECT 734.208 786.480 734.400 786.504 ;
    END
  END wl_d[177]
  PIN wl_d[178]
    DIRECTION OUTPUT ;
    USE SIGNAL ;
    PORT
      LAYER M4 ;
        RECT 734.208 787.392 734.400 787.416 ;
    END
  END wl_d[178]
  PIN wl_d[179]
    DIRECTION OUTPUT ;
    USE SIGNAL ;
    PORT
      LAYER M4 ;
        RECT 734.208 788.304 734.400 788.328 ;
    END
  END wl_d[179]
  PIN wl_d[180]
    DIRECTION OUTPUT ;
    USE SIGNAL ;
    PORT
      LAYER M4 ;
        RECT 734.208 789.216 734.400 789.240 ;
    END
  END wl_d[180]
  PIN wl_d[181]
    DIRECTION OUTPUT ;
    USE SIGNAL ;
    PORT
      LAYER M4 ;
        RECT 734.208 790.080 734.400 790.104 ;
    END
  END wl_d[181]
  PIN wl_d[182]
    DIRECTION OUTPUT ;
    USE SIGNAL ;
    PORT
      LAYER M4 ;
        RECT 734.208 790.992 734.400 791.016 ;
    END
  END wl_d[182]
  PIN wl_d[183]
    DIRECTION OUTPUT ;
    USE SIGNAL ;
    PORT
      LAYER M4 ;
        RECT 734.208 791.904 734.400 791.928 ;
    END
  END wl_d[183]
  PIN wl_d[184]
    DIRECTION OUTPUT ;
    USE SIGNAL ;
    PORT
      LAYER M4 ;
        RECT 734.208 792.816 734.400 792.840 ;
    END
  END wl_d[184]
  PIN wl_d[185]
    DIRECTION OUTPUT ;
    USE SIGNAL ;
    PORT
      LAYER M4 ;
        RECT 734.208 793.728 734.400 793.752 ;
    END
  END wl_d[185]
  PIN wl_d[186]
    DIRECTION OUTPUT ;
    USE SIGNAL ;
    PORT
      LAYER M4 ;
        RECT 734.208 794.640 734.400 794.664 ;
    END
  END wl_d[186]
  PIN wl_d[187]
    DIRECTION OUTPUT ;
    USE SIGNAL ;
    PORT
      LAYER M4 ;
        RECT 734.208 795.552 734.400 795.576 ;
    END
  END wl_d[187]
  PIN wl_d[188]
    DIRECTION OUTPUT ;
    USE SIGNAL ;
    PORT
      LAYER M4 ;
        RECT 734.208 796.416 734.400 796.440 ;
    END
  END wl_d[188]
  PIN wl_d[189]
    DIRECTION OUTPUT ;
    USE SIGNAL ;
    PORT
      LAYER M4 ;
        RECT 734.208 797.328 734.400 797.352 ;
    END
  END wl_d[189]
  PIN wl_d[190]
    DIRECTION OUTPUT ;
    USE SIGNAL ;
    PORT
      LAYER M4 ;
        RECT 734.208 798.240 734.400 798.264 ;
    END
  END wl_d[190]
  PIN wl_d[191]
    DIRECTION OUTPUT ;
    USE SIGNAL ;
    PORT
      LAYER M4 ;
        RECT 734.208 799.152 734.400 799.176 ;
    END
  END wl_d[191]
  PIN wl_d[192]
    DIRECTION OUTPUT ;
    USE SIGNAL ;
    PORT
      LAYER M4 ;
        RECT 734.208 800.064 734.400 800.088 ;
    END
  END wl_d[192]
  PIN wl_d[193]
    DIRECTION OUTPUT ;
    USE SIGNAL ;
    PORT
      LAYER M4 ;
        RECT 734.208 800.976 734.400 801.000 ;
    END
  END wl_d[193]
  PIN wl_d[194]
    DIRECTION OUTPUT ;
    USE SIGNAL ;
    PORT
      LAYER M4 ;
        RECT 734.208 801.888 734.400 801.912 ;
    END
  END wl_d[194]
  PIN wl_d[195]
    DIRECTION OUTPUT ;
    USE SIGNAL ;
    PORT
      LAYER M4 ;
        RECT 734.208 802.752 734.400 802.776 ;
    END
  END wl_d[195]
  PIN wl_d[196]
    DIRECTION OUTPUT ;
    USE SIGNAL ;
    PORT
      LAYER M4 ;
        RECT 734.208 803.664 734.400 803.688 ;
    END
  END wl_d[196]
  PIN wl_d[197]
    DIRECTION OUTPUT ;
    USE SIGNAL ;
    PORT
      LAYER M4 ;
        RECT 734.208 804.576 734.400 804.600 ;
    END
  END wl_d[197]
  PIN wl_d[198]
    DIRECTION OUTPUT ;
    USE SIGNAL ;
    PORT
      LAYER M4 ;
        RECT 734.208 805.488 734.400 805.512 ;
    END
  END wl_d[198]
  PIN wl_d[199]
    DIRECTION OUTPUT ;
    USE SIGNAL ;
    PORT
      LAYER M4 ;
        RECT 734.208 806.400 734.400 806.424 ;
    END
  END wl_d[199]
  PIN wl_d[200]
    DIRECTION OUTPUT ;
    USE SIGNAL ;
    PORT
      LAYER M4 ;
        RECT 734.208 807.312 734.400 807.336 ;
    END
  END wl_d[200]
  PIN wl_d[201]
    DIRECTION OUTPUT ;
    USE SIGNAL ;
    PORT
      LAYER M4 ;
        RECT 734.208 808.176 734.400 808.200 ;
    END
  END wl_d[201]
  PIN wl_d[202]
    DIRECTION OUTPUT ;
    USE SIGNAL ;
    PORT
      LAYER M4 ;
        RECT 734.208 809.088 734.400 809.112 ;
    END
  END wl_d[202]
  PIN wl_d[203]
    DIRECTION OUTPUT ;
    USE SIGNAL ;
    PORT
      LAYER M4 ;
        RECT 734.208 810.000 734.400 810.024 ;
    END
  END wl_d[203]
  PIN wl_d[204]
    DIRECTION OUTPUT ;
    USE SIGNAL ;
    PORT
      LAYER M4 ;
        RECT 734.208 810.912 734.400 810.936 ;
    END
  END wl_d[204]
  PIN wl_d[205]
    DIRECTION OUTPUT ;
    USE SIGNAL ;
    PORT
      LAYER M4 ;
        RECT 734.208 811.824 734.400 811.848 ;
    END
  END wl_d[205]
  PIN wl_d[206]
    DIRECTION OUTPUT ;
    USE SIGNAL ;
    PORT
      LAYER M4 ;
        RECT 734.208 812.736 734.400 812.760 ;
    END
  END wl_d[206]
  PIN wl_d[207]
    DIRECTION OUTPUT ;
    USE SIGNAL ;
    PORT
      LAYER M4 ;
        RECT 734.208 813.648 734.400 813.672 ;
    END
  END wl_d[207]
  PIN wl_d[208]
    DIRECTION OUTPUT ;
    USE SIGNAL ;
    PORT
      LAYER M4 ;
        RECT 734.208 814.512 734.400 814.536 ;
    END
  END wl_d[208]
  PIN wl_d[209]
    DIRECTION OUTPUT ;
    USE SIGNAL ;
    PORT
      LAYER M4 ;
        RECT 734.208 815.424 734.400 815.448 ;
    END
  END wl_d[209]
  PIN wl_d[210]
    DIRECTION OUTPUT ;
    USE SIGNAL ;
    PORT
      LAYER M4 ;
        RECT 734.208 816.336 734.400 816.360 ;
    END
  END wl_d[210]
  PIN wl_d[211]
    DIRECTION OUTPUT ;
    USE SIGNAL ;
    PORT
      LAYER M4 ;
        RECT 734.208 817.248 734.400 817.272 ;
    END
  END wl_d[211]
  PIN wl_d[212]
    DIRECTION OUTPUT ;
    USE SIGNAL ;
    PORT
      LAYER M4 ;
        RECT 734.208 818.160 734.400 818.184 ;
    END
  END wl_d[212]
  PIN wl_d[213]
    DIRECTION OUTPUT ;
    USE SIGNAL ;
    PORT
      LAYER M4 ;
        RECT 734.208 819.072 734.400 819.096 ;
    END
  END wl_d[213]
  PIN wl_d[214]
    DIRECTION OUTPUT ;
    USE SIGNAL ;
    PORT
      LAYER M4 ;
        RECT 734.208 819.936 734.400 819.960 ;
    END
  END wl_d[214]
  PIN wl_d[215]
    DIRECTION OUTPUT ;
    USE SIGNAL ;
    PORT
      LAYER M4 ;
        RECT 734.208 820.848 734.400 820.872 ;
    END
  END wl_d[215]
  PIN wl_d[216]
    DIRECTION OUTPUT ;
    USE SIGNAL ;
    PORT
      LAYER M4 ;
        RECT 734.208 821.760 734.400 821.784 ;
    END
  END wl_d[216]
  PIN wl_d[217]
    DIRECTION OUTPUT ;
    USE SIGNAL ;
    PORT
      LAYER M4 ;
        RECT 734.208 822.672 734.400 822.696 ;
    END
  END wl_d[217]
  PIN wl_d[218]
    DIRECTION OUTPUT ;
    USE SIGNAL ;
    PORT
      LAYER M4 ;
        RECT 734.208 823.584 734.400 823.608 ;
    END
  END wl_d[218]
  PIN wl_d[219]
    DIRECTION OUTPUT ;
    USE SIGNAL ;
    PORT
      LAYER M4 ;
        RECT 734.208 824.496 734.400 824.520 ;
    END
  END wl_d[219]
  PIN wl_d[220]
    DIRECTION OUTPUT ;
    USE SIGNAL ;
    PORT
      LAYER M4 ;
        RECT 734.208 825.408 734.400 825.432 ;
    END
  END wl_d[220]
  PIN wl_d[221]
    DIRECTION OUTPUT ;
    USE SIGNAL ;
    PORT
      LAYER M4 ;
        RECT 734.208 826.272 734.400 826.296 ;
    END
  END wl_d[221]
  PIN wl_d[222]
    DIRECTION OUTPUT ;
    USE SIGNAL ;
    PORT
      LAYER M4 ;
        RECT 734.208 827.184 734.400 827.208 ;
    END
  END wl_d[222]
  PIN wl_d[223]
    DIRECTION OUTPUT ;
    USE SIGNAL ;
    PORT
      LAYER M4 ;
        RECT 734.208 828.096 734.400 828.120 ;
    END
  END wl_d[223]
  PIN wl_d[224]
    DIRECTION OUTPUT ;
    USE SIGNAL ;
    PORT
      LAYER M4 ;
        RECT 734.208 829.008 734.400 829.032 ;
    END
  END wl_d[224]
  PIN wl_d[225]
    DIRECTION OUTPUT ;
    USE SIGNAL ;
    PORT
      LAYER M4 ;
        RECT 734.208 829.920 734.400 829.944 ;
    END
  END wl_d[225]
  PIN wl_d[226]
    DIRECTION OUTPUT ;
    USE SIGNAL ;
    PORT
      LAYER M4 ;
        RECT 734.208 830.832 734.400 830.856 ;
    END
  END wl_d[226]
  PIN wl_d[227]
    DIRECTION OUTPUT ;
    USE SIGNAL ;
    PORT
      LAYER M4 ;
        RECT 734.208 831.744 734.400 831.768 ;
    END
  END wl_d[227]
  PIN wl_d[228]
    DIRECTION OUTPUT ;
    USE SIGNAL ;
    PORT
      LAYER M4 ;
        RECT 734.208 832.608 734.400 832.632 ;
    END
  END wl_d[228]
  PIN wl_d[229]
    DIRECTION OUTPUT ;
    USE SIGNAL ;
    PORT
      LAYER M4 ;
        RECT 734.208 833.520 734.400 833.544 ;
    END
  END wl_d[229]
  PIN wl_d[230]
    DIRECTION OUTPUT ;
    USE SIGNAL ;
    PORT
      LAYER M4 ;
        RECT 734.208 834.432 734.400 834.456 ;
    END
  END wl_d[230]
  PIN wl_d[231]
    DIRECTION OUTPUT ;
    USE SIGNAL ;
    PORT
      LAYER M4 ;
        RECT 734.208 835.344 734.400 835.368 ;
    END
  END wl_d[231]
  PIN wl_d[232]
    DIRECTION OUTPUT ;
    USE SIGNAL ;
    PORT
      LAYER M4 ;
        RECT 734.208 836.256 734.400 836.280 ;
    END
  END wl_d[232]
  PIN wl_d[233]
    DIRECTION OUTPUT ;
    USE SIGNAL ;
    PORT
      LAYER M4 ;
        RECT 734.208 837.168 734.400 837.192 ;
    END
  END wl_d[233]
  PIN wl_d[234]
    DIRECTION OUTPUT ;
    USE SIGNAL ;
    PORT
      LAYER M4 ;
        RECT 734.208 838.032 734.400 838.056 ;
    END
  END wl_d[234]
  PIN wl_d[235]
    DIRECTION OUTPUT ;
    USE SIGNAL ;
    PORT
      LAYER M4 ;
        RECT 734.208 838.944 734.400 838.968 ;
    END
  END wl_d[235]
  PIN wl_d[236]
    DIRECTION OUTPUT ;
    USE SIGNAL ;
    PORT
      LAYER M4 ;
        RECT 734.208 839.856 734.400 839.880 ;
    END
  END wl_d[236]
  PIN wl_d[237]
    DIRECTION OUTPUT ;
    USE SIGNAL ;
    PORT
      LAYER M4 ;
        RECT 734.208 840.768 734.400 840.792 ;
    END
  END wl_d[237]
  PIN wl_d[238]
    DIRECTION OUTPUT ;
    USE SIGNAL ;
    PORT
      LAYER M4 ;
        RECT 734.208 841.680 734.400 841.704 ;
    END
  END wl_d[238]
  PIN wl_d[239]
    DIRECTION OUTPUT ;
    USE SIGNAL ;
    PORT
      LAYER M4 ;
        RECT 734.208 842.592 734.400 842.616 ;
    END
  END wl_d[239]
  PIN wl_d[240]
    DIRECTION OUTPUT ;
    USE SIGNAL ;
    PORT
      LAYER M4 ;
        RECT 734.208 843.504 734.400 843.528 ;
    END
  END wl_d[240]
  PIN wl_d[241]
    DIRECTION OUTPUT ;
    USE SIGNAL ;
    PORT
      LAYER M4 ;
        RECT 734.208 844.368 734.400 844.392 ;
    END
  END wl_d[241]
  PIN wl_d[242]
    DIRECTION OUTPUT ;
    USE SIGNAL ;
    PORT
      LAYER M4 ;
        RECT 734.208 845.280 734.400 845.304 ;
    END
  END wl_d[242]
  PIN wl_d[243]
    DIRECTION OUTPUT ;
    USE SIGNAL ;
    PORT
      LAYER M4 ;
        RECT 734.208 846.192 734.400 846.216 ;
    END
  END wl_d[243]
  PIN wl_d[244]
    DIRECTION OUTPUT ;
    USE SIGNAL ;
    PORT
      LAYER M4 ;
        RECT 734.208 847.104 734.400 847.128 ;
    END
  END wl_d[244]
  PIN wl_d[245]
    DIRECTION OUTPUT ;
    USE SIGNAL ;
    PORT
      LAYER M4 ;
        RECT 734.208 848.016 734.400 848.040 ;
    END
  END wl_d[245]
  PIN wl_d[246]
    DIRECTION OUTPUT ;
    USE SIGNAL ;
    PORT
      LAYER M4 ;
        RECT 734.208 848.928 734.400 848.952 ;
    END
  END wl_d[246]
  PIN wl_d[247]
    DIRECTION OUTPUT ;
    USE SIGNAL ;
    PORT
      LAYER M4 ;
        RECT 734.208 849.840 734.400 849.864 ;
    END
  END wl_d[247]
  PIN wl_d[248]
    DIRECTION OUTPUT ;
    USE SIGNAL ;
    PORT
      LAYER M4 ;
        RECT 734.208 850.704 734.400 850.728 ;
    END
  END wl_d[248]
  PIN wl_d[249]
    DIRECTION OUTPUT ;
    USE SIGNAL ;
    PORT
      LAYER M4 ;
        RECT 734.208 851.616 734.400 851.640 ;
    END
  END wl_d[249]
  PIN wl_d[250]
    DIRECTION OUTPUT ;
    USE SIGNAL ;
    PORT
      LAYER M4 ;
        RECT 734.208 852.528 734.400 852.552 ;
    END
  END wl_d[250]
  PIN wl_d[251]
    DIRECTION OUTPUT ;
    USE SIGNAL ;
    PORT
      LAYER M4 ;
        RECT 734.208 853.440 734.400 853.464 ;
    END
  END wl_d[251]
  PIN wl_d[252]
    DIRECTION OUTPUT ;
    USE SIGNAL ;
    PORT
      LAYER M4 ;
        RECT 734.208 854.352 734.400 854.376 ;
    END
  END wl_d[252]
  PIN wl_d[253]
    DIRECTION OUTPUT ;
    USE SIGNAL ;
    PORT
      LAYER M4 ;
        RECT 734.208 855.264 734.400 855.288 ;
    END
  END wl_d[253]
  PIN wl_d[254]
    DIRECTION OUTPUT ;
    USE SIGNAL ;
    PORT
      LAYER M4 ;
        RECT 734.208 856.128 734.400 856.152 ;
    END
  END wl_d[254]
  PIN wl_d[255]
    DIRECTION OUTPUT ;
    USE SIGNAL ;
    PORT
      LAYER M4 ;
        RECT 734.208 857.040 734.400 857.064 ;
    END
  END wl_d[255]
  PIN s_v
    DIRECTION OUTPUT ;
    USE SIGNAL ;
    PORT
      LAYER M4 ;
        RECT 0.000 7.728 0.192 7.752 ;
    END
  END s_v
  PIN s_d[0]
    DIRECTION OUTPUT ;
    USE SIGNAL ;
    PORT
      LAYER M4 ;
        RECT 0.000 9.600 0.192 9.624 ;
    END
  END s_d[0]
  PIN s_d[1]
    DIRECTION OUTPUT ;
    USE SIGNAL ;
    PORT
      LAYER M4 ;
        RECT 0.000 10.800 0.192 10.824 ;
    END
  END s_d[1]
  PIN s_d[2]
    DIRECTION OUTPUT ;
    USE SIGNAL ;
    PORT
      LAYER M4 ;
        RECT 0.000 12.000 0.192 12.024 ;
    END
  END s_d[2]
  PIN s_d[3]
    DIRECTION OUTPUT ;
    USE SIGNAL ;
    PORT
      LAYER M4 ;
        RECT 0.000 13.200 0.192 13.224 ;
    END
  END s_d[3]
  PIN s_d[4]
    DIRECTION OUTPUT ;
    USE SIGNAL ;
    PORT
      LAYER M4 ;
        RECT 0.000 14.400 0.192 14.424 ;
    END
  END s_d[4]
  PIN s_d[5]
    DIRECTION OUTPUT ;
    USE SIGNAL ;
    PORT
      LAYER M4 ;
        RECT 0.000 15.600 0.192 15.624 ;
    END
  END s_d[5]
  PIN s_d[6]
    DIRECTION OUTPUT ;
    USE SIGNAL ;
    PORT
      LAYER M4 ;
        RECT 0.000 16.800 0.192 16.824 ;
    END
  END s_d[6]
  PIN s_d[7]
    DIRECTION OUTPUT ;
    USE SIGNAL ;
    PORT
      LAYER M4 ;
        RECT 0.000 18.048 0.192 18.072 ;
    END
  END s_d[7]
  PIN s_d[8]
    DIRECTION OUTPUT ;
    USE SIGNAL ;
    PORT
      LAYER M4 ;
        RECT 0.000 19.248 0.192 19.272 ;
    END
  END s_d[8]
  PIN s_d[9]
    DIRECTION OUTPUT ;
    USE SIGNAL ;
    PORT
      LAYER M4 ;
        RECT 0.000 20.448 0.192 20.472 ;
    END
  END s_d[9]
  PIN s_d[10]
    DIRECTION OUTPUT ;
    USE SIGNAL ;
    PORT
      LAYER M4 ;
        RECT 0.000 21.648 0.192 21.672 ;
    END
  END s_d[10]
  PIN s_d[11]
    DIRECTION OUTPUT ;
    USE SIGNAL ;
    PORT
      LAYER M4 ;
        RECT 0.000 22.848 0.192 22.872 ;
    END
  END s_d[11]
  PIN s_d[12]
    DIRECTION OUTPUT ;
    USE SIGNAL ;
    PORT
      LAYER M4 ;
        RECT 0.000 24.048 0.192 24.072 ;
    END
  END s_d[12]
  PIN s_d[13]
    DIRECTION OUTPUT ;
    USE SIGNAL ;
    PORT
      LAYER M4 ;
        RECT 0.000 25.248 0.192 25.272 ;
    END
  END s_d[13]
  PIN s_d[14]
    DIRECTION OUTPUT ;
    USE SIGNAL ;
    PORT
      LAYER M4 ;
        RECT 0.000 26.448 0.192 26.472 ;
    END
  END s_d[14]
  PIN s_d[15]
    DIRECTION OUTPUT ;
    USE SIGNAL ;
    PORT
      LAYER M4 ;
        RECT 0.000 27.648 0.192 27.672 ;
    END
  END s_d[15]
  PIN s_d[16]
    DIRECTION OUTPUT ;
    USE SIGNAL ;
    PORT
      LAYER M4 ;
        RECT 0.000 28.848 0.192 28.872 ;
    END
  END s_d[16]
  PIN s_d[17]
    DIRECTION OUTPUT ;
    USE SIGNAL ;
    PORT
      LAYER M4 ;
        RECT 0.000 30.048 0.192 30.072 ;
    END
  END s_d[17]
  PIN s_d[18]
    DIRECTION OUTPUT ;
    USE SIGNAL ;
    PORT
      LAYER M4 ;
        RECT 0.000 31.248 0.192 31.272 ;
    END
  END s_d[18]
  PIN s_d[19]
    DIRECTION OUTPUT ;
    USE SIGNAL ;
    PORT
      LAYER M4 ;
        RECT 0.000 32.448 0.192 32.472 ;
    END
  END s_d[19]
  PIN s_d[20]
    DIRECTION OUTPUT ;
    USE SIGNAL ;
    PORT
      LAYER M4 ;
        RECT 0.000 33.648 0.192 33.672 ;
    END
  END s_d[20]
  PIN s_d[21]
    DIRECTION OUTPUT ;
    USE SIGNAL ;
    PORT
      LAYER M4 ;
        RECT 0.000 34.848 0.192 34.872 ;
    END
  END s_d[21]
  PIN s_d[22]
    DIRECTION OUTPUT ;
    USE SIGNAL ;
    PORT
      LAYER M4 ;
        RECT 0.000 36.048 0.192 36.072 ;
    END
  END s_d[22]
  PIN s_d[23]
    DIRECTION OUTPUT ;
    USE SIGNAL ;
    PORT
      LAYER M4 ;
        RECT 0.000 37.248 0.192 37.272 ;
    END
  END s_d[23]
  PIN s_d[24]
    DIRECTION OUTPUT ;
    USE SIGNAL ;
    PORT
      LAYER M4 ;
        RECT 0.000 38.448 0.192 38.472 ;
    END
  END s_d[24]
  PIN s_d[25]
    DIRECTION OUTPUT ;
    USE SIGNAL ;
    PORT
      LAYER M4 ;
        RECT 0.000 39.648 0.192 39.672 ;
    END
  END s_d[25]
  PIN s_d[26]
    DIRECTION OUTPUT ;
    USE SIGNAL ;
    PORT
      LAYER M4 ;
        RECT 0.000 40.848 0.192 40.872 ;
    END
  END s_d[26]
  PIN s_d[27]
    DIRECTION OUTPUT ;
    USE SIGNAL ;
    PORT
      LAYER M4 ;
        RECT 0.000 42.048 0.192 42.072 ;
    END
  END s_d[27]
  PIN s_d[28]
    DIRECTION OUTPUT ;
    USE SIGNAL ;
    PORT
      LAYER M4 ;
        RECT 0.000 43.248 0.192 43.272 ;
    END
  END s_d[28]
  PIN s_d[29]
    DIRECTION OUTPUT ;
    USE SIGNAL ;
    PORT
      LAYER M4 ;
        RECT 0.000 44.448 0.192 44.472 ;
    END
  END s_d[29]
  PIN s_d[30]
    DIRECTION OUTPUT ;
    USE SIGNAL ;
    PORT
      LAYER M4 ;
        RECT 0.000 45.648 0.192 45.672 ;
    END
  END s_d[30]
  PIN s_d[31]
    DIRECTION OUTPUT ;
    USE SIGNAL ;
    PORT
      LAYER M4 ;
        RECT 0.000 46.848 0.192 46.872 ;
    END
  END s_d[31]
  PIN s_d[32]
    DIRECTION OUTPUT ;
    USE SIGNAL ;
    PORT
      LAYER M4 ;
        RECT 0.000 48.048 0.192 48.072 ;
    END
  END s_d[32]
  PIN s_d[33]
    DIRECTION OUTPUT ;
    USE SIGNAL ;
    PORT
      LAYER M4 ;
        RECT 0.000 49.248 0.192 49.272 ;
    END
  END s_d[33]
  PIN s_d[34]
    DIRECTION OUTPUT ;
    USE SIGNAL ;
    PORT
      LAYER M4 ;
        RECT 0.000 50.448 0.192 50.472 ;
    END
  END s_d[34]
  PIN s_d[35]
    DIRECTION OUTPUT ;
    USE SIGNAL ;
    PORT
      LAYER M4 ;
        RECT 0.000 51.648 0.192 51.672 ;
    END
  END s_d[35]
  PIN s_d[36]
    DIRECTION OUTPUT ;
    USE SIGNAL ;
    PORT
      LAYER M4 ;
        RECT 0.000 52.848 0.192 52.872 ;
    END
  END s_d[36]
  PIN s_d[37]
    DIRECTION OUTPUT ;
    USE SIGNAL ;
    PORT
      LAYER M4 ;
        RECT 0.000 54.048 0.192 54.072 ;
    END
  END s_d[37]
  PIN s_d[38]
    DIRECTION OUTPUT ;
    USE SIGNAL ;
    PORT
      LAYER M4 ;
        RECT 0.000 55.248 0.192 55.272 ;
    END
  END s_d[38]
  PIN s_d[39]
    DIRECTION OUTPUT ;
    USE SIGNAL ;
    PORT
      LAYER M4 ;
        RECT 0.000 56.448 0.192 56.472 ;
    END
  END s_d[39]
  PIN s_d[40]
    DIRECTION OUTPUT ;
    USE SIGNAL ;
    PORT
      LAYER M4 ;
        RECT 0.000 57.648 0.192 57.672 ;
    END
  END s_d[40]
  PIN s_d[41]
    DIRECTION OUTPUT ;
    USE SIGNAL ;
    PORT
      LAYER M4 ;
        RECT 0.000 58.848 0.192 58.872 ;
    END
  END s_d[41]
  PIN s_d[42]
    DIRECTION OUTPUT ;
    USE SIGNAL ;
    PORT
      LAYER M4 ;
        RECT 0.000 60.048 0.192 60.072 ;
    END
  END s_d[42]
  PIN s_d[43]
    DIRECTION OUTPUT ;
    USE SIGNAL ;
    PORT
      LAYER M4 ;
        RECT 0.000 61.248 0.192 61.272 ;
    END
  END s_d[43]
  PIN s_d[44]
    DIRECTION OUTPUT ;
    USE SIGNAL ;
    PORT
      LAYER M4 ;
        RECT 0.000 62.448 0.192 62.472 ;
    END
  END s_d[44]
  PIN s_d[45]
    DIRECTION OUTPUT ;
    USE SIGNAL ;
    PORT
      LAYER M4 ;
        RECT 0.000 63.648 0.192 63.672 ;
    END
  END s_d[45]
  PIN s_d[46]
    DIRECTION OUTPUT ;
    USE SIGNAL ;
    PORT
      LAYER M4 ;
        RECT 0.000 64.896 0.192 64.920 ;
    END
  END s_d[46]
  PIN s_d[47]
    DIRECTION OUTPUT ;
    USE SIGNAL ;
    PORT
      LAYER M4 ;
        RECT 0.000 66.096 0.192 66.120 ;
    END
  END s_d[47]
  PIN s_d[48]
    DIRECTION OUTPUT ;
    USE SIGNAL ;
    PORT
      LAYER M4 ;
        RECT 0.000 67.296 0.192 67.320 ;
    END
  END s_d[48]
  PIN s_d[49]
    DIRECTION OUTPUT ;
    USE SIGNAL ;
    PORT
      LAYER M4 ;
        RECT 0.000 68.496 0.192 68.520 ;
    END
  END s_d[49]
  PIN s_d[50]
    DIRECTION OUTPUT ;
    USE SIGNAL ;
    PORT
      LAYER M4 ;
        RECT 0.000 69.696 0.192 69.720 ;
    END
  END s_d[50]
  PIN s_d[51]
    DIRECTION OUTPUT ;
    USE SIGNAL ;
    PORT
      LAYER M4 ;
        RECT 0.000 70.896 0.192 70.920 ;
    END
  END s_d[51]
  PIN s_d[52]
    DIRECTION OUTPUT ;
    USE SIGNAL ;
    PORT
      LAYER M4 ;
        RECT 0.000 72.096 0.192 72.120 ;
    END
  END s_d[52]
  PIN s_d[53]
    DIRECTION OUTPUT ;
    USE SIGNAL ;
    PORT
      LAYER M4 ;
        RECT 0.000 73.296 0.192 73.320 ;
    END
  END s_d[53]
  PIN s_d[54]
    DIRECTION OUTPUT ;
    USE SIGNAL ;
    PORT
      LAYER M4 ;
        RECT 0.000 74.496 0.192 74.520 ;
    END
  END s_d[54]
  PIN s_d[55]
    DIRECTION OUTPUT ;
    USE SIGNAL ;
    PORT
      LAYER M4 ;
        RECT 0.000 75.696 0.192 75.720 ;
    END
  END s_d[55]
  PIN s_d[56]
    DIRECTION OUTPUT ;
    USE SIGNAL ;
    PORT
      LAYER M4 ;
        RECT 0.000 76.896 0.192 76.920 ;
    END
  END s_d[56]
  PIN s_d[57]
    DIRECTION OUTPUT ;
    USE SIGNAL ;
    PORT
      LAYER M4 ;
        RECT 0.000 78.096 0.192 78.120 ;
    END
  END s_d[57]
  PIN s_d[58]
    DIRECTION OUTPUT ;
    USE SIGNAL ;
    PORT
      LAYER M4 ;
        RECT 0.000 79.296 0.192 79.320 ;
    END
  END s_d[58]
  PIN s_d[59]
    DIRECTION OUTPUT ;
    USE SIGNAL ;
    PORT
      LAYER M4 ;
        RECT 0.000 80.496 0.192 80.520 ;
    END
  END s_d[59]
  PIN s_d[60]
    DIRECTION OUTPUT ;
    USE SIGNAL ;
    PORT
      LAYER M4 ;
        RECT 0.000 81.696 0.192 81.720 ;
    END
  END s_d[60]
  PIN s_d[61]
    DIRECTION OUTPUT ;
    USE SIGNAL ;
    PORT
      LAYER M4 ;
        RECT 0.000 82.896 0.192 82.920 ;
    END
  END s_d[61]
  PIN s_d[62]
    DIRECTION OUTPUT ;
    USE SIGNAL ;
    PORT
      LAYER M4 ;
        RECT 0.000 84.096 0.192 84.120 ;
    END
  END s_d[62]
  PIN s_d[63]
    DIRECTION OUTPUT ;
    USE SIGNAL ;
    PORT
      LAYER M4 ;
        RECT 0.000 85.296 0.192 85.320 ;
    END
  END s_d[63]
  PIN s_d[64]
    DIRECTION OUTPUT ;
    USE SIGNAL ;
    PORT
      LAYER M4 ;
        RECT 0.000 86.496 0.192 86.520 ;
    END
  END s_d[64]
  PIN s_d[65]
    DIRECTION OUTPUT ;
    USE SIGNAL ;
    PORT
      LAYER M4 ;
        RECT 0.000 87.696 0.192 87.720 ;
    END
  END s_d[65]
  PIN s_d[66]
    DIRECTION OUTPUT ;
    USE SIGNAL ;
    PORT
      LAYER M4 ;
        RECT 0.000 88.896 0.192 88.920 ;
    END
  END s_d[66]
  PIN s_d[67]
    DIRECTION OUTPUT ;
    USE SIGNAL ;
    PORT
      LAYER M4 ;
        RECT 0.000 90.096 0.192 90.120 ;
    END
  END s_d[67]
  PIN s_d[68]
    DIRECTION OUTPUT ;
    USE SIGNAL ;
    PORT
      LAYER M4 ;
        RECT 0.000 91.296 0.192 91.320 ;
    END
  END s_d[68]
  PIN s_d[69]
    DIRECTION OUTPUT ;
    USE SIGNAL ;
    PORT
      LAYER M4 ;
        RECT 0.000 92.496 0.192 92.520 ;
    END
  END s_d[69]
  PIN s_d[70]
    DIRECTION OUTPUT ;
    USE SIGNAL ;
    PORT
      LAYER M4 ;
        RECT 0.000 93.696 0.192 93.720 ;
    END
  END s_d[70]
  PIN s_d[71]
    DIRECTION OUTPUT ;
    USE SIGNAL ;
    PORT
      LAYER M4 ;
        RECT 0.000 94.896 0.192 94.920 ;
    END
  END s_d[71]
  PIN s_d[72]
    DIRECTION OUTPUT ;
    USE SIGNAL ;
    PORT
      LAYER M4 ;
        RECT 0.000 96.096 0.192 96.120 ;
    END
  END s_d[72]
  PIN s_d[73]
    DIRECTION OUTPUT ;
    USE SIGNAL ;
    PORT
      LAYER M4 ;
        RECT 0.000 97.296 0.192 97.320 ;
    END
  END s_d[73]
  PIN s_d[74]
    DIRECTION OUTPUT ;
    USE SIGNAL ;
    PORT
      LAYER M4 ;
        RECT 0.000 98.496 0.192 98.520 ;
    END
  END s_d[74]
  PIN s_d[75]
    DIRECTION OUTPUT ;
    USE SIGNAL ;
    PORT
      LAYER M4 ;
        RECT 0.000 99.696 0.192 99.720 ;
    END
  END s_d[75]
  PIN s_d[76]
    DIRECTION OUTPUT ;
    USE SIGNAL ;
    PORT
      LAYER M4 ;
        RECT 0.000 100.896 0.192 100.920 ;
    END
  END s_d[76]
  PIN s_d[77]
    DIRECTION OUTPUT ;
    USE SIGNAL ;
    PORT
      LAYER M4 ;
        RECT 0.000 102.096 0.192 102.120 ;
    END
  END s_d[77]
  PIN s_d[78]
    DIRECTION OUTPUT ;
    USE SIGNAL ;
    PORT
      LAYER M4 ;
        RECT 0.000 103.296 0.192 103.320 ;
    END
  END s_d[78]
  PIN s_d[79]
    DIRECTION OUTPUT ;
    USE SIGNAL ;
    PORT
      LAYER M4 ;
        RECT 0.000 104.496 0.192 104.520 ;
    END
  END s_d[79]
  PIN s_d[80]
    DIRECTION OUTPUT ;
    USE SIGNAL ;
    PORT
      LAYER M4 ;
        RECT 0.000 105.696 0.192 105.720 ;
    END
  END s_d[80]
  PIN s_d[81]
    DIRECTION OUTPUT ;
    USE SIGNAL ;
    PORT
      LAYER M4 ;
        RECT 0.000 106.896 0.192 106.920 ;
    END
  END s_d[81]
  PIN s_d[82]
    DIRECTION OUTPUT ;
    USE SIGNAL ;
    PORT
      LAYER M4 ;
        RECT 0.000 108.096 0.192 108.120 ;
    END
  END s_d[82]
  PIN s_d[83]
    DIRECTION OUTPUT ;
    USE SIGNAL ;
    PORT
      LAYER M4 ;
        RECT 0.000 109.296 0.192 109.320 ;
    END
  END s_d[83]
  PIN s_d[84]
    DIRECTION OUTPUT ;
    USE SIGNAL ;
    PORT
      LAYER M4 ;
        RECT 0.000 110.496 0.192 110.520 ;
    END
  END s_d[84]
  PIN s_d[85]
    DIRECTION OUTPUT ;
    USE SIGNAL ;
    PORT
      LAYER M4 ;
        RECT 0.000 111.696 0.192 111.720 ;
    END
  END s_d[85]
  PIN s_d[86]
    DIRECTION OUTPUT ;
    USE SIGNAL ;
    PORT
      LAYER M4 ;
        RECT 0.000 112.944 0.192 112.968 ;
    END
  END s_d[86]
  PIN s_d[87]
    DIRECTION OUTPUT ;
    USE SIGNAL ;
    PORT
      LAYER M4 ;
        RECT 0.000 114.144 0.192 114.168 ;
    END
  END s_d[87]
  PIN s_d[88]
    DIRECTION OUTPUT ;
    USE SIGNAL ;
    PORT
      LAYER M4 ;
        RECT 0.000 115.344 0.192 115.368 ;
    END
  END s_d[88]
  PIN s_d[89]
    DIRECTION OUTPUT ;
    USE SIGNAL ;
    PORT
      LAYER M4 ;
        RECT 0.000 116.544 0.192 116.568 ;
    END
  END s_d[89]
  PIN s_d[90]
    DIRECTION OUTPUT ;
    USE SIGNAL ;
    PORT
      LAYER M4 ;
        RECT 0.000 117.744 0.192 117.768 ;
    END
  END s_d[90]
  PIN s_d[91]
    DIRECTION OUTPUT ;
    USE SIGNAL ;
    PORT
      LAYER M4 ;
        RECT 0.000 118.944 0.192 118.968 ;
    END
  END s_d[91]
  PIN s_d[92]
    DIRECTION OUTPUT ;
    USE SIGNAL ;
    PORT
      LAYER M4 ;
        RECT 0.000 120.144 0.192 120.168 ;
    END
  END s_d[92]
  PIN s_d[93]
    DIRECTION OUTPUT ;
    USE SIGNAL ;
    PORT
      LAYER M4 ;
        RECT 0.000 121.344 0.192 121.368 ;
    END
  END s_d[93]
  PIN s_d[94]
    DIRECTION OUTPUT ;
    USE SIGNAL ;
    PORT
      LAYER M4 ;
        RECT 0.000 122.544 0.192 122.568 ;
    END
  END s_d[94]
  PIN s_d[95]
    DIRECTION OUTPUT ;
    USE SIGNAL ;
    PORT
      LAYER M4 ;
        RECT 0.000 123.744 0.192 123.768 ;
    END
  END s_d[95]
  PIN s_d[96]
    DIRECTION OUTPUT ;
    USE SIGNAL ;
    PORT
      LAYER M4 ;
        RECT 0.000 124.944 0.192 124.968 ;
    END
  END s_d[96]
  PIN s_d[97]
    DIRECTION OUTPUT ;
    USE SIGNAL ;
    PORT
      LAYER M4 ;
        RECT 0.000 126.144 0.192 126.168 ;
    END
  END s_d[97]
  PIN s_d[98]
    DIRECTION OUTPUT ;
    USE SIGNAL ;
    PORT
      LAYER M4 ;
        RECT 0.000 127.344 0.192 127.368 ;
    END
  END s_d[98]
  PIN s_d[99]
    DIRECTION OUTPUT ;
    USE SIGNAL ;
    PORT
      LAYER M4 ;
        RECT 0.000 128.544 0.192 128.568 ;
    END
  END s_d[99]
  PIN s_d[100]
    DIRECTION OUTPUT ;
    USE SIGNAL ;
    PORT
      LAYER M4 ;
        RECT 0.000 129.744 0.192 129.768 ;
    END
  END s_d[100]
  PIN s_d[101]
    DIRECTION OUTPUT ;
    USE SIGNAL ;
    PORT
      LAYER M4 ;
        RECT 0.000 130.944 0.192 130.968 ;
    END
  END s_d[101]
  PIN s_d[102]
    DIRECTION OUTPUT ;
    USE SIGNAL ;
    PORT
      LAYER M4 ;
        RECT 0.000 132.144 0.192 132.168 ;
    END
  END s_d[102]
  PIN s_d[103]
    DIRECTION OUTPUT ;
    USE SIGNAL ;
    PORT
      LAYER M4 ;
        RECT 0.000 133.344 0.192 133.368 ;
    END
  END s_d[103]
  PIN s_d[104]
    DIRECTION OUTPUT ;
    USE SIGNAL ;
    PORT
      LAYER M4 ;
        RECT 0.000 134.544 0.192 134.568 ;
    END
  END s_d[104]
  PIN s_d[105]
    DIRECTION OUTPUT ;
    USE SIGNAL ;
    PORT
      LAYER M4 ;
        RECT 0.000 135.744 0.192 135.768 ;
    END
  END s_d[105]
  PIN s_d[106]
    DIRECTION OUTPUT ;
    USE SIGNAL ;
    PORT
      LAYER M4 ;
        RECT 0.000 136.944 0.192 136.968 ;
    END
  END s_d[106]
  PIN s_d[107]
    DIRECTION OUTPUT ;
    USE SIGNAL ;
    PORT
      LAYER M4 ;
        RECT 0.000 138.144 0.192 138.168 ;
    END
  END s_d[107]
  PIN s_d[108]
    DIRECTION OUTPUT ;
    USE SIGNAL ;
    PORT
      LAYER M4 ;
        RECT 0.000 139.344 0.192 139.368 ;
    END
  END s_d[108]
  PIN s_d[109]
    DIRECTION OUTPUT ;
    USE SIGNAL ;
    PORT
      LAYER M4 ;
        RECT 0.000 140.544 0.192 140.568 ;
    END
  END s_d[109]
  PIN s_d[110]
    DIRECTION OUTPUT ;
    USE SIGNAL ;
    PORT
      LAYER M4 ;
        RECT 0.000 141.744 0.192 141.768 ;
    END
  END s_d[110]
  PIN s_d[111]
    DIRECTION OUTPUT ;
    USE SIGNAL ;
    PORT
      LAYER M4 ;
        RECT 0.000 142.944 0.192 142.968 ;
    END
  END s_d[111]
  PIN s_d[112]
    DIRECTION OUTPUT ;
    USE SIGNAL ;
    PORT
      LAYER M4 ;
        RECT 0.000 144.144 0.192 144.168 ;
    END
  END s_d[112]
  PIN s_d[113]
    DIRECTION OUTPUT ;
    USE SIGNAL ;
    PORT
      LAYER M4 ;
        RECT 0.000 145.344 0.192 145.368 ;
    END
  END s_d[113]
  PIN s_d[114]
    DIRECTION OUTPUT ;
    USE SIGNAL ;
    PORT
      LAYER M4 ;
        RECT 0.000 146.544 0.192 146.568 ;
    END
  END s_d[114]
  PIN s_d[115]
    DIRECTION OUTPUT ;
    USE SIGNAL ;
    PORT
      LAYER M4 ;
        RECT 0.000 147.744 0.192 147.768 ;
    END
  END s_d[115]
  PIN s_d[116]
    DIRECTION OUTPUT ;
    USE SIGNAL ;
    PORT
      LAYER M4 ;
        RECT 0.000 148.944 0.192 148.968 ;
    END
  END s_d[116]
  PIN s_d[117]
    DIRECTION OUTPUT ;
    USE SIGNAL ;
    PORT
      LAYER M4 ;
        RECT 0.000 150.144 0.192 150.168 ;
    END
  END s_d[117]
  PIN s_d[118]
    DIRECTION OUTPUT ;
    USE SIGNAL ;
    PORT
      LAYER M4 ;
        RECT 0.000 151.344 0.192 151.368 ;
    END
  END s_d[118]
  PIN s_d[119]
    DIRECTION OUTPUT ;
    USE SIGNAL ;
    PORT
      LAYER M4 ;
        RECT 0.000 152.544 0.192 152.568 ;
    END
  END s_d[119]
  PIN s_d[120]
    DIRECTION OUTPUT ;
    USE SIGNAL ;
    PORT
      LAYER M4 ;
        RECT 0.000 153.744 0.192 153.768 ;
    END
  END s_d[120]
  PIN s_d[121]
    DIRECTION OUTPUT ;
    USE SIGNAL ;
    PORT
      LAYER M4 ;
        RECT 0.000 154.944 0.192 154.968 ;
    END
  END s_d[121]
  PIN s_d[122]
    DIRECTION OUTPUT ;
    USE SIGNAL ;
    PORT
      LAYER M4 ;
        RECT 0.000 156.144 0.192 156.168 ;
    END
  END s_d[122]
  PIN s_d[123]
    DIRECTION OUTPUT ;
    USE SIGNAL ;
    PORT
      LAYER M4 ;
        RECT 0.000 157.344 0.192 157.368 ;
    END
  END s_d[123]
  PIN s_d[124]
    DIRECTION OUTPUT ;
    USE SIGNAL ;
    PORT
      LAYER M4 ;
        RECT 0.000 158.544 0.192 158.568 ;
    END
  END s_d[124]
  PIN s_d[125]
    DIRECTION OUTPUT ;
    USE SIGNAL ;
    PORT
      LAYER M4 ;
        RECT 0.000 159.792 0.192 159.816 ;
    END
  END s_d[125]
  PIN s_d[126]
    DIRECTION OUTPUT ;
    USE SIGNAL ;
    PORT
      LAYER M4 ;
        RECT 0.000 160.992 0.192 161.016 ;
    END
  END s_d[126]
  PIN s_d[127]
    DIRECTION OUTPUT ;
    USE SIGNAL ;
    PORT
      LAYER M4 ;
        RECT 0.000 162.192 0.192 162.216 ;
    END
  END s_d[127]
  PIN s_d[128]
    DIRECTION OUTPUT ;
    USE SIGNAL ;
    PORT
      LAYER M4 ;
        RECT 0.000 163.392 0.192 163.416 ;
    END
  END s_d[128]
  PIN s_d[129]
    DIRECTION OUTPUT ;
    USE SIGNAL ;
    PORT
      LAYER M4 ;
        RECT 0.000 164.592 0.192 164.616 ;
    END
  END s_d[129]
  PIN s_d[130]
    DIRECTION OUTPUT ;
    USE SIGNAL ;
    PORT
      LAYER M4 ;
        RECT 0.000 165.792 0.192 165.816 ;
    END
  END s_d[130]
  PIN s_d[131]
    DIRECTION OUTPUT ;
    USE SIGNAL ;
    PORT
      LAYER M4 ;
        RECT 0.000 166.992 0.192 167.016 ;
    END
  END s_d[131]
  PIN s_d[132]
    DIRECTION OUTPUT ;
    USE SIGNAL ;
    PORT
      LAYER M4 ;
        RECT 0.000 168.192 0.192 168.216 ;
    END
  END s_d[132]
  PIN s_d[133]
    DIRECTION OUTPUT ;
    USE SIGNAL ;
    PORT
      LAYER M4 ;
        RECT 0.000 169.392 0.192 169.416 ;
    END
  END s_d[133]
  PIN s_d[134]
    DIRECTION OUTPUT ;
    USE SIGNAL ;
    PORT
      LAYER M4 ;
        RECT 0.000 170.592 0.192 170.616 ;
    END
  END s_d[134]
  PIN s_d[135]
    DIRECTION OUTPUT ;
    USE SIGNAL ;
    PORT
      LAYER M4 ;
        RECT 0.000 171.792 0.192 171.816 ;
    END
  END s_d[135]
  PIN s_d[136]
    DIRECTION OUTPUT ;
    USE SIGNAL ;
    PORT
      LAYER M4 ;
        RECT 0.000 172.992 0.192 173.016 ;
    END
  END s_d[136]
  PIN s_d[137]
    DIRECTION OUTPUT ;
    USE SIGNAL ;
    PORT
      LAYER M4 ;
        RECT 0.000 174.192 0.192 174.216 ;
    END
  END s_d[137]
  PIN s_d[138]
    DIRECTION OUTPUT ;
    USE SIGNAL ;
    PORT
      LAYER M4 ;
        RECT 0.000 175.392 0.192 175.416 ;
    END
  END s_d[138]
  PIN s_d[139]
    DIRECTION OUTPUT ;
    USE SIGNAL ;
    PORT
      LAYER M4 ;
        RECT 0.000 176.592 0.192 176.616 ;
    END
  END s_d[139]
  PIN s_d[140]
    DIRECTION OUTPUT ;
    USE SIGNAL ;
    PORT
      LAYER M4 ;
        RECT 0.000 177.792 0.192 177.816 ;
    END
  END s_d[140]
  PIN s_d[141]
    DIRECTION OUTPUT ;
    USE SIGNAL ;
    PORT
      LAYER M4 ;
        RECT 0.000 178.992 0.192 179.016 ;
    END
  END s_d[141]
  PIN s_d[142]
    DIRECTION OUTPUT ;
    USE SIGNAL ;
    PORT
      LAYER M4 ;
        RECT 0.000 180.192 0.192 180.216 ;
    END
  END s_d[142]
  PIN s_d[143]
    DIRECTION OUTPUT ;
    USE SIGNAL ;
    PORT
      LAYER M4 ;
        RECT 0.000 181.392 0.192 181.416 ;
    END
  END s_d[143]
  PIN s_d[144]
    DIRECTION OUTPUT ;
    USE SIGNAL ;
    PORT
      LAYER M4 ;
        RECT 0.000 182.592 0.192 182.616 ;
    END
  END s_d[144]
  PIN s_d[145]
    DIRECTION OUTPUT ;
    USE SIGNAL ;
    PORT
      LAYER M4 ;
        RECT 0.000 183.792 0.192 183.816 ;
    END
  END s_d[145]
  PIN s_d[146]
    DIRECTION OUTPUT ;
    USE SIGNAL ;
    PORT
      LAYER M4 ;
        RECT 0.000 184.992 0.192 185.016 ;
    END
  END s_d[146]
  PIN s_d[147]
    DIRECTION OUTPUT ;
    USE SIGNAL ;
    PORT
      LAYER M4 ;
        RECT 0.000 186.192 0.192 186.216 ;
    END
  END s_d[147]
  PIN s_d[148]
    DIRECTION OUTPUT ;
    USE SIGNAL ;
    PORT
      LAYER M4 ;
        RECT 0.000 187.392 0.192 187.416 ;
    END
  END s_d[148]
  PIN s_d[149]
    DIRECTION OUTPUT ;
    USE SIGNAL ;
    PORT
      LAYER M4 ;
        RECT 0.000 188.592 0.192 188.616 ;
    END
  END s_d[149]
  PIN s_d[150]
    DIRECTION OUTPUT ;
    USE SIGNAL ;
    PORT
      LAYER M4 ;
        RECT 0.000 189.792 0.192 189.816 ;
    END
  END s_d[150]
  PIN s_d[151]
    DIRECTION OUTPUT ;
    USE SIGNAL ;
    PORT
      LAYER M4 ;
        RECT 0.000 190.992 0.192 191.016 ;
    END
  END s_d[151]
  PIN s_d[152]
    DIRECTION OUTPUT ;
    USE SIGNAL ;
    PORT
      LAYER M4 ;
        RECT 0.000 192.192 0.192 192.216 ;
    END
  END s_d[152]
  PIN s_d[153]
    DIRECTION OUTPUT ;
    USE SIGNAL ;
    PORT
      LAYER M4 ;
        RECT 0.000 193.392 0.192 193.416 ;
    END
  END s_d[153]
  PIN s_d[154]
    DIRECTION OUTPUT ;
    USE SIGNAL ;
    PORT
      LAYER M4 ;
        RECT 0.000 194.592 0.192 194.616 ;
    END
  END s_d[154]
  PIN s_d[155]
    DIRECTION OUTPUT ;
    USE SIGNAL ;
    PORT
      LAYER M4 ;
        RECT 0.000 195.792 0.192 195.816 ;
    END
  END s_d[155]
  PIN s_d[156]
    DIRECTION OUTPUT ;
    USE SIGNAL ;
    PORT
      LAYER M4 ;
        RECT 0.000 196.992 0.192 197.016 ;
    END
  END s_d[156]
  PIN s_d[157]
    DIRECTION OUTPUT ;
    USE SIGNAL ;
    PORT
      LAYER M4 ;
        RECT 0.000 198.192 0.192 198.216 ;
    END
  END s_d[157]
  PIN s_d[158]
    DIRECTION OUTPUT ;
    USE SIGNAL ;
    PORT
      LAYER M4 ;
        RECT 0.000 199.392 0.192 199.416 ;
    END
  END s_d[158]
  PIN s_d[159]
    DIRECTION OUTPUT ;
    USE SIGNAL ;
    PORT
      LAYER M4 ;
        RECT 0.000 200.592 0.192 200.616 ;
    END
  END s_d[159]
  PIN x_rv
    DIRECTION INPUT ;
    USE SIGNAL ;
    PORT
      LAYER M4 ;
        RECT 0.000 202.464 0.192 202.488 ;
    END
  END x_rv
  PIN x_ra[0]
    DIRECTION INPUT ;
    USE SIGNAL ;
    PORT
      LAYER M4 ;
        RECT 0.000 204.336 0.192 204.360 ;
    END
  END x_ra[0]
  PIN x_ra[1]
    DIRECTION INPUT ;
    USE SIGNAL ;
    PORT
      LAYER M4 ;
        RECT 0.000 205.536 0.192 205.560 ;
    END
  END x_ra[1]
  PIN x_ra[2]
    DIRECTION INPUT ;
    USE SIGNAL ;
    PORT
      LAYER M4 ;
        RECT 0.000 206.784 0.192 206.808 ;
    END
  END x_ra[2]
  PIN x_ra[3]
    DIRECTION INPUT ;
    USE SIGNAL ;
    PORT
      LAYER M4 ;
        RECT 0.000 207.984 0.192 208.008 ;
    END
  END x_ra[3]
  PIN x_ra[4]
    DIRECTION INPUT ;
    USE SIGNAL ;
    PORT
      LAYER M4 ;
        RECT 0.000 209.184 0.192 209.208 ;
    END
  END x_ra[4]
  PIN x_ra[5]
    DIRECTION INPUT ;
    USE SIGNAL ;
    PORT
      LAYER M4 ;
        RECT 0.000 210.384 0.192 210.408 ;
    END
  END x_ra[5]
  PIN x_ra[6]
    DIRECTION INPUT ;
    USE SIGNAL ;
    PORT
      LAYER M4 ;
        RECT 0.000 211.584 0.192 211.608 ;
    END
  END x_ra[6]
  PIN x_ra[7]
    DIRECTION INPUT ;
    USE SIGNAL ;
    PORT
      LAYER M4 ;
        RECT 0.000 212.784 0.192 212.808 ;
    END
  END x_ra[7]
  PIN x_ra[8]
    DIRECTION INPUT ;
    USE SIGNAL ;
    PORT
      LAYER M4 ;
        RECT 0.000 213.984 0.192 214.008 ;
    END
  END x_ra[8]
  PIN x_ra[9]
    DIRECTION INPUT ;
    USE SIGNAL ;
    PORT
      LAYER M4 ;
        RECT 0.000 215.184 0.192 215.208 ;
    END
  END x_ra[9]
  PIN x_qv
    DIRECTION OUTPUT ;
    USE SIGNAL ;
    PORT
      LAYER M4 ;
        RECT 0.000 217.056 0.192 217.080 ;
    END
  END x_qv
  PIN x_qd[0]
    DIRECTION OUTPUT ;
    USE SIGNAL ;
    PORT
      LAYER M4 ;
        RECT 0.000 218.928 0.192 218.952 ;
    END
  END x_qd[0]
  PIN x_qd[1]
    DIRECTION OUTPUT ;
    USE SIGNAL ;
    PORT
      LAYER M4 ;
        RECT 0.000 220.128 0.192 220.152 ;
    END
  END x_qd[1]
  PIN x_qd[2]
    DIRECTION OUTPUT ;
    USE SIGNAL ;
    PORT
      LAYER M4 ;
        RECT 0.000 221.328 0.192 221.352 ;
    END
  END x_qd[2]
  PIN x_qd[3]
    DIRECTION OUTPUT ;
    USE SIGNAL ;
    PORT
      LAYER M4 ;
        RECT 0.000 222.528 0.192 222.552 ;
    END
  END x_qd[3]
  PIN x_qd[4]
    DIRECTION OUTPUT ;
    USE SIGNAL ;
    PORT
      LAYER M4 ;
        RECT 0.000 223.728 0.192 223.752 ;
    END
  END x_qd[4]
  PIN x_qd[5]
    DIRECTION OUTPUT ;
    USE SIGNAL ;
    PORT
      LAYER M4 ;
        RECT 0.000 224.928 0.192 224.952 ;
    END
  END x_qd[5]
  PIN x_qd[6]
    DIRECTION OUTPUT ;
    USE SIGNAL ;
    PORT
      LAYER M4 ;
        RECT 0.000 226.128 0.192 226.152 ;
    END
  END x_qd[6]
  PIN x_qd[7]
    DIRECTION OUTPUT ;
    USE SIGNAL ;
    PORT
      LAYER M4 ;
        RECT 0.000 227.328 0.192 227.352 ;
    END
  END x_qd[7]
  PIN x_qd[8]
    DIRECTION OUTPUT ;
    USE SIGNAL ;
    PORT
      LAYER M4 ;
        RECT 0.000 228.528 0.192 228.552 ;
    END
  END x_qd[8]
  PIN x_qd[9]
    DIRECTION OUTPUT ;
    USE SIGNAL ;
    PORT
      LAYER M4 ;
        RECT 0.000 229.728 0.192 229.752 ;
    END
  END x_qd[9]
  PIN x_qd[10]
    DIRECTION OUTPUT ;
    USE SIGNAL ;
    PORT
      LAYER M4 ;
        RECT 0.000 230.928 0.192 230.952 ;
    END
  END x_qd[10]
  PIN x_qd[11]
    DIRECTION OUTPUT ;
    USE SIGNAL ;
    PORT
      LAYER M4 ;
        RECT 0.000 232.128 0.192 232.152 ;
    END
  END x_qd[11]
  PIN x_qd[12]
    DIRECTION OUTPUT ;
    USE SIGNAL ;
    PORT
      LAYER M4 ;
        RECT 0.000 233.328 0.192 233.352 ;
    END
  END x_qd[12]
  PIN x_qd[13]
    DIRECTION OUTPUT ;
    USE SIGNAL ;
    PORT
      LAYER M4 ;
        RECT 0.000 234.528 0.192 234.552 ;
    END
  END x_qd[13]
  PIN x_qd[14]
    DIRECTION OUTPUT ;
    USE SIGNAL ;
    PORT
      LAYER M4 ;
        RECT 0.000 235.728 0.192 235.752 ;
    END
  END x_qd[14]
  PIN x_qd[15]
    DIRECTION OUTPUT ;
    USE SIGNAL ;
    PORT
      LAYER M4 ;
        RECT 0.000 236.928 0.192 236.952 ;
    END
  END x_qd[15]
  PIN x_qd[16]
    DIRECTION OUTPUT ;
    USE SIGNAL ;
    PORT
      LAYER M4 ;
        RECT 0.000 238.128 0.192 238.152 ;
    END
  END x_qd[16]
  PIN x_qd[17]
    DIRECTION OUTPUT ;
    USE SIGNAL ;
    PORT
      LAYER M4 ;
        RECT 0.000 239.328 0.192 239.352 ;
    END
  END x_qd[17]
  PIN x_qd[18]
    DIRECTION OUTPUT ;
    USE SIGNAL ;
    PORT
      LAYER M4 ;
        RECT 0.000 240.528 0.192 240.552 ;
    END
  END x_qd[18]
  PIN x_qd[19]
    DIRECTION OUTPUT ;
    USE SIGNAL ;
    PORT
      LAYER M4 ;
        RECT 0.000 241.728 0.192 241.752 ;
    END
  END x_qd[19]
  PIN x_qd[20]
    DIRECTION OUTPUT ;
    USE SIGNAL ;
    PORT
      LAYER M4 ;
        RECT 0.000 242.928 0.192 242.952 ;
    END
  END x_qd[20]
  PIN x_qd[21]
    DIRECTION OUTPUT ;
    USE SIGNAL ;
    PORT
      LAYER M4 ;
        RECT 0.000 244.128 0.192 244.152 ;
    END
  END x_qd[21]
  PIN x_qd[22]
    DIRECTION OUTPUT ;
    USE SIGNAL ;
    PORT
      LAYER M4 ;
        RECT 0.000 245.328 0.192 245.352 ;
    END
  END x_qd[22]
  PIN x_qd[23]
    DIRECTION OUTPUT ;
    USE SIGNAL ;
    PORT
      LAYER M4 ;
        RECT 0.000 246.528 0.192 246.552 ;
    END
  END x_qd[23]
  PIN x_qd[24]
    DIRECTION OUTPUT ;
    USE SIGNAL ;
    PORT
      LAYER M4 ;
        RECT 0.000 247.728 0.192 247.752 ;
    END
  END x_qd[24]
  PIN x_qd[25]
    DIRECTION OUTPUT ;
    USE SIGNAL ;
    PORT
      LAYER M4 ;
        RECT 0.000 248.928 0.192 248.952 ;
    END
  END x_qd[25]
  PIN x_qd[26]
    DIRECTION OUTPUT ;
    USE SIGNAL ;
    PORT
      LAYER M4 ;
        RECT 0.000 250.128 0.192 250.152 ;
    END
  END x_qd[26]
  PIN x_qd[27]
    DIRECTION OUTPUT ;
    USE SIGNAL ;
    PORT
      LAYER M4 ;
        RECT 0.000 251.328 0.192 251.352 ;
    END
  END x_qd[27]
  PIN x_qd[28]
    DIRECTION OUTPUT ;
    USE SIGNAL ;
    PORT
      LAYER M4 ;
        RECT 0.000 252.576 0.192 252.600 ;
    END
  END x_qd[28]
  PIN x_qd[29]
    DIRECTION OUTPUT ;
    USE SIGNAL ;
    PORT
      LAYER M4 ;
        RECT 0.000 253.776 0.192 253.800 ;
    END
  END x_qd[29]
  PIN x_qd[30]
    DIRECTION OUTPUT ;
    USE SIGNAL ;
    PORT
      LAYER M4 ;
        RECT 0.000 254.976 0.192 255.000 ;
    END
  END x_qd[30]
  PIN x_qd[31]
    DIRECTION OUTPUT ;
    USE SIGNAL ;
    PORT
      LAYER M4 ;
        RECT 0.000 256.176 0.192 256.200 ;
    END
  END x_qd[31]
  PIN x_qd[32]
    DIRECTION OUTPUT ;
    USE SIGNAL ;
    PORT
      LAYER M4 ;
        RECT 0.000 257.376 0.192 257.400 ;
    END
  END x_qd[32]
  PIN x_qd[33]
    DIRECTION OUTPUT ;
    USE SIGNAL ;
    PORT
      LAYER M4 ;
        RECT 0.000 258.576 0.192 258.600 ;
    END
  END x_qd[33]
  PIN x_qd[34]
    DIRECTION OUTPUT ;
    USE SIGNAL ;
    PORT
      LAYER M4 ;
        RECT 0.000 259.776 0.192 259.800 ;
    END
  END x_qd[34]
  PIN x_qd[35]
    DIRECTION OUTPUT ;
    USE SIGNAL ;
    PORT
      LAYER M4 ;
        RECT 0.000 260.976 0.192 261.000 ;
    END
  END x_qd[35]
  PIN x_qd[36]
    DIRECTION OUTPUT ;
    USE SIGNAL ;
    PORT
      LAYER M4 ;
        RECT 0.000 262.176 0.192 262.200 ;
    END
  END x_qd[36]
  PIN x_qd[37]
    DIRECTION OUTPUT ;
    USE SIGNAL ;
    PORT
      LAYER M4 ;
        RECT 0.000 263.376 0.192 263.400 ;
    END
  END x_qd[37]
  PIN x_qd[38]
    DIRECTION OUTPUT ;
    USE SIGNAL ;
    PORT
      LAYER M4 ;
        RECT 0.000 264.576 0.192 264.600 ;
    END
  END x_qd[38]
  PIN x_qd[39]
    DIRECTION OUTPUT ;
    USE SIGNAL ;
    PORT
      LAYER M4 ;
        RECT 0.000 265.776 0.192 265.800 ;
    END
  END x_qd[39]
  PIN x_qd[40]
    DIRECTION OUTPUT ;
    USE SIGNAL ;
    PORT
      LAYER M4 ;
        RECT 0.000 266.976 0.192 267.000 ;
    END
  END x_qd[40]
  PIN x_qd[41]
    DIRECTION OUTPUT ;
    USE SIGNAL ;
    PORT
      LAYER M4 ;
        RECT 0.000 268.176 0.192 268.200 ;
    END
  END x_qd[41]
  PIN x_qd[42]
    DIRECTION OUTPUT ;
    USE SIGNAL ;
    PORT
      LAYER M4 ;
        RECT 0.000 269.376 0.192 269.400 ;
    END
  END x_qd[42]
  PIN x_qd[43]
    DIRECTION OUTPUT ;
    USE SIGNAL ;
    PORT
      LAYER M4 ;
        RECT 0.000 270.576 0.192 270.600 ;
    END
  END x_qd[43]
  PIN x_qd[44]
    DIRECTION OUTPUT ;
    USE SIGNAL ;
    PORT
      LAYER M4 ;
        RECT 0.000 271.776 0.192 271.800 ;
    END
  END x_qd[44]
  PIN x_qd[45]
    DIRECTION OUTPUT ;
    USE SIGNAL ;
    PORT
      LAYER M4 ;
        RECT 0.000 272.976 0.192 273.000 ;
    END
  END x_qd[45]
  PIN x_qd[46]
    DIRECTION OUTPUT ;
    USE SIGNAL ;
    PORT
      LAYER M4 ;
        RECT 0.000 274.176 0.192 274.200 ;
    END
  END x_qd[46]
  PIN x_qd[47]
    DIRECTION OUTPUT ;
    USE SIGNAL ;
    PORT
      LAYER M4 ;
        RECT 0.000 275.376 0.192 275.400 ;
    END
  END x_qd[47]
  PIN x_qd[48]
    DIRECTION OUTPUT ;
    USE SIGNAL ;
    PORT
      LAYER M4 ;
        RECT 0.000 276.576 0.192 276.600 ;
    END
  END x_qd[48]
  PIN x_qd[49]
    DIRECTION OUTPUT ;
    USE SIGNAL ;
    PORT
      LAYER M4 ;
        RECT 0.000 277.776 0.192 277.800 ;
    END
  END x_qd[49]
  PIN x_qd[50]
    DIRECTION OUTPUT ;
    USE SIGNAL ;
    PORT
      LAYER M4 ;
        RECT 0.000 278.976 0.192 279.000 ;
    END
  END x_qd[50]
  PIN x_qd[51]
    DIRECTION OUTPUT ;
    USE SIGNAL ;
    PORT
      LAYER M4 ;
        RECT 0.000 280.176 0.192 280.200 ;
    END
  END x_qd[51]
  PIN x_qd[52]
    DIRECTION OUTPUT ;
    USE SIGNAL ;
    PORT
      LAYER M4 ;
        RECT 0.000 281.376 0.192 281.400 ;
    END
  END x_qd[52]
  PIN x_qd[53]
    DIRECTION OUTPUT ;
    USE SIGNAL ;
    PORT
      LAYER M4 ;
        RECT 0.000 282.576 0.192 282.600 ;
    END
  END x_qd[53]
  PIN x_qd[54]
    DIRECTION OUTPUT ;
    USE SIGNAL ;
    PORT
      LAYER M4 ;
        RECT 0.000 283.776 0.192 283.800 ;
    END
  END x_qd[54]
  PIN x_qd[55]
    DIRECTION OUTPUT ;
    USE SIGNAL ;
    PORT
      LAYER M4 ;
        RECT 0.000 284.976 0.192 285.000 ;
    END
  END x_qd[55]
  PIN x_qd[56]
    DIRECTION OUTPUT ;
    USE SIGNAL ;
    PORT
      LAYER M4 ;
        RECT 0.000 286.176 0.192 286.200 ;
    END
  END x_qd[56]
  PIN x_qd[57]
    DIRECTION OUTPUT ;
    USE SIGNAL ;
    PORT
      LAYER M4 ;
        RECT 0.000 287.376 0.192 287.400 ;
    END
  END x_qd[57]
  PIN x_qd[58]
    DIRECTION OUTPUT ;
    USE SIGNAL ;
    PORT
      LAYER M4 ;
        RECT 0.000 288.576 0.192 288.600 ;
    END
  END x_qd[58]
  PIN x_qd[59]
    DIRECTION OUTPUT ;
    USE SIGNAL ;
    PORT
      LAYER M4 ;
        RECT 0.000 289.776 0.192 289.800 ;
    END
  END x_qd[59]
  PIN x_qd[60]
    DIRECTION OUTPUT ;
    USE SIGNAL ;
    PORT
      LAYER M4 ;
        RECT 0.000 290.976 0.192 291.000 ;
    END
  END x_qd[60]
  PIN x_qd[61]
    DIRECTION OUTPUT ;
    USE SIGNAL ;
    PORT
      LAYER M4 ;
        RECT 0.000 292.176 0.192 292.200 ;
    END
  END x_qd[61]
  PIN x_qd[62]
    DIRECTION OUTPUT ;
    USE SIGNAL ;
    PORT
      LAYER M4 ;
        RECT 0.000 293.376 0.192 293.400 ;
    END
  END x_qd[62]
  PIN x_qd[63]
    DIRECTION OUTPUT ;
    USE SIGNAL ;
    PORT
      LAYER M4 ;
        RECT 0.000 294.576 0.192 294.600 ;
    END
  END x_qd[63]
  PIN x_qd[64]
    DIRECTION OUTPUT ;
    USE SIGNAL ;
    PORT
      LAYER M4 ;
        RECT 0.000 295.776 0.192 295.800 ;
    END
  END x_qd[64]
  PIN x_qd[65]
    DIRECTION OUTPUT ;
    USE SIGNAL ;
    PORT
      LAYER M4 ;
        RECT 0.000 296.976 0.192 297.000 ;
    END
  END x_qd[65]
  PIN x_qd[66]
    DIRECTION OUTPUT ;
    USE SIGNAL ;
    PORT
      LAYER M4 ;
        RECT 0.000 298.176 0.192 298.200 ;
    END
  END x_qd[66]
  PIN x_qd[67]
    DIRECTION OUTPUT ;
    USE SIGNAL ;
    PORT
      LAYER M4 ;
        RECT 0.000 299.376 0.192 299.400 ;
    END
  END x_qd[67]
  PIN x_qd[68]
    DIRECTION OUTPUT ;
    USE SIGNAL ;
    PORT
      LAYER M4 ;
        RECT 0.000 300.624 0.192 300.648 ;
    END
  END x_qd[68]
  PIN x_qd[69]
    DIRECTION OUTPUT ;
    USE SIGNAL ;
    PORT
      LAYER M4 ;
        RECT 0.000 301.824 0.192 301.848 ;
    END
  END x_qd[69]
  PIN x_qd[70]
    DIRECTION OUTPUT ;
    USE SIGNAL ;
    PORT
      LAYER M4 ;
        RECT 0.000 303.024 0.192 303.048 ;
    END
  END x_qd[70]
  PIN x_qd[71]
    DIRECTION OUTPUT ;
    USE SIGNAL ;
    PORT
      LAYER M4 ;
        RECT 0.000 304.224 0.192 304.248 ;
    END
  END x_qd[71]
  PIN x_qd[72]
    DIRECTION OUTPUT ;
    USE SIGNAL ;
    PORT
      LAYER M4 ;
        RECT 0.000 305.424 0.192 305.448 ;
    END
  END x_qd[72]
  PIN x_qd[73]
    DIRECTION OUTPUT ;
    USE SIGNAL ;
    PORT
      LAYER M4 ;
        RECT 0.000 306.624 0.192 306.648 ;
    END
  END x_qd[73]
  PIN x_qd[74]
    DIRECTION OUTPUT ;
    USE SIGNAL ;
    PORT
      LAYER M4 ;
        RECT 0.000 307.824 0.192 307.848 ;
    END
  END x_qd[74]
  PIN x_qd[75]
    DIRECTION OUTPUT ;
    USE SIGNAL ;
    PORT
      LAYER M4 ;
        RECT 0.000 309.024 0.192 309.048 ;
    END
  END x_qd[75]
  PIN x_qd[76]
    DIRECTION OUTPUT ;
    USE SIGNAL ;
    PORT
      LAYER M4 ;
        RECT 0.000 310.224 0.192 310.248 ;
    END
  END x_qd[76]
  PIN x_qd[77]
    DIRECTION OUTPUT ;
    USE SIGNAL ;
    PORT
      LAYER M4 ;
        RECT 0.000 311.424 0.192 311.448 ;
    END
  END x_qd[77]
  PIN x_qd[78]
    DIRECTION OUTPUT ;
    USE SIGNAL ;
    PORT
      LAYER M4 ;
        RECT 0.000 312.624 0.192 312.648 ;
    END
  END x_qd[78]
  PIN x_qd[79]
    DIRECTION OUTPUT ;
    USE SIGNAL ;
    PORT
      LAYER M4 ;
        RECT 0.000 313.824 0.192 313.848 ;
    END
  END x_qd[79]
  PIN x_qd[80]
    DIRECTION OUTPUT ;
    USE SIGNAL ;
    PORT
      LAYER M4 ;
        RECT 0.000 315.024 0.192 315.048 ;
    END
  END x_qd[80]
  PIN x_qd[81]
    DIRECTION OUTPUT ;
    USE SIGNAL ;
    PORT
      LAYER M4 ;
        RECT 0.000 316.224 0.192 316.248 ;
    END
  END x_qd[81]
  PIN x_qd[82]
    DIRECTION OUTPUT ;
    USE SIGNAL ;
    PORT
      LAYER M4 ;
        RECT 0.000 317.424 0.192 317.448 ;
    END
  END x_qd[82]
  PIN x_qd[83]
    DIRECTION OUTPUT ;
    USE SIGNAL ;
    PORT
      LAYER M4 ;
        RECT 0.000 318.624 0.192 318.648 ;
    END
  END x_qd[83]
  PIN x_qd[84]
    DIRECTION OUTPUT ;
    USE SIGNAL ;
    PORT
      LAYER M4 ;
        RECT 0.000 319.824 0.192 319.848 ;
    END
  END x_qd[84]
  PIN x_qd[85]
    DIRECTION OUTPUT ;
    USE SIGNAL ;
    PORT
      LAYER M4 ;
        RECT 0.000 321.024 0.192 321.048 ;
    END
  END x_qd[85]
  PIN x_qd[86]
    DIRECTION OUTPUT ;
    USE SIGNAL ;
    PORT
      LAYER M4 ;
        RECT 0.000 322.224 0.192 322.248 ;
    END
  END x_qd[86]
  PIN x_qd[87]
    DIRECTION OUTPUT ;
    USE SIGNAL ;
    PORT
      LAYER M4 ;
        RECT 0.000 323.424 0.192 323.448 ;
    END
  END x_qd[87]
  PIN x_qd[88]
    DIRECTION OUTPUT ;
    USE SIGNAL ;
    PORT
      LAYER M4 ;
        RECT 0.000 324.624 0.192 324.648 ;
    END
  END x_qd[88]
  PIN x_qd[89]
    DIRECTION OUTPUT ;
    USE SIGNAL ;
    PORT
      LAYER M4 ;
        RECT 0.000 325.824 0.192 325.848 ;
    END
  END x_qd[89]
  PIN x_qd[90]
    DIRECTION OUTPUT ;
    USE SIGNAL ;
    PORT
      LAYER M4 ;
        RECT 0.000 327.024 0.192 327.048 ;
    END
  END x_qd[90]
  PIN x_qd[91]
    DIRECTION OUTPUT ;
    USE SIGNAL ;
    PORT
      LAYER M4 ;
        RECT 0.000 328.224 0.192 328.248 ;
    END
  END x_qd[91]
  PIN x_qd[92]
    DIRECTION OUTPUT ;
    USE SIGNAL ;
    PORT
      LAYER M4 ;
        RECT 0.000 329.424 0.192 329.448 ;
    END
  END x_qd[92]
  PIN x_qd[93]
    DIRECTION OUTPUT ;
    USE SIGNAL ;
    PORT
      LAYER M4 ;
        RECT 0.000 330.624 0.192 330.648 ;
    END
  END x_qd[93]
  PIN x_qd[94]
    DIRECTION OUTPUT ;
    USE SIGNAL ;
    PORT
      LAYER M4 ;
        RECT 0.000 331.824 0.192 331.848 ;
    END
  END x_qd[94]
  PIN x_qd[95]
    DIRECTION OUTPUT ;
    USE SIGNAL ;
    PORT
      LAYER M4 ;
        RECT 0.000 333.024 0.192 333.048 ;
    END
  END x_qd[95]
  PIN x_qd[96]
    DIRECTION OUTPUT ;
    USE SIGNAL ;
    PORT
      LAYER M4 ;
        RECT 0.000 334.224 0.192 334.248 ;
    END
  END x_qd[96]
  PIN x_qd[97]
    DIRECTION OUTPUT ;
    USE SIGNAL ;
    PORT
      LAYER M4 ;
        RECT 0.000 335.424 0.192 335.448 ;
    END
  END x_qd[97]
  PIN x_qd[98]
    DIRECTION OUTPUT ;
    USE SIGNAL ;
    PORT
      LAYER M4 ;
        RECT 0.000 336.624 0.192 336.648 ;
    END
  END x_qd[98]
  PIN x_qd[99]
    DIRECTION OUTPUT ;
    USE SIGNAL ;
    PORT
      LAYER M4 ;
        RECT 0.000 337.824 0.192 337.848 ;
    END
  END x_qd[99]
  PIN x_qd[100]
    DIRECTION OUTPUT ;
    USE SIGNAL ;
    PORT
      LAYER M4 ;
        RECT 0.000 339.024 0.192 339.048 ;
    END
  END x_qd[100]
  PIN x_qd[101]
    DIRECTION OUTPUT ;
    USE SIGNAL ;
    PORT
      LAYER M4 ;
        RECT 0.000 340.224 0.192 340.248 ;
    END
  END x_qd[101]
  PIN x_qd[102]
    DIRECTION OUTPUT ;
    USE SIGNAL ;
    PORT
      LAYER M4 ;
        RECT 0.000 341.424 0.192 341.448 ;
    END
  END x_qd[102]
  PIN x_qd[103]
    DIRECTION OUTPUT ;
    USE SIGNAL ;
    PORT
      LAYER M4 ;
        RECT 0.000 342.624 0.192 342.648 ;
    END
  END x_qd[103]
  PIN x_qd[104]
    DIRECTION OUTPUT ;
    USE SIGNAL ;
    PORT
      LAYER M4 ;
        RECT 0.000 343.824 0.192 343.848 ;
    END
  END x_qd[104]
  PIN x_qd[105]
    DIRECTION OUTPUT ;
    USE SIGNAL ;
    PORT
      LAYER M4 ;
        RECT 0.000 345.024 0.192 345.048 ;
    END
  END x_qd[105]
  PIN x_qd[106]
    DIRECTION OUTPUT ;
    USE SIGNAL ;
    PORT
      LAYER M4 ;
        RECT 0.000 346.224 0.192 346.248 ;
    END
  END x_qd[106]
  PIN x_qd[107]
    DIRECTION OUTPUT ;
    USE SIGNAL ;
    PORT
      LAYER M4 ;
        RECT 0.000 347.472 0.192 347.496 ;
    END
  END x_qd[107]
  PIN x_qd[108]
    DIRECTION OUTPUT ;
    USE SIGNAL ;
    PORT
      LAYER M4 ;
        RECT 0.000 348.672 0.192 348.696 ;
    END
  END x_qd[108]
  PIN x_qd[109]
    DIRECTION OUTPUT ;
    USE SIGNAL ;
    PORT
      LAYER M4 ;
        RECT 0.000 349.872 0.192 349.896 ;
    END
  END x_qd[109]
  PIN x_qd[110]
    DIRECTION OUTPUT ;
    USE SIGNAL ;
    PORT
      LAYER M4 ;
        RECT 0.000 351.072 0.192 351.096 ;
    END
  END x_qd[110]
  PIN x_qd[111]
    DIRECTION OUTPUT ;
    USE SIGNAL ;
    PORT
      LAYER M4 ;
        RECT 0.000 352.272 0.192 352.296 ;
    END
  END x_qd[111]
  PIN x_qd[112]
    DIRECTION OUTPUT ;
    USE SIGNAL ;
    PORT
      LAYER M4 ;
        RECT 0.000 353.472 0.192 353.496 ;
    END
  END x_qd[112]
  PIN x_qd[113]
    DIRECTION OUTPUT ;
    USE SIGNAL ;
    PORT
      LAYER M4 ;
        RECT 0.000 354.672 0.192 354.696 ;
    END
  END x_qd[113]
  PIN x_qd[114]
    DIRECTION OUTPUT ;
    USE SIGNAL ;
    PORT
      LAYER M4 ;
        RECT 0.000 355.872 0.192 355.896 ;
    END
  END x_qd[114]
  PIN x_qd[115]
    DIRECTION OUTPUT ;
    USE SIGNAL ;
    PORT
      LAYER M4 ;
        RECT 0.000 357.072 0.192 357.096 ;
    END
  END x_qd[115]
  PIN x_qd[116]
    DIRECTION OUTPUT ;
    USE SIGNAL ;
    PORT
      LAYER M4 ;
        RECT 0.000 358.272 0.192 358.296 ;
    END
  END x_qd[116]
  PIN x_qd[117]
    DIRECTION OUTPUT ;
    USE SIGNAL ;
    PORT
      LAYER M4 ;
        RECT 0.000 359.472 0.192 359.496 ;
    END
  END x_qd[117]
  PIN x_qd[118]
    DIRECTION OUTPUT ;
    USE SIGNAL ;
    PORT
      LAYER M4 ;
        RECT 0.000 360.672 0.192 360.696 ;
    END
  END x_qd[118]
  PIN x_qd[119]
    DIRECTION OUTPUT ;
    USE SIGNAL ;
    PORT
      LAYER M4 ;
        RECT 0.000 361.872 0.192 361.896 ;
    END
  END x_qd[119]
  PIN x_qd[120]
    DIRECTION OUTPUT ;
    USE SIGNAL ;
    PORT
      LAYER M4 ;
        RECT 0.000 363.072 0.192 363.096 ;
    END
  END x_qd[120]
  PIN x_qd[121]
    DIRECTION OUTPUT ;
    USE SIGNAL ;
    PORT
      LAYER M4 ;
        RECT 0.000 364.272 0.192 364.296 ;
    END
  END x_qd[121]
  PIN x_qd[122]
    DIRECTION OUTPUT ;
    USE SIGNAL ;
    PORT
      LAYER M4 ;
        RECT 0.000 365.472 0.192 365.496 ;
    END
  END x_qd[122]
  PIN x_qd[123]
    DIRECTION OUTPUT ;
    USE SIGNAL ;
    PORT
      LAYER M4 ;
        RECT 0.000 366.672 0.192 366.696 ;
    END
  END x_qd[123]
  PIN x_qd[124]
    DIRECTION OUTPUT ;
    USE SIGNAL ;
    PORT
      LAYER M4 ;
        RECT 0.000 367.872 0.192 367.896 ;
    END
  END x_qd[124]
  PIN x_qd[125]
    DIRECTION OUTPUT ;
    USE SIGNAL ;
    PORT
      LAYER M4 ;
        RECT 0.000 369.072 0.192 369.096 ;
    END
  END x_qd[125]
  PIN x_qd[126]
    DIRECTION OUTPUT ;
    USE SIGNAL ;
    PORT
      LAYER M4 ;
        RECT 0.000 370.272 0.192 370.296 ;
    END
  END x_qd[126]
  PIN x_qd[127]
    DIRECTION OUTPUT ;
    USE SIGNAL ;
    PORT
      LAYER M4 ;
        RECT 0.000 371.472 0.192 371.496 ;
    END
  END x_qd[127]
  PIN x_qd[128]
    DIRECTION OUTPUT ;
    USE SIGNAL ;
    PORT
      LAYER M4 ;
        RECT 0.000 372.672 0.192 372.696 ;
    END
  END x_qd[128]
  PIN x_qd[129]
    DIRECTION OUTPUT ;
    USE SIGNAL ;
    PORT
      LAYER M4 ;
        RECT 0.000 373.872 0.192 373.896 ;
    END
  END x_qd[129]
  PIN x_qd[130]
    DIRECTION OUTPUT ;
    USE SIGNAL ;
    PORT
      LAYER M4 ;
        RECT 0.000 375.072 0.192 375.096 ;
    END
  END x_qd[130]
  PIN x_qd[131]
    DIRECTION OUTPUT ;
    USE SIGNAL ;
    PORT
      LAYER M4 ;
        RECT 0.000 376.272 0.192 376.296 ;
    END
  END x_qd[131]
  PIN x_qd[132]
    DIRECTION OUTPUT ;
    USE SIGNAL ;
    PORT
      LAYER M4 ;
        RECT 0.000 377.472 0.192 377.496 ;
    END
  END x_qd[132]
  PIN x_qd[133]
    DIRECTION OUTPUT ;
    USE SIGNAL ;
    PORT
      LAYER M4 ;
        RECT 0.000 378.672 0.192 378.696 ;
    END
  END x_qd[133]
  PIN x_qd[134]
    DIRECTION OUTPUT ;
    USE SIGNAL ;
    PORT
      LAYER M4 ;
        RECT 0.000 379.872 0.192 379.896 ;
    END
  END x_qd[134]
  PIN x_qd[135]
    DIRECTION OUTPUT ;
    USE SIGNAL ;
    PORT
      LAYER M4 ;
        RECT 0.000 381.072 0.192 381.096 ;
    END
  END x_qd[135]
  PIN x_qd[136]
    DIRECTION OUTPUT ;
    USE SIGNAL ;
    PORT
      LAYER M4 ;
        RECT 0.000 382.272 0.192 382.296 ;
    END
  END x_qd[136]
  PIN x_qd[137]
    DIRECTION OUTPUT ;
    USE SIGNAL ;
    PORT
      LAYER M4 ;
        RECT 0.000 383.472 0.192 383.496 ;
    END
  END x_qd[137]
  PIN x_qd[138]
    DIRECTION OUTPUT ;
    USE SIGNAL ;
    PORT
      LAYER M4 ;
        RECT 0.000 384.672 0.192 384.696 ;
    END
  END x_qd[138]
  PIN x_qd[139]
    DIRECTION OUTPUT ;
    USE SIGNAL ;
    PORT
      LAYER M4 ;
        RECT 0.000 385.872 0.192 385.896 ;
    END
  END x_qd[139]
  PIN x_qd[140]
    DIRECTION OUTPUT ;
    USE SIGNAL ;
    PORT
      LAYER M4 ;
        RECT 0.000 387.072 0.192 387.096 ;
    END
  END x_qd[140]
  PIN x_qd[141]
    DIRECTION OUTPUT ;
    USE SIGNAL ;
    PORT
      LAYER M4 ;
        RECT 0.000 388.272 0.192 388.296 ;
    END
  END x_qd[141]
  PIN x_qd[142]
    DIRECTION OUTPUT ;
    USE SIGNAL ;
    PORT
      LAYER M4 ;
        RECT 0.000 389.472 0.192 389.496 ;
    END
  END x_qd[142]
  PIN x_qd[143]
    DIRECTION OUTPUT ;
    USE SIGNAL ;
    PORT
      LAYER M4 ;
        RECT 0.000 390.672 0.192 390.696 ;
    END
  END x_qd[143]
  PIN x_qd[144]
    DIRECTION OUTPUT ;
    USE SIGNAL ;
    PORT
      LAYER M4 ;
        RECT 0.000 391.872 0.192 391.896 ;
    END
  END x_qd[144]
  PIN x_qd[145]
    DIRECTION OUTPUT ;
    USE SIGNAL ;
    PORT
      LAYER M4 ;
        RECT 0.000 393.072 0.192 393.096 ;
    END
  END x_qd[145]
  PIN x_qd[146]
    DIRECTION OUTPUT ;
    USE SIGNAL ;
    PORT
      LAYER M4 ;
        RECT 0.000 394.272 0.192 394.296 ;
    END
  END x_qd[146]
  PIN x_qd[147]
    DIRECTION OUTPUT ;
    USE SIGNAL ;
    PORT
      LAYER M4 ;
        RECT 0.000 395.520 0.192 395.544 ;
    END
  END x_qd[147]
  PIN x_qd[148]
    DIRECTION OUTPUT ;
    USE SIGNAL ;
    PORT
      LAYER M4 ;
        RECT 0.000 396.720 0.192 396.744 ;
    END
  END x_qd[148]
  PIN x_qd[149]
    DIRECTION OUTPUT ;
    USE SIGNAL ;
    PORT
      LAYER M4 ;
        RECT 0.000 397.920 0.192 397.944 ;
    END
  END x_qd[149]
  PIN x_qd[150]
    DIRECTION OUTPUT ;
    USE SIGNAL ;
    PORT
      LAYER M4 ;
        RECT 0.000 399.120 0.192 399.144 ;
    END
  END x_qd[150]
  PIN x_qd[151]
    DIRECTION OUTPUT ;
    USE SIGNAL ;
    PORT
      LAYER M4 ;
        RECT 0.000 400.320 0.192 400.344 ;
    END
  END x_qd[151]
  PIN x_qd[152]
    DIRECTION OUTPUT ;
    USE SIGNAL ;
    PORT
      LAYER M4 ;
        RECT 0.000 401.520 0.192 401.544 ;
    END
  END x_qd[152]
  PIN x_qd[153]
    DIRECTION OUTPUT ;
    USE SIGNAL ;
    PORT
      LAYER M4 ;
        RECT 0.000 402.720 0.192 402.744 ;
    END
  END x_qd[153]
  PIN x_qd[154]
    DIRECTION OUTPUT ;
    USE SIGNAL ;
    PORT
      LAYER M4 ;
        RECT 0.000 403.920 0.192 403.944 ;
    END
  END x_qd[154]
  PIN x_qd[155]
    DIRECTION OUTPUT ;
    USE SIGNAL ;
    PORT
      LAYER M4 ;
        RECT 0.000 405.120 0.192 405.144 ;
    END
  END x_qd[155]
  PIN x_qd[156]
    DIRECTION OUTPUT ;
    USE SIGNAL ;
    PORT
      LAYER M4 ;
        RECT 0.000 406.320 0.192 406.344 ;
    END
  END x_qd[156]
  PIN x_qd[157]
    DIRECTION OUTPUT ;
    USE SIGNAL ;
    PORT
      LAYER M4 ;
        RECT 0.000 407.520 0.192 407.544 ;
    END
  END x_qd[157]
  PIN x_qd[158]
    DIRECTION OUTPUT ;
    USE SIGNAL ;
    PORT
      LAYER M4 ;
        RECT 0.000 408.720 0.192 408.744 ;
    END
  END x_qd[158]
  PIN x_qd[159]
    DIRECTION OUTPUT ;
    USE SIGNAL ;
    PORT
      LAYER M4 ;
        RECT 0.000 409.920 0.192 409.944 ;
    END
  END x_qd[159]
  PIN x_qd[160]
    DIRECTION OUTPUT ;
    USE SIGNAL ;
    PORT
      LAYER M4 ;
        RECT 0.000 411.120 0.192 411.144 ;
    END
  END x_qd[160]
  PIN x_qd[161]
    DIRECTION OUTPUT ;
    USE SIGNAL ;
    PORT
      LAYER M4 ;
        RECT 0.000 412.320 0.192 412.344 ;
    END
  END x_qd[161]
  PIN x_qd[162]
    DIRECTION OUTPUT ;
    USE SIGNAL ;
    PORT
      LAYER M4 ;
        RECT 0.000 413.520 0.192 413.544 ;
    END
  END x_qd[162]
  PIN x_qd[163]
    DIRECTION OUTPUT ;
    USE SIGNAL ;
    PORT
      LAYER M4 ;
        RECT 0.000 414.720 0.192 414.744 ;
    END
  END x_qd[163]
  PIN x_qd[164]
    DIRECTION OUTPUT ;
    USE SIGNAL ;
    PORT
      LAYER M4 ;
        RECT 0.000 415.920 0.192 415.944 ;
    END
  END x_qd[164]
  PIN x_qd[165]
    DIRECTION OUTPUT ;
    USE SIGNAL ;
    PORT
      LAYER M4 ;
        RECT 0.000 417.120 0.192 417.144 ;
    END
  END x_qd[165]
  PIN x_qd[166]
    DIRECTION OUTPUT ;
    USE SIGNAL ;
    PORT
      LAYER M4 ;
        RECT 0.000 418.320 0.192 418.344 ;
    END
  END x_qd[166]
  PIN x_qd[167]
    DIRECTION OUTPUT ;
    USE SIGNAL ;
    PORT
      LAYER M4 ;
        RECT 0.000 419.520 0.192 419.544 ;
    END
  END x_qd[167]
  PIN x_qd[168]
    DIRECTION OUTPUT ;
    USE SIGNAL ;
    PORT
      LAYER M4 ;
        RECT 0.000 420.720 0.192 420.744 ;
    END
  END x_qd[168]
  PIN x_qd[169]
    DIRECTION OUTPUT ;
    USE SIGNAL ;
    PORT
      LAYER M4 ;
        RECT 0.000 421.920 0.192 421.944 ;
    END
  END x_qd[169]
  PIN x_qd[170]
    DIRECTION OUTPUT ;
    USE SIGNAL ;
    PORT
      LAYER M4 ;
        RECT 0.000 423.120 0.192 423.144 ;
    END
  END x_qd[170]
  PIN x_qd[171]
    DIRECTION OUTPUT ;
    USE SIGNAL ;
    PORT
      LAYER M4 ;
        RECT 0.000 424.320 0.192 424.344 ;
    END
  END x_qd[171]
  PIN x_qd[172]
    DIRECTION OUTPUT ;
    USE SIGNAL ;
    PORT
      LAYER M4 ;
        RECT 0.000 425.520 0.192 425.544 ;
    END
  END x_qd[172]
  PIN x_qd[173]
    DIRECTION OUTPUT ;
    USE SIGNAL ;
    PORT
      LAYER M4 ;
        RECT 0.000 426.720 0.192 426.744 ;
    END
  END x_qd[173]
  PIN x_qd[174]
    DIRECTION OUTPUT ;
    USE SIGNAL ;
    PORT
      LAYER M4 ;
        RECT 0.000 427.920 0.192 427.944 ;
    END
  END x_qd[174]
  PIN x_qd[175]
    DIRECTION OUTPUT ;
    USE SIGNAL ;
    PORT
      LAYER M4 ;
        RECT 0.000 429.120 0.192 429.144 ;
    END
  END x_qd[175]
  PIN x_qd[176]
    DIRECTION OUTPUT ;
    USE SIGNAL ;
    PORT
      LAYER M4 ;
        RECT 0.000 430.320 0.192 430.344 ;
    END
  END x_qd[176]
  PIN x_qd[177]
    DIRECTION OUTPUT ;
    USE SIGNAL ;
    PORT
      LAYER M4 ;
        RECT 0.000 431.520 0.192 431.544 ;
    END
  END x_qd[177]
  PIN x_qd[178]
    DIRECTION OUTPUT ;
    USE SIGNAL ;
    PORT
      LAYER M4 ;
        RECT 0.000 432.720 0.192 432.744 ;
    END
  END x_qd[178]
  PIN x_qd[179]
    DIRECTION OUTPUT ;
    USE SIGNAL ;
    PORT
      LAYER M4 ;
        RECT 0.000 433.920 0.192 433.944 ;
    END
  END x_qd[179]
  PIN x_qd[180]
    DIRECTION OUTPUT ;
    USE SIGNAL ;
    PORT
      LAYER M4 ;
        RECT 0.000 435.120 0.192 435.144 ;
    END
  END x_qd[180]
  PIN x_qd[181]
    DIRECTION OUTPUT ;
    USE SIGNAL ;
    PORT
      LAYER M4 ;
        RECT 0.000 436.320 0.192 436.344 ;
    END
  END x_qd[181]
  PIN x_qd[182]
    DIRECTION OUTPUT ;
    USE SIGNAL ;
    PORT
      LAYER M4 ;
        RECT 0.000 437.520 0.192 437.544 ;
    END
  END x_qd[182]
  PIN x_qd[183]
    DIRECTION OUTPUT ;
    USE SIGNAL ;
    PORT
      LAYER M4 ;
        RECT 0.000 438.720 0.192 438.744 ;
    END
  END x_qd[183]
  PIN x_qd[184]
    DIRECTION OUTPUT ;
    USE SIGNAL ;
    PORT
      LAYER M4 ;
        RECT 0.000 439.920 0.192 439.944 ;
    END
  END x_qd[184]
  PIN x_qd[185]
    DIRECTION OUTPUT ;
    USE SIGNAL ;
    PORT
      LAYER M4 ;
        RECT 0.000 441.120 0.192 441.144 ;
    END
  END x_qd[185]
  PIN x_qd[186]
    DIRECTION OUTPUT ;
    USE SIGNAL ;
    PORT
      LAYER M4 ;
        RECT 0.000 442.320 0.192 442.344 ;
    END
  END x_qd[186]
  PIN x_qd[187]
    DIRECTION OUTPUT ;
    USE SIGNAL ;
    PORT
      LAYER M4 ;
        RECT 0.000 443.568 0.192 443.592 ;
    END
  END x_qd[187]
  PIN x_qd[188]
    DIRECTION OUTPUT ;
    USE SIGNAL ;
    PORT
      LAYER M4 ;
        RECT 0.000 444.768 0.192 444.792 ;
    END
  END x_qd[188]
  PIN x_qd[189]
    DIRECTION OUTPUT ;
    USE SIGNAL ;
    PORT
      LAYER M4 ;
        RECT 0.000 445.968 0.192 445.992 ;
    END
  END x_qd[189]
  PIN x_qd[190]
    DIRECTION OUTPUT ;
    USE SIGNAL ;
    PORT
      LAYER M4 ;
        RECT 0.000 447.168 0.192 447.192 ;
    END
  END x_qd[190]
  PIN x_qd[191]
    DIRECTION OUTPUT ;
    USE SIGNAL ;
    PORT
      LAYER M4 ;
        RECT 0.000 448.368 0.192 448.392 ;
    END
  END x_qd[191]
  PIN x_qd[192]
    DIRECTION OUTPUT ;
    USE SIGNAL ;
    PORT
      LAYER M4 ;
        RECT 0.000 449.568 0.192 449.592 ;
    END
  END x_qd[192]
  PIN x_qd[193]
    DIRECTION OUTPUT ;
    USE SIGNAL ;
    PORT
      LAYER M4 ;
        RECT 0.000 450.768 0.192 450.792 ;
    END
  END x_qd[193]
  PIN x_qd[194]
    DIRECTION OUTPUT ;
    USE SIGNAL ;
    PORT
      LAYER M4 ;
        RECT 0.000 451.968 0.192 451.992 ;
    END
  END x_qd[194]
  PIN x_qd[195]
    DIRECTION OUTPUT ;
    USE SIGNAL ;
    PORT
      LAYER M4 ;
        RECT 0.000 453.168 0.192 453.192 ;
    END
  END x_qd[195]
  PIN x_qd[196]
    DIRECTION OUTPUT ;
    USE SIGNAL ;
    PORT
      LAYER M4 ;
        RECT 0.000 454.368 0.192 454.392 ;
    END
  END x_qd[196]
  PIN x_qd[197]
    DIRECTION OUTPUT ;
    USE SIGNAL ;
    PORT
      LAYER M4 ;
        RECT 0.000 455.568 0.192 455.592 ;
    END
  END x_qd[197]
  PIN x_qd[198]
    DIRECTION OUTPUT ;
    USE SIGNAL ;
    PORT
      LAYER M4 ;
        RECT 0.000 456.768 0.192 456.792 ;
    END
  END x_qd[198]
  PIN x_qd[199]
    DIRECTION OUTPUT ;
    USE SIGNAL ;
    PORT
      LAYER M4 ;
        RECT 0.000 457.968 0.192 457.992 ;
    END
  END x_qd[199]
  PIN x_qd[200]
    DIRECTION OUTPUT ;
    USE SIGNAL ;
    PORT
      LAYER M4 ;
        RECT 0.000 459.168 0.192 459.192 ;
    END
  END x_qd[200]
  PIN x_qd[201]
    DIRECTION OUTPUT ;
    USE SIGNAL ;
    PORT
      LAYER M4 ;
        RECT 0.000 460.368 0.192 460.392 ;
    END
  END x_qd[201]
  PIN x_qd[202]
    DIRECTION OUTPUT ;
    USE SIGNAL ;
    PORT
      LAYER M4 ;
        RECT 0.000 461.568 0.192 461.592 ;
    END
  END x_qd[202]
  PIN x_qd[203]
    DIRECTION OUTPUT ;
    USE SIGNAL ;
    PORT
      LAYER M4 ;
        RECT 0.000 462.768 0.192 462.792 ;
    END
  END x_qd[203]
  PIN x_qd[204]
    DIRECTION OUTPUT ;
    USE SIGNAL ;
    PORT
      LAYER M4 ;
        RECT 0.000 463.968 0.192 463.992 ;
    END
  END x_qd[204]
  PIN x_qd[205]
    DIRECTION OUTPUT ;
    USE SIGNAL ;
    PORT
      LAYER M4 ;
        RECT 0.000 465.168 0.192 465.192 ;
    END
  END x_qd[205]
  PIN x_qd[206]
    DIRECTION OUTPUT ;
    USE SIGNAL ;
    PORT
      LAYER M4 ;
        RECT 0.000 466.368 0.192 466.392 ;
    END
  END x_qd[206]
  PIN x_qd[207]
    DIRECTION OUTPUT ;
    USE SIGNAL ;
    PORT
      LAYER M4 ;
        RECT 0.000 467.568 0.192 467.592 ;
    END
  END x_qd[207]
  PIN x_qd[208]
    DIRECTION OUTPUT ;
    USE SIGNAL ;
    PORT
      LAYER M4 ;
        RECT 0.000 468.768 0.192 468.792 ;
    END
  END x_qd[208]
  PIN x_qd[209]
    DIRECTION OUTPUT ;
    USE SIGNAL ;
    PORT
      LAYER M4 ;
        RECT 0.000 469.968 0.192 469.992 ;
    END
  END x_qd[209]
  PIN x_qd[210]
    DIRECTION OUTPUT ;
    USE SIGNAL ;
    PORT
      LAYER M4 ;
        RECT 0.000 471.168 0.192 471.192 ;
    END
  END x_qd[210]
  PIN x_qd[211]
    DIRECTION OUTPUT ;
    USE SIGNAL ;
    PORT
      LAYER M4 ;
        RECT 0.000 472.368 0.192 472.392 ;
    END
  END x_qd[211]
  PIN x_qd[212]
    DIRECTION OUTPUT ;
    USE SIGNAL ;
    PORT
      LAYER M4 ;
        RECT 0.000 473.568 0.192 473.592 ;
    END
  END x_qd[212]
  PIN x_qd[213]
    DIRECTION OUTPUT ;
    USE SIGNAL ;
    PORT
      LAYER M4 ;
        RECT 0.000 474.768 0.192 474.792 ;
    END
  END x_qd[213]
  PIN x_qd[214]
    DIRECTION OUTPUT ;
    USE SIGNAL ;
    PORT
      LAYER M4 ;
        RECT 0.000 475.968 0.192 475.992 ;
    END
  END x_qd[214]
  PIN x_qd[215]
    DIRECTION OUTPUT ;
    USE SIGNAL ;
    PORT
      LAYER M4 ;
        RECT 0.000 477.168 0.192 477.192 ;
    END
  END x_qd[215]
  PIN x_qd[216]
    DIRECTION OUTPUT ;
    USE SIGNAL ;
    PORT
      LAYER M4 ;
        RECT 0.000 478.368 0.192 478.392 ;
    END
  END x_qd[216]
  PIN x_qd[217]
    DIRECTION OUTPUT ;
    USE SIGNAL ;
    PORT
      LAYER M4 ;
        RECT 0.000 479.568 0.192 479.592 ;
    END
  END x_qd[217]
  PIN x_qd[218]
    DIRECTION OUTPUT ;
    USE SIGNAL ;
    PORT
      LAYER M4 ;
        RECT 0.000 480.768 0.192 480.792 ;
    END
  END x_qd[218]
  PIN x_qd[219]
    DIRECTION OUTPUT ;
    USE SIGNAL ;
    PORT
      LAYER M4 ;
        RECT 0.000 481.968 0.192 481.992 ;
    END
  END x_qd[219]
  PIN x_qd[220]
    DIRECTION OUTPUT ;
    USE SIGNAL ;
    PORT
      LAYER M4 ;
        RECT 0.000 483.168 0.192 483.192 ;
    END
  END x_qd[220]
  PIN x_qd[221]
    DIRECTION OUTPUT ;
    USE SIGNAL ;
    PORT
      LAYER M4 ;
        RECT 0.000 484.368 0.192 484.392 ;
    END
  END x_qd[221]
  PIN x_qd[222]
    DIRECTION OUTPUT ;
    USE SIGNAL ;
    PORT
      LAYER M4 ;
        RECT 0.000 485.568 0.192 485.592 ;
    END
  END x_qd[222]
  PIN x_qd[223]
    DIRECTION OUTPUT ;
    USE SIGNAL ;
    PORT
      LAYER M4 ;
        RECT 0.000 486.768 0.192 486.792 ;
    END
  END x_qd[223]
  PIN x_qd[224]
    DIRECTION OUTPUT ;
    USE SIGNAL ;
    PORT
      LAYER M4 ;
        RECT 0.000 487.968 0.192 487.992 ;
    END
  END x_qd[224]
  PIN x_qd[225]
    DIRECTION OUTPUT ;
    USE SIGNAL ;
    PORT
      LAYER M4 ;
        RECT 0.000 489.168 0.192 489.192 ;
    END
  END x_qd[225]
  PIN x_qd[226]
    DIRECTION OUTPUT ;
    USE SIGNAL ;
    PORT
      LAYER M4 ;
        RECT 0.000 490.416 0.192 490.440 ;
    END
  END x_qd[226]
  PIN x_qd[227]
    DIRECTION OUTPUT ;
    USE SIGNAL ;
    PORT
      LAYER M4 ;
        RECT 0.000 491.616 0.192 491.640 ;
    END
  END x_qd[227]
  PIN x_qd[228]
    DIRECTION OUTPUT ;
    USE SIGNAL ;
    PORT
      LAYER M4 ;
        RECT 0.000 492.816 0.192 492.840 ;
    END
  END x_qd[228]
  PIN x_qd[229]
    DIRECTION OUTPUT ;
    USE SIGNAL ;
    PORT
      LAYER M4 ;
        RECT 0.000 494.016 0.192 494.040 ;
    END
  END x_qd[229]
  PIN x_qd[230]
    DIRECTION OUTPUT ;
    USE SIGNAL ;
    PORT
      LAYER M4 ;
        RECT 0.000 495.216 0.192 495.240 ;
    END
  END x_qd[230]
  PIN x_qd[231]
    DIRECTION OUTPUT ;
    USE SIGNAL ;
    PORT
      LAYER M4 ;
        RECT 0.000 496.416 0.192 496.440 ;
    END
  END x_qd[231]
  PIN x_qd[232]
    DIRECTION OUTPUT ;
    USE SIGNAL ;
    PORT
      LAYER M4 ;
        RECT 0.000 497.616 0.192 497.640 ;
    END
  END x_qd[232]
  PIN x_qd[233]
    DIRECTION OUTPUT ;
    USE SIGNAL ;
    PORT
      LAYER M4 ;
        RECT 0.000 498.816 0.192 498.840 ;
    END
  END x_qd[233]
  PIN x_qd[234]
    DIRECTION OUTPUT ;
    USE SIGNAL ;
    PORT
      LAYER M4 ;
        RECT 0.000 500.016 0.192 500.040 ;
    END
  END x_qd[234]
  PIN x_qd[235]
    DIRECTION OUTPUT ;
    USE SIGNAL ;
    PORT
      LAYER M4 ;
        RECT 0.000 501.216 0.192 501.240 ;
    END
  END x_qd[235]
  PIN x_qd[236]
    DIRECTION OUTPUT ;
    USE SIGNAL ;
    PORT
      LAYER M4 ;
        RECT 0.000 502.416 0.192 502.440 ;
    END
  END x_qd[236]
  PIN x_qd[237]
    DIRECTION OUTPUT ;
    USE SIGNAL ;
    PORT
      LAYER M4 ;
        RECT 0.000 503.616 0.192 503.640 ;
    END
  END x_qd[237]
  PIN x_qd[238]
    DIRECTION OUTPUT ;
    USE SIGNAL ;
    PORT
      LAYER M4 ;
        RECT 0.000 504.816 0.192 504.840 ;
    END
  END x_qd[238]
  PIN x_qd[239]
    DIRECTION OUTPUT ;
    USE SIGNAL ;
    PORT
      LAYER M4 ;
        RECT 0.000 506.016 0.192 506.040 ;
    END
  END x_qd[239]
  PIN x_qd[240]
    DIRECTION OUTPUT ;
    USE SIGNAL ;
    PORT
      LAYER M4 ;
        RECT 0.000 507.216 0.192 507.240 ;
    END
  END x_qd[240]
  PIN x_qd[241]
    DIRECTION OUTPUT ;
    USE SIGNAL ;
    PORT
      LAYER M4 ;
        RECT 0.000 508.416 0.192 508.440 ;
    END
  END x_qd[241]
  PIN x_qd[242]
    DIRECTION OUTPUT ;
    USE SIGNAL ;
    PORT
      LAYER M4 ;
        RECT 0.000 509.616 0.192 509.640 ;
    END
  END x_qd[242]
  PIN x_qd[243]
    DIRECTION OUTPUT ;
    USE SIGNAL ;
    PORT
      LAYER M4 ;
        RECT 0.000 510.816 0.192 510.840 ;
    END
  END x_qd[243]
  PIN x_qd[244]
    DIRECTION OUTPUT ;
    USE SIGNAL ;
    PORT
      LAYER M4 ;
        RECT 0.000 512.016 0.192 512.040 ;
    END
  END x_qd[244]
  PIN x_qd[245]
    DIRECTION OUTPUT ;
    USE SIGNAL ;
    PORT
      LAYER M4 ;
        RECT 0.000 513.216 0.192 513.240 ;
    END
  END x_qd[245]
  PIN x_qd[246]
    DIRECTION OUTPUT ;
    USE SIGNAL ;
    PORT
      LAYER M4 ;
        RECT 0.000 514.416 0.192 514.440 ;
    END
  END x_qd[246]
  PIN x_qd[247]
    DIRECTION OUTPUT ;
    USE SIGNAL ;
    PORT
      LAYER M4 ;
        RECT 0.000 515.616 0.192 515.640 ;
    END
  END x_qd[247]
  PIN x_qd[248]
    DIRECTION OUTPUT ;
    USE SIGNAL ;
    PORT
      LAYER M4 ;
        RECT 0.000 516.816 0.192 516.840 ;
    END
  END x_qd[248]
  PIN x_qd[249]
    DIRECTION OUTPUT ;
    USE SIGNAL ;
    PORT
      LAYER M4 ;
        RECT 0.000 518.016 0.192 518.040 ;
    END
  END x_qd[249]
  PIN x_qd[250]
    DIRECTION OUTPUT ;
    USE SIGNAL ;
    PORT
      LAYER M4 ;
        RECT 0.000 519.216 0.192 519.240 ;
    END
  END x_qd[250]
  PIN x_qd[251]
    DIRECTION OUTPUT ;
    USE SIGNAL ;
    PORT
      LAYER M4 ;
        RECT 0.000 520.416 0.192 520.440 ;
    END
  END x_qd[251]
  PIN x_qd[252]
    DIRECTION OUTPUT ;
    USE SIGNAL ;
    PORT
      LAYER M4 ;
        RECT 0.000 521.616 0.192 521.640 ;
    END
  END x_qd[252]
  PIN x_qd[253]
    DIRECTION OUTPUT ;
    USE SIGNAL ;
    PORT
      LAYER M4 ;
        RECT 0.000 522.816 0.192 522.840 ;
    END
  END x_qd[253]
  PIN x_qd[254]
    DIRECTION OUTPUT ;
    USE SIGNAL ;
    PORT
      LAYER M4 ;
        RECT 0.000 524.016 0.192 524.040 ;
    END
  END x_qd[254]
  PIN x_qd[255]
    DIRECTION OUTPUT ;
    USE SIGNAL ;
    PORT
      LAYER M4 ;
        RECT 0.000 525.216 0.192 525.240 ;
    END
  END x_qd[255]
  PIN x_wv
    DIRECTION INPUT ;
    USE SIGNAL ;
    PORT
      LAYER M4 ;
        RECT 0.000 527.088 0.192 527.112 ;
    END
  END x_wv
  PIN x_wa[0]
    DIRECTION INPUT ;
    USE SIGNAL ;
    PORT
      LAYER M4 ;
        RECT 0.000 528.960 0.192 528.984 ;
    END
  END x_wa[0]
  PIN x_wa[1]
    DIRECTION INPUT ;
    USE SIGNAL ;
    PORT
      LAYER M4 ;
        RECT 0.000 530.160 0.192 530.184 ;
    END
  END x_wa[1]
  PIN x_wa[2]
    DIRECTION INPUT ;
    USE SIGNAL ;
    PORT
      LAYER M4 ;
        RECT 0.000 531.360 0.192 531.384 ;
    END
  END x_wa[2]
  PIN x_wa[3]
    DIRECTION INPUT ;
    USE SIGNAL ;
    PORT
      LAYER M4 ;
        RECT 0.000 532.560 0.192 532.584 ;
    END
  END x_wa[3]
  PIN x_wa[4]
    DIRECTION INPUT ;
    USE SIGNAL ;
    PORT
      LAYER M4 ;
        RECT 0.000 533.760 0.192 533.784 ;
    END
  END x_wa[4]
  PIN x_wa[5]
    DIRECTION INPUT ;
    USE SIGNAL ;
    PORT
      LAYER M4 ;
        RECT 0.000 534.960 0.192 534.984 ;
    END
  END x_wa[5]
  PIN x_wa[6]
    DIRECTION INPUT ;
    USE SIGNAL ;
    PORT
      LAYER M4 ;
        RECT 0.000 536.208 0.192 536.232 ;
    END
  END x_wa[6]
  PIN x_wa[7]
    DIRECTION INPUT ;
    USE SIGNAL ;
    PORT
      LAYER M4 ;
        RECT 0.000 537.408 0.192 537.432 ;
    END
  END x_wa[7]
  PIN x_wa[8]
    DIRECTION INPUT ;
    USE SIGNAL ;
    PORT
      LAYER M4 ;
        RECT 0.000 538.608 0.192 538.632 ;
    END
  END x_wa[8]
  PIN x_wa[9]
    DIRECTION INPUT ;
    USE SIGNAL ;
    PORT
      LAYER M4 ;
        RECT 0.000 539.808 0.192 539.832 ;
    END
  END x_wa[9]
  PIN x_wm[0]
    DIRECTION INPUT ;
    USE SIGNAL ;
    PORT
      LAYER M4 ;
        RECT 0.000 541.008 0.192 541.032 ;
    END
  END x_wm[0]
  PIN x_wm[1]
    DIRECTION INPUT ;
    USE SIGNAL ;
    PORT
      LAYER M4 ;
        RECT 0.000 542.208 0.192 542.232 ;
    END
  END x_wm[1]
  PIN x_wm[2]
    DIRECTION INPUT ;
    USE SIGNAL ;
    PORT
      LAYER M4 ;
        RECT 0.000 543.408 0.192 543.432 ;
    END
  END x_wm[2]
  PIN x_wm[3]
    DIRECTION INPUT ;
    USE SIGNAL ;
    PORT
      LAYER M4 ;
        RECT 0.000 544.608 0.192 544.632 ;
    END
  END x_wm[3]
  PIN x_wm[4]
    DIRECTION INPUT ;
    USE SIGNAL ;
    PORT
      LAYER M4 ;
        RECT 0.000 545.808 0.192 545.832 ;
    END
  END x_wm[4]
  PIN x_wm[5]
    DIRECTION INPUT ;
    USE SIGNAL ;
    PORT
      LAYER M4 ;
        RECT 0.000 547.008 0.192 547.032 ;
    END
  END x_wm[5]
  PIN x_wm[6]
    DIRECTION INPUT ;
    USE SIGNAL ;
    PORT
      LAYER M4 ;
        RECT 0.000 548.208 0.192 548.232 ;
    END
  END x_wm[6]
  PIN x_wm[7]
    DIRECTION INPUT ;
    USE SIGNAL ;
    PORT
      LAYER M4 ;
        RECT 0.000 549.408 0.192 549.432 ;
    END
  END x_wm[7]
  PIN x_wd[0]
    DIRECTION INPUT ;
    USE SIGNAL ;
    PORT
      LAYER M4 ;
        RECT 0.000 550.608 0.192 550.632 ;
    END
  END x_wd[0]
  PIN x_wd[1]
    DIRECTION INPUT ;
    USE SIGNAL ;
    PORT
      LAYER M4 ;
        RECT 0.000 551.808 0.192 551.832 ;
    END
  END x_wd[1]
  PIN x_wd[2]
    DIRECTION INPUT ;
    USE SIGNAL ;
    PORT
      LAYER M4 ;
        RECT 0.000 553.008 0.192 553.032 ;
    END
  END x_wd[2]
  PIN x_wd[3]
    DIRECTION INPUT ;
    USE SIGNAL ;
    PORT
      LAYER M4 ;
        RECT 0.000 554.208 0.192 554.232 ;
    END
  END x_wd[3]
  PIN x_wd[4]
    DIRECTION INPUT ;
    USE SIGNAL ;
    PORT
      LAYER M4 ;
        RECT 0.000 555.408 0.192 555.432 ;
    END
  END x_wd[4]
  PIN x_wd[5]
    DIRECTION INPUT ;
    USE SIGNAL ;
    PORT
      LAYER M4 ;
        RECT 0.000 556.608 0.192 556.632 ;
    END
  END x_wd[5]
  PIN x_wd[6]
    DIRECTION INPUT ;
    USE SIGNAL ;
    PORT
      LAYER M4 ;
        RECT 0.000 557.808 0.192 557.832 ;
    END
  END x_wd[6]
  PIN x_wd[7]
    DIRECTION INPUT ;
    USE SIGNAL ;
    PORT
      LAYER M4 ;
        RECT 0.000 559.008 0.192 559.032 ;
    END
  END x_wd[7]
  PIN x_wd[8]
    DIRECTION INPUT ;
    USE SIGNAL ;
    PORT
      LAYER M4 ;
        RECT 0.000 560.208 0.192 560.232 ;
    END
  END x_wd[8]
  PIN x_wd[9]
    DIRECTION INPUT ;
    USE SIGNAL ;
    PORT
      LAYER M4 ;
        RECT 0.000 561.408 0.192 561.432 ;
    END
  END x_wd[9]
  PIN x_wd[10]
    DIRECTION INPUT ;
    USE SIGNAL ;
    PORT
      LAYER M4 ;
        RECT 0.000 562.608 0.192 562.632 ;
    END
  END x_wd[10]
  PIN x_wd[11]
    DIRECTION INPUT ;
    USE SIGNAL ;
    PORT
      LAYER M4 ;
        RECT 0.000 563.808 0.192 563.832 ;
    END
  END x_wd[11]
  PIN x_wd[12]
    DIRECTION INPUT ;
    USE SIGNAL ;
    PORT
      LAYER M4 ;
        RECT 0.000 565.008 0.192 565.032 ;
    END
  END x_wd[12]
  PIN x_wd[13]
    DIRECTION INPUT ;
    USE SIGNAL ;
    PORT
      LAYER M4 ;
        RECT 0.000 566.208 0.192 566.232 ;
    END
  END x_wd[13]
  PIN x_wd[14]
    DIRECTION INPUT ;
    USE SIGNAL ;
    PORT
      LAYER M4 ;
        RECT 0.000 567.408 0.192 567.432 ;
    END
  END x_wd[14]
  PIN x_wd[15]
    DIRECTION INPUT ;
    USE SIGNAL ;
    PORT
      LAYER M4 ;
        RECT 0.000 568.608 0.192 568.632 ;
    END
  END x_wd[15]
  PIN x_wd[16]
    DIRECTION INPUT ;
    USE SIGNAL ;
    PORT
      LAYER M4 ;
        RECT 0.000 569.808 0.192 569.832 ;
    END
  END x_wd[16]
  PIN x_wd[17]
    DIRECTION INPUT ;
    USE SIGNAL ;
    PORT
      LAYER M4 ;
        RECT 0.000 571.008 0.192 571.032 ;
    END
  END x_wd[17]
  PIN x_wd[18]
    DIRECTION INPUT ;
    USE SIGNAL ;
    PORT
      LAYER M4 ;
        RECT 0.000 572.208 0.192 572.232 ;
    END
  END x_wd[18]
  PIN x_wd[19]
    DIRECTION INPUT ;
    USE SIGNAL ;
    PORT
      LAYER M4 ;
        RECT 0.000 573.408 0.192 573.432 ;
    END
  END x_wd[19]
  PIN x_wd[20]
    DIRECTION INPUT ;
    USE SIGNAL ;
    PORT
      LAYER M4 ;
        RECT 0.000 574.608 0.192 574.632 ;
    END
  END x_wd[20]
  PIN x_wd[21]
    DIRECTION INPUT ;
    USE SIGNAL ;
    PORT
      LAYER M4 ;
        RECT 0.000 575.808 0.192 575.832 ;
    END
  END x_wd[21]
  PIN x_wd[22]
    DIRECTION INPUT ;
    USE SIGNAL ;
    PORT
      LAYER M4 ;
        RECT 0.000 577.008 0.192 577.032 ;
    END
  END x_wd[22]
  PIN x_wd[23]
    DIRECTION INPUT ;
    USE SIGNAL ;
    PORT
      LAYER M4 ;
        RECT 0.000 578.208 0.192 578.232 ;
    END
  END x_wd[23]
  PIN x_wd[24]
    DIRECTION INPUT ;
    USE SIGNAL ;
    PORT
      LAYER M4 ;
        RECT 0.000 579.408 0.192 579.432 ;
    END
  END x_wd[24]
  PIN x_wd[25]
    DIRECTION INPUT ;
    USE SIGNAL ;
    PORT
      LAYER M4 ;
        RECT 0.000 580.608 0.192 580.632 ;
    END
  END x_wd[25]
  PIN x_wd[26]
    DIRECTION INPUT ;
    USE SIGNAL ;
    PORT
      LAYER M4 ;
        RECT 0.000 581.808 0.192 581.832 ;
    END
  END x_wd[26]
  PIN x_wd[27]
    DIRECTION INPUT ;
    USE SIGNAL ;
    PORT
      LAYER M4 ;
        RECT 0.000 583.008 0.192 583.032 ;
    END
  END x_wd[27]
  PIN x_wd[28]
    DIRECTION INPUT ;
    USE SIGNAL ;
    PORT
      LAYER M4 ;
        RECT 0.000 584.256 0.192 584.280 ;
    END
  END x_wd[28]
  PIN x_wd[29]
    DIRECTION INPUT ;
    USE SIGNAL ;
    PORT
      LAYER M4 ;
        RECT 0.000 585.456 0.192 585.480 ;
    END
  END x_wd[29]
  PIN x_wd[30]
    DIRECTION INPUT ;
    USE SIGNAL ;
    PORT
      LAYER M4 ;
        RECT 0.000 586.656 0.192 586.680 ;
    END
  END x_wd[30]
  PIN x_wd[31]
    DIRECTION INPUT ;
    USE SIGNAL ;
    PORT
      LAYER M4 ;
        RECT 0.000 587.856 0.192 587.880 ;
    END
  END x_wd[31]
  PIN x_wd[32]
    DIRECTION INPUT ;
    USE SIGNAL ;
    PORT
      LAYER M4 ;
        RECT 0.000 589.056 0.192 589.080 ;
    END
  END x_wd[32]
  PIN x_wd[33]
    DIRECTION INPUT ;
    USE SIGNAL ;
    PORT
      LAYER M4 ;
        RECT 0.000 590.256 0.192 590.280 ;
    END
  END x_wd[33]
  PIN x_wd[34]
    DIRECTION INPUT ;
    USE SIGNAL ;
    PORT
      LAYER M4 ;
        RECT 0.000 591.456 0.192 591.480 ;
    END
  END x_wd[34]
  PIN x_wd[35]
    DIRECTION INPUT ;
    USE SIGNAL ;
    PORT
      LAYER M4 ;
        RECT 0.000 592.656 0.192 592.680 ;
    END
  END x_wd[35]
  PIN x_wd[36]
    DIRECTION INPUT ;
    USE SIGNAL ;
    PORT
      LAYER M4 ;
        RECT 0.000 593.856 0.192 593.880 ;
    END
  END x_wd[36]
  PIN x_wd[37]
    DIRECTION INPUT ;
    USE SIGNAL ;
    PORT
      LAYER M4 ;
        RECT 0.000 595.056 0.192 595.080 ;
    END
  END x_wd[37]
  PIN x_wd[38]
    DIRECTION INPUT ;
    USE SIGNAL ;
    PORT
      LAYER M4 ;
        RECT 0.000 596.256 0.192 596.280 ;
    END
  END x_wd[38]
  PIN x_wd[39]
    DIRECTION INPUT ;
    USE SIGNAL ;
    PORT
      LAYER M4 ;
        RECT 0.000 597.456 0.192 597.480 ;
    END
  END x_wd[39]
  PIN x_wd[40]
    DIRECTION INPUT ;
    USE SIGNAL ;
    PORT
      LAYER M4 ;
        RECT 0.000 598.656 0.192 598.680 ;
    END
  END x_wd[40]
  PIN x_wd[41]
    DIRECTION INPUT ;
    USE SIGNAL ;
    PORT
      LAYER M4 ;
        RECT 0.000 599.856 0.192 599.880 ;
    END
  END x_wd[41]
  PIN x_wd[42]
    DIRECTION INPUT ;
    USE SIGNAL ;
    PORT
      LAYER M4 ;
        RECT 0.000 601.056 0.192 601.080 ;
    END
  END x_wd[42]
  PIN x_wd[43]
    DIRECTION INPUT ;
    USE SIGNAL ;
    PORT
      LAYER M4 ;
        RECT 0.000 602.256 0.192 602.280 ;
    END
  END x_wd[43]
  PIN x_wd[44]
    DIRECTION INPUT ;
    USE SIGNAL ;
    PORT
      LAYER M4 ;
        RECT 0.000 603.456 0.192 603.480 ;
    END
  END x_wd[44]
  PIN x_wd[45]
    DIRECTION INPUT ;
    USE SIGNAL ;
    PORT
      LAYER M4 ;
        RECT 0.000 604.656 0.192 604.680 ;
    END
  END x_wd[45]
  PIN x_wd[46]
    DIRECTION INPUT ;
    USE SIGNAL ;
    PORT
      LAYER M4 ;
        RECT 0.000 605.856 0.192 605.880 ;
    END
  END x_wd[46]
  PIN x_wd[47]
    DIRECTION INPUT ;
    USE SIGNAL ;
    PORT
      LAYER M4 ;
        RECT 0.000 607.056 0.192 607.080 ;
    END
  END x_wd[47]
  PIN x_wd[48]
    DIRECTION INPUT ;
    USE SIGNAL ;
    PORT
      LAYER M4 ;
        RECT 0.000 608.256 0.192 608.280 ;
    END
  END x_wd[48]
  PIN x_wd[49]
    DIRECTION INPUT ;
    USE SIGNAL ;
    PORT
      LAYER M4 ;
        RECT 0.000 609.456 0.192 609.480 ;
    END
  END x_wd[49]
  PIN x_wd[50]
    DIRECTION INPUT ;
    USE SIGNAL ;
    PORT
      LAYER M4 ;
        RECT 0.000 610.656 0.192 610.680 ;
    END
  END x_wd[50]
  PIN x_wd[51]
    DIRECTION INPUT ;
    USE SIGNAL ;
    PORT
      LAYER M4 ;
        RECT 0.000 611.856 0.192 611.880 ;
    END
  END x_wd[51]
  PIN x_wd[52]
    DIRECTION INPUT ;
    USE SIGNAL ;
    PORT
      LAYER M4 ;
        RECT 0.000 613.056 0.192 613.080 ;
    END
  END x_wd[52]
  PIN x_wd[53]
    DIRECTION INPUT ;
    USE SIGNAL ;
    PORT
      LAYER M4 ;
        RECT 0.000 614.256 0.192 614.280 ;
    END
  END x_wd[53]
  PIN x_wd[54]
    DIRECTION INPUT ;
    USE SIGNAL ;
    PORT
      LAYER M4 ;
        RECT 0.000 615.456 0.192 615.480 ;
    END
  END x_wd[54]
  PIN x_wd[55]
    DIRECTION INPUT ;
    USE SIGNAL ;
    PORT
      LAYER M4 ;
        RECT 0.000 616.656 0.192 616.680 ;
    END
  END x_wd[55]
  PIN x_wd[56]
    DIRECTION INPUT ;
    USE SIGNAL ;
    PORT
      LAYER M4 ;
        RECT 0.000 617.856 0.192 617.880 ;
    END
  END x_wd[56]
  PIN x_wd[57]
    DIRECTION INPUT ;
    USE SIGNAL ;
    PORT
      LAYER M4 ;
        RECT 0.000 619.056 0.192 619.080 ;
    END
  END x_wd[57]
  PIN x_wd[58]
    DIRECTION INPUT ;
    USE SIGNAL ;
    PORT
      LAYER M4 ;
        RECT 0.000 620.256 0.192 620.280 ;
    END
  END x_wd[58]
  PIN x_wd[59]
    DIRECTION INPUT ;
    USE SIGNAL ;
    PORT
      LAYER M4 ;
        RECT 0.000 621.456 0.192 621.480 ;
    END
  END x_wd[59]
  PIN x_wd[60]
    DIRECTION INPUT ;
    USE SIGNAL ;
    PORT
      LAYER M4 ;
        RECT 0.000 622.656 0.192 622.680 ;
    END
  END x_wd[60]
  PIN x_wd[61]
    DIRECTION INPUT ;
    USE SIGNAL ;
    PORT
      LAYER M4 ;
        RECT 0.000 623.856 0.192 623.880 ;
    END
  END x_wd[61]
  PIN x_wd[62]
    DIRECTION INPUT ;
    USE SIGNAL ;
    PORT
      LAYER M4 ;
        RECT 0.000 625.056 0.192 625.080 ;
    END
  END x_wd[62]
  PIN x_wd[63]
    DIRECTION INPUT ;
    USE SIGNAL ;
    PORT
      LAYER M4 ;
        RECT 0.000 626.256 0.192 626.280 ;
    END
  END x_wd[63]
  PIN x_wd[64]
    DIRECTION INPUT ;
    USE SIGNAL ;
    PORT
      LAYER M4 ;
        RECT 0.000 627.456 0.192 627.480 ;
    END
  END x_wd[64]
  PIN x_wd[65]
    DIRECTION INPUT ;
    USE SIGNAL ;
    PORT
      LAYER M4 ;
        RECT 0.000 628.656 0.192 628.680 ;
    END
  END x_wd[65]
  PIN x_wd[66]
    DIRECTION INPUT ;
    USE SIGNAL ;
    PORT
      LAYER M4 ;
        RECT 0.000 629.856 0.192 629.880 ;
    END
  END x_wd[66]
  PIN x_wd[67]
    DIRECTION INPUT ;
    USE SIGNAL ;
    PORT
      LAYER M4 ;
        RECT 0.000 631.056 0.192 631.080 ;
    END
  END x_wd[67]
  PIN x_wd[68]
    DIRECTION INPUT ;
    USE SIGNAL ;
    PORT
      LAYER M4 ;
        RECT 0.000 632.304 0.192 632.328 ;
    END
  END x_wd[68]
  PIN x_wd[69]
    DIRECTION INPUT ;
    USE SIGNAL ;
    PORT
      LAYER M4 ;
        RECT 0.000 633.504 0.192 633.528 ;
    END
  END x_wd[69]
  PIN x_wd[70]
    DIRECTION INPUT ;
    USE SIGNAL ;
    PORT
      LAYER M4 ;
        RECT 0.000 634.704 0.192 634.728 ;
    END
  END x_wd[70]
  PIN x_wd[71]
    DIRECTION INPUT ;
    USE SIGNAL ;
    PORT
      LAYER M4 ;
        RECT 0.000 635.904 0.192 635.928 ;
    END
  END x_wd[71]
  PIN x_wd[72]
    DIRECTION INPUT ;
    USE SIGNAL ;
    PORT
      LAYER M4 ;
        RECT 0.000 637.104 0.192 637.128 ;
    END
  END x_wd[72]
  PIN x_wd[73]
    DIRECTION INPUT ;
    USE SIGNAL ;
    PORT
      LAYER M4 ;
        RECT 0.000 638.304 0.192 638.328 ;
    END
  END x_wd[73]
  PIN x_wd[74]
    DIRECTION INPUT ;
    USE SIGNAL ;
    PORT
      LAYER M4 ;
        RECT 0.000 639.504 0.192 639.528 ;
    END
  END x_wd[74]
  PIN x_wd[75]
    DIRECTION INPUT ;
    USE SIGNAL ;
    PORT
      LAYER M4 ;
        RECT 0.000 640.704 0.192 640.728 ;
    END
  END x_wd[75]
  PIN x_wd[76]
    DIRECTION INPUT ;
    USE SIGNAL ;
    PORT
      LAYER M4 ;
        RECT 0.000 641.904 0.192 641.928 ;
    END
  END x_wd[76]
  PIN x_wd[77]
    DIRECTION INPUT ;
    USE SIGNAL ;
    PORT
      LAYER M4 ;
        RECT 0.000 643.104 0.192 643.128 ;
    END
  END x_wd[77]
  PIN x_wd[78]
    DIRECTION INPUT ;
    USE SIGNAL ;
    PORT
      LAYER M4 ;
        RECT 0.000 644.304 0.192 644.328 ;
    END
  END x_wd[78]
  PIN x_wd[79]
    DIRECTION INPUT ;
    USE SIGNAL ;
    PORT
      LAYER M4 ;
        RECT 0.000 645.504 0.192 645.528 ;
    END
  END x_wd[79]
  PIN x_wd[80]
    DIRECTION INPUT ;
    USE SIGNAL ;
    PORT
      LAYER M4 ;
        RECT 0.000 646.704 0.192 646.728 ;
    END
  END x_wd[80]
  PIN x_wd[81]
    DIRECTION INPUT ;
    USE SIGNAL ;
    PORT
      LAYER M4 ;
        RECT 0.000 647.904 0.192 647.928 ;
    END
  END x_wd[81]
  PIN x_wd[82]
    DIRECTION INPUT ;
    USE SIGNAL ;
    PORT
      LAYER M4 ;
        RECT 0.000 649.104 0.192 649.128 ;
    END
  END x_wd[82]
  PIN x_wd[83]
    DIRECTION INPUT ;
    USE SIGNAL ;
    PORT
      LAYER M4 ;
        RECT 0.000 650.304 0.192 650.328 ;
    END
  END x_wd[83]
  PIN x_wd[84]
    DIRECTION INPUT ;
    USE SIGNAL ;
    PORT
      LAYER M4 ;
        RECT 0.000 651.504 0.192 651.528 ;
    END
  END x_wd[84]
  PIN x_wd[85]
    DIRECTION INPUT ;
    USE SIGNAL ;
    PORT
      LAYER M4 ;
        RECT 0.000 652.704 0.192 652.728 ;
    END
  END x_wd[85]
  PIN x_wd[86]
    DIRECTION INPUT ;
    USE SIGNAL ;
    PORT
      LAYER M4 ;
        RECT 0.000 653.904 0.192 653.928 ;
    END
  END x_wd[86]
  PIN x_wd[87]
    DIRECTION INPUT ;
    USE SIGNAL ;
    PORT
      LAYER M4 ;
        RECT 0.000 655.104 0.192 655.128 ;
    END
  END x_wd[87]
  PIN x_wd[88]
    DIRECTION INPUT ;
    USE SIGNAL ;
    PORT
      LAYER M4 ;
        RECT 0.000 656.304 0.192 656.328 ;
    END
  END x_wd[88]
  PIN x_wd[89]
    DIRECTION INPUT ;
    USE SIGNAL ;
    PORT
      LAYER M4 ;
        RECT 0.000 657.504 0.192 657.528 ;
    END
  END x_wd[89]
  PIN x_wd[90]
    DIRECTION INPUT ;
    USE SIGNAL ;
    PORT
      LAYER M4 ;
        RECT 0.000 658.704 0.192 658.728 ;
    END
  END x_wd[90]
  PIN x_wd[91]
    DIRECTION INPUT ;
    USE SIGNAL ;
    PORT
      LAYER M4 ;
        RECT 0.000 659.904 0.192 659.928 ;
    END
  END x_wd[91]
  PIN x_wd[92]
    DIRECTION INPUT ;
    USE SIGNAL ;
    PORT
      LAYER M4 ;
        RECT 0.000 661.104 0.192 661.128 ;
    END
  END x_wd[92]
  PIN x_wd[93]
    DIRECTION INPUT ;
    USE SIGNAL ;
    PORT
      LAYER M4 ;
        RECT 0.000 662.304 0.192 662.328 ;
    END
  END x_wd[93]
  PIN x_wd[94]
    DIRECTION INPUT ;
    USE SIGNAL ;
    PORT
      LAYER M4 ;
        RECT 0.000 663.504 0.192 663.528 ;
    END
  END x_wd[94]
  PIN x_wd[95]
    DIRECTION INPUT ;
    USE SIGNAL ;
    PORT
      LAYER M4 ;
        RECT 0.000 664.704 0.192 664.728 ;
    END
  END x_wd[95]
  PIN x_wd[96]
    DIRECTION INPUT ;
    USE SIGNAL ;
    PORT
      LAYER M4 ;
        RECT 0.000 665.904 0.192 665.928 ;
    END
  END x_wd[96]
  PIN x_wd[97]
    DIRECTION INPUT ;
    USE SIGNAL ;
    PORT
      LAYER M4 ;
        RECT 0.000 667.104 0.192 667.128 ;
    END
  END x_wd[97]
  PIN x_wd[98]
    DIRECTION INPUT ;
    USE SIGNAL ;
    PORT
      LAYER M4 ;
        RECT 0.000 668.304 0.192 668.328 ;
    END
  END x_wd[98]
  PIN x_wd[99]
    DIRECTION INPUT ;
    USE SIGNAL ;
    PORT
      LAYER M4 ;
        RECT 0.000 669.504 0.192 669.528 ;
    END
  END x_wd[99]
  PIN x_wd[100]
    DIRECTION INPUT ;
    USE SIGNAL ;
    PORT
      LAYER M4 ;
        RECT 0.000 670.704 0.192 670.728 ;
    END
  END x_wd[100]
  PIN x_wd[101]
    DIRECTION INPUT ;
    USE SIGNAL ;
    PORT
      LAYER M4 ;
        RECT 0.000 671.904 0.192 671.928 ;
    END
  END x_wd[101]
  PIN x_wd[102]
    DIRECTION INPUT ;
    USE SIGNAL ;
    PORT
      LAYER M4 ;
        RECT 0.000 673.104 0.192 673.128 ;
    END
  END x_wd[102]
  PIN x_wd[103]
    DIRECTION INPUT ;
    USE SIGNAL ;
    PORT
      LAYER M4 ;
        RECT 0.000 674.304 0.192 674.328 ;
    END
  END x_wd[103]
  PIN x_wd[104]
    DIRECTION INPUT ;
    USE SIGNAL ;
    PORT
      LAYER M4 ;
        RECT 0.000 675.504 0.192 675.528 ;
    END
  END x_wd[104]
  PIN x_wd[105]
    DIRECTION INPUT ;
    USE SIGNAL ;
    PORT
      LAYER M4 ;
        RECT 0.000 676.704 0.192 676.728 ;
    END
  END x_wd[105]
  PIN x_wd[106]
    DIRECTION INPUT ;
    USE SIGNAL ;
    PORT
      LAYER M4 ;
        RECT 0.000 677.904 0.192 677.928 ;
    END
  END x_wd[106]
  PIN x_wd[107]
    DIRECTION INPUT ;
    USE SIGNAL ;
    PORT
      LAYER M4 ;
        RECT 0.000 679.152 0.192 679.176 ;
    END
  END x_wd[107]
  PIN x_wd[108]
    DIRECTION INPUT ;
    USE SIGNAL ;
    PORT
      LAYER M4 ;
        RECT 0.000 680.352 0.192 680.376 ;
    END
  END x_wd[108]
  PIN x_wd[109]
    DIRECTION INPUT ;
    USE SIGNAL ;
    PORT
      LAYER M4 ;
        RECT 0.000 681.552 0.192 681.576 ;
    END
  END x_wd[109]
  PIN x_wd[110]
    DIRECTION INPUT ;
    USE SIGNAL ;
    PORT
      LAYER M4 ;
        RECT 0.000 682.752 0.192 682.776 ;
    END
  END x_wd[110]
  PIN x_wd[111]
    DIRECTION INPUT ;
    USE SIGNAL ;
    PORT
      LAYER M4 ;
        RECT 0.000 683.952 0.192 683.976 ;
    END
  END x_wd[111]
  PIN x_wd[112]
    DIRECTION INPUT ;
    USE SIGNAL ;
    PORT
      LAYER M4 ;
        RECT 0.000 685.152 0.192 685.176 ;
    END
  END x_wd[112]
  PIN x_wd[113]
    DIRECTION INPUT ;
    USE SIGNAL ;
    PORT
      LAYER M4 ;
        RECT 0.000 686.352 0.192 686.376 ;
    END
  END x_wd[113]
  PIN x_wd[114]
    DIRECTION INPUT ;
    USE SIGNAL ;
    PORT
      LAYER M4 ;
        RECT 0.000 687.552 0.192 687.576 ;
    END
  END x_wd[114]
  PIN x_wd[115]
    DIRECTION INPUT ;
    USE SIGNAL ;
    PORT
      LAYER M4 ;
        RECT 0.000 688.752 0.192 688.776 ;
    END
  END x_wd[115]
  PIN x_wd[116]
    DIRECTION INPUT ;
    USE SIGNAL ;
    PORT
      LAYER M4 ;
        RECT 0.000 689.952 0.192 689.976 ;
    END
  END x_wd[116]
  PIN x_wd[117]
    DIRECTION INPUT ;
    USE SIGNAL ;
    PORT
      LAYER M4 ;
        RECT 0.000 691.152 0.192 691.176 ;
    END
  END x_wd[117]
  PIN x_wd[118]
    DIRECTION INPUT ;
    USE SIGNAL ;
    PORT
      LAYER M4 ;
        RECT 0.000 692.352 0.192 692.376 ;
    END
  END x_wd[118]
  PIN x_wd[119]
    DIRECTION INPUT ;
    USE SIGNAL ;
    PORT
      LAYER M4 ;
        RECT 0.000 693.552 0.192 693.576 ;
    END
  END x_wd[119]
  PIN x_wd[120]
    DIRECTION INPUT ;
    USE SIGNAL ;
    PORT
      LAYER M4 ;
        RECT 0.000 694.752 0.192 694.776 ;
    END
  END x_wd[120]
  PIN x_wd[121]
    DIRECTION INPUT ;
    USE SIGNAL ;
    PORT
      LAYER M4 ;
        RECT 0.000 695.952 0.192 695.976 ;
    END
  END x_wd[121]
  PIN x_wd[122]
    DIRECTION INPUT ;
    USE SIGNAL ;
    PORT
      LAYER M4 ;
        RECT 0.000 697.152 0.192 697.176 ;
    END
  END x_wd[122]
  PIN x_wd[123]
    DIRECTION INPUT ;
    USE SIGNAL ;
    PORT
      LAYER M4 ;
        RECT 0.000 698.352 0.192 698.376 ;
    END
  END x_wd[123]
  PIN x_wd[124]
    DIRECTION INPUT ;
    USE SIGNAL ;
    PORT
      LAYER M4 ;
        RECT 0.000 699.552 0.192 699.576 ;
    END
  END x_wd[124]
  PIN x_wd[125]
    DIRECTION INPUT ;
    USE SIGNAL ;
    PORT
      LAYER M4 ;
        RECT 0.000 700.752 0.192 700.776 ;
    END
  END x_wd[125]
  PIN x_wd[126]
    DIRECTION INPUT ;
    USE SIGNAL ;
    PORT
      LAYER M4 ;
        RECT 0.000 701.952 0.192 701.976 ;
    END
  END x_wd[126]
  PIN x_wd[127]
    DIRECTION INPUT ;
    USE SIGNAL ;
    PORT
      LAYER M4 ;
        RECT 0.000 703.152 0.192 703.176 ;
    END
  END x_wd[127]
  PIN x_wd[128]
    DIRECTION INPUT ;
    USE SIGNAL ;
    PORT
      LAYER M4 ;
        RECT 0.000 704.352 0.192 704.376 ;
    END
  END x_wd[128]
  PIN x_wd[129]
    DIRECTION INPUT ;
    USE SIGNAL ;
    PORT
      LAYER M4 ;
        RECT 0.000 705.552 0.192 705.576 ;
    END
  END x_wd[129]
  PIN x_wd[130]
    DIRECTION INPUT ;
    USE SIGNAL ;
    PORT
      LAYER M4 ;
        RECT 0.000 706.752 0.192 706.776 ;
    END
  END x_wd[130]
  PIN x_wd[131]
    DIRECTION INPUT ;
    USE SIGNAL ;
    PORT
      LAYER M4 ;
        RECT 0.000 707.952 0.192 707.976 ;
    END
  END x_wd[131]
  PIN x_wd[132]
    DIRECTION INPUT ;
    USE SIGNAL ;
    PORT
      LAYER M4 ;
        RECT 0.000 709.152 0.192 709.176 ;
    END
  END x_wd[132]
  PIN x_wd[133]
    DIRECTION INPUT ;
    USE SIGNAL ;
    PORT
      LAYER M4 ;
        RECT 0.000 710.352 0.192 710.376 ;
    END
  END x_wd[133]
  PIN x_wd[134]
    DIRECTION INPUT ;
    USE SIGNAL ;
    PORT
      LAYER M4 ;
        RECT 0.000 711.552 0.192 711.576 ;
    END
  END x_wd[134]
  PIN x_wd[135]
    DIRECTION INPUT ;
    USE SIGNAL ;
    PORT
      LAYER M4 ;
        RECT 0.000 712.752 0.192 712.776 ;
    END
  END x_wd[135]
  PIN x_wd[136]
    DIRECTION INPUT ;
    USE SIGNAL ;
    PORT
      LAYER M4 ;
        RECT 0.000 713.952 0.192 713.976 ;
    END
  END x_wd[136]
  PIN x_wd[137]
    DIRECTION INPUT ;
    USE SIGNAL ;
    PORT
      LAYER M4 ;
        RECT 0.000 715.152 0.192 715.176 ;
    END
  END x_wd[137]
  PIN x_wd[138]
    DIRECTION INPUT ;
    USE SIGNAL ;
    PORT
      LAYER M4 ;
        RECT 0.000 716.352 0.192 716.376 ;
    END
  END x_wd[138]
  PIN x_wd[139]
    DIRECTION INPUT ;
    USE SIGNAL ;
    PORT
      LAYER M4 ;
        RECT 0.000 717.552 0.192 717.576 ;
    END
  END x_wd[139]
  PIN x_wd[140]
    DIRECTION INPUT ;
    USE SIGNAL ;
    PORT
      LAYER M4 ;
        RECT 0.000 718.752 0.192 718.776 ;
    END
  END x_wd[140]
  PIN x_wd[141]
    DIRECTION INPUT ;
    USE SIGNAL ;
    PORT
      LAYER M4 ;
        RECT 0.000 719.952 0.192 719.976 ;
    END
  END x_wd[141]
  PIN x_wd[142]
    DIRECTION INPUT ;
    USE SIGNAL ;
    PORT
      LAYER M4 ;
        RECT 0.000 721.152 0.192 721.176 ;
    END
  END x_wd[142]
  PIN x_wd[143]
    DIRECTION INPUT ;
    USE SIGNAL ;
    PORT
      LAYER M4 ;
        RECT 0.000 722.352 0.192 722.376 ;
    END
  END x_wd[143]
  PIN x_wd[144]
    DIRECTION INPUT ;
    USE SIGNAL ;
    PORT
      LAYER M4 ;
        RECT 0.000 723.552 0.192 723.576 ;
    END
  END x_wd[144]
  PIN x_wd[145]
    DIRECTION INPUT ;
    USE SIGNAL ;
    PORT
      LAYER M4 ;
        RECT 0.000 724.752 0.192 724.776 ;
    END
  END x_wd[145]
  PIN x_wd[146]
    DIRECTION INPUT ;
    USE SIGNAL ;
    PORT
      LAYER M4 ;
        RECT 0.000 725.952 0.192 725.976 ;
    END
  END x_wd[146]
  PIN x_wd[147]
    DIRECTION INPUT ;
    USE SIGNAL ;
    PORT
      LAYER M4 ;
        RECT 0.000 727.200 0.192 727.224 ;
    END
  END x_wd[147]
  PIN x_wd[148]
    DIRECTION INPUT ;
    USE SIGNAL ;
    PORT
      LAYER M4 ;
        RECT 0.000 728.400 0.192 728.424 ;
    END
  END x_wd[148]
  PIN x_wd[149]
    DIRECTION INPUT ;
    USE SIGNAL ;
    PORT
      LAYER M4 ;
        RECT 0.000 729.600 0.192 729.624 ;
    END
  END x_wd[149]
  PIN x_wd[150]
    DIRECTION INPUT ;
    USE SIGNAL ;
    PORT
      LAYER M4 ;
        RECT 0.000 730.800 0.192 730.824 ;
    END
  END x_wd[150]
  PIN x_wd[151]
    DIRECTION INPUT ;
    USE SIGNAL ;
    PORT
      LAYER M4 ;
        RECT 0.000 732.000 0.192 732.024 ;
    END
  END x_wd[151]
  PIN x_wd[152]
    DIRECTION INPUT ;
    USE SIGNAL ;
    PORT
      LAYER M4 ;
        RECT 0.000 733.200 0.192 733.224 ;
    END
  END x_wd[152]
  PIN x_wd[153]
    DIRECTION INPUT ;
    USE SIGNAL ;
    PORT
      LAYER M4 ;
        RECT 0.000 734.400 0.192 734.424 ;
    END
  END x_wd[153]
  PIN x_wd[154]
    DIRECTION INPUT ;
    USE SIGNAL ;
    PORT
      LAYER M4 ;
        RECT 0.000 735.600 0.192 735.624 ;
    END
  END x_wd[154]
  PIN x_wd[155]
    DIRECTION INPUT ;
    USE SIGNAL ;
    PORT
      LAYER M4 ;
        RECT 0.000 736.800 0.192 736.824 ;
    END
  END x_wd[155]
  PIN x_wd[156]
    DIRECTION INPUT ;
    USE SIGNAL ;
    PORT
      LAYER M4 ;
        RECT 0.000 738.000 0.192 738.024 ;
    END
  END x_wd[156]
  PIN x_wd[157]
    DIRECTION INPUT ;
    USE SIGNAL ;
    PORT
      LAYER M4 ;
        RECT 0.000 739.200 0.192 739.224 ;
    END
  END x_wd[157]
  PIN x_wd[158]
    DIRECTION INPUT ;
    USE SIGNAL ;
    PORT
      LAYER M4 ;
        RECT 0.000 740.400 0.192 740.424 ;
    END
  END x_wd[158]
  PIN x_wd[159]
    DIRECTION INPUT ;
    USE SIGNAL ;
    PORT
      LAYER M4 ;
        RECT 0.000 741.600 0.192 741.624 ;
    END
  END x_wd[159]
  PIN x_wd[160]
    DIRECTION INPUT ;
    USE SIGNAL ;
    PORT
      LAYER M4 ;
        RECT 0.000 742.800 0.192 742.824 ;
    END
  END x_wd[160]
  PIN x_wd[161]
    DIRECTION INPUT ;
    USE SIGNAL ;
    PORT
      LAYER M4 ;
        RECT 0.000 744.000 0.192 744.024 ;
    END
  END x_wd[161]
  PIN x_wd[162]
    DIRECTION INPUT ;
    USE SIGNAL ;
    PORT
      LAYER M4 ;
        RECT 0.000 745.200 0.192 745.224 ;
    END
  END x_wd[162]
  PIN x_wd[163]
    DIRECTION INPUT ;
    USE SIGNAL ;
    PORT
      LAYER M4 ;
        RECT 0.000 746.400 0.192 746.424 ;
    END
  END x_wd[163]
  PIN x_wd[164]
    DIRECTION INPUT ;
    USE SIGNAL ;
    PORT
      LAYER M4 ;
        RECT 0.000 747.600 0.192 747.624 ;
    END
  END x_wd[164]
  PIN x_wd[165]
    DIRECTION INPUT ;
    USE SIGNAL ;
    PORT
      LAYER M4 ;
        RECT 0.000 748.800 0.192 748.824 ;
    END
  END x_wd[165]
  PIN x_wd[166]
    DIRECTION INPUT ;
    USE SIGNAL ;
    PORT
      LAYER M4 ;
        RECT 0.000 750.000 0.192 750.024 ;
    END
  END x_wd[166]
  PIN x_wd[167]
    DIRECTION INPUT ;
    USE SIGNAL ;
    PORT
      LAYER M4 ;
        RECT 0.000 751.200 0.192 751.224 ;
    END
  END x_wd[167]
  PIN x_wd[168]
    DIRECTION INPUT ;
    USE SIGNAL ;
    PORT
      LAYER M4 ;
        RECT 0.000 752.400 0.192 752.424 ;
    END
  END x_wd[168]
  PIN x_wd[169]
    DIRECTION INPUT ;
    USE SIGNAL ;
    PORT
      LAYER M4 ;
        RECT 0.000 753.600 0.192 753.624 ;
    END
  END x_wd[169]
  PIN x_wd[170]
    DIRECTION INPUT ;
    USE SIGNAL ;
    PORT
      LAYER M4 ;
        RECT 0.000 754.800 0.192 754.824 ;
    END
  END x_wd[170]
  PIN x_wd[171]
    DIRECTION INPUT ;
    USE SIGNAL ;
    PORT
      LAYER M4 ;
        RECT 0.000 756.000 0.192 756.024 ;
    END
  END x_wd[171]
  PIN x_wd[172]
    DIRECTION INPUT ;
    USE SIGNAL ;
    PORT
      LAYER M4 ;
        RECT 0.000 757.200 0.192 757.224 ;
    END
  END x_wd[172]
  PIN x_wd[173]
    DIRECTION INPUT ;
    USE SIGNAL ;
    PORT
      LAYER M4 ;
        RECT 0.000 758.400 0.192 758.424 ;
    END
  END x_wd[173]
  PIN x_wd[174]
    DIRECTION INPUT ;
    USE SIGNAL ;
    PORT
      LAYER M4 ;
        RECT 0.000 759.600 0.192 759.624 ;
    END
  END x_wd[174]
  PIN x_wd[175]
    DIRECTION INPUT ;
    USE SIGNAL ;
    PORT
      LAYER M4 ;
        RECT 0.000 760.800 0.192 760.824 ;
    END
  END x_wd[175]
  PIN x_wd[176]
    DIRECTION INPUT ;
    USE SIGNAL ;
    PORT
      LAYER M4 ;
        RECT 0.000 762.000 0.192 762.024 ;
    END
  END x_wd[176]
  PIN x_wd[177]
    DIRECTION INPUT ;
    USE SIGNAL ;
    PORT
      LAYER M4 ;
        RECT 0.000 763.200 0.192 763.224 ;
    END
  END x_wd[177]
  PIN x_wd[178]
    DIRECTION INPUT ;
    USE SIGNAL ;
    PORT
      LAYER M4 ;
        RECT 0.000 764.400 0.192 764.424 ;
    END
  END x_wd[178]
  PIN x_wd[179]
    DIRECTION INPUT ;
    USE SIGNAL ;
    PORT
      LAYER M4 ;
        RECT 0.000 765.600 0.192 765.624 ;
    END
  END x_wd[179]
  PIN x_wd[180]
    DIRECTION INPUT ;
    USE SIGNAL ;
    PORT
      LAYER M4 ;
        RECT 0.000 766.800 0.192 766.824 ;
    END
  END x_wd[180]
  PIN x_wd[181]
    DIRECTION INPUT ;
    USE SIGNAL ;
    PORT
      LAYER M4 ;
        RECT 0.000 768.000 0.192 768.024 ;
    END
  END x_wd[181]
  PIN x_wd[182]
    DIRECTION INPUT ;
    USE SIGNAL ;
    PORT
      LAYER M4 ;
        RECT 0.000 769.200 0.192 769.224 ;
    END
  END x_wd[182]
  PIN x_wd[183]
    DIRECTION INPUT ;
    USE SIGNAL ;
    PORT
      LAYER M4 ;
        RECT 0.000 770.400 0.192 770.424 ;
    END
  END x_wd[183]
  PIN x_wd[184]
    DIRECTION INPUT ;
    USE SIGNAL ;
    PORT
      LAYER M4 ;
        RECT 0.000 771.600 0.192 771.624 ;
    END
  END x_wd[184]
  PIN x_wd[185]
    DIRECTION INPUT ;
    USE SIGNAL ;
    PORT
      LAYER M4 ;
        RECT 0.000 772.800 0.192 772.824 ;
    END
  END x_wd[185]
  PIN x_wd[186]
    DIRECTION INPUT ;
    USE SIGNAL ;
    PORT
      LAYER M4 ;
        RECT 0.000 774.000 0.192 774.024 ;
    END
  END x_wd[186]
  PIN x_wd[187]
    DIRECTION INPUT ;
    USE SIGNAL ;
    PORT
      LAYER M4 ;
        RECT 0.000 775.248 0.192 775.272 ;
    END
  END x_wd[187]
  PIN x_wd[188]
    DIRECTION INPUT ;
    USE SIGNAL ;
    PORT
      LAYER M4 ;
        RECT 0.000 776.448 0.192 776.472 ;
    END
  END x_wd[188]
  PIN x_wd[189]
    DIRECTION INPUT ;
    USE SIGNAL ;
    PORT
      LAYER M4 ;
        RECT 0.000 777.648 0.192 777.672 ;
    END
  END x_wd[189]
  PIN x_wd[190]
    DIRECTION INPUT ;
    USE SIGNAL ;
    PORT
      LAYER M4 ;
        RECT 0.000 778.848 0.192 778.872 ;
    END
  END x_wd[190]
  PIN x_wd[191]
    DIRECTION INPUT ;
    USE SIGNAL ;
    PORT
      LAYER M4 ;
        RECT 0.000 780.048 0.192 780.072 ;
    END
  END x_wd[191]
  PIN x_wd[192]
    DIRECTION INPUT ;
    USE SIGNAL ;
    PORT
      LAYER M4 ;
        RECT 0.000 781.248 0.192 781.272 ;
    END
  END x_wd[192]
  PIN x_wd[193]
    DIRECTION INPUT ;
    USE SIGNAL ;
    PORT
      LAYER M4 ;
        RECT 0.000 782.448 0.192 782.472 ;
    END
  END x_wd[193]
  PIN x_wd[194]
    DIRECTION INPUT ;
    USE SIGNAL ;
    PORT
      LAYER M4 ;
        RECT 0.000 783.648 0.192 783.672 ;
    END
  END x_wd[194]
  PIN x_wd[195]
    DIRECTION INPUT ;
    USE SIGNAL ;
    PORT
      LAYER M4 ;
        RECT 0.000 784.848 0.192 784.872 ;
    END
  END x_wd[195]
  PIN x_wd[196]
    DIRECTION INPUT ;
    USE SIGNAL ;
    PORT
      LAYER M4 ;
        RECT 0.000 786.048 0.192 786.072 ;
    END
  END x_wd[196]
  PIN x_wd[197]
    DIRECTION INPUT ;
    USE SIGNAL ;
    PORT
      LAYER M4 ;
        RECT 0.000 787.248 0.192 787.272 ;
    END
  END x_wd[197]
  PIN x_wd[198]
    DIRECTION INPUT ;
    USE SIGNAL ;
    PORT
      LAYER M4 ;
        RECT 0.000 788.448 0.192 788.472 ;
    END
  END x_wd[198]
  PIN x_wd[199]
    DIRECTION INPUT ;
    USE SIGNAL ;
    PORT
      LAYER M4 ;
        RECT 0.000 789.648 0.192 789.672 ;
    END
  END x_wd[199]
  PIN x_wd[200]
    DIRECTION INPUT ;
    USE SIGNAL ;
    PORT
      LAYER M4 ;
        RECT 0.000 790.848 0.192 790.872 ;
    END
  END x_wd[200]
  PIN x_wd[201]
    DIRECTION INPUT ;
    USE SIGNAL ;
    PORT
      LAYER M4 ;
        RECT 0.000 792.048 0.192 792.072 ;
    END
  END x_wd[201]
  PIN x_wd[202]
    DIRECTION INPUT ;
    USE SIGNAL ;
    PORT
      LAYER M4 ;
        RECT 0.000 793.248 0.192 793.272 ;
    END
  END x_wd[202]
  PIN x_wd[203]
    DIRECTION INPUT ;
    USE SIGNAL ;
    PORT
      LAYER M4 ;
        RECT 0.000 794.448 0.192 794.472 ;
    END
  END x_wd[203]
  PIN x_wd[204]
    DIRECTION INPUT ;
    USE SIGNAL ;
    PORT
      LAYER M4 ;
        RECT 0.000 795.648 0.192 795.672 ;
    END
  END x_wd[204]
  PIN x_wd[205]
    DIRECTION INPUT ;
    USE SIGNAL ;
    PORT
      LAYER M4 ;
        RECT 0.000 796.848 0.192 796.872 ;
    END
  END x_wd[205]
  PIN x_wd[206]
    DIRECTION INPUT ;
    USE SIGNAL ;
    PORT
      LAYER M4 ;
        RECT 0.000 798.048 0.192 798.072 ;
    END
  END x_wd[206]
  PIN x_wd[207]
    DIRECTION INPUT ;
    USE SIGNAL ;
    PORT
      LAYER M4 ;
        RECT 0.000 799.248 0.192 799.272 ;
    END
  END x_wd[207]
  PIN x_wd[208]
    DIRECTION INPUT ;
    USE SIGNAL ;
    PORT
      LAYER M4 ;
        RECT 0.000 800.448 0.192 800.472 ;
    END
  END x_wd[208]
  PIN x_wd[209]
    DIRECTION INPUT ;
    USE SIGNAL ;
    PORT
      LAYER M4 ;
        RECT 0.000 801.648 0.192 801.672 ;
    END
  END x_wd[209]
  PIN x_wd[210]
    DIRECTION INPUT ;
    USE SIGNAL ;
    PORT
      LAYER M4 ;
        RECT 0.000 802.848 0.192 802.872 ;
    END
  END x_wd[210]
  PIN x_wd[211]
    DIRECTION INPUT ;
    USE SIGNAL ;
    PORT
      LAYER M4 ;
        RECT 0.000 804.048 0.192 804.072 ;
    END
  END x_wd[211]
  PIN x_wd[212]
    DIRECTION INPUT ;
    USE SIGNAL ;
    PORT
      LAYER M4 ;
        RECT 0.000 805.248 0.192 805.272 ;
    END
  END x_wd[212]
  PIN x_wd[213]
    DIRECTION INPUT ;
    USE SIGNAL ;
    PORT
      LAYER M4 ;
        RECT 0.000 806.448 0.192 806.472 ;
    END
  END x_wd[213]
  PIN x_wd[214]
    DIRECTION INPUT ;
    USE SIGNAL ;
    PORT
      LAYER M4 ;
        RECT 0.000 807.648 0.192 807.672 ;
    END
  END x_wd[214]
  PIN x_wd[215]
    DIRECTION INPUT ;
    USE SIGNAL ;
    PORT
      LAYER M4 ;
        RECT 0.000 808.848 0.192 808.872 ;
    END
  END x_wd[215]
  PIN x_wd[216]
    DIRECTION INPUT ;
    USE SIGNAL ;
    PORT
      LAYER M4 ;
        RECT 0.000 810.048 0.192 810.072 ;
    END
  END x_wd[216]
  PIN x_wd[217]
    DIRECTION INPUT ;
    USE SIGNAL ;
    PORT
      LAYER M4 ;
        RECT 0.000 811.248 0.192 811.272 ;
    END
  END x_wd[217]
  PIN x_wd[218]
    DIRECTION INPUT ;
    USE SIGNAL ;
    PORT
      LAYER M4 ;
        RECT 0.000 812.448 0.192 812.472 ;
    END
  END x_wd[218]
  PIN x_wd[219]
    DIRECTION INPUT ;
    USE SIGNAL ;
    PORT
      LAYER M4 ;
        RECT 0.000 813.648 0.192 813.672 ;
    END
  END x_wd[219]
  PIN x_wd[220]
    DIRECTION INPUT ;
    USE SIGNAL ;
    PORT
      LAYER M4 ;
        RECT 0.000 814.848 0.192 814.872 ;
    END
  END x_wd[220]
  PIN x_wd[221]
    DIRECTION INPUT ;
    USE SIGNAL ;
    PORT
      LAYER M4 ;
        RECT 0.000 816.048 0.192 816.072 ;
    END
  END x_wd[221]
  PIN x_wd[222]
    DIRECTION INPUT ;
    USE SIGNAL ;
    PORT
      LAYER M4 ;
        RECT 0.000 817.248 0.192 817.272 ;
    END
  END x_wd[222]
  PIN x_wd[223]
    DIRECTION INPUT ;
    USE SIGNAL ;
    PORT
      LAYER M4 ;
        RECT 0.000 818.448 0.192 818.472 ;
    END
  END x_wd[223]
  PIN x_wd[224]
    DIRECTION INPUT ;
    USE SIGNAL ;
    PORT
      LAYER M4 ;
        RECT 0.000 819.648 0.192 819.672 ;
    END
  END x_wd[224]
  PIN x_wd[225]
    DIRECTION INPUT ;
    USE SIGNAL ;
    PORT
      LAYER M4 ;
        RECT 0.000 820.848 0.192 820.872 ;
    END
  END x_wd[225]
  PIN x_wd[226]
    DIRECTION INPUT ;
    USE SIGNAL ;
    PORT
      LAYER M4 ;
        RECT 0.000 822.096 0.192 822.120 ;
    END
  END x_wd[226]
  PIN x_wd[227]
    DIRECTION INPUT ;
    USE SIGNAL ;
    PORT
      LAYER M4 ;
        RECT 0.000 823.296 0.192 823.320 ;
    END
  END x_wd[227]
  PIN x_wd[228]
    DIRECTION INPUT ;
    USE SIGNAL ;
    PORT
      LAYER M4 ;
        RECT 0.000 824.496 0.192 824.520 ;
    END
  END x_wd[228]
  PIN x_wd[229]
    DIRECTION INPUT ;
    USE SIGNAL ;
    PORT
      LAYER M4 ;
        RECT 0.000 825.696 0.192 825.720 ;
    END
  END x_wd[229]
  PIN x_wd[230]
    DIRECTION INPUT ;
    USE SIGNAL ;
    PORT
      LAYER M4 ;
        RECT 0.000 826.896 0.192 826.920 ;
    END
  END x_wd[230]
  PIN x_wd[231]
    DIRECTION INPUT ;
    USE SIGNAL ;
    PORT
      LAYER M4 ;
        RECT 0.000 828.096 0.192 828.120 ;
    END
  END x_wd[231]
  PIN x_wd[232]
    DIRECTION INPUT ;
    USE SIGNAL ;
    PORT
      LAYER M4 ;
        RECT 0.000 829.296 0.192 829.320 ;
    END
  END x_wd[232]
  PIN x_wd[233]
    DIRECTION INPUT ;
    USE SIGNAL ;
    PORT
      LAYER M4 ;
        RECT 0.000 830.496 0.192 830.520 ;
    END
  END x_wd[233]
  PIN x_wd[234]
    DIRECTION INPUT ;
    USE SIGNAL ;
    PORT
      LAYER M4 ;
        RECT 0.000 831.696 0.192 831.720 ;
    END
  END x_wd[234]
  PIN x_wd[235]
    DIRECTION INPUT ;
    USE SIGNAL ;
    PORT
      LAYER M4 ;
        RECT 0.000 832.896 0.192 832.920 ;
    END
  END x_wd[235]
  PIN x_wd[236]
    DIRECTION INPUT ;
    USE SIGNAL ;
    PORT
      LAYER M4 ;
        RECT 0.000 834.096 0.192 834.120 ;
    END
  END x_wd[236]
  PIN x_wd[237]
    DIRECTION INPUT ;
    USE SIGNAL ;
    PORT
      LAYER M4 ;
        RECT 0.000 835.296 0.192 835.320 ;
    END
  END x_wd[237]
  PIN x_wd[238]
    DIRECTION INPUT ;
    USE SIGNAL ;
    PORT
      LAYER M4 ;
        RECT 0.000 836.496 0.192 836.520 ;
    END
  END x_wd[238]
  PIN x_wd[239]
    DIRECTION INPUT ;
    USE SIGNAL ;
    PORT
      LAYER M4 ;
        RECT 0.000 837.696 0.192 837.720 ;
    END
  END x_wd[239]
  PIN x_wd[240]
    DIRECTION INPUT ;
    USE SIGNAL ;
    PORT
      LAYER M4 ;
        RECT 0.000 838.896 0.192 838.920 ;
    END
  END x_wd[240]
  PIN x_wd[241]
    DIRECTION INPUT ;
    USE SIGNAL ;
    PORT
      LAYER M4 ;
        RECT 0.000 840.096 0.192 840.120 ;
    END
  END x_wd[241]
  PIN x_wd[242]
    DIRECTION INPUT ;
    USE SIGNAL ;
    PORT
      LAYER M4 ;
        RECT 0.000 841.296 0.192 841.320 ;
    END
  END x_wd[242]
  PIN x_wd[243]
    DIRECTION INPUT ;
    USE SIGNAL ;
    PORT
      LAYER M4 ;
        RECT 0.000 842.496 0.192 842.520 ;
    END
  END x_wd[243]
  PIN x_wd[244]
    DIRECTION INPUT ;
    USE SIGNAL ;
    PORT
      LAYER M4 ;
        RECT 0.000 843.696 0.192 843.720 ;
    END
  END x_wd[244]
  PIN x_wd[245]
    DIRECTION INPUT ;
    USE SIGNAL ;
    PORT
      LAYER M4 ;
        RECT 0.000 844.896 0.192 844.920 ;
    END
  END x_wd[245]
  PIN x_wd[246]
    DIRECTION INPUT ;
    USE SIGNAL ;
    PORT
      LAYER M4 ;
        RECT 0.000 846.096 0.192 846.120 ;
    END
  END x_wd[246]
  PIN x_wd[247]
    DIRECTION INPUT ;
    USE SIGNAL ;
    PORT
      LAYER M4 ;
        RECT 0.000 847.296 0.192 847.320 ;
    END
  END x_wd[247]
  PIN x_wd[248]
    DIRECTION INPUT ;
    USE SIGNAL ;
    PORT
      LAYER M4 ;
        RECT 0.000 848.496 0.192 848.520 ;
    END
  END x_wd[248]
  PIN x_wd[249]
    DIRECTION INPUT ;
    USE SIGNAL ;
    PORT
      LAYER M4 ;
        RECT 0.000 849.696 0.192 849.720 ;
    END
  END x_wd[249]
  PIN x_wd[250]
    DIRECTION INPUT ;
    USE SIGNAL ;
    PORT
      LAYER M4 ;
        RECT 0.000 850.896 0.192 850.920 ;
    END
  END x_wd[250]
  PIN x_wd[251]
    DIRECTION INPUT ;
    USE SIGNAL ;
    PORT
      LAYER M4 ;
        RECT 0.000 852.096 0.192 852.120 ;
    END
  END x_wd[251]
  PIN x_wd[252]
    DIRECTION INPUT ;
    USE SIGNAL ;
    PORT
      LAYER M4 ;
        RECT 0.000 853.296 0.192 853.320 ;
    END
  END x_wd[252]
  PIN x_wd[253]
    DIRECTION INPUT ;
    USE SIGNAL ;
    PORT
      LAYER M4 ;
        RECT 0.000 854.496 0.192 854.520 ;
    END
  END x_wd[253]
  PIN x_wd[254]
    DIRECTION INPUT ;
    USE SIGNAL ;
    PORT
      LAYER M4 ;
        RECT 0.000 855.696 0.192 855.720 ;
    END
  END x_wd[254]
  PIN x_wd[255]
    DIRECTION INPUT ;
    USE SIGNAL ;
    PORT
      LAYER M4 ;
        RECT 0.000 856.896 0.192 856.920 ;
    END
  END x_wd[255]
  PIN VDD
    DIRECTION INOUT ;
    USE POWER ;
    PORT
      LAYER M5 ;
        RECT 2.460 0.500 2.580 863.500 ;
        RECT 7.860 0.500 7.980 863.500 ;
        RECT 13.260 0.500 13.380 863.500 ;
        RECT 18.660 0.500 18.780 863.500 ;
        RECT 24.060 0.500 24.180 863.500 ;
        RECT 29.460 0.500 29.580 863.500 ;
        RECT 34.860 0.500 34.980 863.500 ;
        RECT 40.260 0.500 40.380 863.500 ;
        RECT 45.660 0.500 45.780 863.500 ;
        RECT 51.060 0.500 51.180 863.500 ;
        RECT 56.460 0.500 56.580 863.500 ;
        RECT 61.860 0.500 61.980 863.500 ;
        RECT 67.260 0.500 67.380 863.500 ;
        RECT 72.660 0.500 72.780 863.500 ;
        RECT 78.060 0.500 78.180 863.500 ;
        RECT 83.460 0.500 83.580 863.500 ;
        RECT 88.860 0.500 88.980 863.500 ;
        RECT 94.260 0.500 94.380 863.500 ;
        RECT 99.660 0.500 99.780 863.500 ;
        RECT 105.060 0.500 105.180 863.500 ;
        RECT 110.460 0.500 110.580 863.500 ;
        RECT 115.860 0.500 115.980 863.500 ;
        RECT 121.260 0.500 121.380 863.500 ;
        RECT 126.660 0.500 126.780 863.500 ;
        RECT 132.060 0.500 132.180 863.500 ;
        RECT 137.460 0.500 137.580 863.500 ;
        RECT 142.860 0.500 142.980 863.500 ;
        RECT 148.260 0.500 148.380 863.500 ;
        RECT 153.660 0.500 153.780 863.500 ;
        RECT 159.060 0.500 159.180 863.500 ;
        RECT 164.460 0.500 164.580 863.500 ;
        RECT 169.860 0.500 169.980 863.500 ;
        RECT 175.260 0.500 175.380 863.500 ;
        RECT 180.660 0.500 180.780 863.500 ;
        RECT 186.060 0.500 186.180 863.500 ;
        RECT 191.460 0.500 191.580 863.500 ;
        RECT 196.860 0.500 196.980 863.500 ;
        RECT 202.260 0.500 202.380 863.500 ;
        RECT 207.660 0.500 207.780 863.500 ;
        RECT 213.060 0.500 213.180 863.500 ;
        RECT 218.460 0.500 218.580 863.500 ;
        RECT 223.860 0.500 223.980 863.500 ;
        RECT 229.260 0.500 229.380 863.500 ;
        RECT 234.660 0.500 234.780 863.500 ;
        RECT 240.060 0.500 240.180 863.500 ;
        RECT 245.460 0.500 245.580 863.500 ;
        RECT 250.860 0.500 250.980 863.500 ;
        RECT 256.260 0.500 256.380 863.500 ;
        RECT 261.660 0.500 261.780 863.500 ;
        RECT 267.060 0.500 267.180 863.500 ;
        RECT 272.460 0.500 272.580 863.500 ;
        RECT 277.860 0.500 277.980 863.500 ;
        RECT 283.260 0.500 283.380 863.500 ;
        RECT 288.660 0.500 288.780 863.500 ;
        RECT 294.060 0.500 294.180 863.500 ;
        RECT 299.460 0.500 299.580 863.500 ;
        RECT 304.860 0.500 304.980 863.500 ;
        RECT 310.260 0.500 310.380 863.500 ;
        RECT 315.660 0.500 315.780 863.500 ;
        RECT 321.060 0.500 321.180 863.500 ;
        RECT 326.460 0.500 326.580 863.500 ;
        RECT 331.860 0.500 331.980 863.500 ;
        RECT 337.260 0.500 337.380 863.500 ;
        RECT 342.660 0.500 342.780 863.500 ;
        RECT 348.060 0.500 348.180 863.500 ;
        RECT 353.460 0.500 353.580 863.500 ;
        RECT 358.860 0.500 358.980 863.500 ;
        RECT 364.260 0.500 364.380 863.500 ;
        RECT 369.660 0.500 369.780 863.500 ;
        RECT 375.060 0.500 375.180 863.500 ;
        RECT 380.460 0.500 380.580 863.500 ;
        RECT 385.860 0.500 385.980 863.500 ;
        RECT 391.260 0.500 391.380 863.500 ;
        RECT 396.660 0.500 396.780 863.500 ;
        RECT 402.060 0.500 402.180 863.500 ;
        RECT 407.460 0.500 407.580 863.500 ;
        RECT 412.860 0.500 412.980 863.500 ;
        RECT 418.260 0.500 418.380 863.500 ;
        RECT 423.660 0.500 423.780 863.500 ;
        RECT 429.060 0.500 429.180 863.500 ;
        RECT 434.460 0.500 434.580 863.500 ;
        RECT 439.860 0.500 439.980 863.500 ;
        RECT 445.260 0.500 445.380 863.500 ;
        RECT 450.660 0.500 450.780 863.500 ;
        RECT 456.060 0.500 456.180 863.500 ;
        RECT 461.460 0.500 461.580 863.500 ;
        RECT 466.860 0.500 466.980 863.500 ;
        RECT 472.260 0.500 472.380 863.500 ;
        RECT 477.660 0.500 477.780 863.500 ;
        RECT 483.060 0.500 483.180 863.500 ;
        RECT 488.460 0.500 488.580 863.500 ;
        RECT 493.860 0.500 493.980 863.500 ;
        RECT 499.260 0.500 499.380 863.500 ;
        RECT 504.660 0.500 504.780 863.500 ;
        RECT 510.060 0.500 510.180 863.500 ;
        RECT 515.460 0.500 515.580 863.500 ;
        RECT 520.860 0.500 520.980 863.500 ;
        RECT 526.260 0.500 526.380 863.500 ;
        RECT 531.660 0.500 531.780 863.500 ;
        RECT 537.060 0.500 537.180 863.500 ;
        RECT 542.460 0.500 542.580 863.500 ;
        RECT 547.860 0.500 547.980 863.500 ;
        RECT 553.260 0.500 553.380 863.500 ;
        RECT 558.660 0.500 558.780 863.500 ;
        RECT 564.060 0.500 564.180 863.500 ;
        RECT 569.460 0.500 569.580 863.500 ;
        RECT 574.860 0.500 574.980 863.500 ;
        RECT 580.260 0.500 580.380 863.500 ;
        RECT 585.660 0.500 585.780 863.500 ;
        RECT 591.060 0.500 591.180 863.500 ;
        RECT 596.460 0.500 596.580 863.500 ;
        RECT 601.860 0.500 601.980 863.500 ;
        RECT 607.260 0.500 607.380 863.500 ;
        RECT 612.660 0.500 612.780 863.500 ;
        RECT 618.060 0.500 618.180 863.500 ;
        RECT 623.460 0.500 623.580 863.500 ;
        RECT 628.860 0.500 628.980 863.500 ;
        RECT 634.260 0.500 634.380 863.500 ;
        RECT 639.660 0.500 639.780 863.500 ;
        RECT 645.060 0.500 645.180 863.500 ;
        RECT 650.460 0.500 650.580 863.500 ;
        RECT 655.860 0.500 655.980 863.500 ;
        RECT 661.260 0.500 661.380 863.500 ;
        RECT 666.660 0.500 666.780 863.500 ;
        RECT 672.060 0.500 672.180 863.500 ;
        RECT 677.460 0.500 677.580 863.500 ;
        RECT 682.860 0.500 682.980 863.500 ;
        RECT 688.260 0.500 688.380 863.500 ;
        RECT 693.660 0.500 693.780 863.500 ;
        RECT 699.060 0.500 699.180 863.500 ;
        RECT 704.460 0.500 704.580 863.500 ;
        RECT 709.860 0.500 709.980 863.500 ;
        RECT 715.260 0.500 715.380 863.500 ;
        RECT 720.660 0.500 720.780 863.500 ;
        RECT 726.060 0.500 726.180 863.500 ;
        RECT 731.460 0.500 731.580 863.500 ;
    END
  END VDD
  PIN VSS
    DIRECTION INOUT ;
    USE GROUND ;
    PORT
      LAYER M5 ;
        RECT 2.652 0.500 2.772 863.500 ;
        RECT 8.052 0.500 8.172 863.500 ;
        RECT 13.452 0.500 13.572 863.500 ;
        RECT 18.852 0.500 18.972 863.500 ;
        RECT 24.252 0.500 24.372 863.500 ;
        RECT 29.652 0.500 29.772 863.500 ;
        RECT 35.052 0.500 35.172 863.500 ;
        RECT 40.452 0.500 40.572 863.500 ;
        RECT 45.852 0.500 45.972 863.500 ;
        RECT 51.252 0.500 51.372 863.500 ;
        RECT 56.652 0.500 56.772 863.500 ;
        RECT 62.052 0.500 62.172 863.500 ;
        RECT 67.452 0.500 67.572 863.500 ;
        RECT 72.852 0.500 72.972 863.500 ;
        RECT 78.252 0.500 78.372 863.500 ;
        RECT 83.652 0.500 83.772 863.500 ;
        RECT 89.052 0.500 89.172 863.500 ;
        RECT 94.452 0.500 94.572 863.500 ;
        RECT 99.852 0.500 99.972 863.500 ;
        RECT 105.252 0.500 105.372 863.500 ;
        RECT 110.652 0.500 110.772 863.500 ;
        RECT 116.052 0.500 116.172 863.500 ;
        RECT 121.452 0.500 121.572 863.500 ;
        RECT 126.852 0.500 126.972 863.500 ;
        RECT 132.252 0.500 132.372 863.500 ;
        RECT 137.652 0.500 137.772 863.500 ;
        RECT 143.052 0.500 143.172 863.500 ;
        RECT 148.452 0.500 148.572 863.500 ;
        RECT 153.852 0.500 153.972 863.500 ;
        RECT 159.252 0.500 159.372 863.500 ;
        RECT 164.652 0.500 164.772 863.500 ;
        RECT 170.052 0.500 170.172 863.500 ;
        RECT 175.452 0.500 175.572 863.500 ;
        RECT 180.852 0.500 180.972 863.500 ;
        RECT 186.252 0.500 186.372 863.500 ;
        RECT 191.652 0.500 191.772 863.500 ;
        RECT 197.052 0.500 197.172 863.500 ;
        RECT 202.452 0.500 202.572 863.500 ;
        RECT 207.852 0.500 207.972 863.500 ;
        RECT 213.252 0.500 213.372 863.500 ;
        RECT 218.652 0.500 218.772 863.500 ;
        RECT 224.052 0.500 224.172 863.500 ;
        RECT 229.452 0.500 229.572 863.500 ;
        RECT 234.852 0.500 234.972 863.500 ;
        RECT 240.252 0.500 240.372 863.500 ;
        RECT 245.652 0.500 245.772 863.500 ;
        RECT 251.052 0.500 251.172 863.500 ;
        RECT 256.452 0.500 256.572 863.500 ;
        RECT 261.852 0.500 261.972 863.500 ;
        RECT 267.252 0.500 267.372 863.500 ;
        RECT 272.652 0.500 272.772 863.500 ;
        RECT 278.052 0.500 278.172 863.500 ;
        RECT 283.452 0.500 283.572 863.500 ;
        RECT 288.852 0.500 288.972 863.500 ;
        RECT 294.252 0.500 294.372 863.500 ;
        RECT 299.652 0.500 299.772 863.500 ;
        RECT 305.052 0.500 305.172 863.500 ;
        RECT 310.452 0.500 310.572 863.500 ;
        RECT 315.852 0.500 315.972 863.500 ;
        RECT 321.252 0.500 321.372 863.500 ;
        RECT 326.652 0.500 326.772 863.500 ;
        RECT 332.052 0.500 332.172 863.500 ;
        RECT 337.452 0.500 337.572 863.500 ;
        RECT 342.852 0.500 342.972 863.500 ;
        RECT 348.252 0.500 348.372 863.500 ;
        RECT 353.652 0.500 353.772 863.500 ;
        RECT 359.052 0.500 359.172 863.500 ;
        RECT 364.452 0.500 364.572 863.500 ;
        RECT 369.852 0.500 369.972 863.500 ;
        RECT 375.252 0.500 375.372 863.500 ;
        RECT 380.652 0.500 380.772 863.500 ;
        RECT 386.052 0.500 386.172 863.500 ;
        RECT 391.452 0.500 391.572 863.500 ;
        RECT 396.852 0.500 396.972 863.500 ;
        RECT 402.252 0.500 402.372 863.500 ;
        RECT 407.652 0.500 407.772 863.500 ;
        RECT 413.052 0.500 413.172 863.500 ;
        RECT 418.452 0.500 418.572 863.500 ;
        RECT 423.852 0.500 423.972 863.500 ;
        RECT 429.252 0.500 429.372 863.500 ;
        RECT 434.652 0.500 434.772 863.500 ;
        RECT 440.052 0.500 440.172 863.500 ;
        RECT 445.452 0.500 445.572 863.500 ;
        RECT 450.852 0.500 450.972 863.500 ;
        RECT 456.252 0.500 456.372 863.500 ;
        RECT 461.652 0.500 461.772 863.500 ;
        RECT 467.052 0.500 467.172 863.500 ;
        RECT 472.452 0.500 472.572 863.500 ;
        RECT 477.852 0.500 477.972 863.500 ;
        RECT 483.252 0.500 483.372 863.500 ;
        RECT 488.652 0.500 488.772 863.500 ;
        RECT 494.052 0.500 494.172 863.500 ;
        RECT 499.452 0.500 499.572 863.500 ;
        RECT 504.852 0.500 504.972 863.500 ;
        RECT 510.252 0.500 510.372 863.500 ;
        RECT 515.652 0.500 515.772 863.500 ;
        RECT 521.052 0.500 521.172 863.500 ;
        RECT 526.452 0.500 526.572 863.500 ;
        RECT 531.852 0.500 531.972 863.500 ;
        RECT 537.252 0.500 537.372 863.500 ;
        RECT 542.652 0.500 542.772 863.500 ;
        RECT 548.052 0.500 548.172 863.500 ;
        RECT 553.452 0.500 553.572 863.500 ;
        RECT 558.852 0.500 558.972 863.500 ;
        RECT 564.252 0.500 564.372 863.500 ;
        RECT 569.652 0.500 569.772 863.500 ;
        RECT 575.052 0.500 575.172 863.500 ;
        RECT 580.452 0.500 580.572 863.500 ;
        RECT 585.852 0.500 585.972 863.500 ;
        RECT 591.252 0.500 591.372 863.500 ;
        RECT 596.652 0.500 596.772 863.500 ;
        RECT 602.052 0.500 602.172 863.500 ;
        RECT 607.452 0.500 607.572 863.500 ;
        RECT 612.852 0.500 612.972 863.500 ;
        RECT 618.252 0.500 618.372 863.500 ;
        RECT 623.652 0.500 623.772 863.500 ;
        RECT 629.052 0.500 629.172 863.500 ;
        RECT 634.452 0.500 634.572 863.500 ;
        RECT 639.852 0.500 639.972 863.500 ;
        RECT 645.252 0.500 645.372 863.500 ;
        RECT 650.652 0.500 650.772 863.500 ;
        RECT 656.052 0.500 656.172 863.500 ;
        RECT 661.452 0.500 661.572 863.500 ;
        RECT 666.852 0.500 666.972 863.500 ;
        RECT 672.252 0.500 672.372 863.500 ;
        RECT 677.652 0.500 677.772 863.500 ;
        RECT 683.052 0.500 683.172 863.500 ;
        RECT 688.452 0.500 688.572 863.500 ;
        RECT 693.852 0.500 693.972 863.500 ;
        RECT 699.252 0.500 699.372 863.500 ;
        RECT 704.652 0.500 704.772 863.500 ;
        RECT 710.052 0.500 710.172 863.500 ;
        RECT 715.452 0.500 715.572 863.500 ;
        RECT 720.852 0.500 720.972 863.500 ;
        RECT 726.252 0.500 726.372 863.500 ;
        RECT 731.652 0.500 731.772 863.500 ;
    END
  END VSS
  OBS
    LAYER M1 ;
      RECT 0.500 0.500 733.900 863.500 ;
    LAYER M2 ;
      RECT 0.500 0.500 733.900 863.500 ;
    LAYER M3 ;
      RECT 10.800 0.500 723.600 853.200 ;
    LAYER M4 ;
      RECT 10.800 0.500 723.600 853.200 ;
    LAYER M5 ;
      RECT 10.800 0.900 13.260 853.200 ;
      RECT 13.380 0.900 13.452 853.200 ;
      RECT 13.572 0.900 18.660 853.200 ;
      RECT 18.780 0.900 18.852 853.200 ;
      RECT 18.972 0.900 24.060 853.200 ;
      RECT 24.180 0.900 24.252 853.200 ;
      RECT 24.372 0.900 29.460 853.200 ;
      RECT 29.580 0.900 29.652 853.200 ;
      RECT 29.772 0.900 34.860 853.200 ;
      RECT 34.980 0.900 35.052 853.200 ;
      RECT 35.172 0.900 40.260 853.200 ;
      RECT 40.380 0.900 40.452 853.200 ;
      RECT 40.572 0.900 45.660 853.200 ;
      RECT 45.780 0.900 45.852 853.200 ;
      RECT 45.972 0.900 51.060 853.200 ;
      RECT 51.180 0.900 51.252 853.200 ;
      RECT 51.372 0.900 56.460 853.200 ;
      RECT 56.580 0.900 56.652 853.200 ;
      RECT 56.772 0.900 61.860 853.200 ;
      RECT 61.980 0.900 62.052 853.200 ;
      RECT 62.172 0.900 67.260 853.200 ;
      RECT 67.380 0.900 67.452 853.200 ;
      RECT 67.572 0.900 72.660 853.200 ;
      RECT 72.780 0.900 72.852 853.200 ;
      RECT 72.972 0.900 78.060 853.200 ;
      RECT 78.180 0.900 78.252 853.200 ;
      RECT 78.372 0.900 83.460 853.200 ;
      RECT 83.580 0.900 83.652 853.200 ;
      RECT 83.772 0.900 88.860 853.200 ;
      RECT 88.980 0.900 89.052 853.200 ;
      RECT 89.172 0.900 94.260 853.200 ;
      RECT 94.380 0.900 94.452 853.200 ;
      RECT 94.572 0.900 99.660 853.200 ;
      RECT 99.780 0.900 99.852 853.200 ;
      RECT 99.972 0.900 105.060 853.200 ;
      RECT 105.180 0.900 105.252 853.200 ;
      RECT 105.372 0.900 110.460 853.200 ;
      RECT 110.580 0.900 110.652 853.200 ;
      RECT 110.772 0.900 115.860 853.200 ;
      RECT 115.980 0.900 116.052 853.200 ;
      RECT 116.172 0.900 121.260 853.200 ;
      RECT 121.380 0.900 121.452 853.200 ;
      RECT 121.572 0.900 126.660 853.200 ;
      RECT 126.780 0.900 126.852 853.200 ;
      RECT 126.972 0.900 132.060 853.200 ;
      RECT 132.180 0.900 132.252 853.200 ;
      RECT 132.372 0.900 137.460 853.200 ;
      RECT 137.580 0.900 137.652 853.200 ;
      RECT 137.772 0.900 142.860 853.200 ;
      RECT 142.980 0.900 143.052 853.200 ;
      RECT 143.172 0.900 148.260 853.200 ;
      RECT 148.380 0.900 148.452 853.200 ;
      RECT 148.572 0.900 153.660 853.200 ;
      RECT 153.780 0.900 153.852 853.200 ;
      RECT 153.972 0.900 159.060 853.200 ;
      RECT 159.180 0.900 159.252 853.200 ;
      RECT 159.372 0.900 164.460 853.200 ;
      RECT 164.580 0.900 164.652 853.200 ;
      RECT 164.772 0.900 169.860 853.200 ;
      RECT 169.980 0.900 170.052 853.200 ;
      RECT 170.172 0.900 175.260 853.200 ;
      RECT 175.380 0.900 175.452 853.200 ;
      RECT 175.572 0.900 180.660 853.200 ;
      RECT 180.780 0.900 180.852 853.200 ;
      RECT 180.972 0.900 186.060 853.200 ;
      RECT 186.180 0.900 186.252 853.200 ;
      RECT 186.372 0.900 191.460 853.200 ;
      RECT 191.580 0.900 191.652 853.200 ;
      RECT 191.772 0.900 196.860 853.200 ;
      RECT 196.980 0.900 197.052 853.200 ;
      RECT 197.172 0.900 202.260 853.200 ;
      RECT 202.380 0.900 202.452 853.200 ;
      RECT 202.572 0.900 207.660 853.200 ;
      RECT 207.780 0.900 207.852 853.200 ;
      RECT 207.972 0.900 213.060 853.200 ;
      RECT 213.180 0.900 213.252 853.200 ;
      RECT 213.372 0.900 218.460 853.200 ;
      RECT 218.580 0.900 218.652 853.200 ;
      RECT 218.772 0.900 223.860 853.200 ;
      RECT 223.980 0.900 224.052 853.200 ;
      RECT 224.172 0.900 229.260 853.200 ;
      RECT 229.380 0.900 229.452 853.200 ;
      RECT 229.572 0.900 234.660 853.200 ;
      RECT 234.780 0.900 234.852 853.200 ;
      RECT 234.972 0.900 240.060 853.200 ;
      RECT 240.180 0.900 240.252 853.200 ;
      RECT 240.372 0.900 245.460 853.200 ;
      RECT 245.580 0.900 245.652 853.200 ;
      RECT 245.772 0.900 250.860 853.200 ;
      RECT 250.980 0.900 251.052 853.200 ;
      RECT 251.172 0.900 256.260 853.200 ;
      RECT 256.380 0.900 256.452 853.200 ;
      RECT 256.572 0.900 261.660 853.200 ;
      RECT 261.780 0.900 261.852 853.200 ;
      RECT 261.972 0.900 267.060 853.200 ;
      RECT 267.180 0.900 267.252 853.200 ;
      RECT 267.372 0.900 272.460 853.200 ;
      RECT 272.580 0.900 272.652 853.200 ;
      RECT 272.772 0.900 277.860 853.200 ;
      RECT 277.980 0.900 278.052 853.200 ;
      RECT 278.172 0.900 283.260 853.200 ;
      RECT 283.380 0.900 283.452 853.200 ;
      RECT 283.572 0.900 288.660 853.200 ;
      RECT 288.780 0.900 288.852 853.200 ;
      RECT 288.972 0.900 294.060 853.200 ;
      RECT 294.180 0.900 294.252 853.200 ;
      RECT 294.372 0.900 299.460 853.200 ;
      RECT 299.580 0.900 299.652 853.200 ;
      RECT 299.772 0.900 304.860 853.200 ;
      RECT 304.980 0.900 305.052 853.200 ;
      RECT 305.172 0.900 310.260 853.200 ;
      RECT 310.380 0.900 310.452 853.200 ;
      RECT 310.572 0.900 315.660 853.200 ;
      RECT 315.780 0.900 315.852 853.200 ;
      RECT 315.972 0.900 321.060 853.200 ;
      RECT 321.180 0.900 321.252 853.200 ;
      RECT 321.372 0.900 326.460 853.200 ;
      RECT 326.580 0.900 326.652 853.200 ;
      RECT 326.772 0.900 331.860 853.200 ;
      RECT 331.980 0.900 332.052 853.200 ;
      RECT 332.172 0.900 337.260 853.200 ;
      RECT 337.380 0.900 337.452 853.200 ;
      RECT 337.572 0.900 342.660 853.200 ;
      RECT 342.780 0.900 342.852 853.200 ;
      RECT 342.972 0.900 348.060 853.200 ;
      RECT 348.180 0.900 348.252 853.200 ;
      RECT 348.372 0.900 353.460 853.200 ;
      RECT 353.580 0.900 353.652 853.200 ;
      RECT 353.772 0.900 358.860 853.200 ;
      RECT 358.980 0.900 359.052 853.200 ;
      RECT 359.172 0.900 364.260 853.200 ;
      RECT 364.380 0.900 364.452 853.200 ;
      RECT 364.572 0.900 369.660 853.200 ;
      RECT 369.780 0.900 369.852 853.200 ;
      RECT 369.972 0.900 375.060 853.200 ;
      RECT 375.180 0.900 375.252 853.200 ;
      RECT 375.372 0.900 380.460 853.200 ;
      RECT 380.580 0.900 380.652 853.200 ;
      RECT 380.772 0.900 385.860 853.200 ;
      RECT 385.980 0.900 386.052 853.200 ;
      RECT 386.172 0.900 391.260 853.200 ;
      RECT 391.380 0.900 391.452 853.200 ;
      RECT 391.572 0.900 396.660 853.200 ;
      RECT 396.780 0.900 396.852 853.200 ;
      RECT 396.972 0.900 402.060 853.200 ;
      RECT 402.180 0.900 402.252 853.200 ;
      RECT 402.372 0.900 407.460 853.200 ;
      RECT 407.580 0.900 407.652 853.200 ;
      RECT 407.772 0.900 412.860 853.200 ;
      RECT 412.980 0.900 413.052 853.200 ;
      RECT 413.172 0.900 418.260 853.200 ;
      RECT 418.380 0.900 418.452 853.200 ;
      RECT 418.572 0.900 423.660 853.200 ;
      RECT 423.780 0.900 423.852 853.200 ;
      RECT 423.972 0.900 429.060 853.200 ;
      RECT 429.180 0.900 429.252 853.200 ;
      RECT 429.372 0.900 434.460 853.200 ;
      RECT 434.580 0.900 434.652 853.200 ;
      RECT 434.772 0.900 439.860 853.200 ;
      RECT 439.980 0.900 440.052 853.200 ;
      RECT 440.172 0.900 445.260 853.200 ;
      RECT 445.380 0.900 445.452 853.200 ;
      RECT 445.572 0.900 450.660 853.200 ;
      RECT 450.780 0.900 450.852 853.200 ;
      RECT 450.972 0.900 456.060 853.200 ;
      RECT 456.180 0.900 456.252 853.200 ;
      RECT 456.372 0.900 461.460 853.200 ;
      RECT 461.580 0.900 461.652 853.200 ;
      RECT 461.772 0.900 466.860 853.200 ;
      RECT 466.980 0.900 467.052 853.200 ;
      RECT 467.172 0.900 472.260 853.200 ;
      RECT 472.380 0.900 472.452 853.200 ;
      RECT 472.572 0.900 477.660 853.200 ;
      RECT 477.780 0.900 477.852 853.200 ;
      RECT 477.972 0.900 483.060 853.200 ;
      RECT 483.180 0.900 483.252 853.200 ;
      RECT 483.372 0.900 488.460 853.200 ;
      RECT 488.580 0.900 488.652 853.200 ;
      RECT 488.772 0.900 493.860 853.200 ;
      RECT 493.980 0.900 494.052 853.200 ;
      RECT 494.172 0.900 499.260 853.200 ;
      RECT 499.380 0.900 499.452 853.200 ;
      RECT 499.572 0.900 504.660 853.200 ;
      RECT 504.780 0.900 504.852 853.200 ;
      RECT 504.972 0.900 510.060 853.200 ;
      RECT 510.180 0.900 510.252 853.200 ;
      RECT 510.372 0.900 515.460 853.200 ;
      RECT 515.580 0.900 515.652 853.200 ;
      RECT 515.772 0.900 520.860 853.200 ;
      RECT 520.980 0.900 521.052 853.200 ;
      RECT 521.172 0.900 526.260 853.200 ;
      RECT 526.380 0.900 526.452 853.200 ;
      RECT 526.572 0.900 531.660 853.200 ;
      RECT 531.780 0.900 531.852 853.200 ;
      RECT 531.972 0.900 537.060 853.200 ;
      RECT 537.180 0.900 537.252 853.200 ;
      RECT 537.372 0.900 542.460 853.200 ;
      RECT 542.580 0.900 542.652 853.200 ;
      RECT 542.772 0.900 547.860 853.200 ;
      RECT 547.980 0.900 548.052 853.200 ;
      RECT 548.172 0.900 553.260 853.200 ;
      RECT 553.380 0.900 553.452 853.200 ;
      RECT 553.572 0.900 558.660 853.200 ;
      RECT 558.780 0.900 558.852 853.200 ;
      RECT 558.972 0.900 564.060 853.200 ;
      RECT 564.180 0.900 564.252 853.200 ;
      RECT 564.372 0.900 569.460 853.200 ;
      RECT 569.580 0.900 569.652 853.200 ;
      RECT 569.772 0.900 574.860 853.200 ;
      RECT 574.980 0.900 575.052 853.200 ;
      RECT 575.172 0.900 580.260 853.200 ;
      RECT 580.380 0.900 580.452 853.200 ;
      RECT 580.572 0.900 585.660 853.200 ;
      RECT 585.780 0.900 585.852 853.200 ;
      RECT 585.972 0.900 591.060 853.200 ;
      RECT 591.180 0.900 591.252 853.200 ;
      RECT 591.372 0.900 596.460 853.200 ;
      RECT 596.580 0.900 596.652 853.200 ;
      RECT 596.772 0.900 601.860 853.200 ;
      RECT 601.980 0.900 602.052 853.200 ;
      RECT 602.172 0.900 607.260 853.200 ;
      RECT 607.380 0.900 607.452 853.200 ;
      RECT 607.572 0.900 612.660 853.200 ;
      RECT 612.780 0.900 612.852 853.200 ;
      RECT 612.972 0.900 618.060 853.200 ;
      RECT 618.180 0.900 618.252 853.200 ;
      RECT 618.372 0.900 623.460 853.200 ;
      RECT 623.580 0.900 623.652 853.200 ;
      RECT 623.772 0.900 628.860 853.200 ;
      RECT 628.980 0.900 629.052 853.200 ;
      RECT 629.172 0.900 634.260 853.200 ;
      RECT 634.380 0.900 634.452 853.200 ;
      RECT 634.572 0.900 639.660 853.200 ;
      RECT 639.780 0.900 639.852 853.200 ;
      RECT 639.972 0.900 645.060 853.200 ;
      RECT 645.180 0.900 645.252 853.200 ;
      RECT 645.372 0.900 650.460 853.200 ;
      RECT 650.580 0.900 650.652 853.200 ;
      RECT 650.772 0.900 655.860 853.200 ;
      RECT 655.980 0.900 656.052 853.200 ;
      RECT 656.172 0.900 661.260 853.200 ;
      RECT 661.380 0.900 661.452 853.200 ;
      RECT 661.572 0.900 666.660 853.200 ;
      RECT 666.780 0.900 666.852 853.200 ;
      RECT 666.972 0.900 672.060 853.200 ;
      RECT 672.180 0.900 672.252 853.200 ;
      RECT 672.372 0.900 677.460 853.200 ;
      RECT 677.580 0.900 677.652 853.200 ;
      RECT 677.772 0.900 682.860 853.200 ;
      RECT 682.980 0.900 683.052 853.200 ;
      RECT 683.172 0.900 688.260 853.200 ;
      RECT 688.380 0.900 688.452 853.200 ;
      RECT 688.572 0.900 693.660 853.200 ;
      RECT 693.780 0.900 693.852 853.200 ;
      RECT 693.972 0.900 699.060 853.200 ;
      RECT 699.180 0.900 699.252 853.200 ;
      RECT 699.372 0.900 704.460 853.200 ;
      RECT 704.580 0.900 704.652 853.200 ;
      RECT 704.772 0.900 709.860 853.200 ;
      RECT 709.980 0.900 710.052 853.200 ;
      RECT 710.172 0.900 715.260 853.200 ;
      RECT 715.380 0.900 715.452 853.200 ;
      RECT 715.572 0.900 720.660 853.200 ;
      RECT 720.780 0.900 720.852 853.200 ;
      RECT 720.972 0.900 723.600 853.200 ;
  END
END ot_s81sl_vp
END LIBRARY
